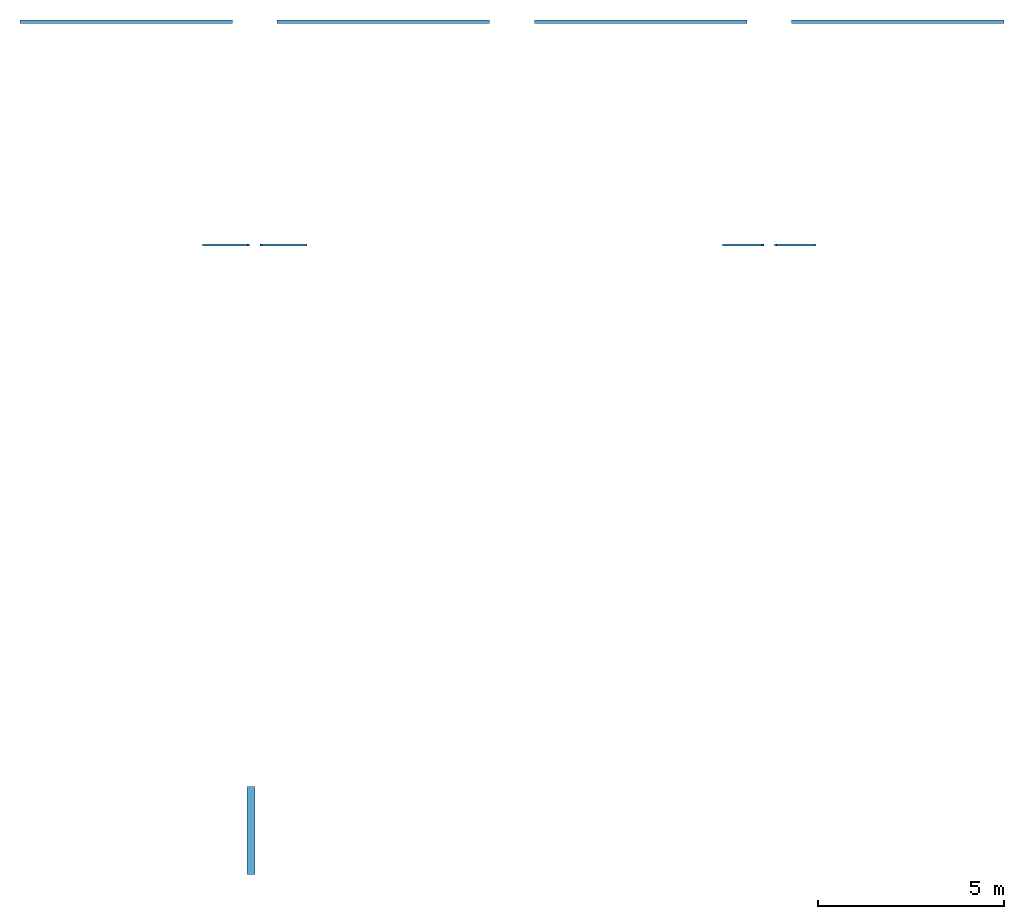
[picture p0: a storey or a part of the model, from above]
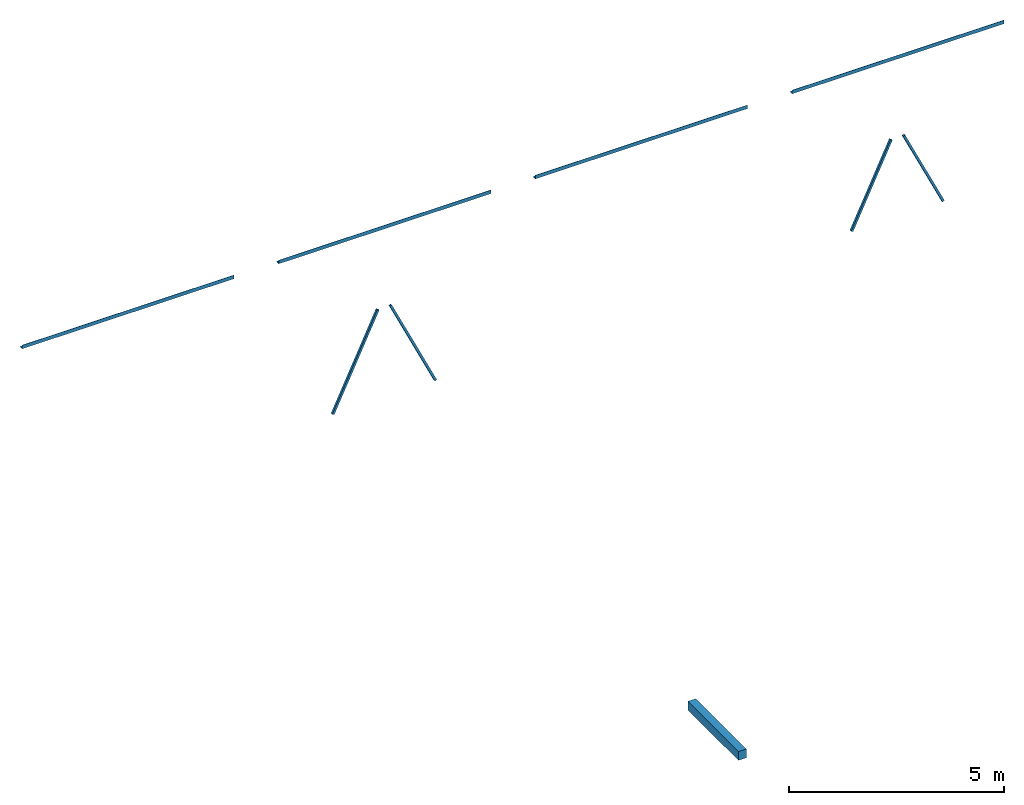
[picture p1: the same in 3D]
Properties of the parts of a building model (IFC2X3), part 1 of 6

# File
Description: ViewDefinition [CoordinationView_V2.0, QuantityTakeOffAddOnView], RevitIdentifiers [VersionGUID: f37ad820-e8d5-4bf8-b316-20b20cab6d81, NumberOfSaves: 258], CoordinateReference [CoordinateBase: Shared Coordinates, ProjectSite: Internal]
File name: 2023.123
Time: 2025-10-08T10:38:46+01:00
Written by: ODA SDAI 22.12
Made in: Autodesk Revit 23.1.60.36 (ENU) - IFC 23.3.0.0

# IfcProject, 2023.123
LongName: n.v.t.

# IfcSite, Default
RefLatitude: 42, 21, 29, 879999; RefLongitude: -71, -3, -37, -79999; RefElevation: 0 mm
Other - Category: Project Information; Client Name: Stichting Spaarnesant; Extensions.Parameters: n.v.t.; Project Address: IKC de zonnewijzer Planetenlaan 9 te Haarlem; Project Issue Date: n.v.t.; Project Name: n.v.t.; Project Number: 2023.123
Text - TemplateVersie: bt_revit_template.rte : 13-10-2023 R2016 ©RB

# IfcBuilding
Pset_BuildingCommon - NumberOfStoreys: 8
Other - Category: Project Information; Client Name: Stichting Spaarnesant; Extensions.Parameters: n.v.t.; Project Address: IKC de zonnewijzer Planetenlaan 9 te Haarlem; Project Issue Date: n.v.t.; Project Name: n.v.t.; Project Number: 2023.123
Text - TemplateVersie: bt_revit_template.rte : 13-10-2023 R2016 ©RB

# IfcBuildingStorey: Level:bt level - maat boven + naam onder (9)
Pset_AirSideSystemInformation - sets with these values: 2
Other - Category: Levels; Family: Level; Family and Type: Level: bt level - maat boven + naam onder; Type: bt level - maat boven + naam onder; Type Id: 551066
Dimensions - Computation Height: 0 mm
Identity Data - Building Story: yes; Structural: no
Other(Type) - Category: Levels; Family Name: Level
Constraints(Type) - Elevation Base: Project Base Point
Graphics(Type) - Color: 16711680; Line Pattern: bt_hoogtelijn; Line Weight: 1; Symbol: bt_hoogtelijnen : Hoogtemaat_Boven + Nivonaam_Onder; Symbol at End 1 Default: no; Symbol at End 2 Default: yes
Identity Data(Type) - Type Name: bt level - maat boven + naam onder
Name | LongName = Pset_AirSideSystemInformation, Name = Identity Data, Name | Elevation (mm) = Constraints, Elevation (mm)
KDV bk ruwe vloer | KDV bk ruwe vloer | -350
F1 begg (bk ruwe vloer) | F1 begg (bk ruwe vloer) | -70
KDV V1 1e verd. (bk ruwe vloer) | KDV V1 1e verd. (bk ruwe vloer) | 2550
V1 1e verd. (bk ruwe vloer) | V1 1e verd. (bk ruwe vloer) | 3730
KDV V2 werkbalken | KDV V2 werkbalken | 5000
V2 2e verd. (bk ruwe vloer) | V2 2e verd. (bk ruwe vloer) | 7530
KDV nok | KDV nok | 9310
V3 dakvloer | V3 dakvloer | 10840
V4 BK metselwerk | V4 BK metselwerk | 11700

# IfcBeam: btl_ihwg - RB 1x afschuining:b300/o200 x 500 (10)
In: F1 begg (bk ruwe vloer)
Type - Other - Category: Structural Framing; Family Name: btl_ihwg - RB 1x afschuining
Type - Dimensions - b boven: 300 mm; b onder: 200 mm; h: 500 mm
Type - Identity Data - Description: vorstrand 300/200 x 500; Model: betonbalk; OmniClass Number: 23.25.30.11.14.14; OmniClass Title: Beams; Type Name: b300/o200 x 500
Type - Materials and Finishes - Structural Material: Concrete - Cast-in-Place - C20/25
Type - Structural - Section Shape: 0
Type - Pset_BeamCommon - IsExternal: no; LoadBearing: yes
Type - Pset_ReinforcementBarPitchOfBeam - Description: vorstrand 300/200 x 500
Material: Concrete - Cast-in-Place - C20/25
BaseQuantities - CrossSectionArea: 125000 mm2
Pset_BeamCommon - Reference: b300/o200 x 500
Pset_QuantityTakeOff - Reference: b300/o200 x 500; sets with these values: 2
Other - Family: btl_ihwg - RB 1x afschuining; Family and Type: btl_ihwg - RB 1x afschuining: b300/o200 x 500; Type: b300/o200 x 500; Type Id: 2097147
Constraints - Cross-Section Rotation: 0 deg; Reference Level: F2 (bk fundering); Reference Level Elevation: -480 mm; Start Level Offset: -200 mm
Identity Data - Has Association: no
Phasing - Phase Created: 2. nieuwbouw
Structural - Rebar Cover - Other Faces: Rebar Cover 1 <25 mm>; Structural Usage: Other
Geometric Position - Join Status: Both joins enabled; y Offset Value: 0 mm; yz Justification: Uniform; z Justification: Top; z Offset Value: 0 mm; y Justification: Center
Name (btl_ihwg - RB 1x afschuining:b300/o200 x 500:...) | BaseQuantities, Length (mm) = Cut Length (mm) | OuterSurfaceArea (mm2) | GrossVolume (m3) | NetVolume (m3) = Volume (m3) | Slope (deg) | Span (mm) = Dimensions, Length (mm) | End Level Offset (mm) | Elevation at Bottom (mm) | Elevation at Top (mm) | Rebar Cover - Bottom Face
2097079 | 3950 | 5964113 | 0.49375 | 0.487917 | 0 | 3650 | -200 | -1180 | -680 | Rebar Cover 1 <25 mm>
2097230 | 1110 | 1675991 | 0.13875 | 0.132083 | 0 | 1160 | -200 | -1180 | -680 | Rebar Cover 1 <25 mm> | Structural - Rebar Cover - Top Face: Rebar Cover 1 <25 mm>
2097357 | 4840 | 7307925 | 0.605 | 0.589157 | 0 | 4840 | -200 | -1180 | -680 | Rebar Cover 1 <25 mm>
2097418 | 3151.69 | 4758749 | 0.393962 | 0.371541 | 0.194885 | 2939.98 | -210
2100637 | 4580 | 6915346 | 0.5725 | 0.5725 | 0 | 4430 | -200 | -1180 | -680 | Rebar Cover 1 <25 mm>
2101210 | 3530 | 5329954 | 0.44125 | 0.42875 | 0 | 3430 | -200 | -1180 | -680 | Rebar Cover 1 <25 mm>
2101342 | 1100 | 1660892 | 0.1375 | 0.1375 | 0 | 1100 | -200 | -1180 | -680 | Rebar Cover 1 <25 mm>
2101343 | 1620 | 2446041 | 0.2025 | 0.19 | 0 | 1520 | -200 | -1180 | -680 | Rebar Cover 1 <25 mm>
2101417 | 5145 | 7768446 | 0.643125 | 0.643125 | 0 | 5145 | -200 | -1180 | -680 | Rebar Cover 1 <25 mm>
2101418 | 950 | 1434407 | 0.11875 | 0.112083 | 0 | 1000 | -200 | -1180 | -680 | Rebar Cover 1 <25 mm>

# IfcBeam: btl_ihwg - RBeam:120x500 (8)
In: F1 begg (bk ruwe vloer)
Type - Other - Category: Structural Framing; Family Name: btl_ihwg - RBeam
Type - Dimensions - b: 120 mm; h: 500 mm
Type - Identity Data - Description: aanstort 120x500; OmniClass Number: 23.25.30.11.14.14; OmniClass Title: Beams; Type Name: 120x500
Type - Materials and Finishes - Structural Material: Concrete - Cast-in-Place - C30/37
Type - Structural - Section Shape: 0
Type - Pset_BeamCommon - IsExternal: no; LoadBearing: yes
Type - Pset_ReinforcementBarPitchOfBeam - Description: aanstort 120x500
Material: Concrete - Cast-in-Place - C30/37
BaseQuantities - CrossSectionArea: 60000 mm2
Pset_BeamCommon - Reference: 120x500
Pset_QuantityTakeOff - Reference: 120x500; sets with these values: 2
Other - Family: btl_ihwg - RBeam; Family and Type: btl_ihwg - RBeam: 120x500; Type: 120x500; Type Id: 2097461
Constraints - Cross-Section Rotation: 0 deg; Reference Level: F2 (bk fundering); Reference Level Elevation: -480 mm; Start Level Offset: -200 mm
Identity Data - Has Association: no
Phasing - Phase Created: 2. nieuwbouw
Structural - Rebar Cover - Other Faces: Rebar Cover 1 <25 mm>; Structural Usage: Other
Geometric Position - Join Status: Both joins enabled; y Offset Value: 0 mm; yz Justification: Uniform; z Justification: Top; z Offset Value: 0 mm; y Justification: Center
Name (btl_ihwg - RBeam:120x500:...) | BaseQuantities, Length (mm) = Cut Length (mm) | OuterSurfaceArea (mm2) | GrossVolume (m3) | NetVolume (m3) = Volume (m3) | Slope (deg) | Span (mm) = Dimensions, Length (mm) | End Level Offset (mm) | Elevation at Bottom (mm) | Elevation at Top (mm) | Rebar Cover - Bottom Face = Rebar Cover - Top Face
2097488 | 6720 | 8332800 | 0.4032 | 0.4032 | 0 | 6660 | -200 | -1180 | -680 | Rebar Cover 1 <25 mm>
2097557 | 5573 | 6910515 | 0.33438 | 0.33438 | 0 | 5573 | -200 | -1180 | -680 | Rebar Cover 1 <25 mm>
2097679 | 300.037 | 372046 | 0.0180022 | 0.0144022 | 0 | 300.037 | -200 | -1180 | -680 | Rebar Cover 1 <25 mm>
2098565 | 590.687 | 732452 | 0.0354412 | 0.0220276 | 1.56079 | 367.141 | -210
2101480 | 5633 | 6984915 | 0.33798 | 0.33798 | 0 | 5573 | -200 | -1180 | -680 | Rebar Cover 1 <25 mm>
2101547 | 1197.33 | 1484687 | 0.0718397 | 0.0718397 | 0 | 1077.33 | -200 | -1180 | -680 | Rebar Cover 1 <25 mm>
2101580 | 1704.99 | 2114193 | 0.1023 | 0.1023 | 0 | 1824.99 | -200 | -1180 | -680 | Rebar Cover 1 <25 mm>
2101653 | 2880 | 3571200 | 0.1728 | 0.1728 | 0 | 2940 | -200 | -1180 | -680 | Rebar Cover 1 <25 mm>

# IfcBeam: btl_ihwg - RBeam:400x700 (3)
In: F1 begg (bk ruwe vloer)
Type - Other - Category: Structural Framing; Family Name: btl_ihwg - RBeam
Type - Dimensions - b: 400 mm; h: 700 mm
Type - Identity Data - Description: betonbalk 400x700; OmniClass Number: 23.25.30.11.14.14; OmniClass Title: Beams; Type Name: 400x700
Type - Materials and Finishes - Structural Material: Beton, ihwg C30/37
Type - Structural - Section Shape: 0
Type - Pset_BeamCommon - IsExternal: no; LoadBearing: yes
Type - Pset_ReinforcementBarPitchOfBeam - Description: betonbalk 400x700
Material: Beton, ihwg C30/37
BaseQuantities - CrossSectionArea: 280000 mm2
Pset_BeamCommon - Slope: 0 deg; Reference: 400x700
Pset_QuantityTakeOff - Reference: 400x700; sets with these values: 2
Other - Family: btl_ihwg - RBeam; Family and Type: btl_ihwg - RBeam: 400x700; Type: 400x700; Type Id: 1999138
Constraints - Cross-Section Rotation: 0 deg; End Level Offset: 0 mm; Orientation: Normal; Reference Level: F2 (bk fundering); Start Level Offset: 0 mm; Reference Level Elevation: -480 mm; Work Plane: Level : F2 (bk fundering)
Dimensions - Elevation at Bottom: -1180 mm; Elevation at Top: -480 mm
Identity Data - Has Association: yes
Phasing - Phase Created: 2. nieuwbouw
Structural - Rebar Cover - Bottom Face: Rebar Cover 1 <25 mm>; Rebar Cover - Other Faces: Rebar Cover 1 <25 mm>; Rebar Cover - Top Face: Rebar Cover 1 <25 mm>; Structural Usage: Other
Geometric Position - y Offset Value: 0 mm; yz Justification: Uniform; z Justification: Top; z Offset Value: 0 mm
Name (btl_ihwg - RBeam:400x700:...) | BaseQuantities, Length (mm) = Cut Length (mm) | OuterSurfaceArea (mm2) | GrossVolume (m3) = NetVolume (m3) = Volume (m3) | Span (mm) = Dimensions, Length (mm) | Join Status | y Justification
1809656 | 8229.67 | 18105278 | 2.30431 | 8779.67 | Both joins enabled | Right
1999243 | 925.022 | 2035048 | 0.259006 | 1568.02 | Both joins enabled | Center
1999358 | 925.022 | 2035048 | 0.259006 | 1475.02 | One or two joins disabled | Center

# IfcBeam: btl_ihwg - RBeam:500x550 (3)
In: F1 begg (bk ruwe vloer)
Type - Other - Category: Structural Framing; Family Name: btl_ihwg - RBeam
Type - Dimensions - b: 500 mm; h: 550 mm
Type - Identity Data - Description: betonbalk 500x550; OmniClass Number: 23.25.30.11.14.14; OmniClass Title: Beams; Type Name: 500x550
Type - Materials and Finishes - Structural Material: Beton, ihwg C30/37
Type - Structural - Section Shape: 0
Type - Pset_BeamCommon - IsExternal: no; LoadBearing: yes
Type - Pset_ReinforcementBarPitchOfBeam - Description: betonbalk 500x550
Material: Beton, ihwg C30/37
BaseQuantities - CrossSectionArea: 275000 mm2
Pset_BeamCommon - Slope: 0 deg; Reference: 500x550
Pset_QuantityTakeOff - Reference: 500x550; sets with these values: 2
Other - Family: btl_ihwg - RBeam; Family and Type: btl_ihwg - RBeam: 500x550; Type: 500x550; Type Id: 1997161
Constraints - Cross-Section Rotation: 0 deg; Reference Level: F2 (bk fundering); End Level Offset: -150 mm; Reference Level Elevation: -480 mm; Start Level Offset: -150 mm
Dimensions - Elevation at Bottom: -1180 mm; Elevation at Top: -630 mm
Identity Data - Has Association: yes
Phasing - Phase Created: 2. nieuwbouw
Structural - Rebar Cover - Bottom Face: Rebar Cover 1 <25 mm>; Rebar Cover - Other Faces: Rebar Cover 1 <25 mm>; Rebar Cover - Top Face: Rebar Cover 1 <25 mm>; Structural Usage: Other
Geometric Position - y Offset Value: 0 mm; yz Justification: Uniform; z Justification: Top; z Offset Value: 0 mm; y Justification: Center
Name (btl_ihwg - RBeam:500x550:...) | BaseQuantities, Length (mm) = Cut Length (mm) | OuterSurfaceArea (mm2) | GrossVolume (m3) = NetVolume (m3) = Volume (m3) | Span (mm) = Dimensions, Length (mm) | Join Status
1624167 | 1000 | 2100000 | 0.275 | 1250 | Both joins enabled
1624201 | 7994.87 | 16789223 | 2.19859 | 7744.87 | One or two joins disabled
1624290 | 1000 | 2100000 | 0.275 | 1250 | Both joins enabled

# IfcBeam: btl_ihwg - RBeam:500x700 (11)
In: F1 begg (bk ruwe vloer)
Type - PredefinedType: BEAM; Material: Beton, ihwg C30/37
Type - Other - Category: Structural Framing; Family Name: btl_ihwg - RBeam
Type - Dimensions - b: 500 mm; h: 700 mm
Type - Identity Data - Description: betonbalk 500x700; OmniClass Number: 23.25.30.11.14.14; OmniClass Title: Beams; Type Name: 500x700
Type - Materials and Finishes - Structural Material: Beton, ihwg C30/37
Type - Structural - Section Shape: 0
Type - Pset_BeamCommon - IsExternal: no; LoadBearing: yes
Type - Pset_ReinforcementBarPitchOfBeam - Description: betonbalk 500x700
Pset_BeamCommon - Slope: 0 deg; Reference: 500x700
Pset_QuantityTakeOff - Reference: 500x700; sets with these values: 2
BaseQuantities - CrossSectionArea: 350000 mm2
Other - Family: btl_ihwg - RBeam; Family and Type: btl_ihwg - RBeam: 500x700; Type: 500x700; Type Id: 1541042
Constraints - Cross-Section Rotation: 0 deg; End Level Offset: 0 mm; Orientation: Normal; Reference Level: F2 (bk fundering); Start Level Offset: 0 mm; Reference Level Elevation: -480 mm; Work Plane: Level : F2 (bk fundering)
Dimensions - Elevation at Bottom: -1180 mm; Elevation at Top: -480 mm
Identity Data - Has Association: yes
Phasing - Phase Created: 2. nieuwbouw
Structural - Rebar Cover - Bottom Face: Rebar Cover 1 <25 mm>; Rebar Cover - Other Faces: Rebar Cover 1 <25 mm>; Rebar Cover - Top Face: Rebar Cover 1 <25 mm>; Structural Usage: Other
Geometric Position - y Offset Value: 0 mm; yz Justification: Uniform; z Justification: Top; z Offset Value: 0 mm
Name (btl_ihwg - RBeam:500x700:...) | Span (mm) = Dimensions, Length (mm) | BaseQuantities, Length (mm) | OuterSurfaceArea (mm2) | GrossVolume (m3) | NetVolume (m3) = Volume (m3) | Cut Length (mm) | Join Status | y Justification
1538251 | 23120 | 23120 | 11339998 | 1.65375 | 6.3595 | 22570 | One or two joins disabled | Center | BaseQuantities - Height: 500 mm; Width: 700 mm; GrossSurfaceArea: 12039998 mm2
1538264 | 22290 | 22200 | 53279962 | 7.76999 | 7.76999 | 22200 | Both joins enabled | Center
1538460 | 6600.78 | 6350 | 15240000 | 2.2225 | 2.2225 | 6350 | Both joins enabled | Center
1538551 | 6600.78 | 6350 | 15240000 | 2.2225 | 2.2225 | 6350 | Both joins enabled | Center
1538684 | 33873.3 | 33873.3 | 73615900 | 10.7357 | 11.6457 | 33873.3 | Both joins enabled | Center | BaseQuantities - Height: 500 mm; Width: 700 mm; GrossSurfaceArea: 74315900 mm2
1538778 | 6000 | 5150 | 12360000 | 1.8025 | 1.8025 | 5150 | Both joins enabled | Center
1538880 | 6000 | 5150 | 12360000 | 1.8025 | 1.8025 | 5150 | Both joins enabled | Center
1538898 | 6000 | 5150 | 12360000 | 1.8025 | 1.8025 | 5150 | Both joins enabled | Center
1538918 | 11500 | 11500 | 12360000 | 1.8025 | 3.62495 | 10857 | Both joins enabled | Center | BaseQuantities - Height: 700 mm; Width: 500 mm; GrossSurfaceArea: 13060000 mm2
1647018 | 6690.33 | 6900.33 | 16560783 | 2.41511 | 2.41511 | 6900.33 | Both joins enabled | Center
1921198 | 22345 | 22345 | 15240296 | 2.22254 | 6.08824 | 21795 | Both joins enabled | Right | BaseQuantities - Height: 500 mm; Width: 700 mm; GrossSurfaceArea: 15940296 mm2

# IfcBeam: btl_ihwg - RBeam:550x700 (8)
In: F1 begg (bk ruwe vloer)
Type - Other - Category: Structural Framing; Family Name: btl_ihwg - RBeam
Type - Dimensions - b: 550 mm; h: 700 mm
Type - Identity Data - Description: betonbalk 550x700; OmniClass Number: 23.25.30.11.14.14; OmniClass Title: Beams; Type Name: 550x700
Type - Materials and Finishes - Structural Material: Concrete - Cast-in-Place - C30/37
Type - Structural - Section Shape: 0
Type - Pset_BeamCommon - IsExternal: no; LoadBearing: yes
Type - Pset_ReinforcementBarPitchOfBeam - Description: betonbalk 550x700
Material: Concrete - Cast-in-Place - C30/37
Pset_BeamCommon - Slope: 0 deg; Reference: 550x700
Pset_QuantityTakeOff - Reference: 550x700; sets with these values: 2
Other - Family: btl_ihwg - RBeam; Family and Type: btl_ihwg - RBeam: 550x700; Type: 550x700; Type Id: 1782740
Constraints - Cross-Section Rotation: 0 deg; End Level Offset: 0 mm; Orientation: Normal; Reference Level: F2 (bk fundering); Start Level Offset: 0 mm; Reference Level Elevation: -480 mm; Work Plane: Level : F2 (bk fundering)
Dimensions - Elevation at Bottom: -1180 mm; Elevation at Top: -480 mm
Identity Data - Has Association: yes
Phasing - Phase Created: 2. nieuwbouw
Structural - Rebar Cover - Bottom Face: Rebar Cover 1 <25 mm>; Rebar Cover - Other Faces: Rebar Cover 1 <25 mm>; Rebar Cover - Top Face: Rebar Cover 1 <25 mm>; Structural Usage: Other
Geometric Position - y Offset Value: 0 mm; yz Justification: Uniform; z Justification: Top; z Offset Value: 0 mm
Name (btl_ihwg - RBeam:550x700:...) | CrossSectionArea (mm2) | NetVolume (m3) = Volume (m3) | Span (mm) = Dimensions, Length (mm) | Cut Length (mm) | Join Status | y Justification
1537750 | 385000 | 8.701 | 23200 | 22600 | Both joins enabled | Right | BaseQuantities - Length: 22600 mm; OuterSurfaceArea: 56500000 mm2; GrossVolume: 8.701 m3
1538102 | 7838967 | 2.23222 | 5942.97 | 6092.97 | One or two joins disabled | Right
1538182 | 385000 | 8.54699 | 22357 | 22200 | Both joins enabled | Center | BaseQuantities - Length: 22200 mm; OuterSurfaceArea: 55499961 mm2; GrossVolume: 8.54699 m3
1544843 | 27829474 | 8.43114 | 23200 | 22000 | One or two joins disabled | Right
1549963 | 7751211 | 2.24429 | 6342.97 | 5942.97 | Both joins enabled | Right
1651979 | 11865913 | 3.46478 | 9807 | 9157 | Both joins enabled | Right
1797548 | 385000 | 0.6545 | 2300 | 1700 | Both joins enabled | Left | BaseQuantities - Length: 1700 mm; OuterSurfaceArea: 4250000 mm2; GrossVolume: 0.6545 m3
1809711 | 385000 | 1.155 | 3000 | 3000 | Both joins enabled | Right | BaseQuantities - Length: 3000 mm; OuterSurfaceArea: 7500000 mm2; GrossVolume: 1.155 m3

# IfcBeam: btl_ihwg - RBeam:600x700 (5)
In: F1 begg (bk ruwe vloer)
Type - Other - Category: Structural Framing; Family Name: btl_ihwg - RBeam
Type - Dimensions - b: 600 mm; h: 700 mm
Type - Identity Data - Description: betonbalk 600x700; OmniClass Number: 23.25.30.11.14.14; OmniClass Title: Beams; Type Name: 600x700
Type - Materials and Finishes - Structural Material: Beton, ihwg C30/37
Type - Structural - Section Shape: 0
Type - Pset_BeamCommon - IsExternal: no; LoadBearing: yes
Type - Pset_ReinforcementBarPitchOfBeam - Description: betonbalk 600x700
Material: Beton, ihwg C30/37
Pset_BeamCommon - Reference: 600x700; Slope: 0 deg
Pset_QuantityTakeOff - Reference: 600x700; sets with these values: 2
Other - Family: btl_ihwg - RBeam; Family and Type: btl_ihwg - RBeam: 600x700; Type: 600x700; Type Id: 1537239
Constraints - Cross-Section Rotation: 0 deg; End Level Offset: 0 mm; Orientation: Normal; Reference Level: F2 (bk fundering); Reference Level Elevation: -480 mm; Start Level Offset: 0 mm; Work Plane: Level : F2 (bk fundering)
Dimensions - Elevation at Bottom: -1180 mm; Elevation at Top: -480 mm
Identity Data - Has Association: yes
Phasing - Phase Created: 2. nieuwbouw
Structural - Rebar Cover - Bottom Face: Rebar Cover 1 <25 mm>; Rebar Cover - Other Faces: Rebar Cover 1 <25 mm>; Rebar Cover - Top Face: Rebar Cover 1 <25 mm>; Structural Usage: Other
Geometric Position - y Offset Value: 0 mm; yz Justification: Uniform; z Justification: Top; z Offset Value: 0 mm
Name (btl_ihwg - RBeam:600x700:...) | CrossSectionArea (mm2) | NetVolume (m3) = Volume (m3) | Span (mm) = Dimensions, Length (mm) | Cut Length (mm) | Join Status | y Justification | BaseQuantities, Length (mm) | OuterSurfaceArea (mm2) | GrossVolume (m3)
1537459 | 30727980 | 9.65549 | 23300 | 23300 | Both joins enabled | Right
1538010 | 420000 | 4.81194 | 12107 | 11457 | Both joins enabled | Right | 11457 | 29788200 | 4.81194
1538033 | 420000 | 13.041 | 31650 | 31050 | Both joins enabled | Right | 31050 | 80729940 | 13.041
1546720 | 1182248 | 0.172905 | 736.059 | 736.059 | One or two joins disabled | Center
1809774 | 420000 | 1.26 | 3439.46 | 3000 | Both joins enabled | Right | 3000 | 7800000 | 1.26

# IfcBeam: btl_ihwg - RBeam:650x700 (2)
In: F1 begg (bk ruwe vloer)
Type - Other - Category: Structural Framing; Family Name: btl_ihwg - RBeam
Type - Dimensions - b: 650 mm; h: 700 mm
Type - Identity Data - Description: betonbalk 650x700; OmniClass Number: 23.25.30.11.14.14; OmniClass Title: Beams; Type Name: 650x700
Type - Materials and Finishes - Structural Material: Concrete - Cast-in-Place - C30/37
Type - Structural - Section Shape: 0
Type - Pset_BeamCommon - IsExternal: no; LoadBearing: yes
Type - Pset_ReinforcementBarPitchOfBeam - Description: betonbalk 650x700
Material: Concrete - Cast-in-Place - C30/37
BaseQuantities - CrossSectionArea: 455000 mm2
Pset_BeamCommon - Slope: 0 deg; Reference: 650x700
Pset_QuantityTakeOff - Reference: 650x700; sets with these values: 2
Other - Family: btl_ihwg - RBeam; Family and Type: btl_ihwg - RBeam: 650x700; Type: 650x700; Type Id: 1921500
Constraints - Cross-Section Rotation: 0 deg; End Level Offset: 0 mm; Orientation: Normal; Reference Level: F2 (bk fundering); Start Level Offset: 0 mm; Reference Level Elevation: -480 mm; Work Plane: Level : F2 (bk fundering)
Dimensions - Elevation at Bottom: -1180 mm; Elevation at Top: -480 mm
Identity Data - Has Association: yes
Phasing - Phase Created: 2. nieuwbouw
Structural - Rebar Cover - Bottom Face: Rebar Cover 1 <25 mm>; Rebar Cover - Other Faces: Rebar Cover 1 <25 mm>; Rebar Cover - Top Face: Rebar Cover 1 <25 mm>; Structural Usage: Other
Geometric Position - Join Status: Both joins enabled; y Justification: Right; y Offset Value: 0 mm; yz Justification: Uniform; z Justification: Top; z Offset Value: 0 mm
Name (btl_ihwg - RBeam:650x700:...) | BaseQuantities, Length (mm) = Cut Length (mm) | OuterSurfaceArea (mm2) | GrossVolume (m3) = NetVolume (m3) = Volume (m3) | Span (mm) = Dimensions, Length (mm)
1538075 | 7480 | 20196000 | 3.4034 | 7480
1921470 | 2374.99 | 6412486 | 1.08062 | 1824.99

# IfcBeam: btl_prefab - RBeam:214x250, btl_prefab - RBeam:214x250:1646126
In: KDV nok
Type - Other - Category: Structural Framing; Family Name: btl_prefab - RBeam
Type - Dimensions - b: 214 mm; h: 250 mm
Type - Identity Data - Description: prefab betonbalk 214x250; Model: ligger; OmniClass Number: 23.25.30.11.14.14; OmniClass Title: Beams; Type Name: 214x250
Type - Materials and Finishes - Structural Material: Beton, prefab
Type - Structural - Section Shape: 0
Type - Pset_BeamCommon - IsExternal: no; LoadBearing: yes
Type - Pset_ReinforcementBarPitchOfBeam - Description: prefab betonbalk 214x250
Material: Beton, prefab
BaseQuantities - Length: 2360.09 mm; CrossSectionArea: 53500 mm2; OuterSurfaceArea: 2190159 mm2; GrossVolume: 0.126265 m3; NetVolume: 0.126265 m3
Pset_BeamCommon - Slope: 0 deg; Reference: 214x250; Span: 1760.09 mm
Pset_QuantityTakeOff - Reference: 214x250; sets with these values: 2
Other - Family: btl_prefab - RBeam; End Extension Calculation: 3000 mm; Family and Type: btl_prefab - RBeam: 214x250; Start Extension Calculation: 3000 mm; Type: 214x250; Type Id: 1936622
Constraints - Cross-Section Rotation: 0 deg; End Level Offset: 177.992 mm; Reference Level: V3 ok vloer; Reference Level Elevation: 10380 mm; Start Level Offset: 177.992 mm
Construction - End Extension: -12.5 mm; Start Extension: -12.5 mm
Dimensions - Elevation at Bottom: 10308 mm; Elevation at Top: 10558 mm; Length: 1760.09 mm; Volume: 0.126265 m3
Identity Data - Has Association: yes
Phasing - Phase Created: 2. nieuwbouw
Structural - Rebar Cover - Bottom Face: Rebar Cover 1 <25 mm>; Rebar Cover - Other Faces: Rebar Cover 1 <25 mm>; Rebar Cover - Top Face: Rebar Cover 1 <25 mm>; Structural Usage: Other; Cut Length: 2360.09 mm
Geometric Position - y Offset Value: 0 mm; yz Justification: Uniform; z Justification: Top; z Offset Value: 0 mm; Join Status: One or two joins disabled; y Justification: Origin; End Extension: 300 mm; Start Extension: 300 mm

# IfcBeam: btl_prefab - RBeam:214x572 (6)
In: V1 1e verd. (bk ruwe vloer)
Type - Other - Category: Structural Framing; Family Name: btl_prefab - RBeam
Type - Dimensions - b: 214 mm; h: 572 mm
Type - Identity Data - Description: prefab betonbalk 214x572; Model: ligger; OmniClass Number: 23.25.30.11.14.14; OmniClass Title: Beams; Type Name: 214x572
Type - Materials and Finishes - Structural Material: Beton, prefab
Type - Structural - Section Shape: 0
Type - Pset_BeamCommon - IsExternal: no; LoadBearing: yes
Type - Pset_ReinforcementBarPitchOfBeam - Description: prefab betonbalk 214x572
Material: Beton, prefab
BaseQuantities - CrossSectionArea: 122408 mm2
Pset_BeamCommon - Slope: 0 deg; Reference: 214x572
Pset_QuantityTakeOff - Reference: 214x572; sets with these values: 2
Other - Family: btl_prefab - RBeam; End Extension Calculation: 3000 mm; Family and Type: btl_prefab - RBeam: 214x572; Start Extension Calculation: 3000 mm; Type: 214x572; Type Id: 1860793
Constraints - Cross-Section Rotation: 0 deg; Reference Level: V1 1e verd. (bk ruwe vloer); End Level Offset: -450 mm; Reference Level Elevation: 3730 mm; Start Level Offset: -450 mm
Construction - End Extension: -12.5 mm; Start Extension: -12.5 mm
Dimensions - Elevation at Bottom: 2708 mm; Elevation at Top: 3280 mm
Identity Data - Has Association: yes
Phasing - Phase Created: 2. nieuwbouw
Structural - Rebar Cover - Bottom Face: Rebar Cover 1 <25 mm>; Rebar Cover - Other Faces: Rebar Cover 1 <25 mm>; Rebar Cover - Top Face: Rebar Cover 1 <25 mm>; Structural Usage: Other
Geometric Position - y Offset Value: 0 mm; yz Justification: Uniform; z Justification: Top; z Offset Value: 0 mm; Join Status: One or two joins disabled; y Justification: Origin
Name (btl_prefab - RBeam:214x572:...) | BaseQuantities, Length (mm) = Cut Length (mm) | OuterSurfaceArea (mm2) | GrossVolume (m3) = NetVolume (m3) = Volume (m3) | Span (mm) = Dimensions, Length (mm) | End Extension (mm) | Start Extension (mm)
1630832 | 6638.79 | 10436184 | 0.812641 | 6348.79 | -10 | 300
1631125 | 6547 | 10291884 | 0.801405 | 6257 | 300 | -10
1632395 | 6301.08 | 9905302 | 0.771303 | 5701.08 | 300 | 300
1632859 | 6300.3 | 9904074 | 0.771207 | 5700.3 | 300 | 300
1633035 | 6300.28 | 9904037 | 0.771204 | 5700.28 | 300 | 300
1633200 | 6300.28 | 9904037 | 0.771204 | 5700.28 | 300 | 300

# IfcBeam: btl_prefab - RBeam:214x762 (15)
Type - Other - Category: Structural Framing; Family Name: btl_prefab - RBeam
Type - Dimensions - b: 214 mm; h: 762 mm
Type - Identity Data - Description: prefab betonbalk 214x ca.762; Model: ligger; OmniClass Number: 23.25.30.11.14.14; OmniClass Title: Beams; Type Name: 214x762
Type - Materials and Finishes - Structural Material: Beton, prefab
Type - Structural - Section Shape: 0
Type - Pset_BeamCommon - IsExternal: no; LoadBearing: yes
Type - Pset_ReinforcementBarPitchOfBeam - Description: prefab betonbalk 214x ca.762
Material: Beton, prefab
BaseQuantities - CrossSectionArea: 163068 mm2
Pset_BeamCommon - Slope: 0 deg; Reference: 214x762
Pset_QuantityTakeOff - Reference: 214x762; sets with these values: 2
Other - End Extension Calculation: 3000 mm; Family: btl_prefab - RBeam; Family and Type: btl_prefab - RBeam: 214x762; Start Extension Calculation: 3000 mm; Type: 214x762; Type Id: 1860184
Constraints - Cross-Section Rotation: 0 deg; End Level Offset: 0 mm; Start Level Offset: 0 mm
Construction - End Extension: -12.5 mm; Start Extension: -12.5 mm
Identity Data - Has Association: yes
Phasing - Phase Created: 2. nieuwbouw
Structural - Rebar Cover - Bottom Face: Rebar Cover 1 <25 mm>; Rebar Cover - Other Faces: Rebar Cover 1 <25 mm>; Rebar Cover - Top Face: Rebar Cover 1 <25 mm>; Structural Usage: Other
Geometric Position - y Offset Value: 0 mm; yz Justification: Uniform; z Justification: Top; z Offset Value: 0 mm; y Justification: Origin
Name (btl_prefab - RBeam:214x762:...) | In | BaseQuantities, Length (mm) = Cut Length (mm) | OuterSurfaceArea (mm2) | GrossVolume (m3) = NetVolume (m3) = Volume (m3) | Span (mm) = Dimensions, Length (mm) | Reference Level | Reference Level Elevation (mm) = Elevation at Top (mm) | Elevation at Bottom (mm) | Join Status | End Extension (mm) | Start Extension (mm)
1630391 | KDV V1 1e verd. (bk ruwe vloer) | 4704.2 | 9182599 | 0.767105 | 4104.2 | V1 ok vloer | 3470 | 2708 | One or two joins disabled | 300 | 300
1630645 | KDV V1 1e verd. (bk ruwe vloer) | 2360.09 | 4606887 | 0.384854 | 1760.09 | V1 ok vloer | 3470 | 2708 | One or two joins disabled | 300 | 300
1633378 | KDV V1 1e verd. (bk ruwe vloer) | 6300.28 | 12298143 | 1.02737 | 5700.28 | V1 ok vloer | 3470 | 2708 | One or two joins disabled | 300 | 300
1635602 | KDV V1 1e verd. (bk ruwe vloer) | 5160 | 10072313 | 0.84143 | 4560 | V1 ok vloer | 3470 | 2708 | Both joins enabled | 300 | 300
1635963 | KDV V1 1e verd. (bk ruwe vloer) | 7019 | 13701090 | 1.14457 | 7039 | V1 ok vloer | 3470 | 2708 | One or two joins disabled | -10 | -10
1636031 | KDV V1 1e verd. (bk ruwe vloer) | 6880 | 13429760 | 1.12191 | 6900 | V1 ok vloer | 3470 | 2708 | One or two joins disabled | -10 | -10
1636110 | KDV V1 1e verd. (bk ruwe vloer) | 6879.98 | 13429729 | 1.12191 | 6899.98 | V1 ok vloer | 3470 | 2708 | One or two joins disabled | -10 | -10
1636127 | KDV V1 1e verd. (bk ruwe vloer) | 6760.73 | 13196939 | 1.10246 | 6770.73 | V1 ok vloer | 3470 | 2708 | One or two joins disabled | 0 | -10
1636601 | KDV V2 werkbalken | 5160 | 10072313 | 0.84143 | 4560 | V2 ok vloer | 7270 | 6508 | Both joins enabled | 300 | 300
1636864 | KDV V2 werkbalken | 7019 | 13701090 | 1.14457 | 7039 | V2 ok vloer | 7270 | 6508 | One or two joins disabled | -10 | -10
1636866 | KDV V2 werkbalken | 6880 | 13429760 | 1.12191 | 6900 | V2 ok vloer | 7270 | 6508 | One or two joins disabled | -10 | -10
1636868 | KDV V2 werkbalken | 6879.98 | 13429729 | 1.12191 | 6899.98 | V2 ok vloer | 7270 | 6508 | One or two joins disabled | -10 | -10
1636870 | KDV V2 werkbalken | 6760.73 | 13196939 | 1.10246 | 6890.43 | V2 ok vloer | 7270 | 6508 | One or two joins disabled | 0 | -10 | Geometric Position - End Join Cutback: 12.7 mm
1645918 | KDV V2 werkbalken | 2360.09 | 4606887 | 0.384854 | 1760.09 | V2 ok vloer | 7270 | 6508 | One or two joins disabled | 300 | 300
1665288 | KDV V1 1e verd. (bk ruwe vloer) | 4704.2 | 9182599 | 0.767105 | 4104.2 | V1 ok vloer | 3470 | 2708 | One or two joins disabled | 300 | 300

# IfcBeam: btl_prefab - RBeam:214x850 (3)
In: KDV V1 1e verd. (bk ruwe vloer)
Type - Other - Category: Structural Framing; Family Name: btl_prefab - RBeam
Type - Dimensions - b: 214 mm; h: 850 mm
Type - Identity Data - Description: prefab betonbalk 214x ca.850; Model: ligger; OmniClass Number: 23.25.30.11.14.14; OmniClass Title: Beams; Type Name: 214x850
Type - Materials and Finishes - Structural Material: Beton, prefab
Type - Structural - Section Shape: 0
Type - Pset_BeamCommon - IsExternal: no; LoadBearing: yes
Type - Pset_ReinforcementBarPitchOfBeam - Description: prefab betonbalk 214x ca.850
Material: Beton, prefab
BaseQuantities - CrossSectionArea: 181900 mm2
Pset_BeamCommon - Slope: 0 deg; Reference: 214x850
Pset_QuantityTakeOff - Reference: 214x850; sets with these values: 2
Other - Family: btl_prefab - RBeam; End Extension Calculation: 3000 mm; Family and Type: btl_prefab - RBeam: 214x850; Start Extension Calculation: 3000 mm; Type: 214x850; Type Id: 2062221
Constraints - Cross-Section Rotation: 0 deg; Reference Level: V1 ok vloer; End Level Offset: -190 mm; Reference Level Elevation: 3470 mm; Start Level Offset: -190 mm
Construction - End Extension: -12.5 mm; Start Extension: -12.5 mm
Dimensions - Elevation at Bottom: 2430 mm; Elevation at Top: 3280 mm
Identity Data - Has Association: no
Phasing - Phase Created: 2. nieuwbouw
Structural - Rebar Cover - Bottom Face: Rebar Cover 1 <25 mm>; Rebar Cover - Other Faces: Rebar Cover 1 <25 mm>; Rebar Cover - Top Face: Rebar Cover 1 <25 mm>; Structural Usage: Other
Geometric Position - Join Status: Both joins enabled; y Offset Value: 0 mm; yz Justification: Uniform; z Justification: Top; z Offset Value: 0 mm; y Justification: Origin; End Extension: 200 mm; Start Extension: 200 mm
Name (btl_prefab - RBeam:214x850:...) | BaseQuantities, Length (mm) = Cut Length (mm) | OuterSurfaceArea (mm2) | GrossVolume (m3) = NetVolume (m3) = Volume (m3) | Span (mm) = Dimensions, Length (mm)
2062927 | 2655 | 5649840 | 0.482945 | 2255
2064152 | 4040 | 8597120 | 0.734876 | 3640
2064205 | 2660 | 5660480 | 0.483854 | 2260

# IfcBeam: btl_prefab - RBeam:214x880 (4)
In: V4 BK metselwerk
Type - Other - Category: Structural Framing; Family Name: btl_prefab - RBeam
Type - Dimensions - b: 214 mm; h: 880 mm
Type - Identity Data - Description: prefab betonbalk 214x880; Model: ligger; OmniClass Number: 23.25.30.11.14.14; OmniClass Title: Beams; Type Name: 214x880
Type - Materials and Finishes - Structural Material: Beton, prefab
Type - Structural - Section Shape: 0
Type - Pset_BeamCommon - IsExternal: no; LoadBearing: yes
Type - Pset_ReinforcementBarPitchOfBeam - Description: prefab betonbalk 214x880
Material: Beton, prefab
BaseQuantities - CrossSectionArea: 188320 mm2
Pset_BeamCommon - Slope: 0 deg; Reference: 214x880
Pset_QuantityTakeOff - Reference: 214x880; sets with these values: 2
Other - Family: btl_prefab - RBeam; End Extension Calculation: 3000 mm; Family and Type: btl_prefab - RBeam: 214x880; Start Extension Calculation: 3000 mm; Type: 214x880; Type Id: 2016995
Constraints - Cross-Section Rotation: 0 deg; Reference Level: V4 BK metselwerk; End Level Offset: -512 mm; Reference Level Elevation: 11700 mm; Start Level Offset: -512 mm
Construction - End Extension: -12.5 mm; Start Extension: -12.5 mm
Dimensions - Elevation at Bottom: 10308 mm; Elevation at Top: 11188 mm
Identity Data - Has Association: yes
Phasing - Phase Created: 2. nieuwbouw
Structural - Rebar Cover - Bottom Face: Rebar Cover 1 <25 mm>; Rebar Cover - Other Faces: Rebar Cover 1 <25 mm>; Rebar Cover - Top Face: Rebar Cover 1 <25 mm>; Structural Usage: Other
Geometric Position - y Offset Value: 0 mm; yz Justification: Uniform; z Justification: Top; z Offset Value: 0 mm; y Justification: Origin; End Extension: 590 mm
Name (btl_prefab - RBeam:214x880:...) | BaseQuantities, Length (mm) = Cut Length (mm) | OuterSurfaceArea (mm2) | GrossVolume (m3) = NetVolume (m3) = Volume (m3) | Span (mm) = Dimensions, Length (mm) | Join Status | Start Extension (mm)
1696130 | 7029.43 | 15380400 | 1.32378 | 6439.43 | One or two joins disabled | 0
1760935 | 6880 | 15053442 | 1.29564 | 5700 | Both joins enabled | 590
1760958 | 6879.98 | 15053407 | 1.29564 | 5699.98 | Both joins enabled | 590
1760980 | 6880 | 15053431 | 1.29564 | 5700 | Both joins enabled | 590

# IfcBeam: btl_staal - HE(a-b-m):HEA100 (16)
In: V3 dakvloer
Type - Other - Category: Structural Framing; Family Name: btl_staal - HE(a-b-m)
Type - Dimensions - bf: 100 mm; d: 96 mm; k: 20 mm; kr: 12 mm; tf: 8 mm; tw: 5 mm
Type - Identity Data - Description: HEA100; Model: ligger; Type Name: HEA100
Type - Materials and Finishes - Structural Material: Metal - Steel - S235 JRG2 (standaard)
Type - Structural - Section Shape: 0; A: 2124 mm2; W: 0.163477
Type - Pset_BeamCommon - IsExternal: no; LoadBearing: yes
Type - Pset_ReinforcementBarPitchOfBeam - Description: HEA100
Material: Metal - Steel - S235 JRG2 (standaard)
BaseQuantities - CrossSectionArea: 2000 mm2
Pset_BeamCommon - Slope: 0 deg; Reference: HEA100
Pset_QuantityTakeOff - Reference: HEA100; sets with these values: 2
Other - Family: btl_staal - HE(a-b-m); End Extension Calculation: 3000 mm; Family and Type: btl_staal - HE(a-b-m): HEA100; Start Extension Calculation: 3000 mm; Type: HEA100; Type Id: 1712342
Constraints - Cross-Section Rotation: 0 deg; Reference Level: V3 dakvloer; End Level Offset: -4.04687 mm; Reference Level Elevation: 10840 mm; Start Level Offset: -4.04687 mm
Construction - EindOplegging: -12.5 mm; StartOplegging: -12.5 mm
Dimensions - Elevation at Bottom: 10740 mm; Elevation at Top: 10836 mm
Identity Data - Has Association: no
Phasing - Phase Created: 2. nieuwbouw
Structural - Structural Usage: Other; Stick Symbol Location: Center of Geometry
Geometric Position - y Offset Value: 0 mm; yz Justification: Uniform; z Justification: Top; z Offset Value: 0 mm; y Justification: Origin; End Extension: 0 mm; Start Extension: 0 mm
Name (btl_staal - HE(a-b-m):HEA100:...) | BaseQuantities, Length (mm) = Cut Length (mm) | OuterSurfaceArea (mm2) | GrossVolume (m3) = NetVolume (m3) = Volume (m3) | Span (mm) = Dimensions, Length (mm) | Join Status | Group
2013470 | 3595.5 | 2092581 | 0.007191 | 3595.5 | One or two joins disabled | Model Group:Spant 4:2013463
2013471 | 3439.12 | 2001568 | 0.00687824 | 3439.12 | One or two joins disabled | Model Group:Spant 4:2013463
2013472 | 3375 | 1964250 | 0.00675 | 3375 | Both joins enabled | Model Group:Spant 4:2013463
2013473 | 3400 | 1978800 | 0.0068 | 3400 | Both joins enabled | Model Group:Spant 4:2013463
2013481 | 3515.5 | 2046021 | 0.007031 | 3595.5 | One or two joins disabled | Model Group:Spant 4:2013474 | Geometric Position - End Join Cutback: 0 mm
2013482 | 3439.12 | 2001568 | 0.00687824 | 3439.12 | One or two joins disabled | Model Group:Spant 4:2013474
2013483 | 3375 | 1964250 | 0.00675 | 3375 | Both joins enabled | Model Group:Spant 4:2013474
2013484 | 3400 | 1978800 | 0.0068 | 3400 | Both joins enabled | Model Group:Spant 4:2013474
2013492 | 3595.5 | 2092581 | 0.007191 | 3595.5 | One or two joins disabled | Model Group:Spant 4:2013485
2013493 | 3439.12 | 2001568 | 0.00687824 | 3439.12 | One or two joins disabled | Model Group:Spant 4:2013485
2013494 | 3375 | 1964250 | 0.00675 | 3375 | Both joins enabled | Model Group:Spant 4:2013485
2013495 | 3400 | 1978800 | 0.0068 | 3400 | Both joins enabled | Model Group:Spant 4:2013485
2013503 | 3595.5 | 2092581 | 0.007191 | 3595.5 | One or two joins disabled | Model Group:Spant 4:2013496
2013504 | 3439.12 | 2001568 | 0.00687824 | 3439.12 | One or two joins disabled | Model Group:Spant 4:2013496
2013505 | 3375 | 1964250 | 0.00675 | 3375 | Both joins enabled | Model Group:Spant 4:2013496
2013506 | 3400 | 1978800 | 0.0068 | 3400 | Both joins enabled | Model Group:Spant 4:2013496

# IfcBeam: btl_staal - HE(a-b-m):HEA120 (5)
In: V1 1e verd. (bk ruwe vloer)
Type - Other - Category: Structural Framing; Family Name: btl_staal - HE(a-b-m)
Type - Dimensions - bf: 120 mm; d: 114 mm; k: 20 mm; kr: 12 mm; tf: 8 mm; tw: 5 mm
Type - Identity Data - Description: HEA120; Model: ligger; Type Name: HEA120
Type - Materials and Finishes - Structural Material: Metal - Steel - S235 JRG2 (standaard)
Type - Structural - Section Shape: 0; A: 2534 mm2; W: 0.195054
Type - Pset_BeamCommon - IsExternal: no; LoadBearing: yes
Type - Pset_ReinforcementBarPitchOfBeam - Description: HEA120
Material: Metal - Steel - S235 JRG2 (standaard)
BaseQuantities - Length: 2248.22 mm; CrossSectionArea: 2410 mm2; OuterSurfaceArea: 1569261 mm2; GrossVolume: 0.00541822 m3; NetVolume: 0.00541822 m3
Pset_BeamCommon - Slope: 0 deg; Reference: HEA120
Pset_QuantityTakeOff - Reference: HEA120; sets with these values: 2
Other - Family: btl_staal - HE(a-b-m); End Extension Calculation: 3000 mm; Family and Type: btl_staal - HE(a-b-m): HEA120; Start Extension Calculation: 3000 mm; Type: HEA120; Type Id: 1807569
Constraints - Cross-Section Rotation: 0 deg
Construction - EindOplegging: -12.5 mm; StartOplegging: -12.5 mm
Dimensions - Volume: 0.00541822 m3
Identity Data - Has Association: yes
Phasing - Phase Created: 2. nieuwbouw
Structural - Structural Usage: Other; Stick Symbol Location: Center of Geometry; Start Attachment Type: End Elevation; End Attachment Type: End Elevation; Cut Length: 2248.22 mm
Geometric Position - Join Status: Both joins enabled; y Offset Value: 0 mm; yz Justification: Uniform; z Justification: Top; z Offset Value: 0 mm; y Justification: Origin; End Extension: 0 mm; Start Extension: 0 mm; End Join Cutback: 12.7 mm; Start Join Cutback: 12.7 mm
Name (btl_staal - HE(a-b-m):HEA120:...) | Span (mm) = Length (mm) | Reference Level | End Level Offset (mm) = Start Level Offset (mm) | Reference Level Elevation (mm) | Elevation at Bottom (mm) | Elevation at Top (mm)
1657248 | 2347.12 | V1 1e verd. (bk ruwe vloer) | -1980 | 3730 | 1636 | 1750
1807791 | 2347.12 | 03800 V1 1e verd | 787.75 | 3800 | 4473.75 | 4587.75
1807877 | 2413.62 | V1 1e verd. (bk ruwe vloer) | -1980 | 3730 | 1636 | 1750
1807899 | 2342.88 | V1 1e verd. (bk ruwe vloer) | -1980 | 3730 | 1636 | 1750
1807901 | 2342.88 | 03800 V1 1e verd | 787.75 | 3800 | 4473.75 | 4587.75

# IfcBeam: btl_staal - HE(a-b-m):HEA140, btl_staal - HE(a-b-m):HEA140:1839879
In: V3 dakvloer
Type - PredefinedType: BEAM; Material: Metal - Steel - S235 JRG2 (standaard)
Type - Other - Category: Structural Framing; Family Name: btl_staal - HE(a-b-m)
Type - Dimensions - bf: 140 mm; d: 133 mm; k: 20.5 mm; kr: 12 mm; tf: 8.5 mm; tw: 5.5 mm
Type - Identity Data - Description: HEA 140; Model: ligger; Type Name: HEA140
Type - Materials and Finishes - Structural Material: Metal - Steel - S235 JRG2 (standaard)
Type - Structural - Section Shape: 0; A: 3142 mm2; W: 0.241832
Type - Pset_BeamCommon - IsExternal: no; LoadBearing: yes
Type - Pset_ReinforcementBarPitchOfBeam - Description: HEA 140
Pset_BeamCommon - Reference: HEA140; Span: 3632.14 mm; Slope: 20.9887 deg
Pset_QuantityTakeOff - Reference: HEA140; sets with these values: 2
BaseQuantities - Length: 3632.14 mm; CrossSectionArea: 3018 mm2; OuterSurfaceArea: 609362 mm2; GrossSurfaceArea: 615398 mm2; GrossVolume: 0.00225651 m3; NetVolume: 0.00943871 m3
Other - Family: btl_staal - HE(a-b-m); Type: HEA140; Family and Type: btl_staal - HE(a-b-m): HEA140; Type Id: 1652352; End Extension Calculation: 3000 mm; Start Extension Calculation: 3000 mm
Constraints - Cross-Section Rotation: 0 deg; Reference Level: V3 dakvloer; End Level Offset: 1300.41 mm; Reference Level Elevation: 10840 mm; Start Level Offset: -0.559996 mm
Construction - EindOplegging: -12.5 mm; StartOplegging: -12.5 mm
Dimensions - Length: 3632.14 mm; Volume: 0.00943871 m3
Identity Data - Has Association: yes
Phasing - Phase Created: 2. nieuwbouw
Structural - Structural Usage: Other; Stick Symbol Location: Center of Geometry; Cut Length: 3468.78 mm
Geometric Position - y Offset Value: 0 mm; yz Justification: Uniform; z Justification: Top; z Offset Value: 0 mm; Join Status: One or two joins disabled; y Justification: Origin; End Extension: 0 mm; Start Extension: 0 mm

# IfcBeam: btl_staal - HE(a-b-m):HEA140 (45)
Type - Other - Category: Structural Framing; Family Name: btl_staal - HE(a-b-m)
Type - Dimensions - bf: 140 mm; d: 133 mm; k: 20.5 mm; kr: 12 mm; tf: 8.5 mm; tw: 5.5 mm
Type - Identity Data - Description: HEA 140; Model: ligger; Type Name: HEA140
Type - Materials and Finishes - Structural Material: Metal - Steel - S235 JRG2 (standaard)
Type - Structural - Section Shape: 0; A: 3142 mm2; W: 0.241832
Type - Pset_BeamCommon - IsExternal: no; LoadBearing: yes
Type - Pset_ReinforcementBarPitchOfBeam - Description: HEA 140
Material: Metal - Steel - S235 JRG2 (standaard)
BaseQuantities - CrossSectionArea: 3018 mm2
Pset_BeamCommon - Reference: HEA140
Pset_QuantityTakeOff - Reference: HEA140; sets with these values: 2
Other - Family: btl_staal - HE(a-b-m); Type: HEA140; Family and Type: btl_staal - HE(a-b-m): HEA140; Start Extension Calculation: 3000 mm; Type Id: 1652352
Constraints - Cross-Section Rotation: 0 deg
Construction - StartOplegging: -12.5 mm
Phasing - Phase Created: 2. nieuwbouw
Structural - Structural Usage: Other; Stick Symbol Location: Center of Geometry
Geometric Position - y Offset Value: 0 mm; yz Justification: Uniform; z Justification: Top; z Offset Value: 0 mm; y Justification: Origin; Start Extension: 0 mm
Name (btl_staal - HE(a-b-m):HEA140:...) | In | BaseQuantities, Length (mm) = Cut Length (mm) | OuterSurfaceArea (mm2) | GrossVolume (m3) | NetVolume (m3) = Volume (m3) | Span (mm) = Dimensions, Length (mm) | Slope (deg) | End Extension Calculation (mm) | Reference Level | End Level Offset (mm) | Reference Level Elevation (mm) | Start Level Offset (mm) | EindOplegging (mm) | Has Association | Join Status | End Extension (mm) | Group
1839871 | V3 dakvloer | 3468.78 | 2827052 | 0.0104688 | 0.00986863 | 3574.62 | 20.9887 | 3000 | V3 dakvloer | 1300.41 | 10840 | 20.0409 | -12.5 | yes | Both joins enabled | 0
1839873 | V3 dakvloer | 3468.77 | 2827048 | 0.0104688 | 0.00986861 | 3615.7 | 20.9888 | 2996.96 | V3 dakvloer | 5.32374 | 10840 | 1300.41 | -15.5425 | yes | Both joins enabled | 0
1839875 | V3 dakvloer | 3440.77 | 2804226 | 0.0103842 | 0.00984555 | 3625.69 | 20.9887 | 3000 | V3 dakvloer | 1300.43 | 10840 | 1.76692 | -12.5 | yes | One or two joins disabled | -5.43931 | Identity Data - Comments: + aangelaste oplegstrip 100x8
1839877 | V3 dakvloer | 3468.82 | 2827088 | 0.0104689 | 0.00986876 | 3685.68 | 20.9887 | 3000 | V3 dakvloer | -19.7231 | 10840 | 1300.43 | -12.5 | yes | One or two joins disabled | 0
1839881 | V3 dakvloer | 3468.77 | 2827047 | 0.0104687 | 0.00986861 | 3574.61 | 20.9888 | 3000 | V3 dakvloer | 20.0409 | 10840 | 1300.41 | -12.5 | yes | Both joins enabled | 0
2011398 | V4 BK metselwerk | 3327.21 | 2711675 | 0.0100415 | 0.00944138 | 3475 | 20.9887 | 3000 | V4 BK metselwerk | 431.259 | 11700 | -813.43 | -12.5 | no | One or two joins disabled | 0 | Model Group:dakspant 1A (members excluded):2011268
2011399 | V4 BK metselwerk | 3327.2 | 2711671 | 0.0100415 | 0.00944136 | 3595.25 | 20.9888 | 2996.96 | V4 BK metselwerk | -856.504 | 11700 | 431.259 | -15.5425 | no | One or two joins disabled | 0 | Model Group:dakspant 1A (members excluded):2011268
2011400 | V4 BK metselwerk | 3327.33 | 2711776 | 0.0100419 | 0.00944175 | 3555 | 20.9887 | 3000 | V4 BK metselwerk | 413.3 | 11700 | -860.045 | -12.5 | no | One or two joins disabled | 0 | Model Group:dakspant 1A (members excluded):2011268
2011401 | V4 BK metselwerk | 3327.33 | 2711775 | 0.0100419 | 0.00944175 | 3610 | 20.9887 | 3000 | V4 BK metselwerk | -881.534 | 11700 | 411.512 | -12.5 | no | One or two joins disabled | 0 | Model Group:dakspant 1A (members excluded):2011268
2011402 | V4 BK metselwerk | 3327.33 | 2711778 | 0.0100419 | 0.00944176 | 3464.46 | 20.9887 | 3000 | V4 BK metselwerk | 438.619 | 11700 | -802.294 | -12.5 | no | One or two joins disabled | 0 | Model Group:dakspant 1A (members excluded):2011268
2011403 | V4 BK metselwerk | 3327.33 | 2711772 | 0.0100419 | 0.00944174 | 3450 | 20.9888 | 3000 | V4 BK metselwerk | -797.119 | 11700 | 438.619 | -12.5 | no | One or two joins disabled | 0 | Model Group:dakspant 1A (members excluded):2011268
2011732 | V3 dakvloer | 3556.91 | 2898880 | 0.0107347 | 0.0101346 | 3617.08 | 20.9887 | 3000 | V3 dakvloer | 1291.29 | 10840 | -4.28906 | -12.5 | no | One or two joins disabled | 0 | Model Group:dakspant 1 (members excluded):2011580
2011733 | V3 dakvloer | 3553.77 | 2896322 | 0.0107253 | 0.0101341 | 3617 | 20.9888 | 2996.96 | V3 dakvloer | -4.28906 | 10840 | 1291.26 | -15.5425 | no | One or two joins disabled | 0 | Model Group:dakspant 1 (members excluded):2011580
2011734 | V3 dakvloer | 3544.77 | 2888985 | 0.0106981 | 0.0101307 | 3565 | 20.9887 | 3000 | V3 dakvloer | 1276.99 | 10840 | 0.0605824 | -12.5 | no | One or two joins disabled | 0 | Model Group:dakspant 1 (members excluded):2011580
2011735 | V3 dakvloer | 3556.9 | 2898877 | 0.0107347 | 0.0101346 | 3612.39 | 20.9887 | 3000 | V3 dakvloer | -21.4294 | 10840 | 1272.47 | -12.5 | no | One or two joins disabled | 0 | Model Group:dakspant 1 (members excluded):2011580
2011736 | V3 dakvloer | 3551.59 | 2894544 | 0.0107187 | 0.0101336 | 3632.18 | 20.9887 | 3000 | V3 dakvloer | 1298.57 | 10840 | -2.41579 | -12.5 | no | One or two joins disabled | 0 | Model Group:dakspant 1 (members excluded):2011580
2011737 | V3 dakvloer | 3540.09 | 2885171 | 0.010684 | 0.0101257 | 3643.73 | 20.9888 | 3000 | V3 dakvloer | -6.55535 | 10840 | 1298.57 | -12.5 | no | One or two joins disabled | 0 | Model Group:dakspant 1 (members excluded):2011580
2012031 | V3 dakvloer | 3556.91 | 2898880 | 0.0107347 | 0.0101346 | 3617.08 | 20.9887 | 3000 | V3 dakvloer | 1291.29 | 10840 | -4.28906 | -12.5 | no | One or two joins disabled | 0 | Model Group:dakspant 1 (members excluded):2011879
2012032 | V3 dakvloer | 3553.77 | 2896322 | 0.0107253 | 0.0101341 | 3617 | 20.9888 | 2996.96 | V3 dakvloer | -4.28906 | 10840 | 1291.26 | -15.5425 | no | One or two joins disabled | 0 | Model Group:dakspant 1 (members excluded):2011879
2012033 | V3 dakvloer | 3544.77 | 2888985 | 0.0106981 | 0.0101307 | 3565 | 20.9887 | 3000 | V3 dakvloer | 1276.99 | 10840 | 0.0605824 | -12.5 | no | One or two joins disabled | 0 | Model Group:dakspant 1 (members excluded):2011879
2012034 | V3 dakvloer | 3556.9 | 2898877 | 0.0107347 | 0.0101346 | 3612.39 | 20.9887 | 3000 | V3 dakvloer | -21.4294 | 10840 | 1272.47 | -12.5 | no | One or two joins disabled | 0 | Model Group:dakspant 1 (members excluded):2011879
2012035 | V3 dakvloer | 3551.59 | 2894544 | 0.0107187 | 0.0101336 | 3632.18 | 20.9887 | 3000 | V3 dakvloer | 1298.57 | 10840 | -2.41579 | -12.5 | no | One or two joins disabled | 0 | Model Group:dakspant 1 (members excluded):2011879
2012036 | V3 dakvloer | 3540.09 | 2885171 | 0.010684 | 0.0101257 | 3643.73 | 20.9888 | 3000 | V3 dakvloer | -6.55535 | 10840 | 1298.57 | -12.5 | no | One or two joins disabled | 0 | Model Group:dakspant 1 (members excluded):2011879
2012330 | V3 dakvloer | 3556.91 | 2898880 | 0.0107347 | 0.0101346 | 3617.08 | 20.9887 | 3000 | V3 dakvloer | 1291.29 | 10840 | -4.28906 | -12.5 | no | One or two joins disabled | 0 | Model Group:dakspant 1 (members excluded):2012178
2012331 | V3 dakvloer | 3553.77 | 2896322 | 0.0107253 | 0.0101341 | 3617 | 20.9888 | 2996.96 | V3 dakvloer | -4.28906 | 10840 | 1291.26 | -15.5425 | no | One or two joins disabled | 0 | Model Group:dakspant 1 (members excluded):2012178
2012332 | V3 dakvloer | 3544.77 | 2888985 | 0.0106981 | 0.0101307 | 3565 | 20.9887 | 3000 | V3 dakvloer | 1276.99 | 10840 | 0.0605824 | -12.5 | no | One or two joins disabled | 0 | Model Group:dakspant 1 (members excluded):2012178
2012333 | V3 dakvloer | 3556.9 | 2898877 | 0.0107347 | 0.0101346 | 3612.39 | 20.9887 | 3000 | V3 dakvloer | -21.4294 | 10840 | 1272.47 | -12.5 | no | One or two joins disabled | 0 | Model Group:dakspant 1 (members excluded):2012178
2012334 | V3 dakvloer | 3551.59 | 2894544 | 0.0107187 | 0.0101336 | 3632.18 | 20.9887 | 3000 | V3 dakvloer | 1298.57 | 10840 | -2.41579 | -12.5 | no | One or two joins disabled | 0 | Model Group:dakspant 1 (members excluded):2012178
2012335 | V3 dakvloer | 3540.09 | 2885171 | 0.010684 | 0.0101257 | 3643.73 | 20.9888 | 3000 | V3 dakvloer | -6.55535 | 10840 | 1298.57 | -12.5 | no | One or two joins disabled | 0 | Model Group:dakspant 1 (members excluded):2012178
2043975 | V3 dakvloer | 697.364 | 568352 | 0.00210465 | 0.00150451 | 697.364 | 20.9887 | 3000 | V3 dakvloer | 1300.41 | 10840 | 1050.63 | -12.5 | no | One or two joins disabled | 0
2043976 | V3 dakvloer | 727.037 | 592535 | 0.0021942 | 0.00159406 | 790 | 20.9888 | 2996.96 | V3 dakvloer | 1017.45 | 10840 | 1300.41 | -15.5425 | no | Both joins enabled | 0
2044422 | V3 dakvloer | 697.364 | 568352 | 0.00210465 | 0.00150451 | 697.364 | 20.9887 | 3000 | V3 dakvloer | 1300.41 | 10840 | 1050.63 | -12.5 | no | One or two joins disabled | 0
2044423 | V3 dakvloer | 721.957 | 588395 | 0.00217887 | 0.00159337 | 725 | 20.9888 | 2996.96 | V3 dakvloer | 1040.73 | 10840 | 1300.41 | -15.5425 | no | One or two joins disabled | 0
2044727 | V4 BK metselwerk | 697.364 | 568352 | 0.00210465 | 0.00150451 | 697.364 | 20.9887 | 3000 | V4 BK metselwerk | 440.414 | 11700 | 190.629 | -12.5 | no | One or two joins disabled | 0
2044728 | V4 BK metselwerk | 727.037 | 592535 | 0.0021942 | 0.00159406 | 790 | 20.9888 | 2996.96 | V4 BK metselwerk | 157.448 | 11700 | 440.414 | -15.5425 | no | Both joins enabled | 0
2044745 | V4 BK metselwerk | 697.364 | 568352 | 0.00210465 | 0.00150451 | 697.364 | 20.9887 | 3000 | V4 BK metselwerk | 440.414 | 11700 | 190.629 | -12.5 | no | One or two joins disabled | 0
2044746 | V4 BK metselwerk | 721.957 | 588395 | 0.00217887 | 0.00159337 | 725 | 20.9888 | 2996.96 | V4 BK metselwerk | 180.73 | 11700 | 440.414 | -15.5425 | no | One or two joins disabled | 0
2045352 | V4 BK metselwerk | 697.364 | 568352 | 0.00210465 | 0.00150451 | 697.364 | 20.9887 | 3000 | V4 BK metselwerk | 440.414 | 11700 | 190.629 | -12.5 | no | One or two joins disabled | 0
2045353 | V4 BK metselwerk | 721.957 | 588395 | 0.00217887 | 0.00159337 | 725 | 20.9888 | 2996.96 | V4 BK metselwerk | 180.73 | 11700 | 440.414 | -15.5425 | no | One or two joins disabled | 0
2045463 | V4 BK metselwerk | 697.364 | 568352 | 0.00210465 | 0.0015815 | 697.364 | 20.9887 | 3000 | V4 BK metselwerk | 440.414 | 11700 | 190.629 | -12.5 | no | One or two joins disabled | 0
2045464 | V4 BK metselwerk | 586.946 | 478361 | 0.0017714 | 0.0012629 | 725 | 20.9888 | 2996.96 | V4 BK metselwerk | 180.73 | 11700 | 440.414 | -15.5425 | no | One or two joins disabled | 0 | Geometric Position - Start Join Cutback: 0 mm
2077953 | V1 1e verd. (bk ruwe vloer) | 6168.07 | 5026978 | 0.0186152 | 0.0183321 | 6074.25 | 44.8082 | 3000 | 03800 V1 1e verd | 5097.66 | 3800 | 816.915 | -12.5 | no | Both joins enabled | 0 | Identity Data - Comments: onder bestaande vloer
2078034 | V1 1e verd. (bk ruwe vloer) | 6154.19 | 5015663 | 0.0185733 | 0.0182904 | 6060.42 | 44.8823 | 3000 | 03800 V1 1e verd | 821.045 | 3800 | 5097.6 | -12.5 | no | Both joins enabled | 0 | Identity Data - Comments: onder bestaande vloer
2078098 | V1 1e verd. (bk ruwe vloer) | 871.551 | 710314 | 0.00263034 | 0.00254697 | 843.926 | 90 | 3000 | 03800 V1 1e verd | -70 | 3800 | 773.926 | -12.5 | no | One or two joins disabled | 0 | Identity Data - Comments: onder bestaande vloer
2078219 | V1 1e verd. (bk ruwe vloer) | 867.41 | 706940 | 0.00261784 | 0.00253432 | 839.735 | 90 | 3000 | 03800 V1 1e verd | -70 | 3800 | 769.735 | -12.5 | no | One or two joins disabled | 0 | Identity Data - Comments: onder bestaande vloer

# IfcBeam: btl_staal - HE(a-b-m):HEA160. (27)
Type - Other - Category: Structural Framing; Family Name: btl_staal - HE(a-b-m)
Type - Dimensions - bf: 160 mm; d: 152 mm; k: 24 mm; kr: 15 mm; tf: 9 mm; tw: 6 mm
Type - Identity Data - Description: HEA 160; Model: ligger; Type Name: HEA160.
Type - Materials and Finishes - Structural Material: Metal - Steel - S235 JRG2 (standaard)
Type - Structural - Section Shape: 0; A: 3880 mm2; W: 0.298514
Type - Pset_BeamCommon - IsExternal: no; LoadBearing: yes
Type - Pset_ReinforcementBarPitchOfBeam - Description: HEA 160
Material: Metal - Steel - S235 JRG2 (standaard)
BaseQuantities - CrossSectionArea: 3684 mm2
Pset_BeamCommon - Reference: HEA160.
Pset_QuantityTakeOff - Reference: HEA160.; sets with these values: 2
Other - End Extension Calculation: 3000 mm; Family: btl_staal - HE(a-b-m); Family and Type: btl_staal - HE(a-b-m): HEA160.; Start Extension Calculation: 3000 mm; Type: HEA160.; Type Id: 1705367
Constraints - Cross-Section Rotation: 0 deg
Construction - EindOplegging: -12.5 mm; StartOplegging: -12.5 mm
Phasing - Phase Created: 2. nieuwbouw
Structural - Structural Usage: Other; Stick Symbol Location: Center of Geometry
Geometric Position - y Offset Value: 0 mm; yz Justification: Uniform; z Justification: Top; z Offset Value: 0 mm; y Justification: Origin; Start Extension: 0 mm
Name (btl_staal - HE(a-b-m):HEA160.:...) | In | BaseQuantities, Length (mm) = Cut Length (mm) | OuterSurfaceArea (mm2) | GrossVolume (m3) = NetVolume (m3) = Volume (m3) | Slope (deg) | Span (mm) = Dimensions, Length (mm) | End Level Offset (mm) | Reference Level | Reference Level Elevation (mm) | Start Level Offset (mm) | Elevation at Bottom (mm) | Elevation at Top (mm) | Has Association | Join Status | End Extension (mm) | Group
1586570 | V4 BK metselwerk | 2403.35 | 2239923 | 0.00885395 | 0 | 2403.35 | 424 | V4 BK metselwerk | 11700 | 424 | 11972 | 12124 | yes | One or two joins disabled | 0
1748311 | V4 BK metselwerk | 2462.26 | 2294826 | 0.00907097 | 0.427043 | 2683.4 | 200 | V4 BK metselwerk | 11700 | 180 |  |  | yes | Both joins enabled | 0 | Structural - Start Attachment Type: End Elevation; Geometric Position - End Join Cutback: 0 mm; Start Join Cutback: 0 mm
1836224 | V4 BK metselwerk | 2247.85 | 2094997 | 0.00828108 | 0 | 2247.85 | 424 | V4 BK metselwerk | 11700 | 424 | 11972 | 12124 | yes | One or two joins disabled | 0
1849496 | V4 BK metselwerk | 2543.32 | 2370378 | 0.00936961 | 0 | 2593.32 | 409.706 | V4 BK metselwerk | 11700 | 409.706 | 11957.7 | 12109.7 | yes | One or two joins disabled | -50
1849608 | V3 dakvloer | 2593.32 | 2416978 | 0.00955381 | 0 | 2593.32 | 1269.71 | V3 dakvloer | 10840 | 1269.71 | 11957.7 | 12109.7 | yes | Both joins enabled | 0
1849866 | V4 BK metselwerk | 2543.32 | 2370378 | 0.00936961 | 0 | 2593.32 | 409.706 | V4 BK metselwerk | 11700 | 409.706 | 11957.7 | 12109.7 | yes | One or two joins disabled | -50
1854317 | V4 BK metselwerk | 2593.32 | 2416978 | 0.00955381 | 0 | 2593.32 | 409.706 | V4 BK metselwerk | 11700 | 409.706 | 11957.7 | 12109.7 | yes | Both joins enabled | 0
2011731 | V3 dakvloer | 3292.9 | 3068979 | 0.012131 | 0 | 3292.9 | -4.28906 | V3 dakvloer | 10840 | -4.28906 | 10683.7 | 10835.7 | no | One or two joins disabled | 0 | Model Group:dakspant 1 (members excluded):2011580
2011875 | V3 dakvloer | 7579.75 | 7064324 | 0.0279238 | 0 | 7579.75 | -4.28906 | V3 dakvloer | 10840 | -4.28906 | 10683.7 | 10835.7 | no | One or two joins disabled | 0 | Model Group:dakspant 1 (members excluded):2011580
2011876 | V3 dakvloer | 7589.09 | 7073035 | 0.0279582 | 0 | 7589.09 | -4.28906 | V3 dakvloer | 10840 | -4.28906 | 10683.7 | 10835.7 | no | One or two joins disabled | 0 | Model Group:dakspant 1 (members excluded):2011580
2011877 | V3 dakvloer | 3302.91 | 3078309 | 0.0121679 | 0 | 3302.91 | -4.28906 | V3 dakvloer | 10840 | -4.28906 | 10683.7 | 10835.7 | no | One or two joins disabled | 0 | Model Group:dakspant 1 (members excluded):2011580
2012030 | V3 dakvloer | 3292.9 | 3068979 | 0.012131 | 0 | 3292.9 | -4.28906 | V3 dakvloer | 10840 | -4.28906 | 10683.7 | 10835.7 | no | One or two joins disabled | 0 | Model Group:dakspant 1 (members excluded):2011879
2012174 | V3 dakvloer | 7579.75 | 7064324 | 0.0279238 | 0 | 7579.75 | -4.28906 | V3 dakvloer | 10840 | -4.28906 | 10683.7 | 10835.7 | no | One or two joins disabled | 0 | Model Group:dakspant 1 (members excluded):2011879
2012175 | V3 dakvloer | 7589.09 | 7073035 | 0.0279582 | 0 | 7589.09 | -4.28906 | V3 dakvloer | 10840 | -4.28906 | 10683.7 | 10835.7 | no | One or two joins disabled | 0 | Model Group:dakspant 1 (members excluded):2011879
2012176 | V3 dakvloer | 3302.91 | 3078309 | 0.0121679 | 0 | 3302.91 | -4.28906 | V3 dakvloer | 10840 | -4.28906 | 10683.7 | 10835.7 | no | One or two joins disabled | 0 | Model Group:dakspant 1 (members excluded):2011879
2012329 | V3 dakvloer | 3292.9 | 3068979 | 0.012131 | 0 | 3292.9 | -4.28906 | V3 dakvloer | 10840 | -4.28906 | 10683.7 | 10835.7 | no | One or two joins disabled | 0 | Model Group:dakspant 1 (members excluded):2012178
2012473 | V3 dakvloer | 7579.75 | 7064324 | 0.0279238 | 0 | 7579.75 | -4.28906 | V3 dakvloer | 10840 | -4.28906 | 10683.7 | 10835.7 | no | One or two joins disabled | 0 | Model Group:dakspant 1 (members excluded):2012178
2012474 | V3 dakvloer | 7589.09 | 7073035 | 0.0279582 | 0 | 7589.09 | -4.28906 | V3 dakvloer | 10840 | -4.28906 | 10683.7 | 10835.7 | no | One or two joins disabled | 0 | Model Group:dakspant 1 (members excluded):2012178
2012475 | V3 dakvloer | 3302.91 | 3078309 | 0.0121679 | 0 | 3302.91 | -4.28906 | V3 dakvloer | 10840 | -4.28906 | 10683.7 | 10835.7 | no | One or two joins disabled | 0 | Model Group:dakspant 1 (members excluded):2012178
2012643 | V3 dakvloer | 14214.1 | 13247560 | 0.0523648 | 0 | 14214.1 | -4.28906 | V3 dakvloer | 10840 | -4.28906 | 10683.7 | 10835.7 | no | One or two joins disabled | 0 | Model Group:Spant 3:2012551
2012709 | V4 BK metselwerk | 14452 | 13469264 | 0.0532412 | 0 | 14452 | 409.706 | V4 BK metselwerk | 11700 | 409.706 | 11957.7 | 12109.7 | no | One or two joins disabled | 0 | Model Group:Spant 3:2012551
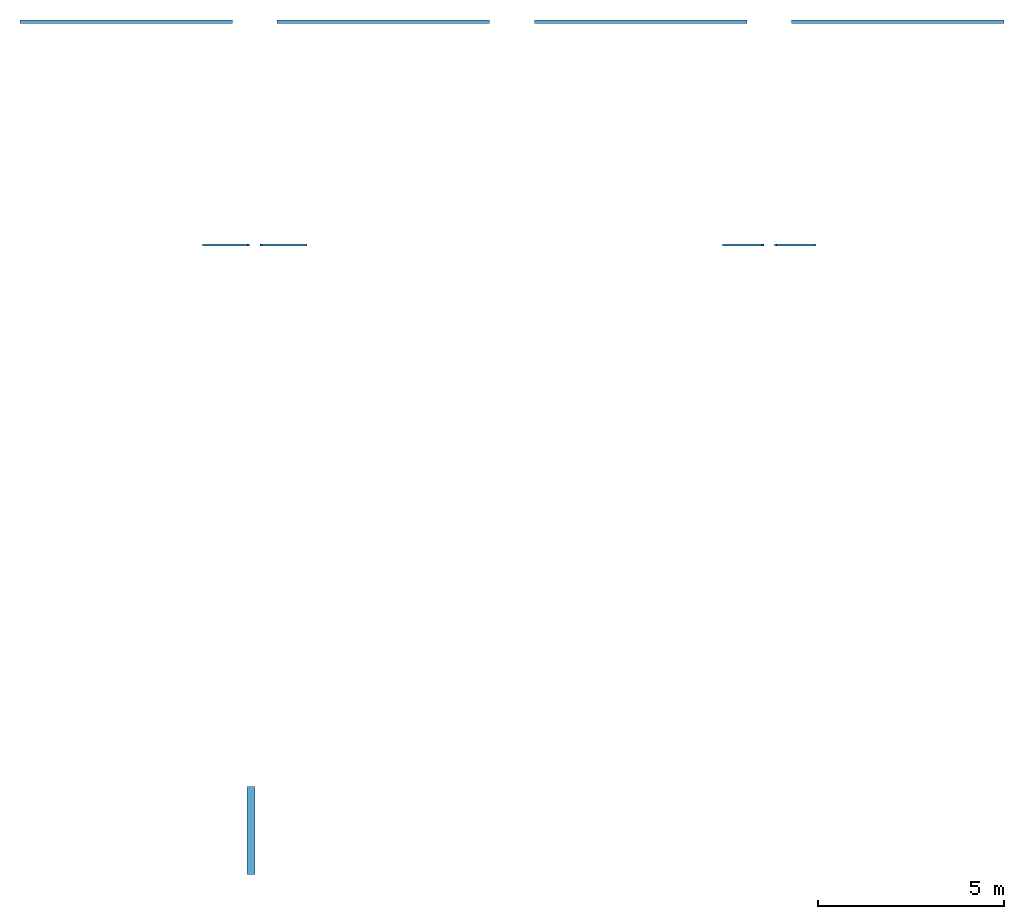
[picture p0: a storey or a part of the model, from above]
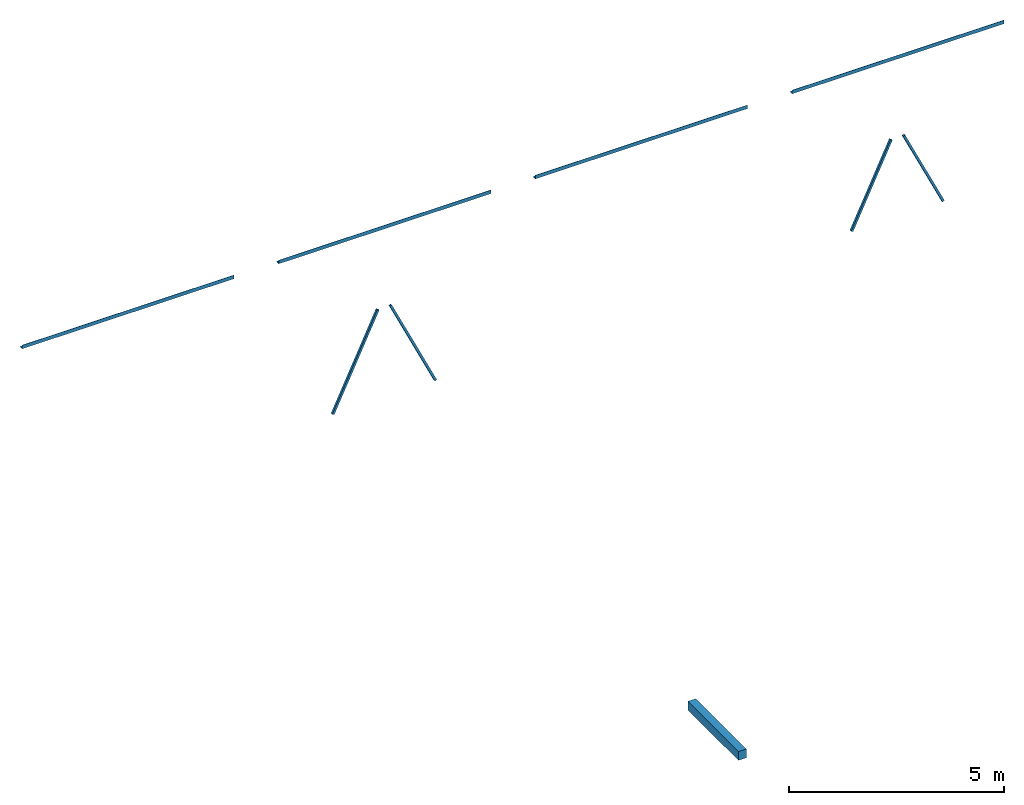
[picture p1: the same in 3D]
Properties of the parts of a building model (IFC2X3), part 2 of 6

# IfcBeam: btl_staal - HE(a-b-m):HEA160. (27)
Name (btl_staal - HE(a-b-m):HEA160.:...) | In | BaseQuantities, Length (mm) = Cut Length (mm) | OuterSurfaceArea (mm2) | GrossVolume (m3) = NetVolume (m3) = Volume (m3) | Slope (deg) | Span (mm) = Dimensions, Length (mm) | End Level Offset (mm) | Reference Level | Reference Level Elevation (mm) | Start Level Offset (mm) | Elevation at Bottom (mm) | Elevation at Top (mm) | Has Association | Join Status | End Extension (mm) | Group
2012824 | V3 dakvloer | 14214.1 | 13247560 | 0.0523648 | 0 | 14214.1 | -4.28906 | V3 dakvloer | 10840 | -4.28906 | 10683.7 | 10835.7 | no | One or two joins disabled | 0 | Model Group:Spant 3:2012732
2012890 | V4 BK metselwerk | 14452 | 13469264 | 0.0532412 | 0 | 14452 | 409.706 | V4 BK metselwerk | 11700 | 409.706 | 11957.7 | 12109.7 | no | One or two joins disabled | 0 | Model Group:Spant 3:2012732
2013005 | V3 dakvloer | 14214.1 | 13247560 | 0.0523648 | 0 | 14214.1 | -4.28906 | V3 dakvloer | 10840 | -4.28906 | 10683.7 | 10835.7 | no | One or two joins disabled | 0 | Model Group:Spant 3:2012913
2013071 | V4 BK metselwerk | 14452 | 13469264 | 0.0532412 | 0 | 14452 | 409.706 | V4 BK metselwerk | 11700 | 409.706 | 11957.7 | 12109.7 | no | One or two joins disabled | 0 | Model Group:Spant 3:2012913
2036651 | V4 BK metselwerk | 2323.32 | 2165338 | 0.00855913 | 0 | 2723.32 | 200 | V4 BK metselwerk | 11700 | 200 | 11748 | 11900 | no | Both joins enabled | 0 | Geometric Position - End Join Cutback: 0 mm; Start Join Cutback: 0 mm
2036740 | V4 BK metselwerk | 2102.11 | 1959167 | 0.00774418 | 0.497487 | 2303.44 | 180 | V4 BK metselwerk | 11700 | 200 |  |  | no | One or two joins disabled | 0 | Geometric Position - Start Join Cutback: 0 mm

# IfcBeam: btl_staal - HE(a-b-m):HEA180, btl_staal - HE(a-b-m):HEA180:2032421
In: V3 dakvloer
Type - PredefinedType: BEAM; Material: Metal - Steel - S235 JRG2 (standaard)
Type - Other - Category: Structural Framing; Family Name: btl_staal - HE(a-b-m)
Type - Dimensions - bf: 180 mm; d: 171 mm; k: 24.5 mm; kr: 15 mm; tf: 9.5 mm; tw: 6 mm
Type - Identity Data - Description: HEA180; Model: ligger; Type Name: HEA180
Type - Materials and Finishes - Structural Material: Metal - Steel - S235 JRG2 (standaard)
Type - Structural - Section Shape: 0; A: 4530 mm2; W: 0.348136
Type - Pset_BeamCommon - IsExternal: no; LoadBearing: yes
Type - Pset_ReinforcementBarPitchOfBeam - Description: HEA180
Pset_BeamCommon - Reference: HEA180; Span: 2769.57 mm; Slope: 20.9887 deg
Pset_QuantityTakeOff - Reference: HEA180; sets with these values: 2
BaseQuantities - Length: 2769.57 mm; CrossSectionArea: 4332 mm2; OuterSurfaceArea: 2908048 mm2; GrossSurfaceArea: 2916712 mm2; GrossVolume: 0.0119978 m3; NetVolume: 0.011325 m3
Other - Family: btl_staal - HE(a-b-m); Family and Type: btl_staal - HE(a-b-m): HEA180; Type: HEA180; Type Id: 1732681; End Extension Calculation: 3000 mm; Start Extension Calculation: 3000 mm
Constraints - Cross-Section Rotation: 0 deg; Reference Level: V3 dakvloer; End Level Offset: 1040 mm; Reference Level Elevation: 10840 mm; Start Level Offset: 47.9841 mm
Construction - EindOplegging: -12.5 mm; StartOplegging: -12.5 mm
Dimensions - Length: 2769.57 mm; Volume: 0.011325 m3
Identity Data - Has Association: no
Phasing - Phase Created: 2. nieuwbouw
Structural - Structural Usage: Other; Stick Symbol Location: Center of Geometry; Cut Length: 2769.57 mm
Geometric Position - Join Status: Both joins enabled; y Offset Value: 0 mm; yz Justification: Uniform; z Justification: Top; z Offset Value: 0 mm; y Justification: Origin; End Extension: 0 mm; Start Extension: 0 mm

# IfcBeam: btl_staal - HE(a-b-m):HEA180 (10)
Type - Other - Category: Structural Framing; Family Name: btl_staal - HE(a-b-m)
Type - Dimensions - bf: 180 mm; d: 171 mm; k: 24.5 mm; kr: 15 mm; tf: 9.5 mm; tw: 6 mm
Type - Identity Data - Description: HEA180; Model: ligger; Type Name: HEA180
Type - Materials and Finishes - Structural Material: Metal - Steel - S235 JRG2 (standaard)
Type - Structural - Section Shape: 0; A: 4530 mm2; W: 0.348136
Type - Pset_BeamCommon - IsExternal: no; LoadBearing: yes
Type - Pset_ReinforcementBarPitchOfBeam - Description: HEA180
Material: Metal - Steel - S235 JRG2 (standaard)
BaseQuantities - CrossSectionArea: 4332 mm2
Pset_BeamCommon - Reference: HEA180
Pset_QuantityTakeOff - Reference: HEA180; sets with these values: 2
Other - Family: btl_staal - HE(a-b-m); End Extension Calculation: 3000 mm; Family and Type: btl_staal - HE(a-b-m): HEA180; Start Extension Calculation: 3000 mm; Type: HEA180; Type Id: 1732681
Constraints - Cross-Section Rotation: 0 deg
Construction - EindOplegging: -12.5 mm; StartOplegging: -12.5 mm
Phasing - Phase Created: 2. nieuwbouw
Structural - Structural Usage: Other; Stick Symbol Location: Center of Geometry
Geometric Position - y Offset Value: 0 mm; yz Justification: Uniform; z Justification: Top; z Offset Value: 0 mm; y Justification: Origin; End Extension: 0 mm; Start Extension: 0 mm
Name (btl_staal - HE(a-b-m):HEA180:...) | In | BaseQuantities, Length (mm) = Cut Length (mm) | OuterSurfaceArea (mm2) | GrossVolume (m3) | NetVolume (m3) = Volume (m3) | Slope (deg) | Span (mm) = Dimensions, Length (mm) | Reference Level | End Level Offset (mm) | Reference Level Elevation (mm) | Start Level Offset (mm) | Elevation at Bottom (mm) | Elevation at Top (mm) | Has Association | Join Status
1608468 | V4 BK metselwerk | 6807 | 7147350 | 0.0294879 | 0.0294879 | 0 | 6807 | V4 BK metselwerk | 1743.8 | 11700 | 1743.8 | 13272.8 | 13443.8 | yes | One or two joins disabled
1608470 | V4 BK metselwerk | 6675 | 7008749 | 0.0289161 | 0.0289161 | 0 | 6675 | V4 BK metselwerk | 1743.8 | 11700 | 1743.8 | 13272.8 | 13443.8 | yes | Both joins enabled
1608472 | V4 BK metselwerk | 6699.98 | 7034983 | 0.0290243 | 0.0290243 | 0 | 6699.98 | V4 BK metselwerk | 1743.8 | 11700 | 1743.8 | 13272.8 | 13443.8 | yes | Both joins enabled
1608474 | V4 BK metselwerk | 6699.99 | 7034995 | 0.0290244 | 0.0290244 | 0 | 6699.99 | V4 BK metselwerk | 1743.8 | 11700 | 1743.8 | 13272.8 | 13443.8 | yes | Both joins enabled
1608476 | V4 BK metselwerk | 2913.75 | 3059434 | 0.0126224 | 0.0126224 | 0 | 2913.75 | V4 BK metselwerk | 1743.79 | 11700 | 1743.79 | 13272.8 | 13443.8 | yes | One or two joins disabled
2014031 | V3 dakvloer | 250.106 | 262611 | 0.00108346 | 0.000828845 | 90 | 191.331 | V3 dakvloer | 181.331 | 10840 | -10 |  |  | no | One or two joins disabled
2032422 | V4 BK metselwerk | 5069.86 | 5323349 | 0.0219626 | 0.021894 | 0 | 5069.86 | V4 BK metselwerk | 180 | 11700 | 180 | 11709 | 11880 | no | Both joins enabled
2032427 | V3 dakvloer | 2233.19 | 2344848 | 0.00967417 | 0.00935095 | 20.9888 | 2174.41 | V3 dakvloer | 261.158 | 10840 | 1040 |  |  | no | Both joins enabled
2060078 | V4 BK metselwerk | 8310.12 | 8725630 | 0.0359995 | 0.0359995 | 0 | 8310.12 | V4 BK metselwerk | 180 | 11700 | 180 | 11709 | 11880 | no | One or two joins disabled
2060432 | V4 BK metselwerk | 3069.98 | 3223480 | 0.0132992 | 0.0132305 | 0 | 3069.98 | V4 BK metselwerk | 180 | 11700 | 180 | 11709 | 11880 | no | One or two joins disabled

# IfcBeam: btl_staal - HE(a-b-m):HEA200. (22)
Type - Other - Category: Structural Framing; Family Name: btl_staal - HE(a-b-m)
Type - Dimensions - bf: 200 mm; d: 190 mm; k: 28 mm; kr: 18 mm; tf: 10 mm; tw: 6.5 mm
Type - Identity Data - Description: HEA 200; Model: ligger; Type Name: HEA200.
Type - Materials and Finishes - Structural Material: Metal - Steel - S235 JRG2 (standaard)
Type - Structural - Section Shape: 0; A: 5380 mm2; W: 0.414821
Type - Pset_BeamCommon - IsExternal: no; LoadBearing: yes
Type - Pset_ReinforcementBarPitchOfBeam - Description: HEA 200
Material: Metal - Steel - S235 JRG2 (standaard)
Pset_BeamCommon - Reference: HEA200.
Pset_QuantityTakeOff - Reference: HEA200.; sets with these values: 2
Other - Family: btl_staal - HE(a-b-m); End Extension Calculation: 3000 mm; Family and Type: btl_staal - HE(a-b-m): HEA200.; Start Extension Calculation: 3000 mm; Type: HEA200.; Type Id: 1757411
Construction - EindOplegging: -12.5 mm; StartOplegging: -12.5 mm
Phasing - Phase Created: 2. nieuwbouw
Structural - Structural Usage: Other; Stick Symbol Location: Center of Geometry
Geometric Position - y Offset Value: 0 mm; yz Justification: Uniform; z Justification: Top; z Offset Value: 0 mm; y Justification: Origin; End Extension: 0 mm; Start Extension: 0 mm
Name (btl_staal - HE(a-b-m):HEA200.:...) | In | BaseQuantities, Length (mm) | CrossSectionArea (mm2) | OuterSurfaceArea (mm2) | GrossVolume (m3) | NetVolume (m3) = Volume (m3) | Span (mm) = Dimensions, Length (mm) | Slope (deg) | Reference Level | Cross-Section Rotation (deg) | End Level Offset (mm) | Reference Level Elevation (mm) | Start Level Offset (mm) | Has Association | Cut Length (mm) | Join Status
1603292 | V4 BK metselwerk | 6002.45 | 5105 | 7004858 | 0.0306425 | 0.030261 | 6186.77 | 20.968 | V4 BK metselwerk | -90 | -542.719 | 11700 | 1671.19 | yes | 6002.45 | One or two joins disabled
1603324 | V4 BK metselwerk | 6170.13 | 5105 | 7200536 | 0.0314985 | 0.030942 | 6145.04 | 20.9696 | V4 BK metselwerk | 90 | -527.951 | 11700 | 1671.19 | yes | 6170.13 | One or two joins disabled
1764587 | V4 BK metselwerk | 6687.3 | 5105 | 7804079 | 0.0341387 | 0.0341387 | 6807 | 0 | V4 BK metselwerk | -20.97 | 705.2 | 11700 | 705.2 | yes | 6687.3 | Both joins enabled | Dimensions - Elevation at Bottom: 12192 mm; Elevation at Top: 12441 mm; Geometric Position - Start Join Cutback: 12.7 mm
1764589 | V4 BK metselwerk | 6675 | 5105 | 7789724 | 0.0340759 | 0.0340759 | 6675 | 0 | V4 BK metselwerk | 20.97 | 705.2 | 11700 | 705.2 | yes | 6675 | Both joins enabled | Dimensions - Elevation at Bottom: 12192 mm; Elevation at Top: 12441 mm
1764591 | V4 BK metselwerk | 6699.98 | 5105 | 7818881 | 0.0342034 | 0.0342034 | 6699.98 | 0 | V4 BK metselwerk | 20.97 | 705.2 | 11700 | 705.2 | yes | 6699.98 | Both joins enabled | Dimensions - Elevation at Bottom: 12192 mm; Elevation at Top: 12441 mm
1764593 | V4 BK metselwerk | 6674.99 | 5105 | 7789718 | 0.0340758 | 0.0340758 | 6674.99 | 0 | V4 BK metselwerk | 20.97 | 705.2 | 11700 | 705.2 | yes | 6674.99 | Both joins enabled | Dimensions - Elevation at Bottom: 12192 mm; Elevation at Top: 12441 mm
1764595 | V4 BK metselwerk | 2909.05 | 5105 | 3394859 | 0.0148507 | 0.0148507 | 3028.75 | 0 | V4 BK metselwerk | 20.97 | 705.2 | 11700 | 705.2 | yes | 2909.05 | Both joins enabled | Dimensions - Elevation at Bottom: 12192 mm; Elevation at Top: 12441 mm; Geometric Position - Start Join Cutback: 12.7 mm
1765167 | V4 BK metselwerk | 6687.3 | 5105 | 7804079 | 0.0341387 | 0.0341387 | 6807 | 0 | V4 BK metselwerk | 20.97 | 705.2 | 11700 | 705.2 | yes | 6687.3 | Both joins enabled | Dimensions - Elevation at Bottom: 12192 mm; Elevation at Top: 12441 mm; Geometric Position - Start Join Cutback: 12.7 mm
1765169 | V4 BK metselwerk | 6675 | 5105 | 7789724 | 0.0340759 | 0.0340759 | 6675 | 0 | V4 BK metselwerk | -20.97 | 705.2 | 11700 | 705.2 | yes | 6675 | Both joins enabled | Dimensions - Elevation at Bottom: 12192 mm; Elevation at Top: 12441 mm
1765171 | V4 BK metselwerk | 6699.98 | 5105 | 7818881 | 0.0342034 | 0.0342034 | 6699.98 | 0 | V4 BK metselwerk | -20.97 | 705.2 | 11700 | 705.2 | yes | 6699.98 | Both joins enabled | Dimensions - Elevation at Bottom: 12192 mm; Elevation at Top: 12441 mm
1765173 | V4 BK metselwerk | 6674.99 | 5105 | 7789718 | 0.0340758 | 0.0340758 | 6674.99 | 0 | V4 BK metselwerk | -20.97 | 705.2 | 11700 | 705.2 | yes | 6674.99 | Both joins enabled | Dimensions - Elevation at Bottom: 12192 mm; Elevation at Top: 12441 mm
1765175 | V4 BK metselwerk | 3028.75 | 5105 | 3534549 | 0.0154618 | 0.0154618 | 3028.75 | 0 | V4 BK metselwerk | -20.97 | 705.2 | 11700 | 705.2 | yes | 3028.75 | One or two joins disabled | Dimensions - Elevation at Bottom: 12192 mm; Elevation at Top: 12441 mm
1988283 | V4 BK metselwerk | 6002.43 | 5105 | 7004841 | 0.0306424 | 0.0302609 | 6186.75 | 20.9681 | V4 BK metselwerk | -90 | -542.719 | 11700 | 1671.2 | yes | 6002.43 | One or two joins disabled
1988285 | V4 BK metselwerk | 6170.15 | 5105 | 7200561 | 0.0314986 | 0.0309421 | 6145.06 | 20.9696 | V4 BK metselwerk | 90 | -527.951 | 11700 | 1671.2 | yes | 6170.15 | One or two joins disabled
2015837 | V3 dakvloer | 5847.55 | 5105 | 6824096 | 0.0298518 | 0.0296659 | 6188.68 | 20.9681 | V3 dakvloer | 0 | 410.655 | 10840 | 2625.26 | no | 5847.55 | One or two joins disabled | Geometric Position - Start Join Cutback: 12.7 mm; Structural - Start Attachment Type: End Elevation; Group: Model Group:Spant 5 (members excluded):2015775
2015838 | V3 dakvloer |  |  |  |  | 0.0304958 | 6146.99 | 20.9696 | V3 dakvloer | 0 | 425.42 | 10840 | 2625.26 | no | 6044.37 | One or two joins disabled | Geometric Position - Start Join Cutback: 12.7 mm; Structural - Start Attachment Type: End Elevation; Group: Model Group:Spant 5 (members excluded):2015775; BaseQuantities - GrossSurfaceArea: 0 mm2
2015954 | V3 dakvloer | 5847.55 | 5105 | 6824096 | 0.0298518 | 0.0296659 | 6188.68 | 20.9681 | V3 dakvloer | 0 | 410.655 | 10840 | 2625.26 | no | 5847.55 | One or two joins disabled | Geometric Position - Start Join Cutback: 12.7 mm; Structural - Start Attachment Type: End Elevation; Group: Model Group:Spant 5 (members excluded):2015892
2015955 | V3 dakvloer |  |  |  |  | 0.0304958 | 6146.99 | 20.9696 | V3 dakvloer | 0 | 425.42 | 10840 | 2625.26 | no | 6044.37 | One or two joins disabled | Geometric Position - Start Join Cutback: 12.7 mm; Structural - Start Attachment Type: End Elevation; Group: Model Group:Spant 5 (members excluded):2015892; BaseQuantities - GrossSurfaceArea: 0 mm2
2016069 | V3 dakvloer | 5847.55 | 5105 | 6824096 | 0.0298518 | 0.0296659 | 6188.68 | 20.9681 | V3 dakvloer | 0 | 410.655 | 10840 | 2625.26 | no | 5847.55 | One or two joins disabled | Geometric Position - Start Join Cutback: 12.7 mm; Structural - Start Attachment Type: End Elevation; Group: Model Group:Spant 5 (members excluded):2016007
2016070 | V3 dakvloer |  |  |  |  | 0.0304958 | 6146.99 | 20.9696 | V3 dakvloer | 0 | 425.42 | 10840 | 2625.26 | no | 6044.37 | One or two joins disabled | Geometric Position - Start Join Cutback: 12.7 mm; Structural - Start Attachment Type: End Elevation; Group: Model Group:Spant 5 (members excluded):2016007; BaseQuantities - GrossSurfaceArea: 0 mm2
2016184 | V3 dakvloer | 5847.55 | 5105 | 6824096 | 0.0298518 | 0.0296659 | 6188.68 | 20.9681 | V3 dakvloer | 0 | 410.655 | 10840 | 2625.26 | no | 5847.55 | One or two joins disabled | Geometric Position - Start Join Cutback: 12.7 mm; Structural - Start Attachment Type: End Elevation; Group: Model Group:Spant 5 (members excluded):2016122
2016185 | V3 dakvloer |  |  |  |  | 0.0304958 | 6146.99 | 20.9696 | V3 dakvloer | 0 | 425.42 | 10840 | 2625.26 | no | 6044.37 | One or two joins disabled | Geometric Position - Start Join Cutback: 12.7 mm; Structural - Start Attachment Type: End Elevation; Group: Model Group:Spant 5 (members excluded):2016122; BaseQuantities - GrossSurfaceArea: 0 mm2

# IfcBeam: btl_staal - HE(a-b-m):HEA260 (12)
Type - Other - Category: Structural Framing; Family Name: btl_staal - HE(a-b-m)
Type - Dimensions - bf: 260 mm; d: 250 mm; k: 36.5 mm; kr: 24 mm; tf: 12.5 mm; tw: 7.5 mm
Type - Identity Data - Description: HEA 260; Model: ligger; Type Name: HEA260
Type - Materials and Finishes - Structural Material: Metal - Steel - S235 JRG2 (standaard)
Type - Structural - Section Shape: 0; A: 8680 mm2; W: 0.668814
Type - Pset_BeamCommon - IsExternal: no; LoadBearing: yes
Type - Pset_ReinforcementBarPitchOfBeam - Description: HEA 260
Material: Metal - Steel - S235 JRG2 (standaard)
BaseQuantities - CrossSectionArea: 8187.5 mm2
Pset_BeamCommon - Slope: 0 deg; Reference: HEA260
Pset_QuantityTakeOff - Reference: HEA260; sets with these values: 2
Other - Type: HEA260; Family: btl_staal - HE(a-b-m); End Extension Calculation: 3000 mm; Family and Type: btl_staal - HE(a-b-m): HEA260; Start Extension Calculation: 3000 mm; Type Id: 1779730
Construction - EindOplegging: -12.5 mm; StartOplegging: -12.5 mm
Phasing - Phase Created: 2. nieuwbouw
Structural - Structural Usage: Other; Stick Symbol Location: Center of Geometry
Geometric Position - y Offset Value: 0 mm; yz Justification: Uniform; z Offset Value: 0 mm; y Justification: Origin; End Extension: 0 mm; Start Extension: 0 mm
Name (btl_staal - HE(a-b-m):HEA260:...) | In | BaseQuantities, Length (mm) = Cut Length (mm) | OuterSurfaceArea (mm2) | GrossVolume (m3) = NetVolume (m3) = Volume (m3) | Span (mm) = Dimensions, Length (mm) | Reference Level | Cross-Section Rotation (deg) | End Level Offset (mm) = Start Level Offset (mm) | Reference Level Elevation (mm) | Elevation at Bottom (mm) | Elevation at Top (mm) | Has Association | z Justification | Join Status | End Join Cutback (mm) | Start Attachment Type = End Attachment Type | Start Join Cutback (mm)
1735328 | V4 BK metselwerk | 14542 | 22176550 | 0.119063 | 14692 | V4 BK metselwerk | 90 | -912 | 11700 | 10658 | 10918 | yes | Top | One or two joins disabled | 0
1735475 | V4 BK metselwerk | 22646 | 34535109 | 0.185414 | 22646 | V4 BK metselwerk | 90 | -912 | 11700 | 10658 | 10918 | yes | Top | One or two joins disabled
1760956 | V4 BK metselwerk | 31087.7 | 47408784 | 0.254531 | 31087.7 | V4 BK metselwerk | 90 | -484 | 11700 | 11086 | 11346 | yes | Top | Both joins enabled
1764120 | V2 2e verd. (bk ruwe vloer) | 6934.6 | 10575265 | 0.056777 | 7091.87 | V2 2e verd. (bk ruwe vloer) | 90 | 0 | 7530 | 7400 | 7660 | yes | Top | Both joins enabled | 12.7 | End Elevation | 12.7
1766850 | V2 2e verd. (bk ruwe vloer) | 6976.6 | 10639315 | 0.0571209 | 7214.12 | V2 2e verd. (bk ruwe vloer) | -90 | 0 | 7530 | 7400 | 7660 | yes | Top | Both joins enabled | 12.7 | End Elevation | 12.7
1766907 | V2 2e verd. (bk ruwe vloer) | 7373.16 | 11244062 | 0.0603677 | 7616.5 | V2 2e verd. (bk ruwe vloer) | 90 | 0 | 7530 | 7400 | 7660 | yes | Top | Both joins enabled | 12.7 | End Elevation | 12.7
1767654 | V2 2e verd. (bk ruwe vloer) | 6955.47 | 10607099 | 0.0569479 | 7349.54 | V2 2e verd. (bk ruwe vloer) | -90 | 0 | 7530 | 7400 | 7660 | yes | Top | Both joins enabled | 12.7 | End Elevation | 12.7
1767692 | V2 2e verd. (bk ruwe vloer) | 7329.15 | 11176961 | 0.0600075 | 7567.81 | V2 2e verd. (bk ruwe vloer) | 90 | 0 | 7530 | 7400 | 7660 | yes | Top | Both joins enabled | 12.7 | End Elevation | 12.7
1767811 | V2 2e verd. (bk ruwe vloer) | 6976.6 | 10639315 | 0.0571209 | 7214.12 | V2 2e verd. (bk ruwe vloer) | -90 | 0 | 7530 | 7400 | 7660 | yes | Top | Both joins enabled | 12.7 | End Elevation | 12.7
1767838 | V2 2e verd. (bk ruwe vloer) | 6934.6 | 10575265 | 0.056777 | 7227.12 | V2 2e verd. (bk ruwe vloer) | 90 | 0 | 7530 | 7400 | 7660 | yes | Top | Both joins enabled | 12.7 | End Elevation | 12.7
2011397 | V4 BK metselwerk | 22259 | 33944952 | 0.182245 | 22259 | V4 BK metselwerk | 90 | -912.047 | 11700 | 10658 | 10918 | no | Center | One or two joins disabled | Group: Model Group:dakspant 1A (members excluded):2011268
2049194 | V4 BK metselwerk | 7940 | 12108500 | 0.0650088 | 7940 | V4 BK metselwerk | 0 | -782 | 11700 | 10668 | 10918 | no | Top | Both joins enabled

# IfcBeam: btl_staal - HE(a-b-m):HEB120, btl_staal - HE(a-b-m):HEB120:1807879
In: V1 1e verd. (bk ruwe vloer)
Type - Other - Category: Structural Framing; Family Name: btl_staal - HE(a-b-m)
Type - Dimensions - bf: 120 mm; d: 120 mm; k: 23 mm; kr: 12 mm; tf: 11 mm; tw: 6.5 mm
Type - Identity Data - Description: HEB120; Model: ligger; Type Name: HEB120
Type - Materials and Finishes - Structural Material: Metal - Steel - S235 JRG2 (standaard)
Type - Structural - Section Shape: 0; A: 3400 mm2; W: 0.261739
Type - Pset_BeamCommon - IsExternal: no; LoadBearing: yes
Type - Pset_ReinforcementBarPitchOfBeam - Description: HEB120
Material: Metal - Steel - S235 JRG2 (standaard)
BaseQuantities - Length: 2248.22 mm; CrossSectionArea: 3277 mm2; OuterSurfaceArea: 1589495 mm2; GrossVolume: 0.00736743 m3; NetVolume: 0.00736743 m3
Pset_BeamCommon - Slope: 0 deg; Reference: HEB120; Span: 2413.62 mm
Pset_QuantityTakeOff - Reference: HEB120; sets with these values: 2
Other - Family: btl_staal - HE(a-b-m); End Extension Calculation: 3000 mm; Family and Type: btl_staal - HE(a-b-m): HEB120; Start Extension Calculation: 3000 mm; Type: HEB120; Type Id: 1662910
Constraints - Cross-Section Rotation: 0 deg; Reference Level: 03800 V1 1e verd; End Level Offset: 787.75 mm; Reference Level Elevation: 3800 mm; Start Level Offset: 787.75 mm
Construction - EindOplegging: -12.5 mm; StartOplegging: -12.5 mm
Dimensions - Elevation at Bottom: 4467.75 mm; Elevation at Top: 4587.75 mm; Length: 2413.62 mm; Volume: 0.00736743 m3
Identity Data - Has Association: yes
Phasing - Phase Created: 2. nieuwbouw
Structural - Structural Usage: Other; Stick Symbol Location: Center of Geometry; Start Attachment Type: End Elevation; End Attachment Type: End Elevation; Cut Length: 2248.22 mm
Geometric Position - Join Status: Both joins enabled; y Offset Value: 0 mm; yz Justification: Uniform; z Justification: Top; z Offset Value: 0 mm; y Justification: Origin; End Extension: 0 mm; Start Extension: 0 mm; End Join Cutback: 12.7 mm; Start Join Cutback: 12.7 mm

# IfcBeam: btl_staal - HE(a-b-m):HEB180 (4)
In: V3 dakvloer
Type - Other - Category: Structural Framing; Family Name: btl_staal - HE(a-b-m)
Type - Dimensions - bf: 180 mm; d: 180 mm; k: 29 mm; kr: 15 mm; tf: 14 mm; tw: 8.5 mm
Type - Identity Data - Description: HEB180; Model: ligger; Type Name: HEB180
Type - Materials and Finishes - Structural Material: Metal - Steel - S235 JRG2 (standaard)
Type - Structural - Section Shape: 0; A: 6530 mm2; W: 0.5021
Type - Pset_BeamCommon - IsExternal: no; LoadBearing: yes
Type - Pset_ReinforcementBarPitchOfBeam - Description: HEB180
Material: Metal - Steel - S235 JRG2 (standaard)
BaseQuantities - GrossSurfaceArea: 0 mm2
Pset_BeamCommon - Reference: HEB180
Pset_QuantityTakeOff - Reference: HEB180; sets with these values: 2
Other - Family: btl_staal - HE(a-b-m); End Extension Calculation: 3000 mm; Family and Type: btl_staal - HE(a-b-m): HEB180; Start Extension Calculation: 3000 mm; Type: HEB180; Type Id: 1985818
Constraints - Cross-Section Rotation: 0 deg; Reference Level: V3 dakvloer; Reference Level Elevation: 10840 mm
Construction - EindOplegging: -12.5 mm; StartOplegging: -12.5 mm
Identity Data - Has Association: no
Phasing - Phase Created: 2. nieuwbouw
Structural - Structural Usage: Other; Stick Symbol Location: Center of Geometry
Geometric Position - y Offset Value: 0 mm; yz Justification: Uniform; z Justification: Top; z Offset Value: 0 mm; Join Status: One or two joins disabled; y Justification: Origin; End Extension: 0 mm; Start Extension: 0 mm
Name (btl_staal - HE(a-b-m):HEB180:...) | NetVolume (m3) = Volume (m3) | Span (mm) = Length (mm) | Slope (deg) | End Level Offset (mm) | Start Level Offset (mm) | Cut Length (mm)
2013574 | 0.0184554 | 3080 | 20.9887 | 1050.63 | -52.5782 | 3050.33
2013580 | 0.0183998 | 2960.52 | 20.9888 | -20.2829 | 1040.13 | 2960.16
2031743 | 0.0184554 | 3080 | 20.9887 | 1050.63 | -52.5782 | 3050.33
2031749 | 0.0183998 | 2960.52 | 20.9888 | -20.2829 | 1040.13 | 2960.16

# IfcBeam: btl_staal - HE(a-b-m):HEB200 (3)
Type - Other - Category: Structural Framing; Family Name: btl_staal - HE(a-b-m)
Type - Dimensions - bf: 200 mm; d: 200 mm; k: 33 mm; kr: 18 mm; tf: 15 mm; tw: 9 mm
Type - Identity Data - Description: HEB 200; Model: ligger; Type Name: HEB200
Type - Materials and Finishes - Structural Material: Metal - Steel - S235 JRG2 (standaard)
Type - Structural - Section Shape: 0; A: 7810 mm2; W: 0.601148
Type - Pset_BeamCommon - IsExternal: no; LoadBearing: yes
Type - Pset_ReinforcementBarPitchOfBeam - Description: HEB 200
Material: Metal - Steel - S235 JRG2 (standaard)
BaseQuantities - CrossSectionArea: 7530 mm2
Pset_BeamCommon - Slope: 0 deg; Reference: HEB200
Pset_QuantityTakeOff - Reference: HEB200; sets with these values: 2
Other - Family: btl_staal - HE(a-b-m); Type: HEB200; End Extension Calculation: 3000 mm; Family and Type: btl_staal - HE(a-b-m): HEB200; Start Extension Calculation: 3000 mm; Type Id: 1576327
Constraints - Cross-Section Rotation: 0 deg
Construction - EindOplegging: -12.5 mm; StartOplegging: -12.5 mm
Identity Data - Has Association: yes
Phasing - Phase Created: 2. nieuwbouw
Structural - Structural Usage: Other; Stick Symbol Location: Center of Geometry
Geometric Position - y Offset Value: 0 mm; yz Justification: Uniform; z Justification: Top; z Offset Value: 0 mm; y Justification: Origin; End Extension: 0 mm; Start Extension: 0 mm
Name (btl_staal - HE(a-b-m):HEB200:...) | In | BaseQuantities, Length (mm) = Span (mm) = Dimensions, Length (mm) = Cut Length (mm) | OuterSurfaceArea (mm2) | GrossVolume (m3) = NetVolume (m3) = Volume (m3) | Reference Level | End Level Offset (mm) = Start Level Offset (mm) | Reference Level Elevation (mm) | Elevation at Bottom (mm) | Elevation at Top (mm) | Join Status
1861520 | V1 1e verd. (bk ruwe vloer) | 7604.75 | 8988815 | 0.0572638 | V1 1e verd. (bk ruwe vloer) | -60 | 3730 | 3470 | 3670 | Both joins enabled
1868773 | V2 2e verd. (bk ruwe vloer) | 7728.75 | 9135383 | 0.0581975 | V2 2e verd. (bk ruwe vloer) | -60 | 7530 | 7270 | 7470 | Both joins enabled
1922207 | V1 1e verd. (bk ruwe vloer) | 8736.59 | 10326648 | 0.0657865 | V1 1e verd. (bk ruwe vloer) | -200 | 3730 | 3330 | 3530 | One or two joins disabled | Identity Data - Comments: onder bestaande vloer

# IfcBeam: btl_staal - HE(a-b-m):HEB200 (S355) (5)
Type - Other - Category: Structural Framing; Family Name: btl_staal - HE(a-b-m)
Type - Dimensions - bf: 200 mm; d: 200 mm; k: 33 mm; kr: 18 mm; tf: 15 mm; tw: 9 mm
Type - Identity Data - Description: HEB200 (S355); Model: ligger; Type Name: HEB200 (S355)
Type - Materials and Finishes - Structural Material: Metal - Steel - S355 JR (standaard-geintegreerde liggers)
Type - Structural - Section Shape: 0; A: 7810 mm2; W: 0.601148
Type - Pset_BeamCommon - IsExternal: no; LoadBearing: yes
Type - Pset_ReinforcementBarPitchOfBeam - Description: HEB200 (S355)
Material: Metal - Steel - S355 JR (standaard-geintegreerde liggers)
BaseQuantities - CrossSectionArea: 7530 mm2
Pset_BeamCommon - Reference: HEB200 (S355)
Pset_QuantityTakeOff - Reference: HEB200 (S355); sets with these values: 2
Other - Family: btl_staal - HE(a-b-m); End Extension Calculation: 3000 mm; Family and Type: btl_staal - HE(a-b-m): HEB200 (S355); Start Extension Calculation: 3000 mm; Type: HEB200 (S355); Type Id: 1963991
Constraints - Cross-Section Rotation: 0 deg
Construction - EindOplegging: -12.5 mm; StartOplegging: -12.5 mm
Phasing - Phase Created: 2. nieuwbouw
Structural - Structural Usage: Other; Stick Symbol Location: Center of Geometry
Geometric Position - y Offset Value: 0 mm; yz Justification: Uniform; z Justification: Top; z Offset Value: 0 mm; y Justification: Origin; End Extension: 0 mm; Start Extension: 0 mm
Name (btl_staal - HE(a-b-m):HEB200 (S355):...) | In | BaseQuantities, Length (mm) = Cut Length (mm) | OuterSurfaceArea (mm2) | GrossVolume (m3) = NetVolume (m3) = Volume (m3) | Span (mm) = Dimensions, Length (mm) | Slope (deg) | End Level Offset (mm) | Reference Level | Reference Level Elevation (mm) | Start Level Offset (mm) | Has Association | Comments | Start Attachment Type = End Attachment Type | Join Status | End Join Cutback (mm) = Start Join Cutback (mm)
1612477 | V1 1e verd. (bk ruwe vloer) | 6405.63 | 7571449 | 0.0482344 | 6592.98 | 0.0869043 | 0 | V1 1e verd. (bk ruwe vloer) | 3730 | 10 | yes | Toog 15mm & brandwerend bekleden | End Elevation | Both joins enabled | 12.7
1613049 | V1 1e verd. (bk ruwe vloer) | 6405.63 | 7571449 | 0.0482344 | 6592.98 | 0.0869043 | 0 | V1 1e verd. (bk ruwe vloer) | 3730 | 10 | yes | Toog 15mm & brandwerend bekleden | End Elevation | Both joins enabled | 12.7
1641951 | V2 2e verd. (bk ruwe vloer) | 6405.63 | 7571449 | 0.0482344 | 6592.98 | 0.0869043 | 0 | V2 2e verd. (bk ruwe vloer) | 7530 | 10 | yes | Toog 15mm & brandwerend bekleden | End Elevation | Both joins enabled | 12.7
1641953 | V2 2e verd. (bk ruwe vloer) | 6405.63 | 7571449 | 0.0482344 | 6592.98 | 0.0869043 | 0 | V2 2e verd. (bk ruwe vloer) | 7530 | 10 | yes | Toog 15mm & brandwerend bekleden | End Elevation | Both joins enabled | 12.7
2059949 | V3 dakvloer | 22279 | 26333761 | 0.167761 | 22279 | 0 | 57.9531 | V3 dakvloer | 10840 | 57.9531 | no |  |  | One or two joins disabled | Dimensions - Elevation at Bottom: 10698 mm; Elevation at Top: 10898 mm

# IfcBeam: btl_staal - HE(a-b-m):HEB240 (2)
In: V4 BK metselwerk
Type - Other - Category: Structural Framing; Family Name: btl_staal - HE(a-b-m)
Type - Dimensions - bf: 240 mm; d: 240 mm; k: 38 mm; kr: 21 mm; tf: 17 mm; tw: 10 mm
Type - Identity Data - Description: HEB240; Model: ligger; Type Name: HEB240
Type - Materials and Finishes - Structural Material: Metal - Steel - S235 JRG2 (standaard)
Type - Structural - Section Shape: 0; A: 10600 mm2; W: 0.815913
Type - Pset_BeamCommon - IsExternal: no; LoadBearing: yes
Type - Pset_ReinforcementBarPitchOfBeam - Description: HEB240
Material: Metal - Steel - S235 JRG2 (standaard)
BaseQuantities - Length: 8085 mm; CrossSectionArea: 10220 mm2; OuterSurfaceArea: 11480700 mm2; GrossVolume: 0.0826287 m3; NetVolume: 0.0826287 m3
Pset_BeamCommon - Slope: 0 deg; Reference: HEB240; Span: 8085 mm
Pset_QuantityTakeOff - Reference: HEB240; sets with these values: 2
Other - Family: btl_staal - HE(a-b-m); End Extension Calculation: 3000 mm; Family and Type: btl_staal - HE(a-b-m): HEB240; Start Extension Calculation: 3000 mm; Type: HEB240; Type Id: 1612443
Constraints - Cross-Section Rotation: 0 deg; Reference Level: V4 BK metselwerk; End Level Offset: 240 mm; Reference Level Elevation: 11700 mm; Start Level Offset: 240 mm
Construction - EindOplegging: -12.5 mm; StartOplegging: -12.5 mm
Dimensions - Elevation at Bottom: 11700 mm; Elevation at Top: 11940 mm; Length: 8085 mm; Volume: 0.0826287 m3
Identity Data - Has Association: yes; Comments: Toog 20mm
Phasing - Phase Created: 2. nieuwbouw
Structural - Structural Usage: Other; Stick Symbol Location: Center of Geometry; Cut Length: 8085 mm
Geometric Position - y Offset Value: 0 mm; yz Justification: Uniform; z Justification: Top; z Offset Value: 0 mm; Join Status: One or two joins disabled; y Justification: Origin; End Extension: 0 mm; Start Extension: 0 mm
Name (btl_staal - HE(a-b-m):HEB240:...)
1734806
1735245

# IfcBeam: btl_staal - Hoeklijn 2.0:L 60X60X8 (40)
Type - Other - Category: Structural Framing; Family Name: btl_staal - Hoeklijn 2.0
Type - Dimensions - b: 60 mm; d: 60 mm; k: 16 mm; t: 8 mm; x: 28.22 mm; y: 28.22 mm
Type - Identity Data - Description: WVB L60X60X8; Model: ligger; Type Name: L 60X60X8
Type - Materials and Finishes - Structural Material: Metal - Steel - S235 JRG2 (standaard)
Type - Structural - Section Shape: 0; A: 1915 mm2; W: 0.147492
Type - Pset_BeamCommon - IsExternal: no; LoadBearing: yes
Type - Pset_ReinforcementBarPitchOfBeam - Description: WVB L60X60X8
Material: Metal - Steel - S235 JRG2 (standaard)
BaseQuantities - CrossSectionArea: 896 mm2
Pset_BeamCommon - Reference: L 60X60X8
Pset_QuantityTakeOff - Reference: L 60X60X8; sets with these values: 2
Other - Family: btl_staal - Hoeklijn 2.0; End Extension Calculation: 3000 mm; Family and Type: btl_staal - Hoeklijn 2.0: L 60X60X8; Start Extension Calculation: 3000 mm; Type: L 60X60X8; Type Id: 2106954
Construction - EindOplegging: -12.5 mm; StartOplegging: -12.5 mm
Identity Data - Has Association: no
Phasing - Phase Created: 2. nieuwbouw
Structural - Structural Usage: Other; Stick Symbol Location: Center of Geometry
Geometric Position - Join Status: Both joins enabled; y Offset Value: 0 mm; yz Justification: Uniform; z Justification: Top; z Offset Value: 0 mm; y Justification: Origin; End Extension: 0 mm; Start Extension: 0 mm
Name (btl_staal - Hoeklijn 2.0:L 60X60X8:...) | In | BaseQuantities, Length (mm) = Cut Length (mm) | OuterSurfaceArea (mm2) | GrossVolume (m3) = NetVolume (m3) = Volume (m3) | Span (mm) = Dimensions, Length (mm) | Slope (deg) | Cross-Section Rotation (deg) | Orientation | Reference Level | End Level Offset (mm) | Reference Level Elevation (mm) | Start Level Offset (mm) | Work Plane | Start Join Cutback (mm)
2047389 | V4 BK metselwerk | 4759.46 | 1142272 | 0.00426448 | 4995.25 | 14.4873 | 0 | Normal | V4 BK metselwerk | 372.416 | 11700 | -877.226 | Reference Plane : Dakvlak 1 | 12.7 | Geometric Position - End Join Cutback: 12.7 mm
2047494 | V4 BK metselwerk | 4752.34 | 1140562 | 0.0042581 | 4995.25 | 14.4873 | 0 | Normal | V4 BK metselwerk | 372.416 | 11700 | -877.226 | Reference Plane : Dakvlak 1 | 12.7 | Geometric Position - End Join Cutback: 12.7 mm
2047569 | V4 BK metselwerk | 4204.6 | 1009105 | 0.00376733 | 4180 | 17.0621 | 0 | Normal | V4 BK metselwerk | 367.624 | 11700 | -858.819 | Reference Plane : Dakvlak 1
2047590 | V4 BK metselwerk | 4240.74 | 1017777 | 0.0037997 | 4216.31 | 17.1716 | 0 | Normal | V4 BK metselwerk | 367.566 | 11700 | -877.237 | Reference Plane : Dakvlak 1
2047611 | V4 BK metselwerk | 4370.44 | 1048905 | 0.00391591 | 4400 | 16.3947 | 0 | Normal | V4 BK metselwerk | -874.289 | 11700 | 367.624 | Reference Plane : Dakvlak 1 | 12.7
2047629 | V4 BK metselwerk | 4114.97 | 987594 | 0.00368702 | 4431.9 | 16.3379 | 0 | Normal | V4 BK metselwerk | 372.416 | 11700 | -874.289 | Reference Plane : Dakvlak 1 | 12.7 | Geometric Position - End Join Cutback: 12.7 mm
2047684 | V4 BK metselwerk | 4121.8 | 989232 | 0.00369313 | 4440 | 16.3947 | 0 | Normal | V4 BK metselwerk | 373.443 | 11700 | -879.76 | Reference Plane : Dakvlak 1 | 12.7 | Geometric Position - End Join Cutback: 12.7 mm
2047698 | V4 BK metselwerk | 4401.7 | 1056408 | 0.00394392 | 4431.72 | 16.3922 | 0 | Normal | V4 BK metselwerk | -877.237 | 11700 | 373.443 | Reference Plane : Dakvlak 1 | Geometric Position - End Join Cutback: 12.7 mm
2047822 | V4 BK metselwerk | 4854.32 | 1165036 | 0.00434947 | 4995.25 | 14.4873 | 0 | Normal | V4 BK metselwerk | 372.416 | 11700 | -877.226 | <not associated> | 12.7
2047823 | V4 BK metselwerk | 4847.2 | 1163327 | 0.00434309 | 4995.25 | 14.4873 | 0 | Normal | V4 BK metselwerk | 372.416 | 11700 | -877.226 | <not associated> | 12.7
2049020 | V4 BK metselwerk | 4741.88 | 1138050 | 0.00424872 | 4975.65 | 14.4259 | 0 | Normal | V4 BK metselwerk | 370.201 | 11700 | -869.367 | Reference Plane : Dakvlak 3 | 12.7 | Geometric Position - End Join Cutback: 12.7 mm
2049045 | V4 BK metselwerk | 4751.28 | 1140306 | 0.00425714 | 4986.59 | 14.4603 | 0 | Normal | V4 BK metselwerk | 372.325 | 11700 | -872.871 | Reference Plane : Dakvlak 3 | 12.7 | Geometric Position - End Join Cutback: 12.7 mm
2049070 | V1 1e verd. (bk ruwe vloer) | 4836.78 | 1160827 | 0.00433375 | 4975.65 | 14.4259 | 0 | Normal | V1 1e verd. (bk ruwe vloer) | 8340.2 | 3730 | 7100.63 | <not associated> | 12.7
2049071 | V1 1e verd. (bk ruwe vloer) | 4846.15 | 1163076 | 0.00434215 | 4986.59 | 14.4603 | 0 | Normal | V1 1e verd. (bk ruwe vloer) | 8342.33 | 3730 | 7097.13 | <not associated> | 12.7
2049086 | V1 1e verd. (bk ruwe vloer) | 4792.26 | 1150142 | 0.00429386 | 5124.57 | 14.4259 | 0 | Normal | V1 1e verd. (bk ruwe vloer) | 8377.3 | 3730 | 7100.63 | Reference Plane : Dakvlak 3 | 12.7 | Geometric Position - End Join Cutback: 12.7 mm
2049087 | V1 1e verd. (bk ruwe vloer) | 4874.42 | 1169860 | 0.00436748 | 5135.84 | 14.4603 | 0 | Normal | V1 1e verd. (bk ruwe vloer) | 8342.33 | 3730 | 7059.86 | Reference Plane : Dakvlak 3 | 12.7 | Geometric Position - End Join Cutback: 12.7 mm
2049089 | V1 1e verd. (bk ruwe vloer) | 4792.26 | 1150142 | 0.00429386 | 5124.57 | 14.4259 | 0 | Normal | V1 1e verd. (bk ruwe vloer) | 8377.3 | 3730 | 7100.63 | <not associated> | 12.7 | Geometric Position - End Join Cutback: 12.7 mm
2049090 | V1 1e verd. (bk ruwe vloer) | 4969.29 | 1192629 | 0.00445248 | 5135.84 | 14.4603 | 0 | Normal | V1 1e verd. (bk ruwe vloer) | 8342.33 | 3730 | 7059.86 | <not associated> | 12.7
2049104 | V1 1e verd. (bk ruwe vloer) | 4759.27 | 1142226 | 0.00426431 | 4975.65 | 14.4259 | 0 | Normal | V1 1e verd. (bk ruwe vloer) | 8340.2 | 3730 | 7100.63 | Reference Plane : Dakvlak 3 | 12.7 | Geometric Position - End Join Cutback: 12.7 mm
2049105 | V1 1e verd. (bk ruwe vloer) | 4768.71 | 1144491 | 0.00427277 | 4986.59 | 14.4603 | 0 | Normal | V1 1e verd. (bk ruwe vloer) | 8342.33 | 3730 | 7097.13 | Reference Plane : Dakvlak 3 | 12.7 | Geometric Position - End Join Cutback: 12.7 mm
2049106 | V1 1e verd. (bk ruwe vloer) | 4854.18 | 1165002 | 0.00434934 | 4975.65 | 14.4259 | 0 | Normal | V1 1e verd. (bk ruwe vloer) | 8340.2 | 3730 | 7100.63 | <not associated> | 12.7
2049107 | V1 1e verd. (bk ruwe vloer) | 4863.59 | 1167261 | 0.00435777 | 4986.59 | 14.4603 | 0 | Normal | V1 1e verd. (bk ruwe vloer) | 8342.33 | 3730 | 7097.13 | <not associated> | 12.7
2049123 | V1 1e verd. (bk ruwe vloer) | 4896.68 | 1175204 | 0.00438743 | 4975.65 | 14.4259 | 0 | Normal | V1 1e verd. (bk ruwe vloer) | 8340.2 | 3730 | 7100.63 | Reference Plane : Dakvlak 3 | Geometric Position - End Join Cutback: 12.7 mm
2049124 | V1 1e verd. (bk ruwe vloer) | 4632.2 | 1111727 | 0.00415045 | 5004.02 | 14.4603 | 0 | Normal | V1 1e verd. (bk ruwe vloer) | 8346.68 | 3730 | 7097.13 | Reference Plane : Dakvlak 3 | 12.7 | Geometric Position - End Join Cutback: 12.7 mm
2049125 | V1 1e verd. (bk ruwe vloer) | 4771.9 | 1145255 | 0.00427562 | 4993.04 | 14.4259 | 0 | Normal | V1 1e verd. (bk ruwe vloer) | 8340.2 | 3730 | 7096.3 | <not associated> | 12.7
2049126 | V1 1e verd. (bk ruwe vloer) | 4632.2 | 1111727 | 0.00415045 | 5004.02 | 14.4603 | 0 | Normal | V1 1e verd. (bk ruwe vloer) | 8346.68 | 3730 | 7097.13 | <not associated> | 12.7 | Geometric Position - End Join Cutback: 12.7 mm
2049140 | V1 1e verd. (bk ruwe vloer) | 4204.6 | 1009105 | 0.00376733 | 4180 | 17.0621 | 0 | Normal | V1 1e verd. (bk ruwe vloer) | 8337.62 | 3730 | 7111.18 | <not associated>
2049141 | V1 1e verd. (bk ruwe vloer) | 4240.74 | 1017777 | 0.0037997 | 4216.31 | 17.1716 | 0 | Normal | V1 1e verd. (bk ruwe vloer) | 8337.57 | 3730 | 7092.76 | <not associated>
2049142 | V1 1e verd. (bk ruwe vloer) | 4370.44 | 1048905 | 0.00391591 | 4400 | 16.3947 | 0 | Normal | V1 1e verd. (bk ruwe vloer) | 7095.71 | 3730 | 8337.62 | <not associated> | 12.7
2049143 | V1 1e verd. (bk ruwe vloer) | 4114.97 | 987594 | 0.00368702 | 4431.9 | 16.3379 | 0 | Normal | V1 1e verd. (bk ruwe vloer) | 8342.42 | 3730 | 7095.71 | <not associated> | 12.7 | Geometric Position - End Join Cutback: 12.7 mm
2049144 | V1 1e verd. (bk ruwe vloer) | 4121.8 | 989232 | 0.00369313 | 4440 | 16.3947 | 0 | Normal | V1 1e verd. (bk ruwe vloer) | 8343.44 | 3730 | 7090.24 | <not associated> | 12.7 | Geometric Position - End Join Cutback: 12.7 mm
2049145 | V1 1e verd. (bk ruwe vloer) | 4401.7 | 1056408 | 0.00394392 | 4431.72 | 16.3922 | 0 | Normal | V1 1e verd. (bk ruwe vloer) | 7092.76 | 3730 | 8343.44 | <not associated> | Geometric Position - End Join Cutback: 12.7 mm
2049161 | V1 1e verd. (bk ruwe vloer) | 4759.46 | 1142272 | 0.00426448 | 4986.06 | 14.4873 | 0 | Normal | V1 1e verd. (bk ruwe vloer) | 8340.12 | 3730 | 7092.77 | <not associated> | 12.7 | Geometric Position - End Join Cutback: 12.7 mm
2049162 | V1 1e verd. (bk ruwe vloer) | 4752.34 | 1140562 | 0.0042581 | 4986.06 | 14.4873 | 0 | Normal | V1 1e verd. (bk ruwe vloer) | 8340.12 | 3730 | 7092.77 | <not associated> | 12.7 | Geometric Position - End Join Cutback: 12.7 mm
2049164 | V1 1e verd. (bk ruwe vloer) | 4854.32 | 1165036 | 0.00434947 | 4986.06 | 14.4873 | 0 | Normal | V1 1e verd. (bk ruwe vloer) | 8340.12 | 3730 | 7092.77 | <not associated> | 12.7
2049165 | V1 1e verd. (bk ruwe vloer) | 4847.2 | 1163327 | 0.00434309 | 4986.06 | 14.4873 | 0 | Normal | V1 1e verd. (bk ruwe vloer) | 8340.12 | 3730 | 7092.77 | <not associated> | 12.7
2124958 | V3 dakvloer | 3819.65 | 916715 | 0.0034224 | 3819.65 | 0 | 0 |  | V3 dakvloer | 0 | 10840 | 0 | Dimensions - Elevation at Bottom: 10780 mm; Elevation at Top: 10840 mm
2125387 | V3 dakvloer | 3805.79 | 913390 | 0.00340999 | 3805.79 | 0 | 180 |  | V3 dakvloer | -120 | 10840 | -120 | Dimensions - Elevation at Bottom: 10720 mm; Elevation at Top: 10780 mm
2125494 | V3 dakvloer | 3819.65 | 916715 | 0.0034224 | 3819.65 | 0 | 0 |  | V3 dakvloer | 0 | 10840 | 0 | Dimensions - Elevation at Bottom: 10780 mm; Elevation at Top: 10840 mm
2125495 | V3 dakvloer | 3805.79 | 913390 | 0.00340999 | 3805.79 | 0 | 180 |  | V3 dakvloer | -120 | 10840 | -120 | Dimensions - Elevation at Bottom: 10720 mm; Elevation at Top: 10780 mm

# IfcBeam: btl_staal - Hoeklijn 2.0:L100x100x10 (21)
Type - Other - Category: Structural Framing; Family Name: btl_staal - Hoeklijn 2.0
Type - Dimensions - b: 100 mm; d: 100 mm; k: 16 mm; t: 10 mm; x: 28.22 mm; y: 28.22 mm
Type - Identity Data - Description: geveldrager; Model: ligger; Type Name: L100x100x10
Type - Materials and Finishes - Structural Material: Metal - Steel - S235 JRG2 (standaard)
Type - Structural - Section Shape: 0; A: 1915 mm2; W: 0.147492
Type - Pset_BeamCommon - IsExternal: no; LoadBearing: yes
Type - Pset_ReinforcementBarPitchOfBeam - Description: geveldrager
Material: Metal - Steel - S235 JRG2 (standaard)
BaseQuantities - CrossSectionArea: 1900 mm2
Pset_BeamCommon - Slope: 0 deg; Reference: L100x100x10
Pset_QuantityTakeOff - Reference: L100x100x10; sets with these values: 2
Other - Family: btl_staal - Hoeklijn 2.0; End Extension Calculation: 3000 mm; Family and Type: btl_staal - Hoeklijn 2.0: L100x100x10; Start Extension Calculation: 3000 mm; Type: L100x100x10; Type Id: 1683194
Constraints - Cross-Section Rotation: 0 deg
Construction - EindOplegging: -12.5 mm; StartOplegging: -12.5 mm
Identity Data - Has Association: no
Phasing - Phase Created: 2. nieuwbouw
Structural - Structural Usage: Other; Stick Symbol Location: Center of Geometry
Geometric Position - Join Status: Both joins enabled; y Offset Value: 0 mm; yz Justification: Uniform; z Justification: Top; z Offset Value: 0 mm; y Justification: Origin; End Extension: 0 mm; Start Extension: 0 mm
Name (btl_staal - Hoeklijn 2.0:L100x100x10:...) | In | BaseQuantities, Length (mm) = Span (mm) = Dimensions, Length (mm) = Cut Length (mm) | OuterSurfaceArea (mm2) | GrossVolume (m3) = NetVolume (m3) = Volume (m3) | Reference Level | End Level Offset (mm) = Start Level Offset (mm) | Reference Level Elevation (mm) | Elevation at Bottom (mm) | Elevation at Top (mm)
2067165 | V1 1e verd. (bk ruwe vloer) | 5700.3 | 2280120 | 0.0108306 | V1 1e verd. (bk ruwe vloer) | -932 | 3730 | 2698 | 2798
2067406 | V1 1e verd. (bk ruwe vloer) | 5700.3 | 2280120 | 0.0108306 | V1 1e verd. (bk ruwe vloer) | -932 | 3730 | 2698 | 2798
2067424 | V1 1e verd. (bk ruwe vloer) | 5700.3 | 2280120 | 0.0108306 | V1 1e verd. (bk ruwe vloer) | -932 | 3730 | 2698 | 2798
2067434 | V1 1e verd. (bk ruwe vloer) | 5700.3 | 2280120 | 0.0108306 | V1 1e verd. (bk ruwe vloer) | -932 | 3730 | 2698 | 2798
2067495 | V2 2e verd. (bk ruwe vloer) | 5700.3 | 2280120 | 0.0108306 | V2 2e verd. (bk ruwe vloer) | -932 | 7530 | 6498 | 6598
2067496 | V2 2e verd. (bk ruwe vloer) | 5700.3 | 2280120 | 0.0108306 | V2 2e verd. (bk ruwe vloer) | -932 | 7530 | 6498 | 6598
2067497 | V2 2e verd. (bk ruwe vloer) | 5700.3 | 2280120 | 0.0108306 | V2 2e verd. (bk ruwe vloer) | -932 | 7530 | 6498 | 6598
2067498 | V2 2e verd. (bk ruwe vloer) | 5700.3 | 2280120 | 0.0108306 | V2 2e verd. (bk ruwe vloer) | -932 | 7530 | 6498 | 6598
2067508 | KDV nok | 5700.3 | 2280120 | 0.0108306 | V3 ok vloer | 18 | 10380 | 10298 | 10398
2067509 | KDV nok | 5700.3 | 2280120 | 0.0108306 | V3 ok vloer | 18 | 10380 | 10298 | 10398
2067510 | KDV nok | 5700.3 | 2280120 | 0.0108306 | V3 ok vloer | 18 | 10380 | 10298 | 10398
2067511 | KDV nok | 5700.3 | 2280120 | 0.0108306 | V3 ok vloer | 18 | 10380 | 10298 | 10398
2067836 | V1 1e verd. (bk ruwe vloer) | 4104.2 | 1641680 | 0.00779798 | V1 1e verd. (bk ruwe vloer) | -932 | 3730 | 2698 | 2798
2068072 | V1 1e verd. (bk ruwe vloer) | 5700.33 | 2280130 | 0.0108306 | V1 1e verd. (bk ruwe vloer) | -932 | 3730 | 2698 | 2798
2068134 | V1 1e verd. (bk ruwe vloer) | 5700.33 | 2280130 | 0.0108306 | V1 1e verd. (bk ruwe vloer) | -932 | 3730 | 2698 | 2798
2068409 | V1 1e verd. (bk ruwe vloer) | 5696.29 | 2278518 | 0.010823 | V1 1e verd. (bk ruwe vloer) | -932 | 3730 | 2698 | 2798
2068558 | V1 1e verd. (bk ruwe vloer) | 5696.29 | 2278518 | 0.010823 | V1 1e verd. (bk ruwe vloer) | -932 | 3730 | 2698 | 2798
2068572 | V1 1e verd. (bk ruwe vloer) | 5696.29 | 2278518 | 0.010823 | V1 1e verd. (bk ruwe vloer) | -932 | 3730 | 2698 | 2798
2068580 | V1 1e verd. (bk ruwe vloer) | 4104.22 | 1641687 | 0.00779801 | V1 1e verd. (bk ruwe vloer) | -932 | 3730 | 2698 | 2798
2068965 | V1 1e verd. (bk ruwe vloer) | 5700.3 | 2280120 | 0.0108306 | V1 1e verd. (bk ruwe vloer) | -932 | 3730 | 2698 | 2798
2069010 | V1 1e verd. (bk ruwe vloer) | 5696.29 | 2278518 | 0.010823 | V1 1e verd. (bk ruwe vloer) | -932 | 3730 | 2698 | 2798

# IfcBeam: btl_staal - Hoeklijn 2.0:L120x120x12 (2)
In: V1 1e verd. (bk ruwe vloer)
Type - Other - Category: Structural Framing; Family Name: btl_staal - Hoeklijn 2.0
Type - Dimensions - b: 120 mm; d: 120 mm; k: 18.5 mm; t: 12 mm; x: 34 mm; y: 34 mm
Type - Identity Data - Model: ligger; Type Name: L120x120x12
Type - Materials and Finishes - Structural Material: Metal - Steel - S235 JRG2 (standaard)
Type - Structural - Section Shape: 0; A: 2754 mm2; W: 0.21202
Type - Pset_BeamCommon - IsExternal: no; LoadBearing: yes
Material: Metal - Steel - S235 JRG2 (standaard)
BaseQuantities - CrossSectionArea: 2736 mm2
Pset_BeamCommon - Slope: 0 deg; Reference: L120x120x12
Pset_QuantityTakeOff - Reference: L120x120x12; sets with these values: 2
Other - End Extension Calculation: 3000 mm; Family: btl_staal - Hoeklijn 2.0; Family and Type: btl_staal - Hoeklijn 2.0: L120x120x12; Start Extension Calculation: 3000 mm; Type: L120x120x12; Type Id: 1662901
Constraints - Cross-Section Rotation: 0 deg; Reference Level: V1 1e verd. (bk ruwe vloer); Reference Level Elevation: 3730 mm
Construction - EindOplegging: -12.5 mm; StartOplegging: -12.5 mm
Identity Data - Has Association: yes
Phasing - Phase Created: 2. nieuwbouw
Structural - Structural Usage: Other; Stick Symbol Location: Center of Geometry
Geometric Position - Join Status: Both joins enabled; y Offset Value: 0 mm; yz Justification: Uniform; z Justification: Top; z Offset Value: 0 mm; y Justification: Origin; End Extension: 0 mm; Start Extension: 0 mm
Name (btl_staal - Hoeklijn 2.0:L120x120x12:...) | BaseQuantities, Length (mm) = Span (mm) = Dimensions, Length (mm) = Cut Length (mm) | OuterSurfaceArea (mm2) | GrossVolume (m3) = NetVolume (m3) = Volume (m3) | End Level Offset (mm) = Start Level Offset (mm) | Elevation at Bottom (mm) | Elevation at Top (mm)
1663107 | 1135.56 | 545069 | 0.00310689 | 28 | 3638 | 3758
1663956 | 837.985 | 402233 | 0.00229273 | -1872 | 1738 | 1858

# IfcBeam: btl_staal - Hoeklijn 2.0:L150x150x12 (3)
In: V1 1e verd. (bk ruwe vloer)
Type - Other - Category: Structural Framing; Family Name: btl_staal - Hoeklijn 2.0
Type - Dimensions - b: 150 mm; d: 150 mm; k: 16.5 mm; t: 12 mm; x: 23.36 mm; y: 48 mm
Type - Identity Data - Description: Hoeklijn 150x150x12; Model: ligger; Type Name: L150x150x12
Type - Materials and Finishes - Structural Material: Metal - Steel - S235 JRG2 (standaard)
Type - Structural - Section Shape: 0; A: 2418 mm2; W: 0.18613
Type - Pset_BeamCommon - IsExternal: no; LoadBearing: yes
Type - Pset_ReinforcementBarPitchOfBeam - Description: Hoeklijn 150x150x12
Material: Metal - Steel - S235 JRG2 (standaard)
BaseQuantities - CrossSectionArea: 3456 mm2
Pset_BeamCommon - Slope: 0 deg; Reference: L150x150x12
Pset_QuantityTakeOff - Reference: L150x150x12; sets with these values: 2
Other - Family: btl_staal - Hoeklijn 2.0; End Extension Calculation: 3000 mm; Family and Type: btl_staal - Hoeklijn 2.0: L150x150x12; Start Extension Calculation: 3000 mm; Type: L150x150x12; Type Id: 1867773
Constraints - Cross-Section Rotation: 0 deg
Construction - EindOplegging: -12.5 mm; StartOplegging: -12.5 mm
Identity Data - Has Association: yes
Phasing - Phase Created: 2. nieuwbouw
Structural - Structural Usage: Other; Stick Symbol Location: Center of Geometry
Geometric Position - y Offset Value: 0 mm; yz Justification: Uniform; z Justification: Top; z Offset Value: 0 mm; Join Status: One or two joins disabled; y Justification: Origin; End Extension: 0 mm; Start Extension: 0 mm
Name (btl_staal - Hoeklijn 2.0:L150x150x12:...) | BaseQuantities, Length (mm) = Cut Length (mm) | OuterSurfaceArea (mm2) | GrossVolume (m3) = NetVolume (m3) = Volume (m3) | Span (mm) = Dimensions, Length (mm) | Reference Level | End Level Offset (mm) = Start Level Offset (mm) | Reference Level Elevation (mm) | Elevation at Bottom (mm) | Elevation at Top (mm)
1683242 | 1323.48 | 794087 | 0.00457394 | 1486.18 | V1 1e verd. (bk ruwe vloer) | -2280 | 3730 | 1300 | 1450 | Geometric Position - Start Join Cutback: 12.7 mm
1868439 | 1311.18 | 786707 | 0.00453143 | 1311.18 | 03800 V1 1e verd | 1450 | 3800 | 5100 | 5250
1970536 | 920 | 552000 | 0.00317952 | 920 | V1 1e verd. (bk ruwe vloer) | -1900.3 | 3730 | 1679.7 | 1829.7

# IfcBeam: btl_staal - Hoeklijn 2.0:L260x180x10 (4)
In: V1 1e verd. (bk ruwe vloer)
Type - Other - Category: Structural Framing; Family Name: btl_staal - Hoeklijn 2.0
Type - Dimensions - b: 180 mm; d: 260 mm; k: 16.5 mm; t: 10 mm; x: 23.36 mm; y: 48 mm
Type - Identity Data - Model: ligger; Type Name: L260x180x10
Type - Materials and Finishes - Structural Material: Metal - Steel - S235 JRG2 (standaard)
Type - Structural - Section Shape: 0; A: 2418 mm2; W: 0.18613
Type - Pset_BeamCommon - IsExternal: no; LoadBearing: yes
Material: Metal - Steel - S235 JRG2 (standaard)
BaseQuantities - Length: 80 mm; CrossSectionArea: 4300 mm2; OuterSurfaceArea: 70400 mm2; GrossVolume: 0.000344 m3; NetVolume: 0.000344 m3
Pset_BeamCommon - Slope: 0 deg; Reference: L260x180x10; Span: 80 mm
Pset_QuantityTakeOff - Reference: L260x180x10; sets with these values: 2
Other - Family: btl_staal - Hoeklijn 2.0; End Extension Calculation: 3000 mm; Family and Type: btl_staal - Hoeklijn 2.0: L260x180x10; Start Extension Calculation: 3000 mm; Type: L260x180x10; Type Id: 1830118
Constraints - Cross-Section Rotation: 0 deg; End Level Offset: 0 mm; Orientation: Normal; Start Level Offset: 0 mm; Reference Level: V1 1e verd. (bk ruwe vloer); Reference Level Elevation: 3730 mm; Work Plane: Level : V1 1e verd. (bk ruwe vloer)
Construction - EindOplegging: -12.5 mm; StartOplegging: -12.5 mm
Dimensions - Elevation at Bottom: 3470 mm; Elevation at Top: 3730 mm; Length: 80 mm; Volume: 0.000344 m3
Identity Data - Has Association: yes
Phasing - Phase Created: 2. nieuwbouw
Structural - Structural Usage: Other; Stick Symbol Location: Center of Geometry; Cut Length: 80 mm
Geometric Position - Join Status: Both joins enabled; y Offset Value: 0 mm; yz Justification: Uniform; z Justification: Top; z Offset Value: 0 mm; y Justification: Origin; End Extension: 0 mm; Start Extension: 0 mm
Name (btl_staal - Hoeklijn 2.0:L260x180x10:...) | Group
1830191 | Model Group:koppeling stalen kolom aan ligget tpv vide (members excluded):1831325
1831374 | Model Group:koppeling stalen kolom aan ligget tpv vide (members excluded):1831406
1831445 | Model Group:koppeling stalen kolom aan ligget tpv vide (members excluded):1831465
1831516 | Model Group:koppeling stalen kolom aan ligget tpv vide (members excluded):1831536

# IfcBeam: btl_staal - IPE:IPE160 (32)
Type - Other - Category: Structural Framing; Family Name: btl_staal - IPE
Type - Dimensions - bf: 82 mm; d: 160 mm; k: 16.4 mm; tf: 7.4 mm; tr: 9 mm; tw: 5 mm
Type - Identity Data - Description: IPE160; Model: ligger; Type Name: IPE160
Type - Materials and Finishes - Structural Material: Metal - Steel - S235 JRG2 (standaard)
Type - Structural - Section Shape: 0; A: 2009 mm2; W: 0.154651
Type - Pset_BeamCommon - IsExternal: no; LoadBearing: yes
Type - Pset_ReinforcementBarPitchOfBeam - Description: IPE160
Material: Metal - Steel - S235 JRG2 (standaard)
BaseQuantities - CrossSectionArea: 1939.6 mm2
Pset_BeamCommon - Reference: IPE160
Pset_QuantityTakeOff - Reference: IPE160; sets with these values: 2
Other - End Extension Calculation: 3000 mm; Family: btl_staal - IPE; Family and Type: btl_staal - IPE: IPE160; Start Extension Calculation: 3000 mm; Type: IPE160; Type Id: 1818942
Constraints - Cross-Section Rotation: 0 deg
Construction - EindOplegging: -12.5 mm; StartOplegging: -12.5 mm
Identity Data - Has Association: yes
Phasing - Phase Created: 2. nieuwbouw
Structural - Structural Usage: Other; Stick Symbol Location: Center of Geometry
Geometric Position - y Offset Value: 0 mm; yz Justification: Uniform; z Justification: Top; z Offset Value: 0 mm; y Justification: Origin; End Extension: 0 mm; Start Extension: 0 mm
Name (btl_staal - IPE:IPE160:...) | In | BaseQuantities, Length (mm) = Cut Length (mm) | OuterSurfaceArea (mm2) | GrossVolume (m3) | NetVolume (m3) = Volume (m3) | Span (mm) = Dimensions, Length (mm) | Slope (deg) | Start Level Offset (mm) | End Level Offset (mm) | Reference Level | Reference Level Elevation (mm) | Join Status | Elevation at Bottom (mm) | Elevation at Top (mm)
1819181 | F1 begg (bk ruwe vloer) | 2625.9 | 1675322 | 0.00509319 | 0.00501446 | 2763.36 | 36.1968 | 0 | 1631.93 | 00000 begg | 0 | Both joins enabled | Geometric Position - End Join Cutback: 0 mm; Group: Model Group:tribune spant (members excluded):1820483
1819208 | F1 begg (bk ruwe vloer) | 1099.87 | 701720 | 0.00213332 | 0.00213332 | 1099.87 | 0 | 2952.6 | 2952.6 | F2 (bk fundering) | -480 | Both joins enabled | 2312.6 | 2472.6 | Group: Model Group:tribune spant (members excluded):1820483
1820520 | F1 begg (bk ruwe vloer) | 2625.9 | 1675322 | 0.00509319 | 0.00501446 | 2763.36 | 36.1968 | 0 | 1631.93 | 00000 begg | 0 | Both joins enabled | Geometric Position - End Join Cutback: 0 mm; Group: Model Group:tribune spant (members excluded):1820524
1820522 | KDV V1 1e verd. (bk ruwe vloer) | 1099.87 | 701720 | 0.00213332 | 0.0020826 | 1099.87 | 0 | -997.4 | -997.4 | V1 ok vloer | 3470 | Both joins enabled | 2312.6 | 2472.6 | Group: Model Group:tribune spant (members excluded):1820524
1820542 | F1 begg (bk ruwe vloer) | 2625.9 | 1675322 | 0.00509319 | 0.00501446 | 2763.36 | 36.1968 | 0 | 1631.93 | 00000 begg | 0 | Both joins enabled | Geometric Position - End Join Cutback: 0 mm; Group: Model Group:tribune spant (members excluded):1820546
1820544 | KDV V1 1e verd. (bk ruwe vloer) | 1099.87 | 701720 | 0.00213332 | 0.0020826 | 1099.87 | 0 | -997.4 | -997.4 | V1 ok vloer | 3470 | Both joins enabled | 2312.6 | 2472.6 | Group: Model Group:tribune spant (members excluded):1820546
1820582 | V1 1e verd. (bk ruwe vloer) | 6810.11 | 4344852 | 0.0132089 | 0.0132089 | 6810.11 | 0 | -1257.4 | -1257.4 | V1 1e verd. (bk ruwe vloer) | 3730 | One or two joins disabled | 2312.6 | 2472.6
1821838 | F1 begg (bk ruwe vloer) | 2873.6 | 1833357 | 0.00557363 | 0.00536007 | 2904.04 | 35.0319 | 472.047 | 2139.06 | F2 (bk fundering) | -480 | Both joins enabled | Geometric Position - End Join Cutback: 0 mm
1821840 | F1 begg (bk ruwe vloer) | 1059.67 | 676067 | 0.00205533 | 0.00200636 | 1034.42 | 0 | 2952.6 | 2952.6 | F2 (bk fundering) | -480 | One or two joins disabled | 2312.6 | 2472.6
1821888 | V1 1e verd. (bk ruwe vloer) | 903.285 | 576296 | 0.00175201 | 0.00175201 | 915.99 | 0 | -1257.4 | -1257.4 | V1 1e verd. (bk ruwe vloer) | 3730 | Both joins enabled | 2312.6 | 2472.6 | Geometric Position - Start Join Cutback: 12.7 mm
1824940 | V1 1e verd. (bk ruwe vloer) | 1879.17 | 1198911 | 0.00364484 | 0.00364484 | 1910.14 | 0 | -1257.4 | -1257.4 | V1 1e verd. (bk ruwe vloer) | 3730 | One or two joins disabled | 2312.6 | 2472.6 | Geometric Position - Start Join Cutback: 0 mm
1825043 | V1 1e verd. (bk ruwe vloer) | 1518.95 | 969091 | 0.00294616 | 0.00294616 | 1609.37 | 0 | -1257.4 | -1257.4 | V1 1e verd. (bk ruwe vloer) | 3730 | Both joins enabled | 2312.6 | 2472.6 | Geometric Position - End Join Cutback: 0 mm; Start Join Cutback: 0 mm
1825166 | V1 1e verd. (bk ruwe vloer) | 1518.95 | 969091 | 0.00294616 | 0.00294616 | 1590.73 | 0 | -1257.4 | -1257.4 | V1 1e verd. (bk ruwe vloer) | 3730 | Both joins enabled | 2312.6 | 2472.6 | Geometric Position - End Join Cutback: 0 mm; Start Join Cutback: 0 mm
1825341 | KDV V1 1e verd. (bk ruwe vloer) | 918.052 | 585717 | 0.00178065 | 0.00178065 | 918.052 | 0 | -1674.78 | -1674.78 | V1 ok vloer | 3470 | One or two joins disabled | 1635.22 | 1795.22
1825343 | KDV V1 1e verd. (bk ruwe vloer) | 2064.77 | 1317320 | 0.00400482 | 0.00400482 | 2095.74 | 0 | -1674.78 | -1674.78 | V1 ok vloer | 3470 | Both joins enabled | 1635.22 | 1795.22 | Geometric Position - Start Join Cutback: 0 mm
1825345 | KDV V1 1e verd. (bk ruwe vloer) | 1518.95 | 969091 | 0.00294616 | 0.00294616 | 1609.37 | 0 | -1674.78 | -1674.78 | V1 ok vloer | 3470 | Both joins enabled | 1635.22 | 1795.22 | Geometric Position - End Join Cutback: 0 mm; Start Join Cutback: 0 mm
1825347 | KDV V1 1e verd. (bk ruwe vloer) | 1518.95 | 969091 | 0.00294616 | 0.00294616 | 1600.95 | 0 | -1674.78 | -1674.78 | V1 ok vloer | 3470 | Both joins enabled | 1635.22 | 1795.22 | Geometric Position - End Join Cutback: 0 mm; Start Join Cutback: 0 mm
1825709 | F1 begg (bk ruwe vloer) | 2719.55 | 1735074 | 0.00527484 | 0.00505353 | 2776.91 | 35.0357 | 447.073 | 2041.26 | F2 (bk fundering) | -480 | Both joins enabled | Geometric Position - End Join Cutback: 0 mm
1825711 | F1 begg (bk ruwe vloer) | 1044.92 | 666660 | 0.00202673 | 0.00197775 | 1044.92 | 0 | 2952.6 | 2952.6 | F2 (bk fundering) | -480 | One or two joins disabled | 2312.6 | 2472.6
1827109 | V1 1e verd. (bk ruwe vloer) | 854.623 | 545249 | 0.00165763 | 0.00165763 | 956.573 | 0 | -1257.4 | -1257.4 | V1 1e verd. (bk ruwe vloer) | 3730 | Both joins enabled | 2312.6 | 2472.6 | Geometric Position - End Join Cutback: 0 mm; Start Join Cutback: 0 mm
1828013 | KDV V1 1e verd. (bk ruwe vloer) | 1046.94 | 667951 | 0.00203065 | 0.00203065 | 1099.77 | 0 | -1674.78 | -1674.78 | V1 ok vloer | 3470 | One or two joins disabled | 1635.22 | 1795.22 | Geometric Position - End Join Cutback: 0 mm
1828206 | F1 begg (bk ruwe vloer) | 2561.49 | 1634228 | 0.00496826 | 0.00474695 | 2618.84 | 35.0357 | 447.073 | 1950.52 | F2 (bk fundering) | -480 | Both joins enabled | Geometric Position - End Join Cutback: 0 mm
1828208 | F1 begg (bk ruwe vloer) | 877.722 | 559987 | 0.00170243 | 0.00165345 | 877.722 | 0 | 2952.6 | 2952.6 | F2 (bk fundering) | -480 | One or two joins disabled | 2312.6 | 2472.6
1887897 | F1 begg (bk ruwe vloer) | 121.178 | 77311.7 | 0.000235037 | 0.000156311 | 140 | 90 | 100 | -40 | 00000 begg | 0 | One or two joins disabled | Group: Model Group:tribune spant (members excluded):1820483
1888125 | F1 begg (bk ruwe vloer) | 121.178 | 77311.7 | 0.000235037 | 0.000156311 | 140 | 90 | 170 | 30 | F1 begg (bk ruwe vloer) | -70 | One or two joins disabled | Group: Model Group:tribune spant (members excluded):1820524
1888152 | F1 begg (bk ruwe vloer) | 121.178 | 77311.7 | 0.000235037 | 0.000156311 | 140 | 90 | 170 | 30 | F1 begg (bk ruwe vloer) | -70 | One or two joins disabled | Group: Model Group:tribune spant (members excluded):1820546
1906077 | F1 begg (bk ruwe vloer) | 1745.53 | 1113647 | 0.00338563 | 0.00333665 | 1745.53 | 35.0357 | 1950.52 | 2952.6 | F2 (bk fundering) | -480 | Both joins enabled
1906103 | F1 begg (bk ruwe vloer) | 1587.46 | 1012800 | 0.00307904 | 0.00303006 | 1587.46 | 35.0357 | 2041.26 | 2952.6 | F2 (bk fundering) | -480 | Both joins enabled
1906167 | F1 begg (bk ruwe vloer) | 1423.51 | 908200 | 0.00276104 | 0.00271033 | 1423.51 | 36.1968 | 1631.93 | 2472.6 | 00000 begg | 0 | Both joins enabled | Group: Model Group:tribune spant (members excluded):1820483
1906268 | F1 begg (bk ruwe vloer) | 1423.51 | 908200 | 0.00276104 | 0.00271033 | 1423.51 | 36.1968 | 1631.93 | 2472.6 | 00000 begg | 0 | Both joins enabled | Group: Model Group:tribune spant (members excluded):1820524
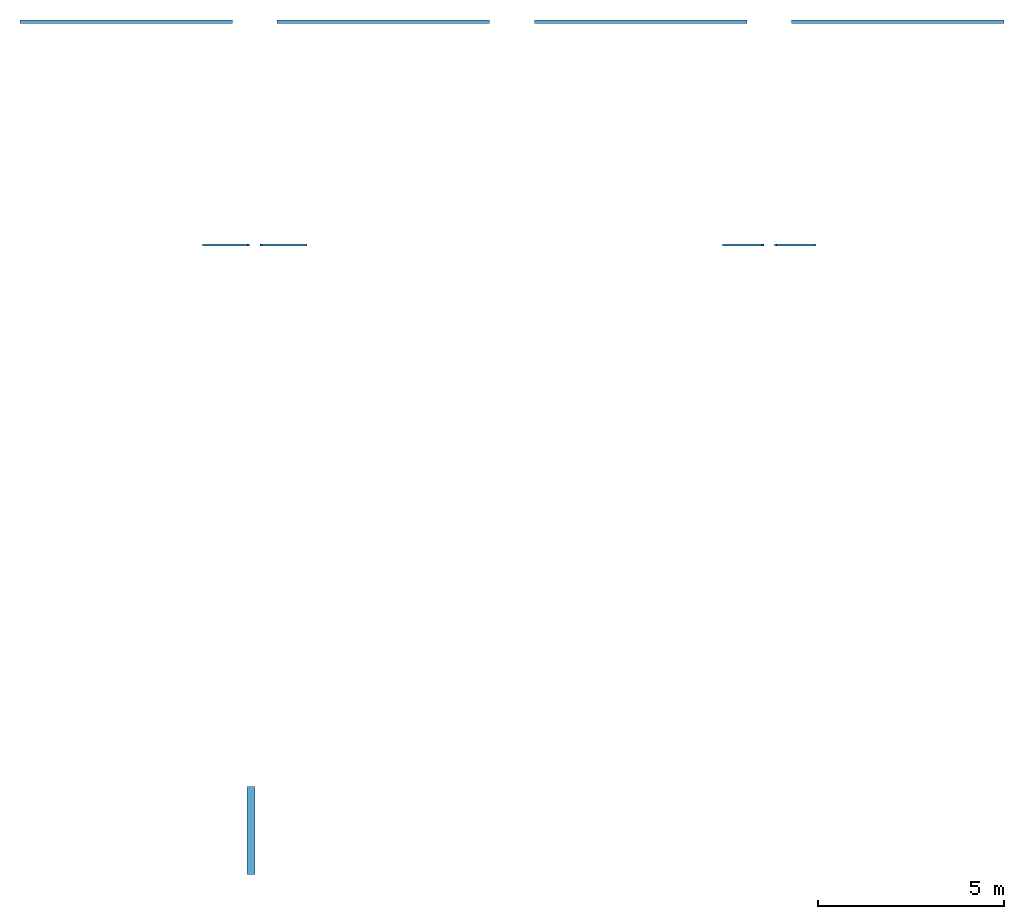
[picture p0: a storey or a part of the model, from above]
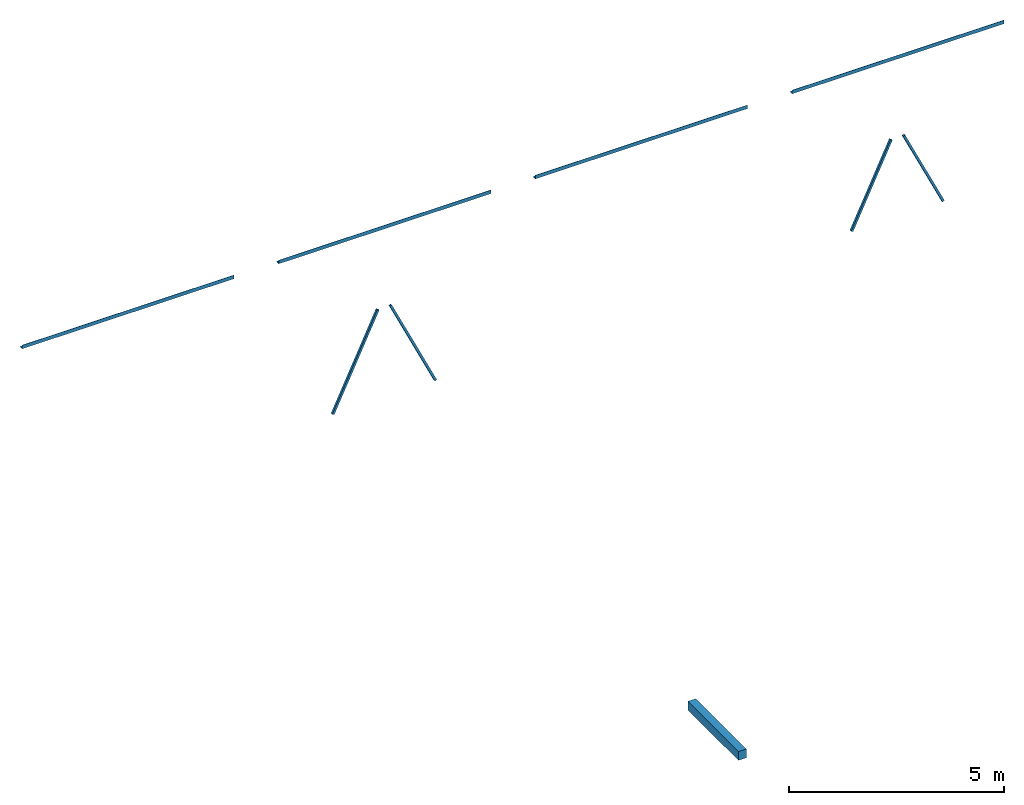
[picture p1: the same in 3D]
Properties of the parts of a building model (IFC2X3), part 3 of 6

# IfcBeam: btl_staal - IPE:IPE160 (32)
Name (btl_staal - IPE:IPE160:...) | In | BaseQuantities, Length (mm) = Cut Length (mm) | OuterSurfaceArea (mm2) | GrossVolume (m3) | NetVolume (m3) = Volume (m3) | Span (mm) = Dimensions, Length (mm) | Slope (deg) | Start Level Offset (mm) | End Level Offset (mm) | Reference Level | Reference Level Elevation (mm) | Join Status | Elevation at Bottom (mm) | Elevation at Top (mm)
1906272 | F1 begg (bk ruwe vloer) | 1423.51 | 908200 | 0.00276104 | 0.00271033 | 1423.51 | 36.1968 | 1631.93 | 2472.6 | 00000 begg | 0 | Both joins enabled | Group: Model Group:tribune spant (members excluded):1820546
1964621 | F1 begg (bk ruwe vloer) | 1417.23 | 904192 | 0.00274886 | 0.00269988 | 1391.98 | 35.0319 | 2139.06 | 2938.11 | F2 (bk fundering) | -480 | Both joins enabled

# IfcBeam: btl_staal - IPE:IPE200 (4)
In: V3 dakvloer
Type - Other - Category: Structural Framing; Family Name: btl_staal - IPE
Type - Dimensions - bf: 100 mm; d: 200 mm; k: 20.5 mm; tf: 8.5 mm; tr: 12 mm; tw: 5.6 mm
Type - Identity Data - Description: IPE200; Model: ligger; Type Name: IPE200
Type - Materials and Finishes - Structural Material: Metal - Steel - S235 JRG2 (standaard)
Type - Structural - Section Shape: 0; A: 2848 mm2; W: 0.219277
Type - Pset_BeamCommon - IsExternal: no; LoadBearing: yes
Type - Pset_ReinforcementBarPitchOfBeam - Description: IPE200
Material: Metal - Steel - S235 JRG2 (standaard)
BaseQuantities - Length: 5473.81 mm; CrossSectionArea: 2724.8 mm2; OuterSurfaceArea: 4317743 mm2; GrossVolume: 0.014915 m3; NetVolume: 0.014915 m3
Pset_BeamCommon - Slope: 0 deg; Reference: IPE200; Span: 5473.81 mm
Pset_QuantityTakeOff - Reference: IPE200; sets with these values: 2
Other - Family: btl_staal - IPE; End Extension Calculation: 3000 mm; Family and Type: btl_staal - IPE: IPE200; Start Extension Calculation: 3000 mm; Type: IPE200; Type Id: 1757208
Constraints - Cross-Section Rotation: 0 deg; Reference Level: V3 dakvloer; End Level Offset: -10 mm; Reference Level Elevation: 10840 mm; Start Level Offset: -10 mm
Construction - EindOplegging: -12.5 mm; StartOplegging: -12.5 mm
Dimensions - Elevation at Bottom: 10630 mm; Elevation at Top: 10830 mm; Length: 5473.81 mm; Volume: 0.014915 m3
Identity Data - Has Association: no
Phasing - Phase Created: 2. nieuwbouw
Structural - Structural Usage: Other; Stick Symbol Location: Center of Geometry; Cut Length: 5473.81 mm
Geometric Position - y Offset Value: 0 mm; yz Justification: Uniform; z Justification: Top; z Offset Value: 0 mm; Join Status: One or two joins disabled; y Justification: Origin; End Extension: 0 mm; Start Extension: 0 mm
Name (btl_staal - IPE:IPE200:...) | Group
2015836 | Model Group:Spant 5 (members excluded):2015775
2015953 | Model Group:Spant 5 (members excluded):2015892
2016068 | Model Group:Spant 5 (members excluded):2016007
2016183 | Model Group:Spant 5 (members excluded):2016122

# IfcBeam: btl_staal - IPE:IPE240 (2)
Type - Other - Category: Structural Framing; Family Name: btl_staal - IPE
Type - Dimensions - bf: 120 mm; d: 240 mm; k: 24.8 mm; tf: 9.8 mm; tr: 15 mm; tw: 6.2 mm
Type - Identity Data - Description: IPE240; Model: ligger; Type Name: IPE240
Type - Materials and Finishes - Structural Material: Metal - Steel - S235 JRG2 (standaard)
Type - Structural - Section Shape: 0; A: 3910 mm2; W: 0.301162
Type - Pset_BeamCommon - IsExternal: no; LoadBearing: yes
Type - Pset_ReinforcementBarPitchOfBeam - Description: IPE240
Material: Metal - Steel - S235 JRG2 (standaard)
BaseQuantities - Length: 3301.06 mm; CrossSectionArea: 3718.48 mm2; OuterSurfaceArea: 3128087 mm2; GrossVolume: 0.0122749 m3; NetVolume: 0.0122749 m3
Pset_BeamCommon - Slope: 0 deg; Reference: IPE240; Span: 3301.06 mm
Pset_QuantityTakeOff - Reference: IPE240; sets with these values: 2
Other - Family: btl_staal - IPE; End Extension Calculation: 3000 mm; Family and Type: btl_staal - IPE: IPE240; Start Extension Calculation: 3000 mm; Type: IPE240; Type Id: 1760346
Constraints - Cross-Section Rotation: 90 deg; End Level Offset: -120 mm; Start Level Offset: -120 mm
Construction - EindOplegging: -12.5 mm; StartOplegging: -12.5 mm
Dimensions - Length: 3301.06 mm; Volume: 0.0122749 m3
Identity Data - Has Association: no
Phasing - Phase Created: 2. nieuwbouw
Structural - Structural Usage: Other; Stick Symbol Location: Center of Geometry; Cut Length: 3301.06 mm
Geometric Position - y Offset Value: 0 mm; yz Justification: Uniform; z Justification: Top; z Offset Value: 0 mm; Join Status: One or two joins disabled; y Justification: Origin; End Extension: 0 mm; Start Extension: 0 mm
Name (btl_staal - IPE:IPE240:...) | In | Reference Level | Reference Level Elevation (mm) | Elevation at Bottom (mm) | Elevation at Top (mm)
2051930 | V1 1e verd. (bk ruwe vloer) | V1 1e verd. (bk ruwe vloer) | 3730 | 3550 | 3670
2052821 | V2 2e verd. (bk ruwe vloer) | V2 2e verd. (bk ruwe vloer) | 7530 | 7350 | 7470

# IfcBeam: btl_staal - Koker:K200x120x8 (2)
In: V4 BK metselwerk
Type - Other - Category: Structural Framing; Family Name: btl_staal - Koker
Type - Dimensions - b: 120 mm; Ht: 200 mm; t: 8 mm; tr: 16 mm
Type - Identity Data - Description: K200x10x8; Model: ligger; Type Name: K200x120x8
Type - Materials and Finishes - Structural Material: Metal - Steel - S275 J0H (standaard-kokers/buizen)
Type - Structural - Section Shape: 0; A: 2500 mm2; Shape: rechthoek; W: 0.19221
Type - Pset_BeamCommon - IsExternal: no; LoadBearing: yes
Type - Pset_ReinforcementBarPitchOfBeam - Description: K200x10x8
Material: Metal - Steel - S275 J0H (standaard-kokers/buizen)
BaseQuantities - CrossSectionArea: 24000 mm2
Pset_BeamCommon - Slope: 0 deg; Reference: K200x120x8
Pset_QuantityTakeOff - Reference: K200x120x8; sets with these values: 2
Other - End Extension Calculation: 3000 mm; Family: btl_staal - Koker; Family and Type: btl_staal - Koker: K200x120x8; Start Extension Calculation: 3000 mm; Type: K200x120x8; Type Id: 2116077
Constraints - Cross-Section Rotation: 0 deg; Reference Level: V4 BK metselwerk; Reference Level Elevation: 11700 mm
Construction - EindOpleggging: -12.5 mm; StartOplegging: -12.5 mm
Identity Data - Has Association: yes
Phasing - Phase Created: 2. nieuwbouw
Structural - Structural Usage: Other; Stick Symbol Location: Center of Geometry
Geometric Position - Join Status: Both joins enabled; y Offset Value: 0 mm; yz Justification: Uniform; z Justification: Top; z Offset Value: 0 mm; y Justification: Origin; End Extension: 0 mm; Start Extension: 0 mm
Name (btl_staal - Koker:K200x120x8:...) | BaseQuantities, Length (mm) = Span (mm) = Dimensions, Length (mm) = Cut Length (mm) | OuterSurfaceArea (mm2) | GrossVolume (m3) | NetVolume (m3) = Volume (m3) | End Level Offset (mm) = Start Level Offset (mm) | Elevation at Bottom (mm) | Elevation at Top (mm)
1610107 | 6278.47 | 4018220 | 0.150683 | 0.0305385 | -910 | 10590 | 10790
1610363 | 6292.97 | 4027500 | 0.151031 | 0.030609 | -870 | 10630 | 10830

# IfcBeam: btl_staal - Koker:K220x80x5.0, btl_staal - Koker:K220x80x5.0:1770139
In: V1 1e verd. (bk ruwe vloer)
Type - Other - Category: Structural Framing; Family Name: btl_staal - Koker
Type - Dimensions - b: 80 mm; Ht: 220 mm; t: 5 mm; tr: 10 mm
Type - Identity Data - Description: K220x80x5; Model: ligger; Type Name: K220x80x5.0
Type - Materials and Finishes - Structural Material: Metal - Steel - S275 J0H (standaard-kokers/buizen)
Type - Structural - Section Shape: 0; A: 2500 mm2; Shape: rechthoek; W: 0.19221
Type - Pset_BeamCommon - IsExternal: no; LoadBearing: yes
Type - Pset_ReinforcementBarPitchOfBeam - Description: K220x80x5
Material: Metal - Steel - S275 J0H (standaard-kokers/buizen)
BaseQuantities - Length: 13513.7 mm; CrossSectionArea: 17600 mm2; OuterSurfaceArea: 8108197 mm2; GrossVolume: 0.23784 m3; NetVolume: 0.0391896 m3
Pset_BeamCommon - Slope: 0 deg; Reference: K220x80x5.0; Span: 13513.7 mm
Pset_QuantityTakeOff - Reference: K220x80x5.0; sets with these values: 2
Other - Family: btl_staal - Koker; End Extension Calculation: 3000 mm; Family and Type: btl_staal - Koker: K220x80x5.0; Start Extension Calculation: 3000 mm; Type: K220x80x5.0; Type Id: 1770266
Constraints - Cross-Section Rotation: 0 deg; Reference Level: V1 1e verd. (bk ruwe vloer); End Level Offset: -262.5 mm; Reference Level Elevation: 3730 mm; Start Level Offset: -262.5 mm
Construction - EindOpleggging: -12.5 mm; StartOplegging: -12.5 mm
Dimensions - Elevation at Bottom: 3247.5 mm; Elevation at Top: 3467.5 mm; Length: 13513.7 mm; Volume: 0.0391896 m3
Identity Data - Has Association: yes
Phasing - Phase Created: 2. nieuwbouw
Structural - Structural Usage: Other; Stick Symbol Location: Center of Geometry; Cut Length: 13513.7 mm
Geometric Position - y Offset Value: 0 mm; yz Justification: Uniform; z Justification: Top; z Offset Value: 0 mm; Join Status: One or two joins disabled; y Justification: Origin; End Extension: 0 mm; Start Extension: 0 mm

# IfcBeam: btl_staal - Koker:K60x60x5.0 (4)
In: KDV nok
Type - Other - Category: Structural Framing; Family Name: btl_staal - Koker
Type - Dimensions - b: 60 mm; Ht: 60 mm; t: 5 mm; tr: 10 mm
Type - Identity Data - Description: K60x60x5; Model: ligger; Type Name: K60x60x5.0
Type - Materials and Finishes - Structural Material: Metal - Steel - S275 J0H (standaard-kokers/buizen)
Type - Structural - Section Shape: 0; A: 1088 mm2; Shape: vierkant; W: 0.0837488
Type - Pset_BeamCommon - IsExternal: no; LoadBearing: yes
Type - Pset_ReinforcementBarPitchOfBeam - Description: K60x60x5
Material: Metal - Steel - S275 J0H (standaard-kokers/buizen)
BaseQuantities - CrossSectionArea: 3600 mm2
Pset_BeamCommon - Reference: K60x60x5.0; Span: 3036.84 mm; Slope: 64.6366 deg
Pset_QuantityTakeOff - Reference: K60x60x5.0; sets with these values: 2
Other - Family: btl_staal - Koker; End Extension Calculation: 3000 mm; Family and Type: btl_staal - Koker: K60x60x5.0; Start Extension Calculation: 3000 mm; Type: K60x60x5.0; Type Id: 1762913
Constraints - Cross-Section Rotation: 0 deg; Reference Level: V3 ok vloer; Reference Level Elevation: 10380 mm
Construction - EindOpleggging: -12.5 mm; StartOplegging: -12.5 mm
Dimensions - Length: 3036.84 mm
Identity Data - Has Association: yes
Phasing - Phase Created: 2. nieuwbouw
Structural - Structural Usage: Other; End Attachment Elevation: 0 mm; Start Attachment Elevation: 0 mm
Geometric Position - yz Justification: Uniform; z Offset Value: 0 mm; Join Status: One or two joins disabled; y Justification: Origin; z Justification: Origin; Start Extension: -394.645 mm
Name (btl_staal - Koker:K60x60x5.0:...) | Length (mm) = Cut Length (mm) | OuterSurfaceArea (mm2) | GrossVolume (m3) | NetVolume (m3) = Volume (m3) | End Extension (mm) | y Offset Value (mm)
1762934 | 2818.4 | 676416 | 0.0101462 | 0.00310024 | 176.2 | -5
1763153 | 2818.4 | 676416 | 0.0101462 | 0.00310024 | 176.2 | 5
1763191 | 2466.01 | 591843 | 0.00887764 | 0.00271261 | -176.188 | -5
1763193 | 2466.01 | 591843 | 0.00887764 | 0.00271261 | -176.188 | 5

# IfcBeam: btl_staal - Koker:K70x70x6.0 (6)
In: V3 dakvloer
Type - Other - Category: Structural Framing; Family Name: btl_staal - Koker
Type - Dimensions - b: 70 mm; Ht: 70 mm; t: 6 mm; tr: 12 mm
Type - Identity Data - Description: K70x70x6; Model: ligger; Type Name: K70x70x6.0
Type - Materials and Finishes - Structural Material: Metal - Steel - S275 J0H (standaard-kokers/buizen)
Type - Structural - Section Shape: 0; A: 1288 mm2; Shape: vierkant; W: 0.0984244
Type - Pset_BeamCommon - IsExternal: no; LoadBearing: yes
Type - Pset_ReinforcementBarPitchOfBeam - Description: K70x70x6
Material: Metal - Steel - S275 J0H (standaard-kokers/buizen)
BaseQuantities - Length: 5345 mm; CrossSectionArea: 4900 mm2; OuterSurfaceArea: 1496600 mm2; GrossVolume: 0.0261905 m3; NetVolume: 0.00820992 m3
Pset_BeamCommon - Slope: 0 deg; Reference: K70x70x6.0; Span: 5345 mm
Pset_QuantityTakeOff - Reference: K70x70x6.0; sets with these values: 2
Other - Family: btl_staal - Koker; End Extension Calculation: 3000 mm; Family and Type: btl_staal - Koker: K70x70x6.0; Start Extension Calculation: 3000 mm; Type: K70x70x6.0; Type Id: 1757260
Constraints - Cross-Section Rotation: 0 deg; Reference Level: V3 dakvloer; Reference Level Elevation: 10840 mm
Construction - EindOpleggging: -12.5 mm; StartOplegging: -12.5 mm
Dimensions - Length: 5345 mm; Volume: 0.00820992 m3
Identity Data - Has Association: no
Phasing - Phase Created: 2. nieuwbouw
Structural - Structural Usage: Other; Stick Symbol Location: Center of Geometry; Cut Length: 5345 mm
Geometric Position - y Offset Value: 0 mm; yz Justification: Uniform; z Justification: Top; z Offset Value: 0 mm; Join Status: One or two joins disabled; y Justification: Origin; End Extension: 0 mm; Start Extension: 0 mm
Name (btl_staal - Koker:K70x70x6.0:...) | End Level Offset (mm) = Start Level Offset (mm) | Elevation at Bottom (mm) | Elevation at Top (mm) | Group
2015880 | 315.9 | 11085.9 | 11155.9 | Model Group:Spant 5 (members excluded):2015775
2015997 | 315.9 | 11085.9 | 11155.9 | Model Group:Spant 5 (members excluded):2015892
2016112 | 315.9 | 11085.9 | 11155.9 | Model Group:Spant 5 (members excluded):2016007
2016227 | 315.9 | 11085.9 | 11155.9 | Model Group:Spant 5 (members excluded):2016122
2094437 | -100 | 10670 | 10740
2094761 | -100 | 10670 | 10740

# IfcBeam: btl_staal - Koker:K80x40x5.0 (6)
Type - Other - Category: Structural Framing; Family Name: btl_staal - Koker
Type - Dimensions - b: 40 mm; Ht: 80 mm; t: 5 mm; tr: 10 mm
Type - Identity Data - Description: K80x40x5.0; Model: ligger; Type Name: K80x40x5.0
Type - Materials and Finishes - Structural Material: Metal - Steel - S275 J0H (standaard-kokers/buizen)
Type - Structural - Section Shape: 0; A: 1088 mm2; Shape: rechthoek; W: 0.0837488
Type - Pset_BeamCommon - IsExternal: no; LoadBearing: yes
Type - Pset_ReinforcementBarPitchOfBeam - Description: K80x40x5.0
Material: Metal - Steel - S275 J0H (standaard-kokers/buizen)
BaseQuantities - CrossSectionArea: 3200 mm2
Pset_BeamCommon - Slope: 0 deg; Reference: K80x40x5.0; Span: 1593.6 mm
Pset_QuantityTakeOff - Reference: K80x40x5.0; sets with these values: 2
Other - Family: btl_staal - Koker; End Extension Calculation: 3000 mm; Family and Type: btl_staal - Koker: K80x40x5.0; Start Extension Calculation: 3000 mm; Type: K80x40x5.0; Type Id: 1808185
Constraints - Cross-Section Rotation: 90 deg
Construction - EindOpleggging: -12.5 mm; StartOplegging: -12.5 mm
Dimensions - Length: 1593.6 mm
Identity Data - Has Association: yes
Phasing - Phase Created: 2. nieuwbouw
Structural - Structural Usage: Other; Stick Symbol Location: Center of Geometry; Start Attachment Type: End Elevation
Geometric Position - Join Status: Both joins enabled; y Offset Value: 0 mm; yz Justification: Uniform; z Offset Value: 0 mm; y Justification: Origin; End Extension: 0 mm; Start Extension: 0 mm; End Join Cutback: 12.7 mm; Start Join Cutback: 12.7 mm; z Justification: Center
Name (btl_staal - Koker:K80x40x5.0:...) | In | Length (mm) = Cut Length (mm) | OuterSurfaceArea (mm2) | GrossVolume (m3) | NetVolume (m3) = Volume (m3) | Reference Level | End Level Offset (mm) = Start Level Offset (mm) | Reference Level Elevation (mm) | Elevation at Bottom (mm) | Elevation at Top (mm)
1808448 | KDV V2 werkbalken | 1318.57 | 316456 | 0.00421942 | 0.00145042 | V2 ok vloer | 260 | 7270 | 7510 | 7550
1808635 | KDV V2 werkbalken | 1318.57 | 316456 | 0.00421942 | 0.00145042 | V2 ok vloer | 260 | 7270 | 7510 | 7550
1808897 | KDV V2 werkbalken | 1407.69 | 337845 | 0.0045046 | 0.00154846 | V2 ok vloer | -545 | 7270 | 6705 | 6745 | Structural - End Attachment Type: End Elevation
1808980 | KDV V2 werkbalken | 1407.69 | 337845 | 0.0045046 | 0.00154846 | V2 ok vloer | -545 | 7270 | 6705 | 6745 | Structural - End Attachment Type: End Elevation
1809233 | V1 1e verd. (bk ruwe vloer) | 1318.57 | 316456 | 0.00421942 | 0.00145042 | V1 1e verd. (bk ruwe vloer) | -940 | 3730 | 2770 | 2810
1809235 | V1 1e verd. (bk ruwe vloer) | 1318.57 | 316456 | 0.00421942 | 0.00145042 | V1 1e verd. (bk ruwe vloer) | -940 | 3730 | 2770 | 2810

# IfcBeam: btl_staal - Koker:K80x80x5.0 (24)
In: V3 dakvloer
Type - Other - Category: Structural Framing; Family Name: btl_staal - Koker
Type - Dimensions - b: 80 mm; Ht: 80 mm; t: 5 mm; tr: 10 mm
Type - Identity Data - Description: K80x80x5; Model: ligger; Type Name: K80x80x5.0
Type - Materials and Finishes - Structural Material: Metal - Steel - S275 J0H (standaard-kokers/buizen)
Type - Structural - Section Shape: 0; A: 1488 mm2; Shape: vierkant; W: 0.113821
Type - Pset_BeamCommon - IsExternal: no; LoadBearing: yes
Type - Pset_ReinforcementBarPitchOfBeam - Description: K80x80x5
Material: Metal - Steel - S275 J0H (standaard-kokers/buizen)
BaseQuantities - GrossSurfaceArea: 0 mm2
Pset_BeamCommon - Reference: K80x80x5.0
Pset_QuantityTakeOff - Reference: K80x80x5.0; sets with these values: 2
Other - Family: btl_staal - Koker; End Extension Calculation: 3000 mm; Family and Type: btl_staal - Koker: K80x80x5.0; Start Extension Calculation: 3000 mm; Type: K80x80x5.0; Type Id: 1714443
Constraints - Cross-Section Rotation: 0 deg; Reference Level: V3 dakvloer; Reference Level Elevation: 10840 mm; Start Level Offset: -66.0469 mm
Construction - EindOpleggging: -12.5 mm; StartOplegging: -12.5 mm
Identity Data - Has Association: no
Phasing - Phase Created: 2. nieuwbouw
Structural - Structural Usage: Other; Stick Symbol Location: Center of Geometry
Geometric Position - y Offset Value: 0 mm; yz Justification: Uniform; z Offset Value: 0 mm; Join Status: One or two joins disabled; y Justification: Origin; Start Extension: 0 mm; z Justification: Center
Name (btl_staal - Koker:K80x80x5.0:...) | NetVolume (m3) = Volume (m3) | Span (mm) = Length (mm) | Slope (deg) | End Level Offset (mm) | Cut Length (mm) | End Extension (mm) | Group
2012644 | 0.00275618 | 2170 | 34.9874 | 1178.22 | 1894.61 | -200 | Model Group:Spant 3:2012551
2012645 | 0.0028831 | 2187.16 | 34.9874 | 1188.07 | 2020.74 | 0 | Model Group:Spant 3:2012551
2012646 | 0.0028831 | 2187.16 | 34.9874 | 1188.07 | 2020.74 | 0 | Model Group:Spant 3:2012551
2012647 | 0.00278193 | 2187.16 | 34.9874 | 1188.07 | 1911.77 | -200 | Model Group:Spant 3:2012551
2012648 | 0.00276744 | 2176.89 | 35.1752 | 1188.01 | 1901.72 | -200 | Model Group:Spant 3:2012551
2012649 | 0.00278822 | 2190.74 | 35.1752 | 1195.99 | 1915.57 | -200 | Model Group:Spant 3:2012551
2012650 | 0.00270912 | 2138 | 35.1752 | 1165.61 | 1862.83 | -200 | Model Group:Spant 3:2012551
2012658 | 0.00288057 | 2257.13 | 33.7627 | 1188.36 | 1980.22 | -200 | Model Group:Spant 3:2012551
2012825 | 0.00275618 | 2170 | 34.9874 | 1178.22 | 1894.61 | -200 | Model Group:Spant 3:2012732
2012826 | 0.0028831 | 2187.16 | 34.9874 | 1188.07 | 2020.74 | 0 | Model Group:Spant 3:2012732
2012827 | 0.0028831 | 2187.16 | 34.9874 | 1188.07 | 2020.74 | 0 | Model Group:Spant 3:2012732
2012828 | 0.00278193 | 2187.16 | 34.9874 | 1188.07 | 1911.77 | -200 | Model Group:Spant 3:2012732
2012829 | 0.00276744 | 2176.89 | 35.1752 | 1188.01 | 1901.72 | -200 | Model Group:Spant 3:2012732
2012830 | 0.00278822 | 2190.74 | 35.1752 | 1195.99 | 1915.57 | -200 | Model Group:Spant 3:2012732
2012831 | 0.00270912 | 2138 | 35.1752 | 1165.61 | 1862.83 | -200 | Model Group:Spant 3:2012732
2012839 | 0.00288057 | 2257.13 | 33.7627 | 1188.36 | 1980.22 | -200 | Model Group:Spant 3:2012732
2013006 | 0.00275618 | 2170 | 34.9874 | 1178.22 | 1894.61 | -200 | Model Group:Spant 3:2012913
2013007 | 0.0028831 | 2187.16 | 34.9874 | 1188.07 | 2020.74 | 0 | Model Group:Spant 3:2012913
2013008 | 0.0028831 | 2187.16 | 34.9874 | 1188.07 | 2020.74 | 0 | Model Group:Spant 3:2012913
2013009 | 0.00278193 | 2187.16 | 34.9874 | 1188.07 | 1911.77 | -200 | Model Group:Spant 3:2012913
2013010 | 0.00276744 | 2176.89 | 35.1752 | 1188.01 | 1901.72 | -200 | Model Group:Spant 3:2012913
2013011 | 0.00278822 | 2190.74 | 35.1752 | 1195.99 | 1915.57 | -200 | Model Group:Spant 3:2012913
2013012 | 0.00270912 | 2138 | 35.1752 | 1165.61 | 1862.83 | -200 | Model Group:Spant 3:2012913
2013020 | 0.00288057 | 2257.13 | 33.7627 | 1188.36 | 1980.22 | -200 | Model Group:Spant 3:2012913

# IfcBeam: btl_staal - Rond:Ø16 (12)
Type - Other - Category: Structural Framing; Family Name: btl_staal - Rond
Type - Dimensions - d: 16 mm
Type - Identity Data - Description: Ø16+spanwartel; Model: staaf; OmniClass Number: 23.25.30.11.14.14; OmniClass Title: Beams; Type Name: Ø16
Type - Materials and Finishes - Structural Material: Metal - Steel - S235 JRG2 (standaard)
Type - Structural - Section Shape: 0; A: 0 mm2
Type - Pset_BeamCommon - IsExternal: no; LoadBearing: yes
Type - Pset_ReinforcementBarPitchOfBeam - Description: Ø16+spanwartel
Material: Metal - Steel - S235 JRG2 (standaard)
BaseQuantities - CrossSectionArea: 200.853 mm2
Pset_BeamCommon - Reference: Ø16
Pset_QuantityTakeOff - Reference: Ø16; sets with these values: 2
Other - End Extension Calculation: 3000 mm; Family: btl_staal - Rond; Family and Type: btl_staal - Rond: Ø16; Start Extension Calculation: 3000 mm; Type: Ø16; Type Id: 2000533
Constraints - Cross-Section Rotation: 0 deg
Construction - End Extension: -12.5 mm; Start Extension: -12.5 mm
Identity Data - Has Association: yes
Phasing - Phase Created: 2. nieuwbouw
Structural - Stick Symbol Location: Center of Geometry
Geometric Position - Join Status: Both joins enabled; y Offset Value: 0 mm; yz Justification: Uniform; z Justification: Top; z Offset Value: 0 mm; y Justification: Origin; End Extension: 0 mm; Start Extension: 0 mm
Name (btl_staal - Rond:Ø16:...) | In | BaseQuantities, Length (mm) = Cut Length (mm) | OuterSurfaceArea (mm2) | GrossVolume (m3) | NetVolume (m3) = Volume (m3) | Span (mm) = Dimensions, Length (mm) | Slope (deg) | Reference Level | End Level Offset (mm) | Reference Level Elevation (mm) | Start Level Offset (mm) | Structural Usage | End Join Cutback (mm)
1870659 | V1 1e verd. (bk ruwe vloer) | 3266.23 | 164179 | 0.000656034 | 0.000656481 | 3288.12 | 31.0532 | V1 1e verd. (bk ruwe vloer) | -2033.87 | 3730 | -3729.99 | Other | 12.7 | Constraints - Orientation: Normal; Work Plane: Reference Plane : Windverband in tribune schuin
1870735 | V1 1e verd. (bk ruwe vloer) | 3265.61 | 164147 | 0.000655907 | 0.000656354 | 3287.61 | 31.0515 | V1 1e verd. (bk ruwe vloer) | -2033.82 | 3730 | -3729.6 | Other | 12.7 | Constraints - Orientation: Normal; Work Plane: Reference Plane : Windverband in tribune schuin
1870784 | V1 1e verd. (bk ruwe vloer) | 1984.31 | 99742.1 | 0.000398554 | 0.000398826 | 1975 | 21.208 | V1 1e verd. (bk ruwe vloer) | -1319.35 | 3730 | -2033.82 | Other | Constraints - Orientation: Normal; Work Plane: Reference Plane : Windverband in tribune schuin
1870805 | V1 1e verd. (bk ruwe vloer) | 2013.79 | 101224 | 0.000404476 | 0.000404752 | 2004.61 | 20.8185 | V1 1e verd. (bk ruwe vloer) | -1321.42 | 3730 | -2033.87 | Other | Constraints - Orientation: Normal; Work Plane: Reference Plane : Windverband in tribune schuin
1872395 | F1 begg (bk ruwe vloer) | 2690.02 | 135215 | 0.000540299 | 0.000540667 | 2792.58 | 39.7375 | F1 begg (bk ruwe vloer) | 0 | -70 | 1785.22 | Other | 12.7 | Structural - End Attachment Type: End Elevation; Geometric Position - Start Join Cutback: 12.7 mm
1872422 | F1 begg (bk ruwe vloer) | 2559.77 | 128668 | 0.000514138 | 0.000514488 | 2700.65 | 37.3298 | F1 begg (bk ruwe vloer) | 0 | -70 | 1637.68 | Girder | 12.7 | Structural - End Attachment Type: End Elevation; Start Attachment Type: End Elevation; Geometric Position - Start Join Cutback: 12.7 mm
1872783 | F1 begg (bk ruwe vloer) | 2947.85 | 148175 | 0.000592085 | 0.000592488 | 3029.24 | 54.3846 | F1 begg (bk ruwe vloer) | 0 | -70 | 2462.6 | Other | 12.7 | Structural - End Attachment Type: End Elevation
1872850 | F1 begg (bk ruwe vloer) | 2947.85 | 148175 | 0.000592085 | 0.000592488 | 3029.24 | 54.3846 | F1 begg (bk ruwe vloer) | 0 | -70 | 2462.6 | Other | 12.7 | Structural - End Attachment Type: End Elevation
1872890 | F1 begg (bk ruwe vloer) | 2947.91 | 148178 | 0.000592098 | 0.000592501 | 3029.3 | 54.3829 | F1 begg (bk ruwe vloer) | 0 | -70 | 2462.6 | Other | 12.7 | Structural - End Attachment Type: End Elevation
1872919 | F1 begg (bk ruwe vloer) | 2948.03 | 148184 | 0.000592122 | 0.000586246 | 3029.42 | 54.3846 | F1 begg (bk ruwe vloer) | -0.151257 | -70 | 2462.6 | Other | 12.7 | Structural - End Attachment Type: End Elevation
2001237 | F1 begg (bk ruwe vloer) | 1841.24 | 92550.8 | 0.000369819 | 0.000366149 | 1841.24 | 0 | F1 begg (bk ruwe vloer) | 2470.6 | -70 | 2470.6 | Other | Dimensions - Elevation at Bottom: 2384.6 mm; Elevation at Top: 2400.6 mm
2001239 | F1 begg (bk ruwe vloer) | 1873.73 | 94183.9 | 0.000376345 | 0.00037261 | 1873.73 | 0 | F1 begg (bk ruwe vloer) | 2470.6 | -70 | 2470.6 | Other | Dimensions - Elevation at Bottom: 2384.6 mm; Elevation at Top: 2400.6 mm

# IfcBeam: btl_staal - SFB:HEB200+400x8 (6)
In: V4 BK metselwerk
Type - PredefinedType: BEAM; Material: Metal - Steel - S235 JRG2 (standaard)
Type - Other - Category: Structural Framing; Family Name: btl_staal - SFB
Type - Dimensions - bf: 200 mm; bu: 400 mm; bu_links: 200 mm; bu_rechts: 200 mm; h: 200 mm; halve breedte SFB: 100 mm; k: 33 mm; kr: 18 mm; tf: 15 mm; tu: 15 mm; tw: 9 mm; vrije oplegging plaat links: 100 mm; vrije oplegging plaat rechts: 100 mm; y: 68 mm
Type - Identity Data - Description: HEB200; Model: ligger; Type Name: HEB200+400x8
Type - Materials and Finishes - Structural Material: Metal - Steel - S235 JRG2 (standaard)
Type - Structural - Section Shape: 0; A: 13810 mm2; W: 1.06232
Type - Pset_BeamCommon - IsExternal: no; LoadBearing: yes
Type - Pset_ReinforcementBarPitchOfBeam - Description: HEB200
Pset_BeamCommon - Slope: 0 deg; Reference: HEB200+400x8
Pset_QuantityTakeOff - Reference: HEB200+400x8; sets with these values: 2
Other - Family: btl_staal - SFB; End Extension Calculation: 3000 mm; Family and Type: btl_staal - SFB: HEB200+400x8; Start Extension Calculation: 3000 mm; Type: HEB200+400x8; Type Id: 2092170
Constraints - Cross-Section Rotation: 0 deg; Reference Level: V4 BK metselwerk; End Level Offset: 200 mm; Reference Level Elevation: 11700 mm; Start Level Offset: 200 mm
Construction - eind_oplegging: -12.7 mm; start_oplegging: -12.7 mm
Dimensions - Elevation at Bottom: 11685 mm; Elevation at Top: 11900 mm
Identity Data - Has Association: no
Phasing - Phase Created: 2. nieuwbouw
Structural - Structural Usage: Other; Stick Symbol Location: Center of Geometry
Geometric Position - y Offset Value: 0 mm; yz Justification: Uniform; z Justification: Top; z Offset Value: 0 mm; Join Status: One or two joins disabled; y Justification: Origin; End Extension: 0 mm; Start Extension: 0 mm
Name (btl_staal - SFB:HEB200+400x8:...) | Span (mm) = BaseQuantities, Length (mm) = Dimensions, Length (mm) = Cut Length (mm) | CrossSectionArea (mm2) | OuterSurfaceArea (mm2) | GrossSurfaceArea (mm2) | GrossVolume (m3) | NetVolume (m3) = Volume (m3) | Comments
2013575 | 5032.81 | 6000 | 4177231 | 4189231 | 0.0301969 | 0.0680939 | + aangelaste plaat 400 | BaseQuantities - Height: 400 mm; Width: 15 mm
2031744 | 5032.81 | 6000 | 4177231 | 4189231 | 0.0301969 | 0.0680939 | + aangelaste plaat 400 | BaseQuantities - Height: 400 mm; Width: 15 mm
2058860 | 8310.12 | 7530 | 9822566 | 9837626 | 0.0625752 | 0.112436 | + aangelaste plaat 400 + toog 20mm
2059218 | 8310.12 | 7530 | 9822566 | 9837626 | 0.0625752 | 0.112436 | + aangelaste plaat 400 + toog 20mm
2059332 | 3032.85 | 7530 | 3584828 | 3599888 | 0.0228374 | 0.0410345 | + aangelaste plaat 400
2059434 | 3032.85 | 7530 | 3584828 | 3599888 | 0.0228374 | 0.0410345 | + aangelaste plaat 400

# IfcBeam: btl_staal - SFB:SFB HEB200+300x10 (2)
Type - PredefinedType: BEAM; Material: Metal - Steel - S355 JR (standaard-geintegreerde liggers)
Type - Other - Category: Structural Framing; Family Name: btl_staal - SFB
Type - Dimensions - vrije oplegging plaat links: 0 mm; bf: 200 mm; bu: 300 mm; bu_links: 100 mm; bu_rechts: 200 mm; h: 200 mm; halve breedte SFB: 100 mm; k: 33 mm; kr: 18 mm; tf: 15 mm; tu: 10 mm; tw: 9 mm; vrije oplegging plaat rechts: 100 mm; y: 68 mm
Type - Identity Data - Description: SFB HEB200+300x10; Model: ligger; Type Name: SFB HEB200+300x10
Type - Materials and Finishes - Structural Material: Metal - Steel - S355 JR (standaard-geintegreerde liggers)
Type - Structural - Section Shape: 0; A: 13810 mm2; W: 1.06232
Type - Pset_BeamCommon - IsExternal: no; LoadBearing: yes
Type - Pset_ReinforcementBarPitchOfBeam - Description: SFB HEB200+300x10
Pset_BeamCommon - Slope: 0 deg; Reference: SFB HEB200+300x10; Span: 8349.99 mm
Pset_QuantityTakeOff - Reference: SFB HEB200+300x10; sets with these values: 2
BaseQuantities - Length: 8349.99 mm; Height: 300 mm; Width: 10 mm; CrossSectionArea: 3000 mm2; OuterSurfaceArea: 5176995 mm2; GrossSurfaceArea: 5182995 mm2; GrossVolume: 0.02505 m3; NetVolume: 0.0879254 m3
Other - Family: btl_staal - SFB; End Extension Calculation: 3000 mm; Family and Type: btl_staal - SFB: SFB HEB200+300x10; Start Extension Calculation: 3000 mm; Type: SFB HEB200+300x10; Type Id: 1964035
Constraints - Cross-Section Rotation: 0 deg
Construction - eind_oplegging: -12.7 mm; start_oplegging: -12.7 mm
Dimensions - Length: 8349.99 mm; Volume: 0.0879254 m3
Identity Data - Has Association: yes; Comments: Toog 20mm & brandwerend bekleden
Phasing - Phase Created: 2. nieuwbouw
Structural - Structural Usage: Other; Stick Symbol Location: Center of Geometry; Cut Length: 8349.99 mm
Geometric Position - y Offset Value: 0 mm; yz Justification: Uniform; z Justification: Top; z Offset Value: 0 mm; Join Status: One or two joins disabled; y Justification: Origin; End Extension: 0 mm; Start Extension: 0 mm
Name (btl_staal - SFB:SFB HEB200+300x10:...) | In | Reference Level | End Level Offset (mm) = Start Level Offset (mm) | Reference Level Elevation (mm) | Elevation at Bottom (mm) | Elevation at Top (mm)
1612375 | V1 1e verd. (bk ruwe vloer) | V1 1e verd. (bk ruwe vloer) | -60 | 3730 | 3460 | 3670
1641949 | V2 2e verd. (bk ruwe vloer) | V2 2e verd. (bk ruwe vloer) | -20 | 7530 | 7300 | 7510

# IfcBeam: btl_staal - SFB:SFB HEB200+300x15 (5)
Type - PredefinedType: BEAM; Material: Metal - Steel - S355 JR (standaard-geintegreerde liggers)
Type - Other - Category: Structural Framing; Family Name: btl_staal - SFB
Type - Dimensions - vrije oplegging plaat links: 0 mm; bf: 200 mm; bu: 300 mm; bu_links: 100 mm; bu_rechts: 200 mm; h: 200 mm; halve breedte SFB: 100 mm; k: 33 mm; kr: 18 mm; tf: 15 mm; tu: 15 mm; tw: 9 mm; vrije oplegging plaat rechts: 100 mm; y: 68 mm
Type - Identity Data - Description: SFB HEB200+300x15; Model: ligger; Type Name: SFB HEB200+300x15
Type - Materials and Finishes - Structural Material: Metal - Steel - S355 JR (standaard-geintegreerde liggers)
Type - Structural - Section Shape: 0; A: 13810 mm2; W: 1.06232
Type - Pset_BeamCommon - IsExternal: no; LoadBearing: yes
Type - Pset_ReinforcementBarPitchOfBeam - Description: SFB HEB200+300x15
Pset_BeamCommon - Slope: 0 deg; Reference: SFB HEB200+300x15
Pset_QuantityTakeOff - Reference: SFB HEB200+300x15; sets with these values: 2
BaseQuantities - Height: 300 mm; Width: 15 mm; CrossSectionArea: 4500 mm2
Other - Family: btl_staal - SFB; End Extension Calculation: 3000 mm; Family and Type: btl_staal - SFB: SFB HEB200+300x15; Start Extension Calculation: 3000 mm; Type: SFB HEB200+300x15; Type Id: 1969932
Constraints - Cross-Section Rotation: 0 deg
Construction - eind_oplegging: -12.7 mm; start_oplegging: -12.7 mm
Phasing - Phase Created: 2. nieuwbouw
Structural - Structural Usage: Other; Stick Symbol Location: Center of Geometry
Geometric Position - y Offset Value: 0 mm; yz Justification: Uniform; z Justification: Top; z Offset Value: 0 mm; Join Status: One or two joins disabled; y Justification: Origin; End Extension: 0 mm; Start Extension: 0 mm
Name (btl_staal - SFB:SFB HEB200+300x15:...) | In | Span (mm) = BaseQuantities, Length (mm) = Dimensions, Length (mm) | OuterSurfaceArea (mm2) | GrossSurfaceArea (mm2) | GrossVolume (m3) | NetVolume (m3) = Volume (m3) | Reference Level | End Level Offset (mm) = Start Level Offset (mm) | Reference Level Elevation (mm) | Elevation at Bottom (mm) | Elevation at Top (mm) | Has Association | Cut Length (mm) | End Join Cutback (mm)
1969303 | V2 2e verd. (bk ruwe vloer) | 6275.32 | 3882454 | 3891454 | 0.0277318 | 0.0741364 | V2 2e verd. (bk ruwe vloer) | -60 | 7530 | 7255 | 7470 | yes | 6162.62 | 12.7
1969840 | V1 1e verd. (bk ruwe vloer) | 6275.32 | 3882454 | 3891454 | 0.0277318 | 0.0741364 | V1 1e verd. (bk ruwe vloer) | -60 | 3730 | 3455 | 3670 | yes | 6162.62 | 12.7
2014032 | V3 dakvloer | 7736.86 | 4874223 | 4883223 | 0.0348159 | 0.0930745 | V3 dakvloer | -10 | 10840 | 10615 | 10830 | no | 7736.86
2032631 | V3 dakvloer | 5732 | 3608010 | 3617010 | 0.0257715 | 0.0688958 | V3 dakvloer | -10 | 10840 | 10615 | 10830 | no | 5727 | Structural - Start Attachment Type: End Elevation; Geometric Position - Start Join Cutback: 0 mm
2032824 | V3 dakvloer | 8305.12 | 5232228 | 5241228 | 0.0373731 | 0.0999106 | V3 dakvloer | -10 | 10840 | 10615 | 10830 | no | 8305.12 | 0 | Structural - End Attachment Type: End Elevation

# IfcBeam: btl_staal - SFB:SFB HEB200+400x15 (S355) (8)
Type - PredefinedType: BEAM; Material: Metal - Steel - S355 JR (standaard-geintegreerde liggers)
Type - Other - Category: Structural Framing; Family Name: btl_staal - SFB
Type - Dimensions - bf: 200 mm; bu: 400 mm; bu_links: 200 mm; bu_rechts: 200 mm; h: 200 mm; halve breedte SFB: 100 mm; k: 33 mm; kr: 18 mm; tf: 15 mm; tu: 15 mm; tw: 9 mm; vrije oplegging plaat links: 100 mm; vrije oplegging plaat rechts: 100 mm; y: 68 mm
Type - Identity Data - Description: SFB HEB200+400x15; Model: ligger; Type Name: SFB HEB200+400x15 (S355)
Type - Materials and Finishes - Structural Material: Metal - Steel - S355 JR (standaard-geintegreerde liggers)
Type - Structural - Section Shape: 0; A: 13810 mm2; W: 1.06232
Type - Pset_BeamCommon - IsExternal: no; LoadBearing: yes
Type - Pset_ReinforcementBarPitchOfBeam - Description: SFB HEB200+400x15
Pset_BeamCommon - Slope: 0 deg; Reference: SFB HEB200+400x15 (S355)
Pset_QuantityTakeOff - Reference: SFB HEB200+400x15 (S355); sets with these values: 2
Other - Family: btl_staal - SFB; End Extension Calculation: 3000 mm; Family and Type: btl_staal - SFB: SFB HEB200+400x15 (S355); Start Extension Calculation: 3000 mm; Type: SFB HEB200+400x15 (S355); Type Id: 1754855
Constraints - Cross-Section Rotation: 0 deg; End Level Offset: -60 mm; Start Level Offset: -60 mm
Construction - eind_oplegging: -12.7 mm; start_oplegging: -12.7 mm
Identity Data - Has Association: yes
Phasing - Phase Created: 2. nieuwbouw
Structural - Structural Usage: Other; Stick Symbol Location: Center of Geometry
Geometric Position - y Offset Value: 0 mm; yz Justification: Uniform; z Justification: Top; z Offset Value: 0 mm; Join Status: One or two joins disabled; y Justification: Origin
Name (btl_staal - SFB:SFB HEB200+400x15 (S355):...) | In | Span (mm) = BaseQuantities, Length (mm) = Dimensions, Length (mm) | CrossSectionArea (mm2) | OuterSurfaceArea (mm2) | GrossSurfaceArea (mm2) | GrossVolume (m3) | NetVolume (m3) = Volume (m3) | Reference Level | Reference Level Elevation (mm) | Elevation at Bottom (mm) | Elevation at Top (mm) | Cut Length (mm) | End Extension (mm) = Start Extension (mm)
1566006 | V1 1e verd. (bk ruwe vloer) | 27846 | 6000 | 23112163 | 23124163 | 0.167076 | 0.376756 | V1 1e verd. (bk ruwe vloer) | 3730 | 3455 | 3670 | 27846 | 0 | BaseQuantities - Height: 400 mm; Width: 15 mm; Identity Data - Comments: Brandwerend bekleden
1573417 | V2 2e verd. (bk ruwe vloer) | 27889 | 6000 | 23147853 | 23159853 | 0.167334 | 0.377338 | V2 2e verd. (bk ruwe vloer) | 7530 | 7255 | 7470 | 27889 | 0 | BaseQuantities - Height: 400 mm; Width: 15 mm
1785711 | V1 1e verd. (bk ruwe vloer) | 3239 | 7530 | 3828495 | 3843555 | 0.0243897 | 0.0411768 | V1 1e verd. (bk ruwe vloer) | 3730 | 3455 | 3670 | 3239 | 0
1785979 | V1 1e verd. (bk ruwe vloer) | 3239 |  |  |  |  | 0.0408768 | V1 1e verd. (bk ruwe vloer) | 3730 | 3455 | 3670 | 3239 | 0 | Identity Data - Comments: Brandwerend bekleden
1786333 | V2 2e verd. (bk ruwe vloer) | 3446 |  |  |  |  | 0.0396866 | V2 2e verd. (bk ruwe vloer) | 7530 | 7255 | 7470 | 3339 | 0 | Geometric Position - End Join Cutback: 0 mm
1810351 | V1 1e verd. (bk ruwe vloer) | 8702.42 |  |  |  |  | 0.121434 | V1 1e verd. (bk ruwe vloer) | 3730 | 3455 | 3670 | 9302.42 | 300 | Identity Data - Comments: Brandwerend bekleden
1810977 | V1 1e verd. (bk ruwe vloer) | 6738.99 | 7530 | 7965481 | 7980541 | 0.0507446 | 0.080749 | V1 1e verd. (bk ruwe vloer) | 3730 | 3455 | 3670 | 6738.99 | 0 | Identity Data - Comments: SFB HEB200+300x15
1811969 | V2 2e verd. (bk ruwe vloer) | 3239 | 7530 | 3828495 | 3843555 | 0.0243897 | 0.0411768 | V2 2e verd. (bk ruwe vloer) | 7530 | 7255 | 7470 | 3239 | 0

# IfcBeam: btl_staal - SFB:SFB HEB220+420x15, btl_staal - SFB:SFB HEB220+420x15:1608629
In: V4 BK metselwerk
Type - PredefinedType: BEAM; Material: Metal - Steel - S355 JR (standaard-geintegreerde liggers)
Type - Other - Category: Structural Framing; Family Name: btl_staal - SFB
Type - Dimensions - bf: 220 mm; bu: 420 mm; bu_links: 210 mm; bu_rechts: 210 mm; h: 220 mm; halve breedte SFB: 110 mm; k: 34 mm; kr: 18 mm; tf: 16 mm; tu: 15 mm; tw: 9.5 mm; vrije oplegging plaat links: 100 mm; vrije oplegging plaat rechts: 100 mm; y: 77 mm
Type - Identity Data - Description: SFB HEB220+420x15; Model: ligger; Type Name: SFB HEB220+420x15
Type - Materials and Finishes - Structural Material: Metal - Steel - S355 JR (standaard-geintegreerde liggers)
Type - Structural - Section Shape: 0; A: 15400 mm2; W: 1.18482
Type - Pset_BeamCommon - IsExternal: no; LoadBearing: yes
Type - Pset_ReinforcementBarPitchOfBeam - Description: SFB HEB220+420x15
Pset_BeamCommon - Slope: 0 deg; Reference: SFB HEB220+420x15; Span: 31071 mm
Pset_QuantityTakeOff - Reference: SFB HEB220+420x15; sets with these values: 2
BaseQuantities - Length: 31071 mm; NetVolume: 0.45593 m3
Other - Family: btl_staal - SFB; End Extension Calculation: 3000 mm; Family and Type: btl_staal - SFB: SFB HEB220+420x15; Start Extension Calculation: 3000 mm; Type: SFB HEB220+420x15; Type Id: 1817583
Constraints - Cross-Section Rotation: 0 deg; Reference Level: V4 BK metselwerk; End Level Offset: -850 mm; Reference Level Elevation: 11700 mm; Start Level Offset: -850 mm
Construction - eind_oplegging: -12.7 mm; start_oplegging: -12.7 mm
Dimensions - Elevation at Bottom: 10615 mm; Elevation at Top: 10850 mm; Length: 31071 mm; Volume: 0.45593 m3
Identity Data - Has Association: yes; Comments: Brandwerend bekleden
Phasing - Phase Created: 2. nieuwbouw
Structural - Structural Usage: Other; Stick Symbol Location: Center of Geometry; Cut Length: 30848 mm; Start Attachment Type: End Elevation
Geometric Position - y Offset Value: 0 mm; yz Justification: Uniform; z Justification: Top; z Offset Value: 0 mm; Join Status: One or two joins disabled; y Justification: Origin; End Extension: 0 mm; Start Extension: 0 mm; Start Join Cutback: 12.7 mm

# IfcBeam: btl_staal - SFB:SFB HEB260+360x15, btl_staal - SFB:SFB HEB260+360x15:1751733
In: V2 2e verd. (bk ruwe vloer)
Type - PredefinedType: BEAM; Material: Metal - Steel - S355 JR (standaard-geintegreerde liggers)
Type - Other - Category: Structural Framing; Family Name: btl_staal - SFB
Type - Dimensions - bf: 260 mm; bu: 460 mm; bu_links: 230 mm; bu_rechts: 230 mm; h: 260 mm; halve breedte SFB: 130 mm; k: 41.5 mm; kr: 24 mm; tf: 17.5 mm; tu: 15 mm; tw: 10 mm; vrije oplegging plaat links: 100 mm; vrije oplegging plaat rechts: 100 mm; y: 94 mm
Type - Identity Data - Description: SFB HEB260+360x15; Model: ligger; Type Name: SFB HEB260+360x15
Type - Materials and Finishes - Structural Material: Metal - Steel - S355 JR (standaard-geintegreerde liggers)
Type - Structural - Section Shape: 0; A: 18740 mm2; W: 1.44158
Type - Pset_BeamCommon - IsExternal: no; LoadBearing: yes
Type - Pset_ReinforcementBarPitchOfBeam - Description: SFB HEB260+360x15
Pset_BeamCommon - Slope: 0 deg; Reference: SFB HEB260+360x15; Span: 22207.7 mm
Pset_QuantityTakeOff - Reference: SFB HEB260+360x15; sets with these values: 2
BaseQuantities - Length: 22207.7 mm; CrossSectionArea: 11350 mm2; OuterSurfaceArea: 34199924 mm2; GrossSurfaceArea: 34222624 mm2; GrossVolume: 0.252058 m3; NetVolume: 0.378642 m3
Other - Family: btl_staal - SFB; End Extension Calculation: 3000 mm; Family and Type: btl_staal - SFB: SFB HEB260+360x15; Start Extension Calculation: 3000 mm; Type: SFB HEB260+360x15; Type Id: 1968255
Constraints - Cross-Section Rotation: 0 deg; End Level Offset: -70 mm; Reference Level: 07400 V2 2e verd; Reference Level Elevation: 7600 mm; Start Level Offset: -70 mm
Construction - eind_oplegging: -12.7 mm; start_oplegging: -12.7 mm
Dimensions - Elevation at Bottom: 7255 mm; Elevation at Top: 7530 mm; Length: 22207.7 mm; Volume: 0.378642 m3
Identity Data - Has Association: yes
Phasing - Phase Created: 2. nieuwbouw
Structural - Structural Usage: Other; Stick Symbol Location: Center of Geometry; Cut Length: 22207.7 mm
Geometric Position - y Offset Value: 0 mm; yz Justification: Uniform; z Justification: Top; z Offset Value: 0 mm; Join Status: One or two joins disabled; y Justification: Origin; End Extension: 0 mm; Start Extension: 0 mm

# IfcBeam: btl_staal - SFB:SFB HEB260+460x15 (2)
Type - PredefinedType: BEAM; Material: Metal - Steel - S355 JR (standaard-geintegreerde liggers)
Type - Other - Category: Structural Framing; Family Name: btl_staal - SFB
Type - Dimensions - bf: 260 mm; bu: 460 mm; bu_links: 230 mm; bu_rechts: 230 mm; h: 260 mm; halve breedte SFB: 130 mm; k: 41.5 mm; kr: 24 mm; tf: 17.5 mm; tu: 15 mm; tw: 10 mm; vrije oplegging plaat links: 100 mm; vrije oplegging plaat rechts: 100 mm; y: 94 mm
Type - Identity Data - Description: SFB HEB260+460x15; Model: ligger; Type Name: SFB HEB260+460x15
Type - Materials and Finishes - Structural Material: Metal - Steel - S355 JR (standaard-geintegreerde liggers)
Type - Structural - Section Shape: 0; A: 18740 mm2; W: 1.44158
Type - Pset_BeamCommon - IsExternal: no; LoadBearing: yes
Type - Pset_ReinforcementBarPitchOfBeam - Description: SFB HEB260+460x15
Pset_BeamCommon - Slope: 0 deg; Reference: SFB HEB260+460x15; Span: 19632.3 mm
Pset_QuantityTakeOff - Reference: SFB HEB260+460x15; sets with these values: 2
BaseQuantities - Length: 19632.3 mm
Other - Family: btl_staal - SFB; End Extension Calculation: 3000 mm; Family and Type: btl_staal - SFB: SFB HEB260+460x15; Start Extension Calculation: 3000 mm; Type: SFB HEB260+460x15; Type Id: 1817839
Constraints - Cross-Section Rotation: 0 deg; End Level Offset: 0 mm; Start Level Offset: 0 mm
Construction - eind_oplegging: -12.7 mm; start_oplegging: -12.7 mm
Dimensions - Length: 19632.3 mm
Identity Data - Has Association: yes
Phasing - Phase Created: 2. nieuwbouw
Structural - Structural Usage: Other; Stick Symbol Location: Center of Geometry; Cut Length: 19632.3 mm
Geometric Position - y Offset Value: 0 mm; yz Justification: Uniform; z Justification: Top; z Offset Value: 0 mm; Join Status: One or two joins disabled; y Justification: Origin; End Extension: 0 mm; Start Extension: 0 mm
Name (btl_staal - SFB:SFB HEB260+460x15:...) | In | CrossSectionArea (mm2) | OuterSurfaceArea (mm2) | GrossSurfaceArea (mm2) | GrossVolume (m3) | NetVolume (m3) = Volume (m3) | Reference Level | Reference Level Elevation (mm) = Elevation at Top (mm) | Elevation at Bottom (mm)
1562991 | V1 1e verd. (bk ruwe vloer) | 11350 | 30233787 | 30256487 | 0.222827 | 0.345825 | V1 1e verd. (bk ruwe vloer) | 3730 | 3455 | Identity Data - Comments: Brandwerend bekleden
1573394 | V2 2e verd. (bk ruwe vloer) | 6900 | 18650713 | 18664513 | 0.135463 | 0.35829 | V2 2e verd. (bk ruwe vloer) | 7530 | 7255 | BaseQuantities - Height: 460 mm; Width: 15 mm

# IfcBeam: btl_staal - SFB:SFB HEM140+260x15, btl_staal - SFB:SFB HEM140+260x15:1608236
In: V3 dakvloer
Type - PredefinedType: BEAM; Material: Metal - Steel - S355 JR (standaard-geintegreerde liggers)
Type - Other - Category: Structural Framing; Family Name: btl_staal - SFB
Type - Dimensions - bf: 146 mm; bu: 260 mm; bu_links: 73 mm; bu_rechts: 187 mm; h: 160 mm; halve breedte SFB: 73 mm; k: 34 mm; kr: 12 mm; tf: 22 mm; tu: 15 mm; tw: 13 mm; vrije oplegging plaat links: 0 mm; vrije oplegging plaat rechts: 114 mm; y: 60 mm
Type - Identity Data - Description: SFB HEM140+260x15; Model: ligger; Type Name: SFB HEM140+260x15
Type - Materials and Finishes - Structural Material: Metal - Steel - S355 JR (standaard-geintegreerde liggers)
Type - Structural - Section Shape: 0; A: 13310 mm2; W: 1.02312
Type - Pset_BeamCommon - IsExternal: no; LoadBearing: yes
Type - Pset_ReinforcementBarPitchOfBeam - Description: SFB HEM140+260x15
Pset_BeamCommon - Slope: 0 deg; Reference: SFB HEM140+260x15; Span: 31079 mm
Pset_QuantityTakeOff - Reference: SFB HEM140+260x15; sets with these values: 2
BaseQuantities - Length: 31079 mm; Height: 260 mm; Width: 15 mm; CrossSectionArea: 3900 mm2; OuterSurfaceArea: 17093437 mm2; GrossSurfaceArea: 17101237 mm2; GrossVolume: 0.121208 m3; NetVolume: 0.367726 m3
Other - Family: btl_staal - SFB; End Extension Calculation: 3000 mm; Family and Type: btl_staal - SFB: SFB HEM140+260x15; Start Extension Calculation: 3000 mm; Type: SFB HEM140+260x15; Type Id: 1978156
Constraints - Cross-Section Rotation: 0 deg; End Level Offset: -50 mm; Reference Level: V3 dakvloer; Reference Level Elevation: 10840 mm; Start Level Offset: -50 mm
Construction - eind_oplegging: -12.7 mm; start_oplegging: -12.7 mm
Dimensions - Elevation at Bottom: 10615 mm; Elevation at Top: 10790 mm; Length: 31079 mm; Volume: 0.367726 m3
Identity Data - Has Association: yes; Comments: Brandwerend bekleden
Phasing - Phase Created: 2. nieuwbouw
Structural - Structural Usage: Other; Stick Symbol Location: Center of Geometry; Cut Length: 31079 mm
Geometric Position - Join Status: Both joins enabled; y Offset Value: 0 mm; yz Justification: Uniform; z Justification: Top; z Offset Value: 0 mm; y Justification: Origin; End Extension: 0 mm; Start Extension: 0 mm

# IfcBeam: btl_staal - SFB:SFB HEM240+450x15 (2)
Type - PredefinedType: BEAM; Material: Metal - Steel - S355 JR (standaard-geintegreerde liggers)
Type - Other - Category: Structural Framing; Family Name: btl_staal - SFB
Type - Dimensions - bf: 248 mm; bu: 450 mm; bu_links: 225 mm; bu_rechts: 225 mm; h: 270 mm; halve breedte SFB: 124 mm; k: 53 mm; kr: 21 mm; tf: 32 mm; tu: 15 mm; tw: 18 mm; vrije oplegging plaat links: 101 mm; vrije oplegging plaat rechts: 101 mm; y: 114 mm
Type - Identity Data - Description: SFB HEM240+450x15; Model: ligger; Type Name: SFB HEM240+450x15
Type - Materials and Finishes - Structural Material: Metal - Steel - S355 JR (standaard-geintegreerde liggers)
Type - Structural - Section Shape: 0; A: 26710 mm2; W: 2.05506
Type - Pset_BeamCommon - IsExternal: no; LoadBearing: yes
Type - Pset_ReinforcementBarPitchOfBeam - Description: SFB HEM240+450x15
Pset_BeamCommon - Slope: 0 deg; Reference: SFB HEM240+450x15
Pset_QuantityTakeOff - Reference: SFB HEM240+450x15; sets with these values: 2
BaseQuantities - Height: 450 mm; Width: 15 mm; CrossSectionArea: 6750 mm2
Other - Family: btl_staal - SFB; End Extension Calculation: 3000 mm; Family and Type: btl_staal - SFB: SFB HEM240+450x15; Start Extension Calculation: 3000 mm; Type: SFB HEM240+450x15; Type Id: 1751857
Constraints - Cross-Section Rotation: 0 deg; End Level Offset: 10 mm; Start Level Offset: 10 mm
Construction - eind_oplegging: -12.7 mm; start_oplegging: -12.7 mm
Identity Data - Has Association: yes
Phasing - Phase Created: 2. nieuwbouw
Structural - Structural Usage: Other; Stick Symbol Location: Center of Geometry
Geometric Position - y Offset Value: 0 mm; yz Justification: Uniform; z Justification: Top; z Offset Value: 0 mm; Join Status: One or two joins disabled; y Justification: Origin; End Extension: 0 mm; Start Extension: 0 mm
Name (btl_staal - SFB:SFB HEM240+450x15:...) | In | Span (mm) = BaseQuantities, Length (mm) = Dimensions, Length (mm) = Cut Length (mm) | OuterSurfaceArea (mm2) | GrossSurfaceArea (mm2) | GrossVolume (m3) | NetVolume (m3) = Volume (m3) | Reference Level | Reference Level Elevation (mm) | Elevation at Bottom (mm) | Elevation at Top (mm)
1555846 | V1 1e verd. (bk ruwe vloer) | 22200 | 20645962 | 20659462 | 0.14985 | 0.584525 | V1 1e verd. (bk ruwe vloer) | 3730 | 3455 | 3740 | Identity Data - Comments: Brandwerend bekleden
1573379 | V2 2e verd. (bk ruwe vloer) | 22078 | 20532498 | 20545998 | 0.149026 | 0.581313 | V2 2e verd. (bk ruwe vloer) | 7530 | 7255 | 7540

# IfcBeam: btl_staal - SFB:SFB HEM260+370x15, btl_staal - SFB:SFB HEM260+370x15:1554314
In: V1 1e verd. (bk ruwe vloer)
Type - PredefinedType: BEAM; Material: Metal - Steel - S355 JR (standaard-geintegreerde liggers)
Type - Other - Category: Structural Framing; Family Name: btl_staal - SFB
Type - Dimensions - bf: 268 mm; bu: 370 mm; bu_links: 236 mm; bu_rechts: 134 mm; h: 290 mm; halve breedte SFB: 134 mm; k: 56.5 mm; kr: 24 mm; tf: 32.5 mm; tu: 15 mm; tw: 18 mm; vrije oplegging plaat links: 102 mm; vrije oplegging plaat rechts: 0 mm; y: 129 mm
Type - Identity Data - Description: SFB HEM260+370x15; Model: ligger; Type Name: SFB HEM260+370x15
Type - Materials and Finishes - Structural Material: Metal - Steel - S355 JR (standaard-geintegreerde liggers)
Type - Structural - Section Shape: 0; A: 26660 mm2; W: 2.05114
Type - Pset_BeamCommon - IsExternal: no; LoadBearing: yes
Type - Pset_ReinforcementBarPitchOfBeam - Description: SFB HEM260+370x15
Pset_BeamCommon - Slope: 0 deg; Reference: SFB HEM260+370x15; Span: 8550.12 mm
Pset_QuantityTakeOff - Reference: SFB HEM260+370x15; sets with these values: 2
BaseQuantities - Length: 8550.12 mm; CrossSectionArea: 21470 mm2; OuterSurfaceArea: 24321000 mm2; GrossSurfaceArea: 24363940 mm2; GrossVolume: 0.323126 m3; NetVolume: 0.404304 m3
Other - End Extension Calculation: 3000 mm; Family: btl_staal - SFB; Family and Type: btl_staal - SFB: SFB HEM260+370x15; Start Extension Calculation: 3000 mm; Type: SFB HEM260+370x15; Type Id: 1769910
Constraints - Cross-Section Rotation: 0 deg; End Level Offset: -192.5 mm; Reference Level: V1 1e verd. (bk ruwe vloer); Reference Level Elevation: 3730 mm; Start Level Offset: -192.5 mm
Construction - eind_oplegging: -12.7 mm; start_oplegging: -12.7 mm
Dimensions - Elevation at Bottom: 3232.5 mm; Elevation at Top: 3537.5 mm; Length: 8550.12 mm; Volume: 0.404304 m3
Identity Data - Has Association: yes; Comments: Brandwerend belkeden
Phasing - Phase Created: 2. nieuwbouw
Structural - Structural Usage: Other; Cut Length: 15050.1 mm; Stick Symbol Location: Center of Geometry
Geometric Position - y Offset Value: 0 mm; yz Justification: Uniform; z Justification: Top; z Offset Value: 0 mm; Join Status: One or two joins disabled; End Extension: 3250 mm; Start Extension: 3250 mm; y Justification: Origin

# IfcBeam: btl_staal - Strip b x h:10x100 verticaal (6)
In: V1 1e verd. (bk ruwe vloer)
Type - Other - Category: Structural Framing; Family Name: btl_staal - Strip b x h
Type - Dimensions - b (x as): 10 mm; h (y as): 100 mm
Type - Identity Data - Description: wbv 100x10; Model: strip verticaal; OmniClass Number: 23.25.30.11.14.14; OmniClass Title: Beams; Type Name: 10x100 verticaal
Type - Materials and Finishes - Structural Material: Metal - Steel - S235 JRG2 (standaard)
Type - Structural - Section Shape: 0
Type - Pset_BeamCommon - IsExternal: no; LoadBearing: yes
Type - Pset_ReinforcementBarPitchOfBeam - Description: wbv 100x10
Material: Metal - Steel - S235 JRG2 (standaard)
BaseQuantities - CrossSectionArea: 1000 mm2
Pset_BeamCommon - Reference: 10x100 verticaal
Pset_QuantityTakeOff - Reference: 10x100 verticaal; sets with these values: 2
Other - Family: btl_staal - Strip b x h; End Extension Calculation: 3000 mm; Family and Type: btl_staal - Strip b x h: 10x100 verticaal; Start Extension Calculation: 3000 mm; Type: 10x100 verticaal; Type Id: 1567478
Constraints - Cross-Section Rotation: 0 deg; Reference Level: 03800 V1 1e verd; Reference Level Elevation: 3800 mm
Construction - End Extension: -12.5 mm; Start Extension: -12.5 mm
Phasing - Phase Created: 2. nieuwbouw
Structural - Structural Usage: Other; End Attachment Elevation: 0 mm; Start Attachment Elevation: 0 mm
Geometric Position - yz Justification: Uniform; z Offset Value: 0 mm; Join Status: One or two joins disabled; y Justification: Origin; z Justification: Origin
Name (btl_staal - Strip b x h:10x100 verticaal:...) | BaseQuantities, Length (mm) = Cut Length (mm) | OuterSurfaceArea (mm2) | GrossVolume (m3) = NetVolume (m3) = Volume (m3) | Span (mm) = Dimensions, Length (mm) | Slope (deg) | Has Association | y Offset Value (mm) | End Extension (mm) | Start Extension (mm)
1609640 | 5003.94 | 1100866 | 0.00500394 | 5303.94 | 43.9336 | yes | 0 | 0 | -300
1767246 | 4974.37 | 1094362 | 0.00497437 | 5274.37 | 44.2438 | yes | 0 | 0 | -300
2055033 | 7837.56 | 1724264 | 0.00783756 | 8137.56 | 26.8864 | no | 5 | -300 | 0
2055198 | 7807.79 | 1717714 | 0.00780779 | 8107.79 | 27.3904 | no | -5 | -300 | 0
2107251 | 7807.79 | 1717714 | 0.00780779 | 8107.79 | 27.3904 | no | 5 | -300 | 0
2107286 | 7837.56 | 1724264 | 0.00783756 | 8137.56 | 26.8864 | no | -5 | -300 | 0

# IfcBeam: btl_staal - Strip b x h:120x12 Vwvb (14)
Type - Other - Category: Structural Framing; Family Name: btl_staal - Strip b x h
Type - Dimensions - b (x as): 12 mm; h (y as): 120 mm
Type - Identity Data - Description: WVB 120x12; Model: Vwvb; OmniClass Number: 23.25.30.11.14.14; OmniClass Title: Beams; Type Name: 120x12 Vwvb
Type - Materials and Finishes - Structural Material: Metal - Steel - S235 JRG2 (standaard)
Type - Structural - Section Shape: 0
Type - Pset_BeamCommon - IsExternal: no; LoadBearing: yes
Type - Pset_ReinforcementBarPitchOfBeam - Description: WVB 120x12
Material: Metal - Steel - S235 JRG2 (standaard)
BaseQuantities - CrossSectionArea: 1440 mm2
Pset_BeamCommon - Reference: 120x12 Vwvb
Pset_QuantityTakeOff - Reference: 120x12 Vwvb; sets with these values: 2
Other - Family: btl_staal - Strip b x h; Family and Type: btl_staal - Strip b x h: 120x12 Vwvb; Type: 120x12 Vwvb; Type Id: 1818178
Constraints - Cross-Section Rotation: 0 deg
Phasing - Phase Created: 2. nieuwbouw
Structural - Structural Usage: Other; End Attachment Elevation: 0 mm
Geometric Position - yz Justification: Uniform; z Offset Value: 0 mm; y Justification: Origin; z Justification: Origin
Name (btl_staal - Strip b x h:120x12 Vwvb:...) | In | BaseQuantities, Length (mm) = Cut Length (mm) | OuterSurfaceArea (mm2) | GrossVolume (m3) = NetVolume (m3) = Volume (m3) | Span (mm) = Dimensions, Length (mm) | Slope (deg) | End Extension Calculation (mm) | Start Extension Calculation (mm) | Reference Level | Reference Level Elevation (mm) | Construction, End Extension (mm) | Construction, Start Extension (mm) | Has Association | Start Attachment Elevation (mm) | Join Status | Geometric Position, End Extension (mm) | Geometric Position, Start Extension (mm) | y Offset Value (mm)
1609529 | V1 1e verd. (bk ruwe vloer) | 7572.66 | 1999183 | 0.0109046 | 7872.66 | 23.7283 | 3000 | 3000 | 03800 V1 1e verd | 3800 | -12.5 | -12.5 | yes | 0 | One or two joins disabled | 0 | -300 | 5
1686763 | V1 1e verd. (bk ruwe vloer) | 8777.03 | 2317136 | 0.0126389 | 8777.03 | 24.5769 | 3000 | 3000 | 03800 V1 1e verd | 3800 | -12.5 | -12.5 | yes | 0 | One or two joins disabled | 0 | 0 | 0
1686809 | V2 2e verd. (bk ruwe vloer) | 8366.86 | 2208851 | 0.0120483 | 8537.33 | 21.4015 | 3000 | 3000 | V2 2e verd. (bk ruwe vloer) | 7530 | -12.5 | -12.5 | yes |  | Both joins enabled | 0 | 0 | 0 | Structural - Start Attachment Distance: 183.985 mm; Start Attachment Type: Distance; Start of Attachment to Reference Element: End; Geometric Position - Start Join Cutback: 12.7 mm
1686859 | V2 2e verd. (bk ruwe vloer) | 8491.93 | 2241869 | 0.0122284 | 8491.93 | 23.9629 | 3000 | 3000 | V2 2e verd. (bk ruwe vloer) | 7530 | -12.5 | -12.5 | yes | 0 | One or two joins disabled | 0 | 0 | 0
1766725 | V1 1e verd. (bk ruwe vloer) | 7593.8 | 2004762 | 0.0109351 | 7893.25 | 23.3463 | 3000.54 | 3000 | 03800 V1 1e verd | 3800 | -11.9559 | -12.5 | yes | 0 | One or two joins disabled | 0 | -300 | -5
1767947 | V1 1e verd. (bk ruwe vloer) | 7571.52 | 1998881 | 0.010903 | 7871.52 | 23.7319 | 3000 | 3000 | 03800 V1 1e verd | 3800 | -12.5 | -12.5 | yes | 0 | One or two joins disabled | 0 | -300 | -5
1767949 | V1 1e verd. (bk ruwe vloer) | 7647.88 | 2019042 | 0.011013 | 7947.88 | 24.1698 | 3000 | 3000 | 03800 V1 1e verd | 3800 | -12.5 | -12.5 | yes | 0 | One or two joins disabled | 0 | -300 | 5
1878802 | V1 1e verd. (bk ruwe vloer) | 8656.07 | 2285203 | 0.0124647 | 8656.07 | 24.5769 | 3000 | 3000 | 03800 V1 1e verd | 3800 | -12.5 | -12.5 | yes | 0 | One or two joins disabled | 0 | 0 | 0
2053132 | V1 1e verd. (bk ruwe vloer) | 7838.34 | 2069322 | 0.0112872 | 8138.34 | 26.8837 | 3000 | 3000 | 03800 V1 1e verd | 3800 | -12.5 | -12.5 | no | 0 | One or two joins disabled | -300 | 0 | -5
2053191 | V1 1e verd. (bk ruwe vloer) | 7778.81 | 2053605 | 0.0112015 | 8107.57 | 27.3912 | 3000 | 2971.24 | 03800 V1 1e verd | 3800 | -12.5 | -41.265 | no | 0 | One or two joins disabled | -300 | 0 | 5
2053635 | V1 1e verd. (bk ruwe vloer) | 4637.32 | 1224251 | 0.00667773 | 4937.32 | 39.9138 | 3000 | 3000 | 03800 V1 1e verd | 3800 | -12.5 | -12.5 | no | 0 | One or two joins disabled | -300 | 0 | 0
2066905 | V1 1e verd. (bk ruwe vloer) | 4730.1 | 1248747 | 0.00681135 | 4730.1 | 42.8351 | 3000 | 3000 | 03800 V1 1e verd | 3800 | -12.5 | -12.5 | no | 0 | One or two joins disabled | 0 | 0 | 0
2107055 | V1 1e verd. (bk ruwe vloer) | 7778.81 | 2053605 | 0.0112015 | 8107.57 | 27.3912 | 3000 | 2971.24 | 03800 V1 1e verd | 3800 | -12.5 | -41.265 | no | 0 | One or two joins disabled | -300 | 0 | -5
2107090 | V1 1e verd. (bk ruwe vloer) | 7838.34 | 2069322 | 0.0112872 | 8138.34 | 26.8837 | 3000 | 3000 | 03800 V1 1e verd | 3800 | -12.5 | -12.5 | no | 0 | One or two joins disabled | -300 | 0 | 5

# IfcBeam: btl_staal - Strip b x h:120x15 Vwvb (12)
Type - Other - Category: Structural Framing; Family Name: btl_staal - Strip b x h
Type - Dimensions - b (x as): 15 mm; h (y as): 120 mm
Type - Identity Data - Description: VWVB 120x15; Model: Vwvb; OmniClass Number: 23.25.30.11.14.14; OmniClass Title: Beams; Type Name: 120x15 Vwvb
Type - Materials and Finishes - Structural Material: Metal - Steel - S235 JRG2 (standaard)
Type - Structural - Section Shape: 0
Type - Pset_BeamCommon - IsExternal: no; LoadBearing: yes
Type - Pset_ReinforcementBarPitchOfBeam - Description: VWVB 120x15
Material: Metal - Steel - S235 JRG2 (standaard)
BaseQuantities - CrossSectionArea: 1800 mm2
Pset_BeamCommon - Reference: 120x15 Vwvb
Pset_QuantityTakeOff - Reference: 120x15 Vwvb; sets with these values: 2
Other - Family: btl_staal - Strip b x h; End Extension Calculation: 3000 mm; Family and Type: btl_staal - Strip b x h: 120x15 Vwvb; Start Extension Calculation: 3000 mm; Type: 120x15 Vwvb; Type Id: 2107517
Constraints - Cross-Section Rotation: 0 deg
Construction - End Extension: -12.5 mm; Start Extension: -12.5 mm
Identity Data - Has Association: yes
Phasing - Phase Created: 2. nieuwbouw
Structural - Structural Usage: Other
Geometric Position - y Offset Value: 0 mm; yz Justification: Uniform; z Offset Value: 0 mm; y Justification: Origin; End Extension: 0 mm; Start Extension: 0 mm; z Justification: Origin
Name (btl_staal - Strip b x h:120x15 Vwvb:...) | In | BaseQuantities, Length (mm) = Cut Length (mm) | OuterSurfaceArea (mm2) | GrossVolume (m3) = NetVolume (m3) = Volume (m3) | Span (mm) = Dimensions, Length (mm) | Slope (deg) | Reference Level | Reference Level Elevation (mm) | Start Attachment Type | Start Attachment Distance (mm) | Start of Attachment to Reference Element | Join Status | Start Join Cutback (mm) | End Attachment Distance (mm) | End Attachment Type | End of Attachment to Reference Element | End Join Cutback (mm)
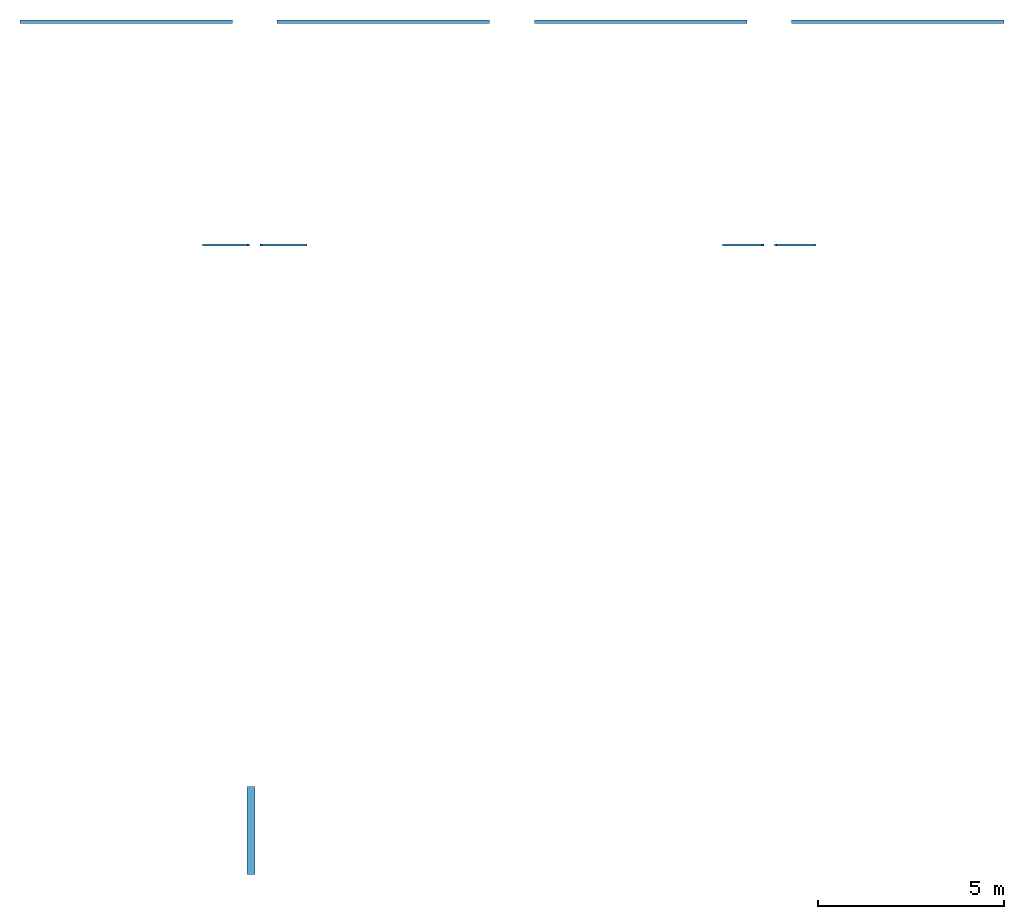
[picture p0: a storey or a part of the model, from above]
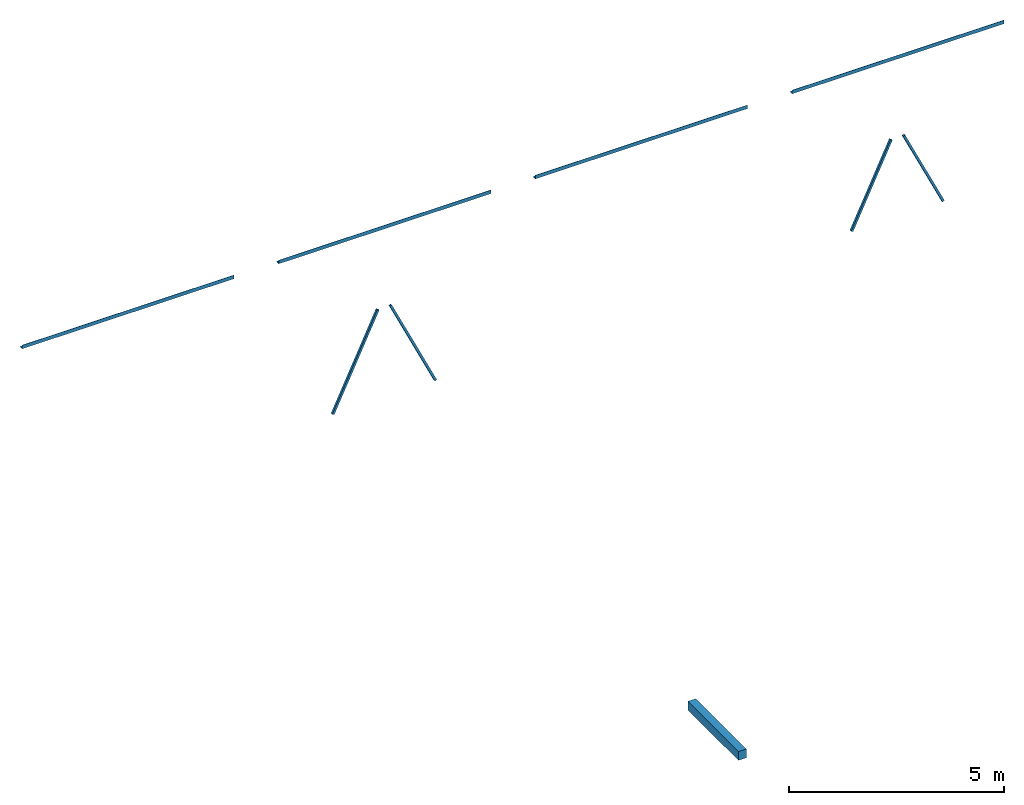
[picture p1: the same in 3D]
Properties of the parts of a building model (IFC2X3), part 4 of 6

# IfcBeam: btl_staal - Strip b x h:120x15 Vwvb (12)
Name (btl_staal - Strip b x h:120x15 Vwvb:...) | In | BaseQuantities, Length (mm) = Cut Length (mm) | OuterSurfaceArea (mm2) | GrossVolume (m3) = NetVolume (m3) = Volume (m3) | Span (mm) = Dimensions, Length (mm) | Slope (deg) | Reference Level | Reference Level Elevation (mm) | Start Attachment Type | Start Attachment Distance (mm) | Start of Attachment to Reference Element | Join Status | Start Join Cutback (mm) | End Attachment Distance (mm) | End Attachment Type | End of Attachment to Reference Element | End Join Cutback (mm)
1817003 | KDV V2 werkbalken | 3792.93 | 1024091 | 0.00682728 | 4047.75 | 50.0275 | V2 ok vloer | 7270 | Distance | 5739 | Start | One or two joins disabled | 12.7 | Structural - End Attachment Elevation: 0 mm
1817076 | KDV V2 werkbalken | 3792.93 | 1024091 | 0.00682728 | 4047.75 | 50.0275 | V2 ok vloer | 7270 |  |  |  | One or two joins disabled |  | 8338.99 | Distance | Start | 12.7 | Structural - Start Attachment Elevation: 0 mm
1817134 | KDV V1 1e verd. (bk ruwe vloer) | 4236.32 | 1143807 | 0.00762538 | 4604.34 | 55.6198 | V1 ok vloer | 3470 | Distance | 5739 | Start | Both joins enabled | 12.7 | 8338.99 | Distance | Start | 12.7
1817210 | KDV V1 1e verd. (bk ruwe vloer) | 4236.32 | 1143807 | 0.00762538 | 4604.34 | 55.6198 | V1 ok vloer | 3470 | Distance | 5739 | Start | Both joins enabled | 12.7 | 8338.99 | Distance | Start | 12.7
1817274 | F1 begg (bk ruwe vloer) | 3986.15 | 1076259 | 0.00717506 | 4435.04 | 54.1096 | F1 begg (bk ruwe vloer) | -70 | Distance | 5739 | Start | Both joins enabled | 12.7 |  |  |  | 12.7 | Structural - End Attachment Elevation: 0 mm; End Attachment Level Reference: F1 begg (bk ruwe vloer)
1817315 | F1 begg (bk ruwe vloer) | 3986.15 | 1076259 | 0.00717506 | 4435.04 | 54.1096 | F1 begg (bk ruwe vloer) | -70 |  |  |  | Both joins enabled | 12.7 | 8338.99 | Distance | Start | 12.7 | Structural - Start Attachment Elevation: 0 mm; Start Attachment Level Reference: F1 begg (bk ruwe vloer)
1817378 | KDV V2 werkbalken | 3793.29 | 1024187 | 0.00682792 | 4048.13 | 50.021 | V2 ok vloer | 7270 | Distance | 8350.15 | End | One or two joins disabled | 12.7 | Structural - End Attachment Elevation: 0 mm
1817380 | KDV V2 werkbalken | 3793.29 | 1024187 | 0.00682791 | 4048.13 | 50.021 | V2 ok vloer | 7270 |  |  |  | One or two joins disabled |  | 5749.8 | Distance | End | 12.7 | Structural - Start Attachment Elevation: 0 mm
1817382 | KDV V1 1e verd. (bk ruwe vloer) | 4236.32 | 1143807 | 0.00762538 | 4604.34 | 55.6198 | V1 ok vloer | 3470 | Distance | 8306.99 | End | Both joins enabled | 12.7 | 5750.01 | Distance | End | 12.7
1817384 | KDV V1 1e verd. (bk ruwe vloer) | 4236.32 | 1143807 | 0.00762538 | 4604.34 | 55.6198 | V1 ok vloer | 3470 | Distance | 8349.99 | End | Both joins enabled | 12.7 | 5707.01 | Distance | End | 12.7
1817386 | F1 begg (bk ruwe vloer) | 3986.15 | 1076262 | 0.00717508 | 4435.05 | 54.1094 | F1 begg (bk ruwe vloer) | -70 | Distance | 8306.99 | End | Both joins enabled | 12.7 |  |  |  | 12.7 | Structural - End Attachment Elevation: 0 mm; End Attachment Level Reference: F1 begg (bk ruwe vloer)
1817388 | F1 begg (bk ruwe vloer) | 3986.15 | 1076259 | 0.00717506 | 4435.04 | 54.1096 | F1 begg (bk ruwe vloer) | -70 |  |  |  | Both joins enabled | 12.7 | 5707.01 | Distance | End | 12.7 | Structural - Start Attachment Elevation: 0 mm; Start Attachment Level Reference: F1 begg (bk ruwe vloer)

# IfcBeam: btl_staal - Strip b x h:300x15 onderplaat, btl_staal - Strip b x h:300x15 onderplaat:1890953
In: KDV V1 1e verd. (bk ruwe vloer)
Type - Other - Category: Structural Framing; Family Name: btl_staal - Strip b x h
Type - Dimensions - b (x as): 300 mm; h (y as): 15 mm
Type - Identity Data - Description: Onderplaat 300x15; Model: strip horizontaal; OmniClass Number: 23.25.30.11.14.14; OmniClass Title: Beams; Type Name: 300x15 onderplaat
Type - Materials and Finishes - Structural Material: Metal - Steel - S235 JRG2 (standaard)
Type - Structural - Section Shape: 0
Type - Pset_BeamCommon - IsExternal: no; LoadBearing: yes
Type - Pset_ReinforcementBarPitchOfBeam - Description: Onderplaat 300x15
Material: Metal - Steel - S235 JRG2 (standaard)
BaseQuantities - Length: 1523.89 mm; CrossSectionArea: 4500 mm2; OuterSurfaceArea: 960054 mm2; GrossVolume: 0.00685753 m3; NetVolume: 0.00685753 m3
Pset_BeamCommon - Slope: 0 deg; Reference: 300x15 onderplaat; Span: 1523.89 mm
Pset_QuantityTakeOff - Reference: 300x15 onderplaat; sets with these values: 2
Other - Family: btl_staal - Strip b x h; End Extension Calculation: 3000 mm; Family and Type: btl_staal - Strip b x h: 300x15 onderplaat; Start Extension Calculation: 3000 mm; Type: 300x15 onderplaat; Type Id: 1891114
Constraints - Cross-Section Rotation: 0 deg; End Level Offset: 0 mm; Start Level Offset: 0 mm; Reference Level: V1 ok vloer; Reference Level Elevation: 3470 mm
Construction - End Extension: -12.5 mm; Start Extension: -12.5 mm
Dimensions - Elevation at Bottom: 3455 mm; Elevation at Top: 3470 mm; Length: 1523.89 mm; Volume: 0.00685753 m3
Identity Data - Has Association: yes
Phasing - Phase Created: 2. nieuwbouw
Structural - Structural Usage: Other; Stick Symbol Location: Center of Geometry; Cut Length: 1523.89 mm
Geometric Position - Join Status: Both joins enabled; y Offset Value: 0 mm; yz Justification: Uniform; z Justification: Top; z Offset Value: 0 mm; y Justification: Origin; End Extension: 0 mm; Start Extension: 0 mm

# IfcBeam: btl_staal - Strip b x h:schotje tpv vide (4)
In: V1 1e verd. (bk ruwe vloer)
Type - Other - Category: Structural Framing; Family Name: btl_staal - Strip b x h
Type - Dimensions - b (x as): 12 mm; h (y as): 150 mm
Type - Identity Data - Model: strip verticaal; OmniClass Number: 23.25.30.11.14.14; OmniClass Title: Beams; Type Name: schotje tpv vide
Type - Materials and Finishes - Structural Material: Metal - Steel - S235 JRG2 (standaard)
Type - Structural - Section Shape: 0
Type - Pset_BeamCommon - IsExternal: no; LoadBearing: yes
Material: Metal - Steel - S235 JRG2 (standaard)
BaseQuantities - GrossSurfaceArea: 0 mm2; NetVolume: 0.000255 m3
Pset_BeamCommon - Reference: schotje tpv vide; Span: 302.161 mm; Slope: 55.7843 deg
Pset_QuantityTakeOff - Reference: schotje tpv vide; sets with these values: 2
Other - Family: btl_staal - Strip b x h; End Extension Calculation: 3000 mm; Family and Type: btl_staal - Strip b x h: schotje tpv vide; Start Extension Calculation: 3000 mm; Type: schotje tpv vide; Type Id: 1830299
Constraints - Cross-Section Rotation: 0 deg; Start Level Offset: 0 mm; Reference Level: V1 1e verd. (bk ruwe vloer); End Level Offset: -249.865 mm; Reference Level Elevation: 3730 mm
Construction - End Extension: -12.5 mm; Start Extension: -12.5 mm
Dimensions - Length: 302.161 mm; Volume: 0.000255 m3
Identity Data - Has Association: yes
Phasing - Phase Created: 2. nieuwbouw
Structural - Structural Usage: Other; Stick Symbol Location: Center of Geometry; Cut Length: 302.161 mm
Geometric Position - y Offset Value: 0 mm; yz Justification: Uniform; z Justification: Top; z Offset Value: 0 mm; Join Status: One or two joins disabled; y Justification: Origin; End Extension: 0 mm; Start Extension: 0 mm
Name (btl_staal - Strip b x h:schotje tpv vide:...) | Group
1830362 | Model Group:koppeling stalen kolom aan ligget tpv vide (members excluded):1831325
1831376 | Model Group:koppeling stalen kolom aan ligget tpv vide (members excluded):1831406
1831447 | Model Group:koppeling stalen kolom aan ligget tpv vide (members excluded):1831465
1831518 | Model Group:koppeling stalen kolom aan ligget tpv vide (members excluded):1831536

# IfcBeam: btl_staal - THQ:THQ 300x8+100x18+200x8, btl_staal - THQ:THQ 300x8+100x18+200x8:1967441
In: V1 1e verd. (bk ruwe vloer)
Type - Other - Category: Structural Framing; Family Name: btl_staal - THQ
Type - Dimensions - bo: 100 mm; bu: 200 mm; bu_links: 100 mm; bu_rechts: 100 mm; h: 300 mm; halve breedte THQ: 58 mm; info = onderplaat bu x tu: h x tw + bo x to + bu x tu; to: 8 mm; tu: 8 mm; tw: 8 mm; vrije oplegging plaat links: 42 mm; vrije oplegging plaat rechts: 42 mm
Type - Identity Data - Model: ligger; Type Name: THQ 300x8+100x18+200x8
Type - Materials and Finishes - Structural Material: Metal - Steel - S355 JR (standaard-geintegreerde liggers)
Type - Structural - Section Shape: 0; A: 13725 mm2; W: 1.07604
Type - Pset_BeamCommon - IsExternal: no; LoadBearing: yes
Material: Metal - Steel - S355 JR (standaard-geintegreerde liggers)
BaseQuantities - Length: 6050 mm; CrossSectionArea: 7200 mm2; OuterSurfaceArea: 10890000 mm2; GrossVolume: 0.04356 m3; NetVolume: 0.04356 m3
Pset_BeamCommon - Slope: 0 deg; Reference: THQ 300x8+100x18+200x8; Span: 5450 mm
Pset_QuantityTakeOff - Reference: THQ 300x8+100x18+200x8; sets with these values: 2
Other - End Extension Calculation: 3000 mm; Family: btl_staal - THQ; Family and Type: btl_staal - THQ: THQ 300x8+100x18+200x8; Start Extension Calculation: 3000 mm; Type: THQ 300x8+100x18+200x8; Type Id: 1967429
Constraints - Cross-Section Rotation: 0 deg; Reference Level: V1 1e verd. (bk ruwe vloer); End Level Offset: -975.664 mm; Reference Level Elevation: 3730 mm; Start Level Offset: -975.664 mm
Construction - eind_oplegging: -12.7 mm; start_oplegging: -12.7 mm
Dimensions - Elevation at Bottom: 2446.34 mm; Elevation at Top: 2754.34 mm; Length: 5450 mm; Volume: 0.04356 m3
Identity Data - Has Association: yes
Phasing - Phase Created: 2. nieuwbouw
Structural - Structural Usage: Other; Stick Symbol Location: Center of Geometry; Cut Length: 6050 mm
Geometric Position - Join Status: Both joins enabled; y Offset Value: 0 mm; yz Justification: Uniform; z Justification: Top; z Offset Value: 0 mm; y Justification: Origin; End Extension: 300 mm; Start Extension: 300 mm

# IfcBeam: btl_staal - UNP met onderstrip:UNP200+strip 190x10 (2)
Type - PredefinedType: BEAM; Material: Metal - Steel - S235 JRG2 (standaard)
Type - Other - Category: Structural Framing; Family Name: btl_staal - UNP met onderstrip; strip vrije oplegging buiten UNP reken: 75 mm
Type - Dimensions - bf: 75 mm; d: 200 mm; tf: 11.5 mm; tw: 8.5 mm; x: 20.1 mm
Type - Division Geometry - strip breedte: 190 mm; strip dikte: 10 mm; strip einde vanaf End Join pt2: 0 mm; strip einde vanaf Start Join pt1: 0 mm; strip pos vanaf rechte rand UNP: -115 mm; strip vrije oplegging buiten UNP: 0 mm
Type - Identity Data - Description: UNP200+strip 190x10; Model: ligger+strip; Type Name: UNP200+strip 190x10
Type - Materials and Finishes - Structural Material: Metal - Steel - S235 JRG2 (standaard)
Type - Structural - Section Shape: 0; A: 3220 mm2; W: 0.247716
Type - Pset_BeamCommon - IsExternal: no; LoadBearing: yes
Type - Pset_ReinforcementBarPitchOfBeam - Description: UNP200+strip 190x10
Pset_BeamCommon - Slope: 0 deg; Reference: UNP200+strip 190x10; Span: 1495.14 mm
Pset_QuantityTakeOff - Reference: UNP200+strip 190x10; sets with these values: 2
BaseQuantities - Length: 1495.14 mm; CrossSectionArea: 3929.92 mm2; OuterSurfaceArea: 992167 mm2; GrossSurfaceArea: 1000027 mm2; GrossVolume: 0.00587579 m3; NetVolume: 0.00871657 m3
Other - End Extension Calculation: 3000 mm; Family: btl_staal - UNP met onderstrip; Family and Type: btl_staal - UNP met onderstrip: UNP200+strip 190x10; Start Extension Calculation: 3000 mm; Type: UNP200+strip 190x10; Type Id: 1862766
Constraints - Cross-Section Rotation: 0 deg; End Level Offset: -60 mm; Start Level Offset: -60 mm
Construction - EindOplegging: -12.5 mm; StartOplegging: -12.5 mm
Dimensions - Length: 1495.14 mm; Volume: 0.00284078 m3
Identity Data - Has Association: yes
Phasing - Phase Created: 2. nieuwbouw
Structural - Structural Usage: Other; Stick Symbol Location: Center of Geometry; Cut Length: 1495.14 mm
Geometric Position - Join Status: Both joins enabled; y Offset Value: 0 mm; yz Justification: Uniform; z Justification: Top; z Offset Value: 0 mm; y Justification: Origin; End Extension: 0 mm; Start Extension: 0 mm
Name (btl_staal - UNP met onderstrip:UNP200+strip 190x10:...) | In | Reference Level | Reference Level Elevation (mm) | Elevation at Bottom (mm) | Elevation at Top (mm)
1863466 | V1 1e verd. (bk ruwe vloer) | V1 1e verd. (bk ruwe vloer) | 3730 | 3460 | 3670
1868649 | V2 2e verd. (bk ruwe vloer) | V2 2e verd. (bk ruwe vloer) | 7530 | 7260 | 7470 | Geometric Position - Start Join Cutback: 0 mm

# IfcBeam: btl_staal - UNP:UNP160 (5)
In: V3 dakvloer
Type - Other - Category: Structural Framing; Family Name: btl_staal - UNP
Type - Dimensions - bf: 65 mm; d: 160 mm; tf: 10.5 mm; tw: 7.5 mm; x: 18.4 mm
Type - Identity Data - Description: UNP 160; Model: ligger; Type Name: UNP160
Type - Materials and Finishes - Structural Material: Metal - Steel - S235 JRG2 (standaard)
Type - Structural - Section Shape: 0; A: 2401 mm2; W: 0.184855
Type - Pset_BeamCommon - IsExternal: no; LoadBearing: yes
Type - Pset_ReinforcementBarPitchOfBeam - Description: UNP 160
Material: Metal - Steel - S235 JRG2 (standaard)
BaseQuantities - CrossSectionArea: 2931.16 mm2
Pset_BeamCommon - Reference: UNP160
Pset_QuantityTakeOff - Reference: UNP160; sets with these values: 2
Other - Family: btl_staal - UNP; End Extension Calculation: 3000 mm; Family and Type: btl_staal - UNP: UNP160; Start Extension Calculation: 3000 mm; Type: UNP160; Type Id: 2123955
Constraints - Reference Level: V3 dakvloer; Reference Level Elevation: 10840 mm
Construction - EindOplegging: -12.5 mm; StartOplegging: -12.5 mm
Identity Data - Has Association: no
Phasing - Phase Created: 2. nieuwbouw
Structural - Structural Usage: Other; Stick Symbol Location: Center of Geometry; Angle: 0 deg
Geometric Position - y Offset Value: 0 mm; yz Justification: Uniform; z Justification: Top; z Offset Value: 0 mm; Join Status: One or two joins disabled; y Justification: Origin; End Extension: 0 mm; Start Extension: 0 mm
Name (btl_staal - UNP:UNP160:...) | BaseQuantities, Length (mm) = Cut Length (mm) | OuterSurfaceArea (mm2) | GrossVolume (m3) | NetVolume (m3) = Volume (m3) | Span (mm) = Dimensions, Length (mm) | Slope (deg) | Cross-Section Rotation (deg) | End Level Offset (mm) | Start Level Offset (mm)
2108071 | 3060.01 | 1677555 | 0.00896937 | 0.00879489 | 3084.87 | 20.9696 | 0 | 425.42 | 1529.41
2109160 | 3060.01 | 1677555 | 0.00896937 | 0.00879489 | 3084.87 | 20.9696 | 0 | 425.42 | 1529.41
2124033 | 3060.01 | 1677555 | 0.00896937 | 0.00879489 | 3084.87 | 20.9696 | 0 | 425.42 | 1529.41
2124565 | 1377.09 | 754950 | 0.00403648 | 0.00403648 | 1395.5 | 0.0018786 | -20.87 | 936.354 | 936.4 | Geometric Position - Start Join Cutback: 0 mm
2124865 | 1512.56 | 829212 | 0.00443354 | 0.00443354 | 1530.96 | 0.0018786 | -20.87 | 936.35 | 936.4 | Geometric Position - Start Join Cutback: 0 mm

# IfcBeam: btl_staal - UNP:UNP180. (4)
In: V3 dakvloer
Type - Other - Category: Structural Framing; Family Name: btl_staal - UNP
Type - Dimensions - bf: 70 mm; d: 180 mm; tf: 11 mm; tw: 8 mm; x: 19.3 mm
Type - Identity Data - Description: UNP 180; Model: ligger; Type Name: UNP180.
Type - Materials and Finishes - Structural Material: Metal - Steel - S235 JRG2 (standaard)
Type - Structural - Section Shape: 0; A: 2796 mm2; W: 0.215256
Type - Pset_BeamCommon - IsExternal: no; LoadBearing: yes
Type - Pset_ReinforcementBarPitchOfBeam - Description: UNP 180
Material: Metal - Steel - S235 JRG2 (standaard)
BaseQuantities - CrossSectionArea: 3412.83 mm2
Pset_BeamCommon - Slope: 0 deg; Reference: UNP180.
Pset_QuantityTakeOff - Reference: UNP180.; sets with these values: 2
Other - End Extension Calculation: 3000 mm; Family: btl_staal - UNP; Family and Type: btl_staal - UNP: UNP180.; Start Extension Calculation: 3000 mm; Type: UNP180.; Type Id: 2202595
Constraints - Cross-Section Rotation: 0 deg; Reference Level: V3 dakvloer; End Level Offset: 860 mm; Reference Level Elevation: 10840 mm; Start Level Offset: 860 mm
Construction - EindOplegging: -12.5 mm; StartOplegging: -12.5 mm
Dimensions - Elevation at Bottom: 11520 mm; Elevation at Top: 11700 mm
Phasing - Phase Created: 2. nieuwbouw
Structural - Structural Usage: Other; Stick Symbol Location: Center of Geometry; Angle: 0 deg
Geometric Position - y Offset Value: 0 mm; yz Justification: Uniform; z Justification: Top; z Offset Value: 0 mm; y Justification: Origin; End Extension: 0 mm; Start Extension: 0 mm
Name (btl_staal - UNP:UNP180.:...) | BaseQuantities, Length (mm) = Cut Length (mm) | OuterSurfaceArea (mm2) | GrossVolume (m3) = NetVolume (m3) = Volume (m3) | Span (mm) = Dimensions, Length (mm) | Has Association | End Attachment Type | Join Status | End Join Cutback (mm)
1734745 | 3359.81 | 2035731 | 0.0114665 | 3427.05 | yes | End Elevation | One or two joins disabled | 0
1750656 | 5220.8 | 3163316 | 0.0178177 | 5222.58 | yes | End Elevation | One or two joins disabled | 0
2060519 | 3142.12 | 1903831 | 0.0107235 | 3281.5 | no | End Elevation | Both joins enabled | 0 | Structural - Start Attachment Type: End Elevation; Geometric Position - Start Join Cutback: 0 mm
2061115 | 1356.05 | 821641 | 0.00462798 | 1362.53 | no |  | Both joins enabled | Structural - Start Attachment Type: End Elevation; Geometric Position - Start Join Cutback: 0 mm

# IfcBeam: btl_staal - UNP:UNP200 (4)
Type - Other - Category: Structural Framing; Family Name: btl_staal - UNP
Type - Dimensions - bf: 75 mm; d: 200 mm; tf: 11.5 mm; tw: 8.5 mm; x: 20.1 mm
Type - Identity Data - Description: UNP200; Model: ligger; Type Name: UNP200
Type - Materials and Finishes - Structural Material: Metal - Steel - S235 JRG2 (standaard)
Type - Structural - Section Shape: 0; A: 3220 mm2; W: 0.247716
Type - Pset_BeamCommon - IsExternal: no; LoadBearing: yes
Type - Pset_ReinforcementBarPitchOfBeam - Description: UNP200
Material: Metal - Steel - S235 JRG2 (standaard)
BaseQuantities - CrossSectionArea: 3929.92 mm2
Pset_BeamCommon - Slope: 0 deg; Reference: UNP200
Pset_QuantityTakeOff - Reference: UNP200; sets with these values: 2
Other - Family: btl_staal - UNP; End Extension Calculation: 3000 mm; Family and Type: btl_staal - UNP: UNP200; Start Extension Calculation: 3000 mm; Type: UNP200; Type Id: 1863261
Constraints - Cross-Section Rotation: 0 deg
Construction - EindOplegging: -12.5 mm; StartOplegging: -12.5 mm
Identity Data - Has Association: yes
Phasing - Phase Created: 2. nieuwbouw
Structural - Structural Usage: Other; Stick Symbol Location: Center of Geometry; Angle: 0 deg
Geometric Position - y Offset Value: 0 mm; yz Justification: Uniform; z Justification: Top; z Offset Value: 0 mm; y Justification: Origin; End Extension: 0 mm; Start Extension: 0 mm
Name (btl_staal - UNP:UNP200:...) | In | BaseQuantities, Length (mm) = Cut Length (mm) | OuterSurfaceArea (mm2) | GrossVolume (m3) = NetVolume (m3) = Volume (m3) | Span (mm) = Dimensions, Length (mm) | Reference Level | End Level Offset (mm) = Start Level Offset (mm) | Reference Level Elevation (mm) | Elevation at Bottom (mm) | Elevation at Top (mm) | Join Status
1862613 | V1 1e verd. (bk ruwe vloer) | 1805.92 | 1198394 | 0.0070971 | 1805.92 | V1 1e verd. (bk ruwe vloer) | -1211 | 3730 | 2319 | 2519 | One or two joins disabled
1863399 | V1 1e verd. (bk ruwe vloer) | 2263.69 | 1502166 | 0.0088961 | 2276.39 | V1 1e verd. (bk ruwe vloer) | -1211 | 3730 | 2319 | 2519 | Both joins enabled | Geometric Position - Start Join Cutback: 12.7 mm
1868645 | V2 2e verd. (bk ruwe vloer) | 1805.92 | 1198394 | 0.0070971 | 1805.92 | V2 2e verd. (bk ruwe vloer) | -60 | 7530 | 7270 | 7470 | One or two joins disabled
1868647 | V2 2e verd. (bk ruwe vloer) | 2276.39 | 1510594 | 0.00894601 | 2276.39 | V2 2e verd. (bk ruwe vloer) | 0 | 7530 | 7330 | 7530 | Both joins enabled | Constraints - Orientation: Normal; Work Plane: Level : V2 2e verd. (bk ruwe vloer)

# IfcBuildingElementProxy: Generic Models 1:Generic Models 1, Generic Models 1:Generic Models 1:1865951
In: F1 begg (bk ruwe vloer)
Type - Material: Beton, prefab C35/45
Type - Other - Category: Generic Models; Family Name: Generic Models 1
Type - Identity Data - Description: Prefab betonplaat d=220; Type Name: Generic Models 1
Pset_BuildingElementProxyCommon - Reference: Generic Models 1; sets with these values: 2
Other - Family: Generic Models 1; Family and Type: Generic Models 1: Generic Models 1; Type: Generic Models 1; Type Id: 1865949
Constraints - Elevation from Level: 0 mm; Moves With Nearby Elements: no
Dimensions - Area: 936944 mm2; Volume: 1.22852 m3
Phasing - Phase Created: 2. nieuwbouw

# IfcBuildingElementProxy: Generic Models 2:Generic Models 1, Generic Models 2:Generic Models 1:1868458
In: KDV V2 werkbalken
Type - Material: Beton, prefab C35/45
Type - Other - Category: Generic Models; Family Name: Generic Models 2
Type - Identity Data - Description: Prefab betonplaat d=220; Type Name: Generic Models 1
Pset_BuildingElementProxyCommon - Reference: Generic Models 1; sets with these values: 2
Other - Type: Generic Models 1; Family: Generic Models 2; Family and Type: Generic Models 2: Generic Models 1; Type Id: 1868456
Constraints - Elevation from Level: 0 mm; Moves With Nearby Elements: no
Dimensions - Area: 937226 mm2; Volume: 1.22889 m3
Phasing - Phase Created: 2. nieuwbouw

# IfcBuildingElementProxy: Generic Models 4:Generic Models 4, Generic Models 4:Generic Models 4:1918372
In: F1 begg (bk ruwe vloer)
Type - Material: Beton, prefab C35/45
Type - Other - Category: Generic Models; Family Name: Generic Models 4
Type - Identity Data - Type Name: Generic Models 4
Pset_BuildingElementProxyCommon - Reference: Generic Models 4; sets with these values: 2
Other - Family: Generic Models 4; Family and Type: Generic Models 4: Generic Models 4; Type: Generic Models 4; Type Id: 1918370
Constraints - Elevation from Level: 0 mm; Moves With Nearby Elements: no
Dimensions - Area: 721486 mm2; Volume: 0.937932 m3
Phasing - Phase Created: 2. nieuwbouw

# IfcBuildingElementProxy: Generic Models 5:Generic Models 4, Generic Models 5:Generic Models 4:1918787
In: F1 begg (bk ruwe vloer)
Type - Material: Beton, prefab C35/45
Type - Other - Category: Generic Models; Family Name: Generic Models 5
Type - Identity Data - Type Name: Generic Models 4
Pset_BuildingElementProxyCommon - Reference: Generic Models 4; sets with these values: 2
Other - Type: Generic Models 4; Family: Generic Models 5; Family and Type: Generic Models 5: Generic Models 4; Type Id: 1918785
Constraints - Elevation from Level: 0 mm; Moves With Nearby Elements: no
Dimensions - Area: 804202 mm2; Volume: 1.04546 m3
Phasing - Phase Created: 2. nieuwbouw

# IfcBuildingElementProxy: Generic Models 8:Generic Models 4, Generic Models 8:Generic Models 4:1961874
In: KDV V2 werkbalken
Type - Material: Beton, prefab C35/45
Type - Other - Category: Generic Models; Family Name: Generic Models 8
Type - Identity Data - Type Name: Generic Models 4
Pset_BuildingElementProxyCommon - Reference: Generic Models 4; sets with these values: 2
Other - Type: Generic Models 4; Family: Generic Models 8; Family and Type: Generic Models 8: Generic Models 4; Type Id: 1961872
Constraints - Moves With Nearby Elements: no; Elevation from Level: 3800 mm
Dimensions - Area: 721486 mm2; Volume: 0.937932 m3
Phasing - Phase Created: 2. nieuwbouw

# IfcBuildingElementProxy: Generic Models 9:Generic Models 4, Generic Models 9:Generic Models 4:1961906
In: V1 1e verd. (bk ruwe vloer)
Type - Material: Beton, prefab C35/45
Type - Other - Category: Generic Models; Family Name: Generic Models 9
Type - Identity Data - Type Name: Generic Models 4
Pset_BuildingElementProxyCommon - Reference: Generic Models 4; sets with these values: 2
Other - Type: Generic Models 4; Family: Generic Models 9; Family and Type: Generic Models 9: Generic Models 4; Type Id: 1961904
Constraints - Moves With Nearby Elements: no; Elevation from Level: 3800 mm
Dimensions - Area: 804202 mm2; Volume: 1.03361 m3
Phasing - Phase Created: 2. nieuwbouw

# IfcBuildingElementProxy: NL_00_BTB_nulpunt_marker & naald:NL_00_BTB_nulpunt_marker & naald, NL_00_BTB_nulpunt_marker & naald:NL_00_BTB_nulpunt_marker & naald:1477550
In: F1 begg (bk ruwe vloer)
Type - Material: <Unnamed>, bt_huisstijl_rood
Type - Other - Category: Generic Models; Family Name: NL_00_BTB_nulpunt_marker & naald
Type - Constraints - Default Elevation: 0 mm
Type - Graphics - Naald allebei uit: yes; Naald onderzijde kubus Links Onder: yes; Naald onderzijde kubus Rechts Boven: no
Type - Identity Data - Description: Orgin punt Revit model; Manufacturer: Berkhout Tros Bouwadviseurs BV; Type Name: NL_00_BTB_nulpunt_marker & naald; URL: www.berkhouttros.nl
Type - Materials and Finishes - kubes kleur: bt_huisstijl_rood
Type - Pset_ManufacturerTypeInformation - Manufacturer: Berkhout Tros Bouwadviseurs BV
Pset_BuildingElementProxyCommon - Reference: NL_00_BTB_nulpunt_marker & naald; sets with these values: 2
Other - Family: NL_00_BTB_nulpunt_marker & naald; Family and Type: NL_00_BTB_nulpunt_marker & naald: NL_00_BTB_nulpunt_marker & naald; Type: NL_00_BTB_nulpunt_marker & naald; Type Id: 1477535
Constraints - Elevation from Level: 0 mm; Host: Level : 00000 begg; Level: 00000 begg; Moves With Nearby Elements: no; Offset from Host: 0 mm
Dimensions - Area: 4750916 mm2; Volume: 1.04803 m3
Phasing - Phase Created: 2. nieuwbouw

# IfcColumn: btk_beton - 4-hoek:500x350 ihwg (19)
In: F1 begg (bk ruwe vloer)
Type - PredefinedType: COLUMN; Material: Concrete - Cast-in-Place - C20/25
Type - Other - Category: Structural Columns; Family Name: btk_beton - 4-hoek
Type - Dimensions - Breedte x: 500 mm; Lengte y: 350 mm
Type - Identity Data - Description: ihwg kolom 500x350; Model: kolom; Type Mark: Opstort; Type Name: 500x350 ihwg
Type - Materials and Finishes - Structural Material: Concrete - Cast-in-Place - C20/25
Type - Structural - Section Shape: 0
Type - Pset_ColumnCommon - IsExternal: no; LoadBearing: yes
Type - Pset_ReinforcementBarPitchOfColumn - Description: ihwg kolom 500x350
BaseQuantities - Length: 350 mm
Pset_ColumnCommon - Reference: 500x350 ihwg
Pset_QuantityTakeOff - Reference: 500x350 ihwg; sets with these values: 2
Other - Family: btk_beton - 4-hoek; Family and Type: btk_beton - 4-hoek: 500x350 ihwg; Type: 500x350 ihwg; Type Id: 1782806
Constraints - Room Bounding: yes; Base Offset: 0 mm; Column Style: Vertical; Moves With Grids: yes; Base Level: F2 (bk fundering); Level: F2 (bk fundering); Top Level: F1 begg (bk ruwe vloer); Top Offset: -60 mm
Dimensions - Length: 350 mm
Identity Data - Has Association: yes
Phasing - Phase Created: 2. nieuwbouw
Structural - Rebar Cover - Other Faces: Rebar Cover 1 <25 mm>; Rebar Cover - Top Face: Rebar Cover 1 <25 mm>
Name (btk_beton - 4-hoek:500x350 ihwg:...) | CrossSectionArea (mm2) | OuterSurfaceArea (mm2) | GrossVolume (m3) = NetVolume (m3) = Volume (m3) | Column Location Mark
1781670 | 150000 | 560000 | 0.0525 | B-2(-1300) | Pset_ColumnCommon - Slope: 0 deg
1782937 | 150000 | 560000 | 0.0525 | B-2(1300) | Pset_ColumnCommon - Slope: 0 deg
1782956 | 157500 | 577500 | 0.055125 | B-3
1782969 | 150000 | 560000 | 0.0525 | B-5(-1300)
1782980 | 150000 | 560000 | 0.0525 | B-5(1300)
1782995 | 165000 | 595000 | 0.05775 | B-7
1783043 | 162500 | 577500 | 0.056875 | C-7
1783143 | 162500 | 577500 | 0.056875 | C-6 | Pset_ColumnCommon - Slope: 0 deg; Structural - Rebar Cover - Bottom Face: Rebar Cover 1 <25 mm>
1783185 | 162500 | 577500 | 0.056875 | C-4 | Pset_ColumnCommon - Slope: 0 deg; Structural - Rebar Cover - Bottom Face: Rebar Cover 1 <25 mm>
1783198 | 162500 | 577500 | 0.056875 | C-2(1325.6) | Pset_ColumnCommon - Slope: 0 deg
1783267 | 166950 | 595000 | 0.0584325 | B-1 | Structural - Rebar Cover - Bottom Face: Rebar Cover 1 <25 mm>
1787127 | 137798 | 699981 | 0.0482294 | D-2
1787147 | 175000 | 595000 | 0.06125 | D-4 | Structural - Rebar Cover - Bottom Face: Rebar Cover 1 <25 mm>
1795236 | 175000 | 595000 | 0.06125 | F-4
1795256 | 175000 | 595000 | 0.06125 | F-6
1880081 | 175000 | 595000 | 0.06125 | B(-2446.7)-9
1880524 | 175000 | 595000 | 0.06125 | B(2063.9)-9
1883180 | 175000 | 595000 | 0.06125 | D-6 | Structural - Rebar Cover - Bottom Face: Rebar Cover 1 <25 mm>
1930189 | 175000 | 595000 | 0.06125 | D-8 | Structural - Rebar Cover - Bottom Face: Rebar Cover 1 <25 mm>

# IfcColumn: btk_staal - Buis + beton:Ø323.9x10 (4)
In: F1 begg (bk ruwe vloer)
Type - PredefinedType: COLUMN; Material: Concrete - Cast-in-Place - C30/37, Metal - Steel - S235 JRG2 (standaard)
Type - Other - Category: Structural Columns; Family Name: btk_staal - Buis + beton; hiddenlijns: 303.9 mm
Type - Dimensions - OD: 323.9 mm; t: 10 mm
Type - Identity Data - Description: buisprofiel-betongevuld; Model: kolom; Type Comments: 6Ø16 + bgls Ø8-150. Dekking 25mm; Type Mark: K4; Type Name: Ø323.9x10
Type - Materials and Finishes - Betonkwaliteit: Concrete - Cast-in-Place - C30/37; Staalkwaliteit: Metal - Steel - S235 JRG2 (standaard)
Type - Structural - Section Shape: 0; A: 6285.95 mm2; W: 0.483906
Type - Pset_ColumnCommon - IsExternal: no; LoadBearing: yes
Type - Pset_ReinforcementBarPitchOfColumn - Description: buisprofiel-betongevuld
BaseQuantities - Length: 3540 mm; CrossSectionArea: 9860.14 mm2; OuterSurfaceArea: 6981913 mm2; GrossVolume: 0.0349049 m3; NetVolume: 0.291664 m3
Pset_ColumnCommon - Reference: Ø323.9x10
Pset_QuantityTakeOff - Reference: Ø323.9x10; sets with these values: 2
Other - Family: btk_staal - Buis + beton; Family and Type: btk_staal - Buis + beton: Ø323.9x10; Type: Ø323.9x10; Type Id: 1815192
Constraints - Level: F1 begg (bk ruwe vloer); Base Offset: 0 mm; Top Offset: 0 mm; Base Level: F1 begg (bk ruwe vloer); Column Style: Vertical; Moves With Grids: yes; Top Level: V1 ok vloer
Dimensions - Length: 3540 mm; Volume: 0.291664 m3
Identity Data - Has Association: yes
Phasing - Phase Created: 2. nieuwbouw
Name (btk_staal - Buis + beton:Ø323.9x10:...) | Column Location Mark
1551474 | D-4
1551519 | D-6
1552006 | C-4
1552429 | C-6

# IfcColumn: btk_staal - Buis + beton:Ø323.9x10 (4)
Type - PredefinedType: COLUMN; Material: Metal - Steel - S235 JRG2 (standaard), Concrete - Cast-in-Place - C30/37
Type - Other - Category: Structural Columns; Family Name: btk_staal - Buis + beton; hiddenlijns: 303.9 mm
Type - Dimensions - OD: 323.9 mm; t: 10 mm
Type - Identity Data - Description: buisprofiel-betongevuld; Model: kolom; Type Comments: 6Ø16 + bgls Ø8-150. Dekking 25mm; Type Mark: K4; Type Name: Ø323.9x10
Type - Materials and Finishes - Betonkwaliteit: Concrete - Cast-in-Place - C30/37; Staalkwaliteit: Metal - Steel - S235 JRG2 (standaard)
Type - Structural - Section Shape: 0; A: 6285.95 mm2; W: 0.483906
Type - Pset_ColumnCommon - IsExternal: no; LoadBearing: yes
Type - Pset_ReinforcementBarPitchOfColumn - Description: buisprofiel-betongevuld
BaseQuantities - CrossSectionArea: 72525.9 mm2
Pset_ColumnCommon - Reference: Ø323.9x10
Pset_QuantityTakeOff - Reference: Ø323.9x10; sets with these values: 2
Other - Family: btk_staal - Buis + beton; Family and Type: btk_staal - Buis + beton: Ø323.9x10; Type: Ø323.9x10; Type Id: 1815192
Constraints - Base Offset: 0 mm; Top is Attached: yes; Column Style: Vertical; Moves With Grids: yes; Top Level: V2 2e verd. (bk ruwe vloer)
Construction - Attachment Justification At Top: Minimum Intersection; Offset From Attachment At Top: 0 mm
Identity Data - Has Association: yes
Phasing - Phase Created: 2. nieuwbouw
Name (btk_staal - Buis + beton:Ø323.9x10:...) | In | BaseQuantities, Length (mm) = Dimensions, Length (mm) | OuterSurfaceArea (mm2) | GrossVolume (m3) | NetVolume (m3) = Volume (m3) | Level = Base Level | Column Location Mark | Top Offset (mm)
1567848 | V1 1e verd. (bk ruwe vloer) | 3525 | 6730847 | 0.255654 | 0.290428 | V1 1e verd. (bk ruwe vloer) | C-4 | -275
1567850 | V1 1e verd. (bk ruwe vloer) | 3525 | 6730847 | 0.255654 | 0.290428 | V1 1e verd. (bk ruwe vloer) | C-6 | -275
1761750 | V2 2e verd. (bk ruwe vloer) | 3085 | 5890684 | 0.223742 | 0.254176 | V2 2e verd. (bk ruwe vloer) | C-4 | 3085
1761752 | V2 2e verd. (bk ruwe vloer) | 3085 | 5890684 | 0.223742 | 0.254176 | V2 2e verd. (bk ruwe vloer) | C-6 | 3085

# IfcColumn: btk_staal - HE(a-b-m):HEA140 (5)
Type - PredefinedType: COLUMN; Material: Metal - Steel - S235 JRG2 (standaard)
Type - Other - Category: Structural Columns; Family Name: btk_staal - HE(a-b-m)
Type - Dimensions - bf: 140 mm; d: 133 mm; k: 20.5 mm; kr: 12 mm; tf: 8.5 mm; tw: 5.5 mm
Type - Identity Data - Model: kolom; Type Mark: HEA140; Type Name: HEA140
Type - Materials and Finishes - Structural Material: Metal - Steel - S235 JRG2 (standaard)
Type - Structural - Section Shape: 0; A: 3142 mm2; W: 0.241832
Type - Pset_ColumnCommon - IsExternal: no; LoadBearing: yes
BaseQuantities - CrossSectionArea: 3018 mm2
Pset_ColumnCommon - Reference: HEA140
Pset_QuantityTakeOff - Reference: HEA140; sets with these values: 2
Other - Family: btk_staal - HE(a-b-m); Family and Type: btk_staal - HE(a-b-m): HEA140; Type: HEA140; Type Id: 1652557
Constraints - Column Style: Vertical; Moves With Grids: yes
Phasing - Phase Created: 2. nieuwbouw
Name (btk_staal - HE(a-b-m):HEA140:...) | In | BaseQuantities, Length (mm) = Dimensions, Length (mm) | OuterSurfaceArea (mm2) | GrossVolume (m3) = NetVolume (m3) = Volume (m3) | Slope (deg) | Base Offset (mm) | Top Level | Base Level = Level | Column Location Mark | Top Offset (mm) | Has Association
1657252 | F1 begg (bk ruwe vloer) | 7265 | 5920975 | 0.0219258 | 0 | 0 | V2 2e verd. (bk ruwe vloer) | F2 (bk fundering) | H(-1731.6)-6(-1676.6) | -745 | yes
1660120 | F1 begg (bk ruwe vloer) | 7265 | 5920975 | 0.0219258 | 0 | 0 | V2 2e verd. (bk ruwe vloer) | F2 (bk fundering) | H(-1731.6)-4(-367.3) | -745 | yes
1839967 | V4 BK metselwerk | 1107 | 902205 | 0.00334093 | 0 | -850 | V4 BK metselwerk | V4 BK metselwerk | F-4(3275.1) | 257 | yes
2090098 | V3 dakvloer | 802.047 | 653668 | 0.00242058 |  | 57.9531 | V4 BK metselwerk | V3 dakvloer | F-4 | 0 | no | Constraints - Top is Attached: yes; Base is Attached: yes; Construction - Attachment Justification At Top: Minimum Intersection; Offset From Attachment At Top: 0 mm; Attachment Justification At Base: Minimum Intersection; Offset From Attachment At Base: 0 mm
2091876 | V3 dakvloer | 802.047 | 653668 | 0.00242058 |  | 57.9531 | V4 BK metselwerk | V3 dakvloer | F-6 | 0 | no | Constraints - Top is Attached: yes; Base is Attached: yes; Construction - Attachment Justification At Top: Minimum Intersection; Offset From Attachment At Top: 0 mm; Attachment Justification At Base: Minimum Intersection; Offset From Attachment At Base: 0 mm

# IfcColumn: btk_staal - HE(a-b-m):HEA260 (6)
In: V1 1e verd. (bk ruwe vloer)
Type - PredefinedType: COLUMN; Material: Metal - Steel - S235 JRG2 (standaard)
Type - Other - Category: Structural Columns; Family Name: btk_staal - HE(a-b-m)
Type - Dimensions - bf: 260 mm; d: 250 mm; k: 36.5 mm; kr: 24 mm; tf: 12.5 mm; tw: 7.5 mm
Type - Identity Data - Model: kolom; Type Mark: HEA260; Type Name: HEA260
Type - Materials and Finishes - Structural Material: Metal - Steel - S235 JRG2 (standaard)
Type - Structural - Section Shape: 0; A: 8680 mm2; W: 0.668814
Type - Pset_ColumnCommon - IsExternal: no; LoadBearing: yes
BaseQuantities - CrossSectionArea: 8187.5 mm2
Pset_ColumnCommon - Reference: HEA260
Pset_QuantityTakeOff - Reference: HEA260; sets with these values: 2
Other - Family: btk_staal - HE(a-b-m); Family and Type: btk_staal - HE(a-b-m): HEA260; Type: HEA260; Type Id: 1778173
Constraints - Column Style: Vertical; Moves With Grids: yes; Level: V1 1e verd. (bk ruwe vloer); Base Level: V1 1e verd. (bk ruwe vloer); Top Level: V4 BK metselwerk; Base Offset: 120 mm
Identity Data - Has Association: yes
Phasing - Phase Created: 2. nieuwbouw
Name (btk_staal - HE(a-b-m):HEA260:...) | BaseQuantities, Length (mm) = Dimensions, Length (mm) | OuterSurfaceArea (mm2) | GrossVolume (m3) = NetVolume (m3) = Volume (m3) | Column Location Mark | Top Offset (mm)
1568915 | 6787.95 | 10351621 | 0.0555763 | H-8 | -1062.05
1568979 | 6787.95 | 10351624 | 0.0555763 | H-6(-1676.6) | -1062.05
1569033 | 6787.95 | 10351626 | 0.0555764 | H-4(-367.3) | -1062.05
1569054 | 6934.25 | 10574731 | 0.0567742 | H-2 | -915.75 | Constraints - Top is Attached: yes; Construction - Attachment Justification At Top: Minimum Intersection; Offset From Attachment At Top: 0 mm
1569101 | 6808 | 10382200 | 0.0557405 | G-2 | -1042 | Constraints - Top is Attached: yes; Construction - Attachment Justification At Top: Minimum Intersection; Offset From Attachment At Top: 0 mm; Pset_ColumnCommon - Slope: 0 deg
1569140 | 6808 | 10382200 | 0.0557405 | G-8 | -1042 | Constraints - Top is Attached: yes; Construction - Attachment Justification At Top: Minimum Intersection; Offset From Attachment At Top: 0 mm; Pset_ColumnCommon - Slope: 0 deg

# IfcColumn: btk_staal - HE(a-b-m):HEB140 (2)
In: F1 begg (bk ruwe vloer)
Type - PredefinedType: COLUMN; Material: Metal - Steel - S235 JRG2 (standaard)
Type - Other - Category: Structural Columns; Family Name: btk_staal - HE(a-b-m)
Type - Dimensions - bf: 140 mm; d: 140 mm; k: 24 mm; kr: 12 mm; tf: 12 mm; tw: 7 mm
Type - Identity Data - Model: kolom; Type Name: HEB140
Type - Materials and Finishes - Structural Material: Metal - Steel - S235 JRG2 (standaard)
Type - Structural - Section Shape: 0; A: 4300 mm2; W: 0.330484
Type - Pset_ColumnCommon - IsExternal: no; LoadBearing: yes
BaseQuantities - Length: 8070 mm; CrossSectionArea: 4172 mm2; OuterSurfaceArea: 6665820 mm2; GrossVolume: 0.033668 m3; NetVolume: 0.033668 m3
Pset_ColumnCommon - Slope: 0 deg; Reference: HEB140
Pset_QuantityTakeOff - Reference: HEB140; sets with these values: 2
Other - Family: btk_staal - HE(a-b-m); Family and Type: btk_staal - HE(a-b-m): HEB140; Type: HEB140; Type Id: 1807250
Constraints - Base Offset: 0 mm; Column Style: Vertical; Moves With Grids: yes; Top Level: V2 2e verd. (bk ruwe vloer); Base Level: F2 (bk fundering); Level: F2 (bk fundering); Top Offset: 60 mm
Dimensions - Length: 8070 mm; Volume: 0.033668 m3
Identity Data - Has Association: yes
Phasing - Phase Created: 2. nieuwbouw
Name (btk_staal - HE(a-b-m):HEB140:...) | Column Location Mark
1807182 | H(-1735.1)-4(2046.3)
1807386 | H(-1735.1)-6(-4090.2)

# IfcColumn: btk_staal - HE(a-b-m):HEB200 (6)
Type - PredefinedType: COLUMN; Material: Metal - Steel - S235 JRG2 (standaard)
Type - Other - Category: Structural Columns; Family Name: btk_staal - HE(a-b-m)
Type - Dimensions - bf: 200 mm; d: 200 mm; k: 33 mm; kr: 18 mm; tf: 15 mm; tw: 9 mm
Type - Identity Data - Description: HEB200; Model: kolom; Type Name: HEB200
Type - Materials and Finishes - Structural Material: Metal - Steel - S235 JRG2 (standaard)
Type - Structural - Section Shape: 0; A: 7810 mm2; W: 0.601148
Type - Pset_ColumnCommon - IsExternal: no; LoadBearing: yes
Type - Pset_ReinforcementBarPitchOfColumn - Description: HEB200
BaseQuantities - GrossSurfaceArea: 0 mm2
Pset_ColumnCommon - Reference: HEB200
Pset_QuantityTakeOff - Reference: HEB200; sets with these values: 2
Other - Family: btk_staal - HE(a-b-m); Family and Type: btk_staal - HE(a-b-m): HEB200; Type: HEB200; Type Id: 1580462
Constraints - Column Style: Vertical; Moves With Grids: yes
Phasing - Phase Created: 2. nieuwbouw
Name (btk_staal - HE(a-b-m):HEB200:...) | In | NetVolume (m3) = Volume (m3) | Slope (deg) | Base Level = Level | Base Offset (mm) | Column Location Mark | Top Level | Top Offset (mm) | Length (mm) | Has Association | Group
1601204 | V3 dakvloer | 0.0025935 | 32.3803 | V3 dakvloer | 10 | C(-107)-1(-107) | V3 dakvloer | 660 | 650 | yes
1988281 | V2 2e verd. (bk ruwe vloer) | 0.00416977 |  | V2 2e verd. (bk ruwe vloer) | 3120 | C(-107)-9(103.8) | V4 BK metselwerk | -163 | 887 | yes
2015835 | V2 2e verd. (bk ruwe vloer) | 0.00269996 |  | 07400 V2 2e verd | 3250 | C(-107)-2 | V4 BK metselwerk | 0 | 850 | no | Model Group:Spant 5 (members excluded):2015775
2015952 | V2 2e verd. (bk ruwe vloer) | 0.00269996 | 32.3796 | 07400 V2 2e verd | 3250 | C(-107)-3 | V4 BK metselwerk | 0 | 850 | no | Model Group:Spant 5 (members excluded):2015892
2016067 | V2 2e verd. (bk ruwe vloer) | 0.00269996 | 32.3796 | 07400 V2 2e verd | 3250 | C(-107)-5 | V4 BK metselwerk | 0 | 850 | no | Model Group:Spant 5 (members excluded):2016007
2016182 | V2 2e verd. (bk ruwe vloer) | 0.00269996 | 32.3796 | 07400 V2 2e verd | 3250 | C(-107)-7 | V4 BK metselwerk | 0 | 850 | no | Model Group:Spant 5 (members excluded):2016122

# IfcColumn: btk_staal - Koker + beton:K200x200x8 (4)
In: F1 begg (bk ruwe vloer)
Type - PredefinedType: COLUMN; Material: Concrete - Cast-in-Place - C30/37, Metal - Steel - S275 J0H (standaard-kokers/buizen)
Type - Other - Category: Structural Columns; Family Name: btk_staal - Koker + beton
Type - Dimensions - b: 200 mm; Ht: 200 mm; kr: 16 mm; t: 8 mm
Type - Identity Data - Description: kokerprofiel-betongevuld; Model: kolom; Type Comments: 4Ø16 + bgls Ø8-150. Dekking 25mm; Type Mark: K5; Type Name: K200x200x8
Type - Materials and Finishes - Betonkwaliteit: Concrete - Cast-in-Place - C30/37; Staalkwaliteit: Metal - Steel - S275 J0H (standaard-kokers/buizen)
Type - Structural - Section Shape: 0; A: 9146.22 mm2; Shape: vierkant; W: 0.704097
Type - Pset_ColumnCommon - IsExternal: no; LoadBearing: yes
Type - Pset_ReinforcementBarPitchOfColumn - Description: kokerprofiel-betongevuld
BaseQuantities - Length: 2778 mm; CrossSectionArea: 6144 mm2; OuterSurfaceArea: 4267008 mm2; GrossVolume: 0.017068 m3; NetVolume: 0.11112 m3
Pset_ColumnCommon - Reference: K200x200x8
Pset_QuantityTakeOff - Reference: K200x200x8; sets with these values: 2
Other - Family: btk_staal - Koker + beton; Family and Type: btk_staal - Koker + beton: K200x200x8; Type: K200x200x8; Type Id: 2064965
Constraints - Level: F1 begg (bk ruwe vloer); Base Offset: 0 mm; Base Level: F1 begg (bk ruwe vloer); Column Style: Vertical; Moves With Grids: yes; Top Level: V1 ok vloer; Top Offset: -762 mm
Dimensions - Length: 2778 mm; Volume: 0.11112 m3
Identity Data - Has Association: no
Phasing - Phase Created: 2. nieuwbouw
Name (btk_staal - Koker + beton:K200x200x8:...) | Column Location Mark
2064898 | H(-107)-2(2415.1)
2065048 | H(-107)-4(-3489.9)
2065068 | H(-107)-6(1489.1)
2065084 | H(-107)-8(-2416.1)

# IfcColumn: btk_staal - Koker + beton:K220x220x8 (16)
Type - PredefinedType: COLUMN; Material: Concrete - Cast-in-Place - C30/37, Metal - Steel - S275 J0H (standaard-kokers/buizen)
Type - Other - Category: Structural Columns; Family Name: btk_staal - Koker + beton
Type - Dimensions - b: 220 mm; Ht: 220 mm; kr: 16 mm; t: 8 mm
Type - Identity Data - Description: kokerprofiel-betongevuld; Model: kolom; Type Comments: 4Ø16 + bgls Ø8-150. Dekking 25mm; Type Mark: K1; Type Name: K220x220x8
Type - Materials and Finishes - Betonkwaliteit: Concrete - Cast-in-Place - C30/37; Staalkwaliteit: Metal - Steel - S275 J0H (standaard-kokers/buizen)
Type - Structural - Section Shape: 0; A: 9146.22 mm2; Shape: vierkant; W: 0.704097
Type - Pset_ColumnCommon - IsExternal: no; LoadBearing: yes
Type - Pset_ReinforcementBarPitchOfColumn - Description: kokerprofiel-betongevuld
BaseQuantities - CrossSectionArea: 6784 mm2
Pset_ColumnCommon - Reference: K220x220x8
Pset_QuantityTakeOff - Reference: K220x220x8; sets with these values: 2
Other - Family: btk_staal - Koker + beton; Family and Type: btk_staal - Koker + beton: K220x220x8; Type: K220x220x8; Type Id: 1814161
Constraints - Column Style: Vertical; Moves With Grids: yes
Identity Data - Has Association: no
Phasing - Phase Created: 2. nieuwbouw
Name (btk_staal - Koker + beton:K220x220x8:...) | In | BaseQuantities, Length (mm) = Dimensions, Length (mm) | OuterSurfaceArea (mm2) | GrossVolume (m3) | NetVolume (m3) = Volume (m3) | Level = Base Level | Base Offset (mm) | Top is Attached | Top Level | Column Location Mark | Top Offset (mm) | Attachment Justification At Top | Offset From Attachment At Top (mm)
1564432 | F1 begg (bk ruwe vloer) | 3525 | 5978400 | 0.0239136 | 0.17061 | F1 begg (bk ruwe vloer) | 0 | yes | V1 ok vloer | B-1 | -15 | Minimum Intersection | 0
1565501 | F1 begg (bk ruwe vloer) | 3525 | 5978400 | 0.0239136 | 0.17061 | F1 begg (bk ruwe vloer) | 0 | yes | V1 ok vloer | B-7 | -15 | Minimum Intersection | 0
1567769 | V1 1e verd. (bk ruwe vloer) | 3525 | 5978400 | 0.0239136 | 0.17061 | V1 1e verd. (bk ruwe vloer) | 0 | yes | V2 2e verd. (bk ruwe vloer) | B-1 | -275 | Minimum Intersection | 0
1567779 | V1 1e verd. (bk ruwe vloer) | 3525 | 5978400 | 0.0239136 | 0.17061 | V1 1e verd. (bk ruwe vloer) | 0 | yes | V2 2e verd. (bk ruwe vloer) | B-7 | -275 | Minimum Intersection | 0
1568898 | V1 1e verd. (bk ruwe vloer) | 6847.95 | 11614128 | 0.0464565 | 0.331441 | V1 1e verd. (bk ruwe vloer) | 120 |  | V4 BK metselwerk | F-8 | -1002.05
1573600 | F1 begg (bk ruwe vloer) | 3540 | 6003840 | 0.0240154 | 0.171336 | F1 begg (bk ruwe vloer) | 0 |  | V1 ok vloer | C-2(1325.6) | 0
1573686 | F1 begg (bk ruwe vloer) | 3540 | 6003840 | 0.0240154 | 0.171336 | F1 begg (bk ruwe vloer) | 0 |  | V1 ok vloer | C-7 | 0
1573735 | V1 1e verd. (bk ruwe vloer) | 3525 | 5978400 | 0.0239136 | 0.17061 | V1 1e verd. (bk ruwe vloer) | 0 | yes | V2 2e verd. (bk ruwe vloer) | C-2(1325.6) | -275 | Minimum Intersection | 0
1573737 | V1 1e verd. (bk ruwe vloer) | 3525 | 5978400 | 0.0239136 | 0.17061 | V1 1e verd. (bk ruwe vloer) | 0 | yes | V2 2e verd. (bk ruwe vloer) | C-7 | -275 | Minimum Intersection | 0
1639178 | V2 2e verd. (bk ruwe vloer) | 3085 | 5232160 | 0.0209286 | 0.149314 | V2 2e verd. (bk ruwe vloer) | 0 | yes | V2 2e verd. (bk ruwe vloer) | B-7 | 3085 | Minimum Intersection | 0
1753877 | V2 2e verd. (bk ruwe vloer) | 3167.95 | 5372848 | 0.0214914 | 0.153329 | V2 2e verd. (bk ruwe vloer) | 0 | yes | V3 dakvloer | F-6 | -142.047 | Minimum Intersection | 0
1753975 | V2 2e verd. (bk ruwe vloer) | 3167.95 | 5372848 | 0.0214914 | 0.153329 | V2 2e verd. (bk ruwe vloer) | 0 | yes | V3 dakvloer | F-4 | -142.047 | Minimum Intersection | 0
1779466 | V2 2e verd. (bk ruwe vloer) | 3085 | 5232160 | 0.0209286 | 0.149314 | V2 2e verd. (bk ruwe vloer) | 0 | yes | V2 2e verd. (bk ruwe vloer) | C-2(1325.6) | 3085 | Minimum Intersection | 0
1809476 | F1 begg (bk ruwe vloer) | 3525 | 5978400 | 0.0239136 | 0.17061 | F1 begg (bk ruwe vloer) | 0 |  | V1 ok vloer | B(2063.9)-9 | -15
1809593 | F1 begg (bk ruwe vloer) | 3525 | 5978400 | 0.0239136 | 0.17061 | F1 begg (bk ruwe vloer) | 0 |  | V1 ok vloer | B(-2446.7)-9 | -15
1817752 | V2 2e verd. (bk ruwe vloer) | 3085 | 5232160 | 0.0209286 | 0.149314 | V2 2e verd. (bk ruwe vloer) | 0 | yes | V2 2e verd. (bk ruwe vloer) | C-7 | 3085 | Minimum Intersection | 0

# IfcColumn: btk_staal - Koker + beton:K220x220x8 (2)
Type - PredefinedType: COLUMN; Material: Metal - Steel - S275 J0H (standaard-kokers/buizen), Concrete - Cast-in-Place - C30/37
Type - Other - Category: Structural Columns; Family Name: btk_staal - Koker + beton
Type - Dimensions - b: 220 mm; Ht: 220 mm; kr: 16 mm; t: 8 mm
Type - Identity Data - Description: kokerprofiel-betongevuld; Model: kolom; Type Comments: 4Ø16 + bgls Ø8-150. Dekking 25mm; Type Mark: K1; Type Name: K220x220x8
Type - Materials and Finishes - Betonkwaliteit: Concrete - Cast-in-Place - C30/37; Staalkwaliteit: Metal - Steel - S275 J0H (standaard-kokers/buizen)
Type - Structural - Section Shape: 0; A: 9146.22 mm2; Shape: vierkant; W: 0.704097
Type - Pset_ColumnCommon - IsExternal: no; LoadBearing: yes
Type - Pset_ReinforcementBarPitchOfColumn - Description: kokerprofiel-betongevuld
BaseQuantities - CrossSectionArea: 41616 mm2
Pset_ColumnCommon - Slope: 0 deg; Reference: K220x220x8
Pset_QuantityTakeOff - Reference: K220x220x8; sets with these values: 2
Other - Family: btk_staal - Koker + beton; Family and Type: btk_staal - Koker + beton: K220x220x8; Type: K220x220x8; Type Id: 1814161
Constraints - Base Offset: 0 mm; Column Style: Vertical; Moves With Grids: yes; Top Level: V4 BK metselwerk
Identity Data - Has Association: no
Phasing - Phase Created: 2. nieuwbouw
Name (btk_staal - Koker + beton:K220x220x8:...) | In | BaseQuantities, Length (mm) = Dimensions, Length (mm) | OuterSurfaceArea (mm2) | GrossVolume (m3) | NetVolume (m3) = Volume (m3) | Level = Base Level | Column Location Mark | Top Offset (mm)
1568845 | V1 1e verd. (bk ruwe vloer) | 7040.87 | 11490697 | 0.293013 | 0.340778 | V1 1e verd. (bk ruwe vloer) | F-2 | -929.132
1639016 | V2 2e verd. (bk ruwe vloer) | 3085 | 5034720 | 0.128385 | 0.149314 | V2 2e verd. (bk ruwe vloer) | B-1 | -1085 | Constraints - Top is Attached: yes; Construction - Attachment Justification At Top: Minimum Intersection; Offset From Attachment At Top: 0 mm

# IfcColumn: btk_staal - Koker + beton:K250x250x8.0 (21)
Type - PredefinedType: COLUMN; Material: Concrete - Cast-in-Place - C30/37, Metal - Steel - S275 J0H (standaard-kokers/buizen)
Type - Other - Category: Structural Columns; Family Name: btk_staal - Koker + beton
Type - Dimensions - b: 250 mm; Ht: 250 mm; kr: 16 mm; t: 8 mm
Type - Identity Data - Description: kokerprofiel-betongevuld; Model: kolom; Type Comments: 8Ø12 + bgls Ø8-150. Dekking 25mm; Type Mark: K2; Type Name: K250x250x8.0
Type - Materials and Finishes - Betonkwaliteit: Concrete - Cast-in-Place - C30/37; Staalkwaliteit: Metal - Steel - S275 J0H (standaard-kokers/buizen)
Type - Structural - Section Shape: 0; A: 7546.22 mm2; Shape: vierkant; W: 0.580925
Type - Pset_ColumnCommon - IsExternal: no; LoadBearing: yes
Type - Pset_ReinforcementBarPitchOfColumn - Description: kokerprofiel-betongevuld
BaseQuantities - CrossSectionArea: 7744 mm2
Pset_ColumnCommon - Reference: K250x250x8.0
Pset_QuantityTakeOff - Reference: K250x250x8.0; sets with these values: 2
Other - Family: btk_staal - Koker + beton; Family and Type: btk_staal - Koker + beton: K250x250x8.0; Type: K250x250x8.0; Type Id: 1813943
Constraints - Column Style: Vertical; Moves With Grids: yes
Identity Data - Has Association: yes
Phasing - Phase Created: 2. nieuwbouw
Name (btk_staal - Koker + beton:K250x250x8.0:...) | In | BaseQuantities, Length (mm) = Dimensions, Length (mm) | OuterSurfaceArea (mm2) | GrossVolume (m3) | NetVolume (m3) = Volume (m3) | Level = Base Level | Base Offset (mm) | Top is Attached | Top Level | Column Location Mark | Top Offset (mm) | Attachment Justification At Top | Offset From Attachment At Top (mm)
1565122 | F1 begg (bk ruwe vloer) | 3525 | 6824400 | 0.0272976 | 0.220312 | F1 begg (bk ruwe vloer) | 0 | yes | V1 ok vloer | B-3 | -15 | Minimum Intersection | 0
1565231 | F1 begg (bk ruwe vloer) | 3525 | 6824400 | 0.0272976 | 0.220312 | F1 begg (bk ruwe vloer) | 0 | yes | V1 ok vloer | B-5(-1300) | -15 | Minimum Intersection | 0
1565412 | F1 begg (bk ruwe vloer) | 3525 | 6824400 | 0.0272976 | 0.220312 | F1 begg (bk ruwe vloer) | 0 | yes | V1 ok vloer | B-5(1300) | -15 | Minimum Intersection | 0
1567773 | V1 1e verd. (bk ruwe vloer) | 3525 | 6824400 | 0.0272976 | 0.220312 | V1 1e verd. (bk ruwe vloer) | 0 | yes | V2 2e verd. (bk ruwe vloer) | B-3 | -275 | Minimum Intersection | 0
1567775 | V1 1e verd. (bk ruwe vloer) | 3525 | 6824400 | 0.0272976 | 0.220312 | V1 1e verd. (bk ruwe vloer) | 0 | yes | V2 2e verd. (bk ruwe vloer) | B-5(-1300) | -275 | Minimum Intersection | 0
1567777 | V1 1e verd. (bk ruwe vloer) | 3525 | 6824400 | 0.0272976 | 0.220312 | V1 1e verd. (bk ruwe vloer) | 0 | yes | V2 2e verd. (bk ruwe vloer) | B-5(1300) | -275 | Minimum Intersection | 0
1567840 | V1 1e verd. (bk ruwe vloer) | 3515 | 6805040 | 0.0272202 | 0.219688 | V1 1e verd. (bk ruwe vloer) | 10 | yes | V2 2e verd. (bk ruwe vloer) | D-4 | -275 | Minimum Intersection | 0
1567842 | V1 1e verd. (bk ruwe vloer) | 3515 | 6805040 | 0.0272202 | 0.219688 | V1 1e verd. (bk ruwe vloer) | 10 | yes | V2 2e verd. (bk ruwe vloer) | D-6 | -275 | Minimum Intersection | 0
1568687 | F1 begg (bk ruwe vloer) | 3525 | 6824400 | 0.0272976 | 0.220312 | F1 begg (bk ruwe vloer) | 0 | yes | V1 ok vloer | D-2(175) | -15 | Minimum Intersection | 0
1568742 | F1 begg (bk ruwe vloer) | 3525 | 6824400 | 0.0272976 | 0.220312 | F1 begg (bk ruwe vloer) | 0 | yes | V1 ok vloer | D-8(-175) | -15 | Minimum Intersection | 0
1568812 | V1 1e verd. (bk ruwe vloer) | 3515 | 6805040 | 0.0272202 | 0.219688 | V1 1e verd. (bk ruwe vloer) | 10 | yes | V2 2e verd. (bk ruwe vloer) | D-2(175) | -275 | Minimum Intersection | 0
1568814 | V1 1e verd. (bk ruwe vloer) | 3515 | 6805040 | 0.0272202 | 0.219688 | V1 1e verd. (bk ruwe vloer) | 10 | yes | V2 2e verd. (bk ruwe vloer) | D-8(-175) | -275 | Minimum Intersection | 0
1572394 | V1 1e verd. (bk ruwe vloer) | 3525 | 6824400 | 0.0272976 | 0.220313 | V1 1e verd. (bk ruwe vloer) | 0 | yes | V2 ok vloer | F-4 | -15 | Minimum Intersection | 0
1572670 | V1 1e verd. (bk ruwe vloer) | 3525 | 6824400 | 0.0272976 | 0.220313 | V1 1e verd. (bk ruwe vloer) | 0 | yes | V2 ok vloer | F-6 | -15 | Minimum Intersection | 0
1582758 | V2 2e verd. (bk ruwe vloer) | 4160 | 8053760 | 0.032215 | 0.26 | V2 2e verd. (bk ruwe vloer) | 10 | yes | V2 2e verd. (bk ruwe vloer) | D-4 | 4170 | Minimum Intersection | 0
1582760 | V2 2e verd. (bk ruwe vloer) | 4160 | 8053760 | 0.032215 | 0.26 | V2 2e verd. (bk ruwe vloer) | 10 | yes | V2 2e verd. (bk ruwe vloer) | D-6 | 4170 | Minimum Intersection | 0
1582766 | V2 2e verd. (bk ruwe vloer) | 2875 | 5566000 | 0.022264 | 0.179687 | V2 2e verd. (bk ruwe vloer) | 10 |  | V2 2e verd. (bk ruwe vloer) | D-2(236) | 2885
1582768 | V2 2e verd. (bk ruwe vloer) | 2875 | 5566000 | 0.022264 | 0.179687 | V2 2e verd. (bk ruwe vloer) | 10 |  | V2 2e verd. (bk ruwe vloer) | D-8(-236) | 2885
1608535 | V2 2e verd. (bk ruwe vloer) | 3085 | 5972560 | 0.0238902 | 0.192812 | V2 2e verd. (bk ruwe vloer) | 0 | yes | V3 dakvloer | B-5(-1300) | -225 | Minimum Intersection | 0
1608537 | V2 2e verd. (bk ruwe vloer) | 3085 | 5972560 | 0.0238902 | 0.192812 | V2 2e verd. (bk ruwe vloer) | 0 | yes | V3 dakvloer | B-5(1300) | -225 | Minimum Intersection | 0
1815797 | V2 2e verd. (bk ruwe vloer) | 3085 | 5972560 | 0.0238902 | 0.192812 | V2 2e verd. (bk ruwe vloer) | 0 | yes | V3 dakvloer | B-3 | -225 | Minimum Intersection | 0

# IfcColumn: btk_staal - Koker + beton:K250x250x8.0 (6)
Type - PredefinedType: COLUMN; Material: Metal - Steel - S275 J0H (standaard-kokers/buizen), Concrete - Cast-in-Place - C30/37
Type - Other - Category: Structural Columns; Family Name: btk_staal - Koker + beton
Type - Dimensions - b: 250 mm; Ht: 250 mm; kr: 16 mm; t: 8 mm
Type - Identity Data - Description: kokerprofiel-betongevuld; Model: kolom; Type Comments: 8Ø12 + bgls Ø8-150. Dekking 25mm; Type Mark: K2; Type Name: K250x250x8.0
Type - Materials and Finishes - Betonkwaliteit: Concrete - Cast-in-Place - C30/37; Staalkwaliteit: Metal - Steel - S275 J0H (standaard-kokers/buizen)
Type - Structural - Section Shape: 0; A: 7546.22 mm2; Shape: vierkant; W: 0.580925
Type - Pset_ColumnCommon - IsExternal: no; LoadBearing: yes
Type - Pset_ReinforcementBarPitchOfColumn - Description: kokerprofiel-betongevuld
BaseQuantities - CrossSectionArea: 54756 mm2
Pset_ColumnCommon - Slope: 0 deg; Reference: K250x250x8.0
Pset_QuantityTakeOff - Reference: K250x250x8.0; sets with these values: 2
Other - Family: btk_staal - Koker + beton; Family and Type: btk_staal - Koker + beton: K250x250x8.0; Type: K250x250x8.0; Type Id: 1813943
Constraints - Base Offset: 0 mm; Top is Attached: yes; Column Style: Vertical; Moves With Grids: yes
Construction - Attachment Justification At Top: Minimum Intersection; Offset From Attachment At Top: 0 mm
Identity Data - Has Association: yes
Phasing - Phase Created: 2. nieuwbouw
Name (btk_staal - Koker + beton:K250x250x8.0:...) | In | BaseQuantities, Length (mm) = Dimensions, Length (mm) | OuterSurfaceArea (mm2) | GrossVolume (m3) | NetVolume (m3) = Volume (m3) | Level = Base Level | Top Level | Column Location Mark | Top Offset (mm)
1564358 | F1 begg (bk ruwe vloer) | 3525 | 6598800 | 0.193015 | 0.220312 | F1 begg (bk ruwe vloer) | V1 ok vloer | B-2(-1300) | -15
1564841 | F1 begg (bk ruwe vloer) | 3525 | 6598800 | 0.193015 | 0.220312 | F1 begg (bk ruwe vloer) | V1 ok vloer | B-2(1300) | -15
1567767 | V1 1e verd. (bk ruwe vloer) | 3525 | 6598800 | 0.193015 | 0.220312 | V1 1e verd. (bk ruwe vloer) | V2 2e verd. (bk ruwe vloer) | B-2(-1300) | -275
1567771 | V1 1e verd. (bk ruwe vloer) | 3525 | 6598800 | 0.193015 | 0.220312 | V1 1e verd. (bk ruwe vloer) | V2 2e verd. (bk ruwe vloer) | B-2(1300) | -275
1608531 | V2 2e verd. (bk ruwe vloer) | 3085 | 5775120 | 0.168922 | 0.192812 | V2 2e verd. (bk ruwe vloer) | V3 dakvloer | B-2(-1300) | -225
1608533 | V2 2e verd. (bk ruwe vloer) | 3085 | 5775120 | 0.168922 | 0.192812 | V2 2e verd. (bk ruwe vloer) | V3 dakvloer | B-2(1300) | -225

# IfcColumn: btk_staal - Koker + beton:K300x300x8.0 (2)
In: F1 begg (bk ruwe vloer)
Type - PredefinedType: COLUMN; Material: Concrete - Cast-in-Place - C30/37, Metal - Steel - S275 J0H (standaard-kokers/buizen)
Type - Other - Category: Structural Columns; Family Name: btk_staal - Koker + beton
Type - Dimensions - b: 300 mm; Ht: 300 mm; kr: 16 mm; t: 8 mm
Type - Identity Data - Description: kokerprofiel-betongevuld; Model: kolom; Type Comments: 8Ø12 + bgls Ø8-150. Dekking 25mm; Type Mark: K3; Type Name: K300x300x8.0
Type - Materials and Finishes - Betonkwaliteit: Concrete - Cast-in-Place - C30/37; Staalkwaliteit: Metal - Steel - S275 J0H (standaard-kokers/buizen)
Type - Structural - Section Shape: 0; A: 9146.22 mm2; Shape: vierkant; W: 0.704097
Type - Pset_ColumnCommon - IsExternal: no; LoadBearing: yes
Type - Pset_ReinforcementBarPitchOfColumn - Description: kokerprofiel-betongevuld
BaseQuantities - Length: 3312.5 mm; CrossSectionArea: 9344 mm2; OuterSurfaceArea: 7738000 mm2; GrossVolume: 0.030952 m3; NetVolume: 0.298125 m3
Pset_ColumnCommon - Reference: K300x300x8.0
Pset_QuantityTakeOff - Reference: K300x300x8.0; sets with these values: 2
Other - Family: btk_staal - Koker + beton; Family and Type: btk_staal - Koker + beton: K300x300x8.0; Type: K300x300x8.0; Type Id: 1813945
Constraints - Level: F1 begg (bk ruwe vloer); Top is Attached: yes; Base Level: F1 begg (bk ruwe vloer); Column Style: Vertical; Moves With Grids: yes; Top Level: V1 ok vloer; Base Offset: -10 mm; Top Offset: -237.5 mm
Construction - Attachment Justification At Top: Minimum Intersection; Offset From Attachment At Top: 0 mm
Dimensions - Length: 3312.5 mm; Volume: 0.298125 m3
Identity Data - Has Association: yes
Phasing - Phase Created: 2. nieuwbouw
Name (btk_staal - Koker + beton:K300x300x8.0:...) | Column Location Mark
1551684 | F-6
1551871 | F-4

# IfcColumn: btk_staal - Koker:K100x100x5.0 (24)
Type - PredefinedType: COLUMN; Material: Metal - Steel - S275 J0H (standaard-kokers/buizen)
Type - Other - Category: Structural Columns; Family Name: btk_staal - Koker
Type - Dimensions - b: 100 mm; Ht: 100 mm; kr: 10 mm; t: 5 mm
Type - Identity Data - Description: kokerprofiel; Model: kolom; Type Name: K100x100x5.0
Type - Materials and Finishes - Structural Material: Metal - Steel - S275 J0H (standaard-kokers/buizen)
Type - Structural - Section Shape: 0; A: 1888 mm2; Shape: vierkant; W: 0.144614
Type - Pset_ColumnCommon - IsExternal: no; LoadBearing: yes
Type - Pset_ReinforcementBarPitchOfColumn - Description: kokerprofiel
Pset_ColumnCommon - Reference: K100x100x5.0
Pset_QuantityTakeOff - Reference: K100x100x5.0; sets with these values: 2
Other - Family: btk_staal - Koker; Family and Type: btk_staal - Koker: K100x100x5.0; Type: K100x100x5.0; Type Id: 1705430
Constraints - Column Style: Vertical; Moves With Grids: yes
Graphics - kolom hartlijn in plattegrond: no; kolom hartlijn lengte: 20 mm
Phasing - Phase Created: 2. nieuwbouw
Name (btk_staal - Koker:K100x100x5.0:...) | In | NetVolume (m3) = Volume (m3) | Base Level = Level | Top Level | Base Offset (mm) | Column Location Mark | Top Offset (mm) | Dimensions, Length (mm) | Has Association | BaseQuantities, Length (mm) | CrossSectionArea (mm2) | OuterSurfaceArea (mm2) | GrossVolume (m3) | Slope (deg)
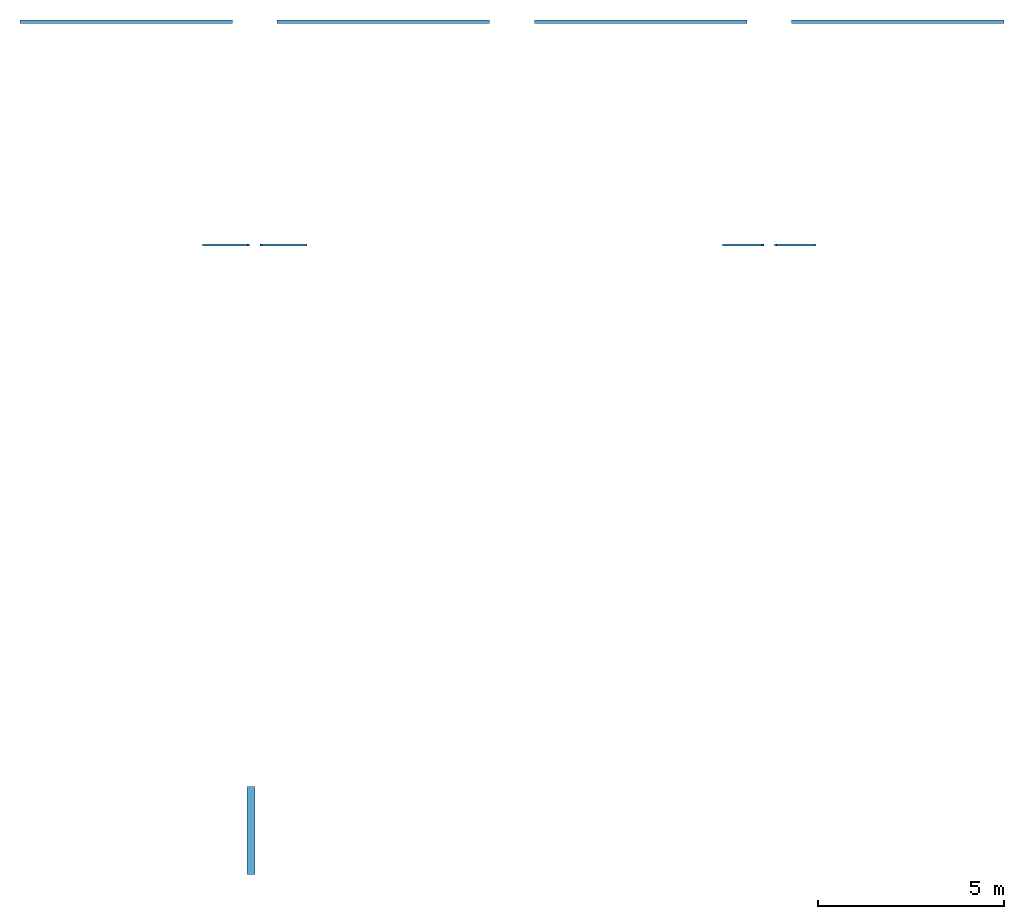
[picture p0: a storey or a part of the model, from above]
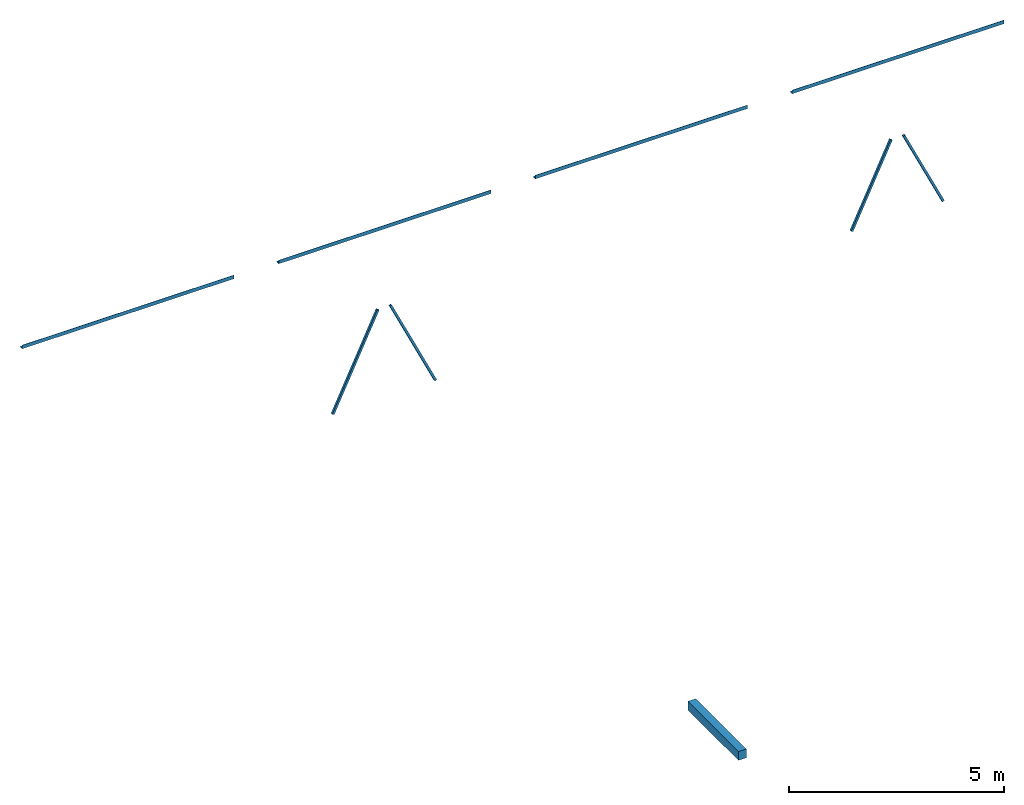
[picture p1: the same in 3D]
Properties of the parts of a building model (IFC2X3), part 5 of 6

# IfcColumn: btk_staal - Koker:K100x100x5.0 (24)
Name (btk_staal - Koker:K100x100x5.0:...) | In | NetVolume (m3) = Volume (m3) | Base Level = Level | Top Level | Base Offset (mm) | Column Location Mark | Top Offset (mm) | Dimensions, Length (mm) | Has Association | BaseQuantities, Length (mm) | CrossSectionArea (mm2) | OuterSurfaceArea (mm2) | GrossVolume (m3) | Slope (deg)
1604064 | V3 dakvloer | 0.00470418 | V3 dakvloer | V3 dakvloer | -50 | B(-50.2)-1(-107) | 2432.8 | 2482.8 | yes | BaseQuantities - GrossSurfaceArea: 0 mm2; Constraints - Top is Attached: yes; Base is Attached: yes; Construction - Attachment Justification At Top: Minimum Intersection; Offset From Attachment At Top: 0 mm; Attachment Justification At Base: Minimum Intersection; Offset From Attachment At Base: 0 mm
1839883 | V4 BK metselwerk | 0.00201344 | V4 BK metselwerk | V4 BK metselwerk | -802 | F-2(3400.9) | 257.706 | 1059.71 | yes | 1059.71 | 1900 | 805377 | 0.00201344 | 0 | Constraints - Top is Attached: yes; Construction - Attachment Justification At Top: Minimum Intersection; Offset From Attachment At Top: 0 mm
1839969 | V4 BK metselwerk | 0.0021033 | V4 BK metselwerk | V4 BK metselwerk | -850 | F-6(2474.1) | 257 | 1107 | yes | 1107 | 1900 | 841320 | 0.0021033 | 0
1857173 | V4 BK metselwerk | 0.00469518 | V4 BK metselwerk | V4 BK metselwerk | -910 | B(-50.2)-9 | 1700 | 2610 | yes |  |  |  |  | 20.9681 | BaseQuantities - GrossSurfaceArea: 0 mm2; Constraints - Base is Attached: yes; Construction - Attachment Justification At Base: Minimum Intersection; Offset From Attachment At Base: 0 mm
2011404 | V4 BK metselwerk | 0.00210464 | V4 BK metselwerk | V4 BK metselwerk | -850 | H(-97)-2(3400.9) | 257.706 | 1107.71 | no | 1107.71 | 1900 | 841857 | 0.00210464 | Constraints - Top is Attached: yes; Construction - Attachment Justification At Top: Minimum Intersection; Offset From Attachment At Top: 0 mm
2011484 | V4 BK metselwerk | 0.00210464 | V4 BK metselwerk | V4 BK metselwerk | -850 | H(-97)-4(3275.1) | 257.706 | 1107.71 | no | 1107.71 | 1900 | 841857 | 0.00210464 | Constraints - Top is Attached: yes; Construction - Attachment Justification At Top: Minimum Intersection; Offset From Attachment At Top: 0 mm
2011485 | V4 BK metselwerk | 0.0021033 | V4 BK metselwerk | V4 BK metselwerk | -850 | H(-97)-6(2474.1) | 257 | 1107 | no | 1107 | 1900 | 841320 | 0.0021033 | 0 | Group: Model Group:dakspant 1A (members excluded):2011268
2011738 | V4 BK metselwerk | 0.00213181 | V4 BK metselwerk | V4 BK metselwerk | -864.3 | F(-3600)-2(3400.9) | 257.706 | 1122.01 | no | 1122.01 | 1900 | 852725 | 0.00213181 | Constraints - Top is Attached: yes; Construction - Attachment Justification At Top: Minimum Intersection; Offset From Attachment At Top: 0 mm
2011818 | V4 BK metselwerk | 0.0021033 | V4 BK metselwerk | V4 BK metselwerk | -850 | F(-3600)-4(3275.1) | 257 | 1107 | no | 1107 | 1900 | 841320 | 0.0021033 | 0 | Group: Model Group:dakspant 1 (members excluded):2011580
2011819 | V4 BK metselwerk | 0.0021033 | V4 BK metselwerk | V4 BK metselwerk | -850 | F(-3600)-6(2474.1) | 257 | 1107 | no | 1107 | 1900 | 841320 | 0.0021033 | 0 | Group: Model Group:dakspant 1 (members excluded):2011580
2012037 | V4 BK metselwerk | 0.00210464 | V4 BK metselwerk | V4 BK metselwerk | -850 | G-2(3400.9) | 257.706 | 1107.71 | no | 1107.71 | 1900 | 841857 | 0.00210464 | 0 | Constraints - Top is Attached: yes; Construction - Attachment Justification At Top: Minimum Intersection; Offset From Attachment At Top: 0 mm
2012117 | V4 BK metselwerk | 0.0021033 | V4 BK metselwerk | V4 BK metselwerk | -850 | G-4(3275.1) | 257 | 1107 | no | 1107 | 1900 | 841320 | 0.0021033 | Group: Model Group:dakspant 1 (members excluded):2011879
2012118 | V4 BK metselwerk | 0.0021033 | V4 BK metselwerk | V4 BK metselwerk | -850 | G-6(2474.1) | 257 | 1107 | no | 1107 | 1900 | 841320 | 0.0021033 | 0 | Group: Model Group:dakspant 1 (members excluded):2011879
2012336 | V4 BK metselwerk | 0.00213179 | V4 BK metselwerk | V4 BK metselwerk | -864.289 | G(-3575)-2(3400.9) | 257.706 | 1122 | no | 1122 | 1900 | 852716 | 0.00213179 | Constraints - Top is Attached: yes; Base is Attached: yes; Construction - Attachment Justification At Top: Minimum Intersection; Offset From Attachment At Top: 0 mm; Attachment Justification At Base: Minimum Intersection; Offset From Attachment At Base: 0 mm
2012416 | V4 BK metselwerk | 0.0021033 | V4 BK metselwerk | V4 BK metselwerk | -850 | G(-3575)-4(3275.1) | 257 | 1107 | no | 1107 | 1900 | 841320 | 0.0021033 | 0 | Group: Model Group:dakspant 1 (members excluded):2012178
2012417 | V4 BK metselwerk | 0.0021033 | V4 BK metselwerk | V4 BK metselwerk | -850 | G(-3575)-6(2474.1) | 257 | 1107 | no | 1107 | 1900 | 841320 | 0.0021033 | 0 | Group: Model Group:dakspant 1 (members excluded):2012178
2013961 | V4 BK metselwerk | 0.0016701 | V4 BK metselwerk | V4 BK metselwerk | -870 | D-2(3400.9) | 9 | 879 | no | 879 | 1900 | 668040 | 0.0016701 | Constraints - Top is Attached: yes; Construction - Attachment Justification At Top: Minimum Intersection; Offset From Attachment At Top: 0 mm
2013963 | V4 BK metselwerk | 0.0016701 | V4 BK metselwerk | V4 BK metselwerk | -870 | D-6(2474.1) | 9 | 879 | no | 879 | 1900 | 668040 | 0.0016701 | Constraints - Top is Attached: yes; Construction - Attachment Justification At Top: Minimum Intersection; Offset From Attachment At Top: 0 mm
2015839 | V4 BK metselwerk | 0.00469518 | V4 BK metselwerk | V4 BK metselwerk | -910 | B(-50.2)-2 | 1800 | 2710 | no | BaseQuantities - GrossSurfaceArea: 0 mm2; Group: Model Group:Spant 5 (members excluded):2015775
2015956 | V4 BK metselwerk | 0.00469518 | V4 BK metselwerk | V4 BK metselwerk | -910 | B(-50.2)-3 | 1800 | 2710 | no |  |  |  |  | 20.9681 | BaseQuantities - GrossSurfaceArea: 0 mm2; Group: Model Group:Spant 5 (members excluded):2015892
2016071 | V4 BK metselwerk | 0.00469518 | V4 BK metselwerk | V4 BK metselwerk | -910 | B(-50.2)-5 | 1800 | 2710 | no |  |  |  |  | 20.9681 | BaseQuantities - GrossSurfaceArea: 0 mm2; Group: Model Group:Spant 5 (members excluded):2016007
2016186 | V4 BK metselwerk | 0.00469518 | V4 BK metselwerk | V4 BK metselwerk | -910 | B(-50.2)-7 | 1800 | 2710 | no |  |  |  |  | 20.9681 | BaseQuantities - GrossSurfaceArea: 0 mm2; Group: Model Group:Spant 5 (members excluded):2016122
2077815 | V1 1e verd. (bk ruwe vloer) | 0.0051265 | V1 1e verd. (bk ruwe vloer) | V2 ok vloer | 0 | B(-2446.7)-10(290) | -841.843 | 2698.16 | no | 2698.16 | 1900 | 2050599 | 0.0051265 | Constraints - Top is Attached: yes; Construction - Attachment Justification At Top: Minimum Intersection; Offset From Attachment At Top: 0 mm
2077816 | V1 1e verd. (bk ruwe vloer) | 0.00526166 | V1 1e verd. (bk ruwe vloer) | V2 ok vloer | 0 | B(2063.9)-10(290) | -770.703 | 2769.3 | no | 2769.3 | 1900 | 2104665 | 0.00526166 | Constraints - Top is Attached: yes; Construction - Attachment Justification At Top: Minimum Intersection; Offset From Attachment At Top: 0 mm

# IfcColumn: btk_staal - Koker:K150x150x5.0 (3)
In: F1 begg (bk ruwe vloer)
Type - PredefinedType: COLUMN; Material: Metal - Steel - S275 J0H (standaard-kokers/buizen)
Type - Other - Category: Structural Columns; Family Name: btk_staal - Koker
Type - Dimensions - b: 150 mm; Ht: 150 mm; kr: 10 mm; t: 5 mm
Type - Identity Data - Description: kokerprofiel; Model: kolom; Type Name: K150x150x5.0
Type - Materials and Finishes - Structural Material: Metal - Steel - S275 J0H (standaard-kokers/buizen)
Type - Structural - Section Shape: 0; A: 2822.74 mm2; Shape: vierkant; W: 0.217301
Type - Pset_ColumnCommon - IsExternal: no; LoadBearing: yes
Type - Pset_ReinforcementBarPitchOfColumn - Description: kokerprofiel
BaseQuantities - CrossSectionArea: 2900 mm2
Pset_ColumnCommon - Reference: K150x150x5.0
Pset_QuantityTakeOff - Reference: K150x150x5.0; sets with these values: 2
Other - Family: btk_staal - Koker; Family and Type: btk_staal - Koker: K150x150x5.0; Type: K150x150x5.0; Type Id: 1810069
Constraints - Level: F1 begg (bk ruwe vloer); Base Offset: 0 mm; Base Level: F1 begg (bk ruwe vloer); Column Style: Vertical; Moves With Grids: yes; Top Level: V1 ok vloer
Graphics - kolom hartlijn in plattegrond: no; kolom hartlijn lengte: 20 mm
Identity Data - Has Association: yes
Phasing - Phase Created: 2. nieuwbouw
Name (btk_staal - Koker:K150x150x5.0:...) | BaseQuantities, Length (mm) = Dimensions, Length (mm) | OuterSurfaceArea (mm2) | GrossVolume (m3) = NetVolume (m3) = Volume (m3) | Column Location Mark | Top Offset (mm) | Top is Attached | Attachment Justification At Top | Offset From Attachment At Top (mm)
1810022 | 3525 | 4089000 | 0.0102225 | B(-2446.7)-10(-100) | -15
1922065 | 3400 | 3944000 | 0.00986 | B(-2446.7)-10(290) | -140 | yes | Minimum Intersection | 0
1922116 | 3400 | 3944000 | 0.00986 | B(2063.9)-10(290) | -140 | yes | Minimum Intersection | 0

# IfcColumn: btk_staal - Koker:K80x80x6 (14)
Type - PredefinedType: COLUMN; Material: Metal - Steel - S275 J0H (standaard-kokers/buizen)
Type - Other - Category: Structural Columns; Family Name: btk_staal - Koker
Type - Dimensions - b: 80 mm; Ht: 80 mm; kr: 12 mm; t: 6 mm
Type - Identity Data - Description: kokerprofiel; Model: kolom; Type Name: K80x80x6
Type - Materials and Finishes - Structural Material: Metal - Steel - S275 J0H (standaard-kokers/buizen)
Type - Structural - Section Shape: 0; A: 1488 mm2; Shape: vierkant; W: 0.113821
Type - Pset_ColumnCommon - IsExternal: no; LoadBearing: yes
Type - Pset_ReinforcementBarPitchOfColumn - Description: kokerprofiel
BaseQuantities - CrossSectionArea: 1776 mm2
Pset_ColumnCommon - Reference: K80x80x6
Pset_QuantityTakeOff - Reference: K80x80x6; sets with these values: 2
Other - Family: btk_staal - Koker; Family and Type: btk_staal - Koker: K80x80x6; Type: K80x80x6; Type Id: 1819390
Constraints - Column Style: Vertical; Moves With Grids: yes
Graphics - kolom hartlijn in plattegrond: no; kolom hartlijn lengte: 20 mm
Identity Data - Has Association: yes
Phasing - Phase Created: 2. nieuwbouw
Name (btk_staal - Koker:K80x80x6:...) | In | BaseQuantities, Length (mm) = Dimensions, Length (mm) | OuterSurfaceArea (mm2) | GrossVolume (m3) = NetVolume (m3) = Volume (m3) | Level = Base Level | Base Offset (mm) | Top is Attached | Top Level | Column Location Mark | Top Offset (mm) | Attachment Justification At Top | Offset From Attachment At Top (mm)
1819394 | F1 begg (bk ruwe vloer) | 1637.68 | 969507 | 0.00290852 | F1 begg (bk ruwe vloer) | 0 | yes | F1 begg (bk ruwe vloer) | C(-2476)-5(-1699.3) | 1637.68 | Minimum Intersection | 0
1819571 | F1 begg (bk ruwe vloer) | 2382.6 | 1410499 | 0.0042315 | F1 begg (bk ruwe vloer) | 0 | yes | V1 ok vloer | C(-376)-4(2624.8) | -1157.4 | Minimum Intersection | 0
1820729 | KDV V1 1e verd. (bk ruwe vloer) | 997.4 | 590461 | 0.00177138 | V1 ok vloer | -997.4 | yes | F1 begg (bk ruwe vloer) | C(-376)-4(2624.8) | 3540 | Minimum Intersection | 0 | Constraints - Base is Attached: yes; Construction - Attachment Justification At Base: Minimum Intersection; Offset From Attachment At Base: 0 mm
1820930 | F1 begg (bk ruwe vloer) | 2382.6 | 1410499 | 0.0042315 | F1 begg (bk ruwe vloer) | 0 | yes | V1 ok vloer | C(-376)-5(-98.4) | -1157.4 | Minimum Intersection | 0
1821256 | KDV V1 1e verd. (bk ruwe vloer) | 997.4 | 590461 | 0.00177138 | V1 ok vloer | -997.4 | yes | V1 ok vloer | C(-376)-5(-98.4) | 0 | Minimum Intersection | 0 | Constraints - Base is Attached: yes; Construction - Attachment Justification At Base: Minimum Intersection; Offset From Attachment At Base: 0 mm
1821673 | F1 begg (bk ruwe vloer) | 2382.6 | 1410499 | 0.0042315 | F1 begg (bk ruwe vloer) | 0 | yes | V1 ok vloer | C(-376)-6(-959.3) | -1157.4 | Minimum Intersection | 0
1821769 | KDV V1 1e verd. (bk ruwe vloer) | 997.4 | 590461 | 0.00177138 | V1 ok vloer | -997.4 | yes | V1 ok vloer | C(-376)-6(-959.3) | 0 | Minimum Intersection | 0 | Constraints - Base is Attached: yes; Construction - Attachment Justification At Base: Minimum Intersection; Offset From Attachment At Base: 0 mm
1824002 | F1 begg (bk ruwe vloer) | 1637.68 | 969507 | 0.00290852 | F1 begg (bk ruwe vloer) | 0 | yes | F1 begg (bk ruwe vloer) | C(-2476)-4(2624.8) | 1637.68 | Minimum Intersection | 0
1824030 | F1 begg (bk ruwe vloer) | 1637.68 | 969507 | 0.00290852 | F1 begg (bk ruwe vloer) | 0 | yes | F1 begg (bk ruwe vloer) | C(-2476)-5(-98.4) | 1637.68 | Minimum Intersection | 0
1824052 | F1 begg (bk ruwe vloer) | 1637.68 | 969507 | 0.00290852 | F1 begg (bk ruwe vloer) | 0 |  | F1 begg (bk ruwe vloer) | C(-2476)-6(-575.9) | 1637.68
1828466 | F1 begg (bk ruwe vloer) | 2382.6 | 1410499 | 0.0042315 | F1 begg (bk ruwe vloer) | 0 | yes | V1 ok vloer | C(-376)-4(860.7) | -1157.4 | Minimum Intersection | 0
1828725 | KDV V1 1e verd. (bk ruwe vloer) | 997.4 | 590461 | 0.00177138 | V1 ok vloer | -997.4 | yes | V1 ok vloer | C(-376)-4(860.7) | 0 | Minimum Intersection | 0 | Constraints - Base is Attached: yes; Construction - Attachment Justification At Base: Minimum Intersection; Offset From Attachment At Base: 0 mm
1829267 | F1 begg (bk ruwe vloer) | 1594.75 | 944090 | 0.00283227 | F1 begg (bk ruwe vloer) | 0 | yes | F1 begg (bk ruwe vloer) | C(-2476)-4(1495.2) | 1594.75 | Minimum Intersection | 0
1829500 | F1 begg (bk ruwe vloer) | 1594.75 | 944090 | 0.00283227 | F1 begg (bk ruwe vloer) | 0 | yes | F1 begg (bk ruwe vloer) | C(-2297.1)-4(511.3) | 1594.75 | Minimum Intersection | 0

# IfcColumn: btk_staal - Koker:K90x90x8 (4)
Type - PredefinedType: COLUMN; Material: Metal - Steel - S275 J0H (standaard-kokers/buizen)
Type - Other - Category: Structural Columns; Family Name: btk_staal - Koker
Type - Dimensions - b: 90 mm; Ht: 90 mm; kr: 16 mm; t: 8 mm
Type - Identity Data - Description: kokerprofiel; Model: kolom; Type Name: K90x90x8
Type - Materials and Finishes - Structural Material: Metal - Steel - S275 J0H (standaard-kokers/buizen)
Type - Structural - Section Shape: 0; A: 1488 mm2; Shape: vierkant; W: 0.113821
Type - Pset_ColumnCommon - IsExternal: no; LoadBearing: yes
Type - Pset_ReinforcementBarPitchOfColumn - Description: kokerprofiel
BaseQuantities - CrossSectionArea: 2624 mm2
Pset_ColumnCommon - Reference: K90x90x8
Pset_QuantityTakeOff - Reference: K90x90x8; sets with these values: 2
Other - Family: btk_staal - Koker; Family and Type: btk_staal - Koker: K90x90x8; Type: K90x90x8; Type Id: 1869064
Constraints - Column Style: Vertical; Moves With Grids: yes
Graphics - kolom hartlijn in plattegrond: no; kolom hartlijn lengte: 20 mm
Identity Data - Has Association: yes
Phasing - Phase Created: 2. nieuwbouw
Name (btk_staal - Koker:K90x90x8:...) | In | BaseQuantities, Length (mm) = Dimensions, Length (mm) | OuterSurfaceArea (mm2) | GrossVolume (m3) = NetVolume (m3) = Volume (m3) | Top Offset (mm) | Level = Base Level | Top Level | Base Offset (mm) | Column Location Mark
1683599 | V1 1e verd. (bk ruwe vloer) | 3600 | 2361600 | 0.0094464 | 0 | V1 1e verd. (bk ruwe vloer) | V2 ok vloer | -60 | F(1395.1)-2(3654.9)
1866597 | F1 begg (bk ruwe vloer) | 3530 | 2315680 | 0.00926272 | -10 | F1 begg (bk ruwe vloer) | V1 ok vloer | 0 | F(1395.1)-2(3654.9)
1868516 | V1 1e verd. (bk ruwe vloer) | 3600 | 2361600 | 0.0094464 | 0 | V1 1e verd. (bk ruwe vloer) | V2 ok vloer | -60 | F(400)-2(3654.9)
1868518 | F1 begg (bk ruwe vloer) | 3530 | 2315680 | 0.00926272 | -10 | F1 begg (bk ruwe vloer) | V1 ok vloer | 0 | F(400)-2(3654.9)

# IfcColumn: btk_staal - UNP:UNP160 (3)
In: V2 2e verd. (bk ruwe vloer)
Type - PredefinedType: COLUMN; Material: Metal - Steel - S235 JRG2 (standaard)
Type - Other - Category: Structural Columns; Family Name: btk_staal - UNP
Type - Dimensions - bf: 65 mm; d: 160 mm; tf: 10.5 mm; tw: 7.5 mm; x: 18.4 mm
Type - Identity Data - Model: kolom; Type Mark: K0; Type Name: UNP160
Type - Materials and Finishes - Structural Material: Metal - Steel - S235 JRG2 (standaard)
Type - Structural - Section Shape: 0; A: 2401 mm2; W: 0.184855
Type - Pset_ColumnCommon - IsExternal: no; LoadBearing: yes
BaseQuantities - GrossSurfaceArea: 0 mm2
Pset_ColumnCommon - Reference: UNP160
Pset_QuantityTakeOff - Reference: UNP160; sets with these values: 2
Other - Type: UNP160; Family: btk_staal - UNP; Family and Type: btk_staal - UNP: UNP160; Type Id: 2123857
Constraints - Top Offset: 0 mm; Column Style: Vertical; Moves With Grids: yes; Top Level: V4 BK metselwerk; Base Level: 07400 V2 2e verd; Level: 07400 V2 2e verd; Base Offset: 3250 mm
Dimensions - Length: 850 mm
Identity Data - Has Association: no
Phasing - Phase Created: 2. nieuwbouw
Name (btk_staal - UNP:UNP160:...) | NetVolume (m3) = Volume (m3) | Column Location Mark
2108207 | 0.00105998 | C(-120.9)-6(426.9)
2108226 | 0.00105998 | C(-120.9)-6(1836.8)
2109611 | 0.00103471 | C(-120.9)-3(-1629)

# IfcFooting: btl_ihwg - Poer 4-hoek:2200x2200x1000 4pp (4)
In: F1 begg (bk ruwe vloer)
Type - Material: Beton, ihwg C30/37
Type - Other - Category: Structural Foundations; Family Name: btl_ihwg - Poer 4-hoek
Type - Dimensions - Height: 1000 mm; Length: 2200 mm; Width: 2200 mm
Type - Identity Data - Model: poer; Type Name: 2200x2200x1000 4pp
Type - Materials and Finishes - Structural Material: Beton, ihwg C30/37
Pset_QuantityTakeOff - Reference: 2200x2200x1000 4pp; sets with these values: 3
Other - Family: btl_ihwg - Poer 4-hoek; Family and Type: btl_ihwg - Poer 4-hoek: 2200x2200x1000 4pp; Type: 2200x2200x1000 4pp; Type Id: 2000617
Constraints - Height Offset From Level: 0 mm; Moves With Grids: yes; Level: F2 (bk fundering); Host: Level : F2 (bk fundering)
Dimensions - Area: 4840000 mm2; Elevation at Bottom: -1480 mm; Elevation at Bottom Survey: -1480 mm; Elevation at Top: -480 mm; Elevation at Top Survey: -480 mm; Volume: 4.84 m3
Identity Data - Has Association: no
Phasing - Phase Created: 2. nieuwbouw
Structural - Rebar Cover - Bottom Face: Rebar Cover 1 <25 mm>; Rebar Cover - Other Faces: Rebar Cover 1 <25 mm>; Rebar Cover - Top Face: Rebar Cover 1 <25 mm>
Name (btl_ihwg - Poer 4-hoek:2200x2200x1000 4pp:...)
2000650
2000735
2237231
2237232

# IfcGroup: Model Group:Spant 3 (3)
Other - Category: Model Groups; Family: Model Group; Family and Type: Model Group: Spant 3; Type: Spant 3; Type Id: 1592839
Constraints - Reference Level: V4 BK metselwerk; Origin Level Offset: -1060.35 mm
Other(Type) - Category: Model Groups; Family Name: Model Group
Identity Data(Type) - Type Name: Spant 3
Name (Model Group:Spant 3:...)
2012551
2012732
2012913

# IfcGroup: Model Group:Spant 4 (4)
Other - Category: Model Groups; Family: Model Group; Family and Type: Model Group: Spant 4; Type: Spant 4; Type Id: 1597068
Constraints - Reference Level: V4 BK metselwerk; Origin Level Offset: -1032.12 mm
Other(Type) - Category: Model Groups; Family Name: Model Group
Identity Data(Type) - Type Name: Spant 4
Name (Model Group:Spant 4:...)
2013463
2013474
2013485
2013496

# IfcGroup: Model Group:Spant 5 (4)
Other - Category: Model Groups; Family: Model Group; Family and Type: Model Group: Spant 5; Type: Spant 5; Type Id: 1604882
Constraints - Origin Level Offset: -50 mm; Reference Level: V2 2e verd. (bk ruwe vloer)
Other(Type) - Category: Model Groups; Family Name: Model Group
Identity Data(Type) - Type Name: Spant 5
Name (Model Group:Spant 5 (members excluded):...)
2015775
2015892
2016007
2016122

# IfcGroup: Model Group:dakspant 1 (3)
Other - Category: Model Groups; Family: Model Group; Family and Type: Model Group: dakspant 1; Type: dakspant 1; Type Id: 1581221
Constraints - Origin Level Offset: 0 mm; Reference Level: V4 BK metselwerk
Other(Type) - Category: Model Groups; Family Name: Model Group
Identity Data(Type) - Type Name: dakspant 1
Name (Model Group:dakspant 1 (members excluded):...)
2011580
2011879
2012178

# IfcGroup: Model Group:dakspant 1A, Model Group:dakspant 1A (members excluded):2011268
Other - Category: Model Groups; Family: Model Group; Family and Type: Model Group: dakspant 1A; Type: dakspant 1A; Type Id: 1840763
Constraints - Origin Level Offset: 0 mm; Reference Level: V4 BK metselwerk
Other(Type) - Category: Model Groups; Family Name: Model Group
Identity Data(Type) - Type Name: dakspant 1A

# IfcGroup: Model Group:koppeling stalen kolom aan ligget tpv vide (4)
Other - Category: Model Groups; Family: Model Group; Family and Type: Model Group: koppeling stalen kolom aan ligget tpv vide; Type: koppeling stalen kolom aan ligget tpv vide; Type Id: 1831326
Constraints - Origin Level Offset: -334.211 mm; Reference Level: V1 1e verd. (bk ruwe vloer)
Other(Type) - Category: Model Groups; Family Name: Model Group
Identity Data(Type) - Type Name: koppeling stalen kolom aan ligget tpv vide
Name (Model Group:koppeling stalen kolom aan ligget tpv vide (members excluded):...)
1831325
1831406
1831465
1831536

# IfcGroup: Model Group:tribune spant (3)
Other - Category: Model Groups; Family: Model Group; Family and Type: Model Group: tribune spant; Type: tribune spant; Type Id: 1820484
Constraints - Origin Level Offset: -96.8812 mm; Reference Level: 00000 begg
Other(Type) - Category: Model Groups; Family Name: Model Group
Identity Data(Type) - Type Name: tribune spant
Name (Model Group:tribune spant (members excluded):...)
1820483
1820524
1820546

# IfcOpeningElement: Opening (83)
Name | In | Depth (mm) | BaseQuantities, Height (mm) | BaseQuantities, Width (mm)
Basic Wall:bt_kzst 214:1543078 | F1 begg (bk ruwe vloer) | 214 | 1222 | 4860 | Classification: (28.d) Uniformat (Uniformat); Pset_OpeningElementCommon - Reference: bt_kzst 214; sets with these values: 2; Other - Category: Walls: Rectangular Straight Wall Opening; Constraints - Top Constraint: Up to level: V1 ok vloer; Base Constraint: F2 (bk fundering); Base Offset: 3188 mm; Top Offset: 460 mm; Unconnected Height: 1222 mm; Phasing - Phase Created: 2. nieuwbouw
Basic Wall:bt_kzst 214:1543875 | F1 begg (bk ruwe vloer) | 214 | 1222 | 470.3 | Classification: (28.d) Uniformat (Uniformat); Pset_OpeningElementCommon - Reference: bt_kzst 214; sets with these values: 2; Other - Category: Walls: Rectangular Straight Wall Opening; Constraints - Top Constraint: Up to level: V1 ok vloer; Base Constraint: F2 (bk fundering); Base Offset: 3188 mm; Top Offset: 460 mm; Unconnected Height: 1222 mm; Phasing - Phase Created: 2. nieuwbouw
Basic Wall:bt_kzst 214:1543875 | F1 begg (bk ruwe vloer) | 3048 | 2295 | 5700.3 | Classification: (28.d) Uniformat (Uniformat); Pset_OpeningElementCommon - Reference: variabel - raam met borstwering; sets with these values: 2; Other - Category: Windows; Family: bt_raamsparing_variabel; Family and Type: bt_raamsparing_variabel: variabel - raam met borstwering; Head Height: 2778 mm; Host Id: 1911856; Type: variabel - raam met borstwering; Type Id: 1140486; Phasing - Phase Created: 2. nieuwbouw; Analysis Results - oppervlakte: 13082192 mm2; oppervlakte in m2: 13.0822 mm; Constraints - Level: F1 begg (bk ruwe vloer); Sill Height: 483 mm; Dimensions - Area: 14793187 mm2; Height: 2295 mm; Sill Height (ter info): 1000 mm; Width: 5700.3 mm; Graphics - Opening gevuld: no; Identity Data - Mark: 55; Other(Type) - Category: Windows; Family Name: bt_raamsparing_variabel; Graphics(Type) - baz streepjes borstwering: no; baz streepjes kruis: yes; Identity Data(Type) - Type Mark: 31; Type Name: variabel - raam met borstwering; Analytical Properties(Type) - Analytic Construction: <None>; Define Thermal Properties by: Schematic Type
Basic Wall:bt_kzst 214:1544769 | F1 begg (bk ruwe vloer) | 214 | 1222 | 300 | Classification: (28.d) Uniformat (Uniformat); Pset_OpeningElementCommon - Reference: bt_kzst 214; sets with these values: 2; Other - Category: Walls: Rectangular Straight Wall Opening; Constraints - Top Constraint: Up to level: V1 ok vloer; Base Constraint: F2 (bk fundering); Base Offset: 3188 mm; Top Offset: 460 mm; Unconnected Height: 1222 mm; Phasing - Phase Created: 2. nieuwbouw
Basic Wall:bt_kzst 214:1544769 | F1 begg (bk ruwe vloer) | 3048 | 2340 | 1200.28 | Classification: (28.d) Uniformat (Uniformat); Pset_OpeningElementCommon - Reference: variabel - raam met borstwering; sets with these values: 2; Other - Category: Windows; Family: bt_raamsparing_variabel; Family and Type: bt_raamsparing_variabel: variabel - raam met borstwering; Head Height: 2708 mm; Host Id: 1543078; Type: variabel - raam met borstwering; Type Id: 1140486; Phasing - Phase Created: 2. nieuwbouw; Analysis Results - oppervlakte: 2808666 mm2; oppervlakte in m2: 2.80867 mm; Constraints - Level: 00000 begg; Sill Height: 368 mm; Dimensions - Area: 3566287 mm2; Height: 2340 mm; Sill Height (ter info): 1000 mm; Width: 1200.28 mm; Graphics - Opening gevuld: no; Identity Data - Mark: 84; Other(Type) - Category: Windows; Family Name: bt_raamsparing_variabel; Graphics(Type) - baz streepjes borstwering: no; baz streepjes kruis: yes; Identity Data(Type) - Type Mark: 31; Type Name: variabel - raam met borstwering; Analytical Properties(Type) - Analytic Construction: <None>; Define Thermal Properties by: Schematic Type
Basic Wall:bt_kzst 214:1545493 | F1 begg (bk ruwe vloer) | 214 | 1172 | 300 | Classification: (28.d) Uniformat (Uniformat); Pset_OpeningElementCommon - Reference: bt_kzst 214; sets with these values: 2; Other - Category: Walls: Rectangular Straight Wall Opening; Constraints - Top Constraint: Up to level: V1 ok vloer; Base Constraint: F2 (bk fundering); Base Offset: 3188 mm; Top Offset: 410 mm; Unconnected Height: 1172 mm; Phasing - Phase Created: 2. nieuwbouw
Basic Wall:bt_kzst 214:1546130 | F1 begg (bk ruwe vloer) | 214 | 1222 | 300 | Classification: (28.d) Uniformat (Uniformat); Pset_OpeningElementCommon - Reference: bt_kzst 214; sets with these values: 2; Other - Category: Walls: Rectangular Straight Wall Opening; Constraints - Top Constraint: Up to level: V1 ok vloer; Base Constraint: F2 (bk fundering); Base Offset: 3188 mm; Top Offset: 460 mm; Unconnected Height: 1222 mm; Phasing - Phase Created: 2. nieuwbouw
Basic Wall:bt_kzst 214:1549191 | F1 begg (bk ruwe vloer) | 214 | 762 | 299.014 | Classification: (28.d) Uniformat (Uniformat); Pset_OpeningElementCommon - Reference: bt_kzst 214; sets with these values: 2; Other - Category: Walls: Rectangular Straight Wall Opening; Constraints - Top Constraint: Up to level: V1 ok vloer; Base Constraint: F1 begg (bk ruwe vloer); Base Offset: 2778 mm; Top Offset: 0 mm; Unconnected Height: 762 mm; Phasing - Phase Created: 2. nieuwbouw
Basic Wall:bt_kzst 300:355912 | F1 begg (bk ruwe vloer) |  | 3250 | 60 | Classification: (28.d) Uniformat (Uniformat); Pset_OpeningElementCommon - Reference: bt_kzst 300; sets with these values: 2; Other - Category: Lines: <Sketch>; Dimensions - Length: 3250 mm
Basic Wall:bt_kzst 214:1555450 | F1 begg (bk ruwe vloer) | 214 | 1172 | 300 | Classification: (28.d) Uniformat (Uniformat); Pset_OpeningElementCommon - Reference: bt_kzst 214; sets with these values: 2; Other - Category: Walls: Rectangular Straight Wall Opening; Constraints - Top Constraint: Up to level: V1 ok vloer; Base Constraint: F2 (bk fundering); Base Offset: 3188 mm; Top Offset: 410 mm; Unconnected Height: 1172 mm; Phasing - Phase Created: 2. nieuwbouw
Basic Wall:bt_kzst 214:1555450 | F1 begg (bk ruwe vloer) | 214 | 220 | 1311.18 | Classification: (28.d) Uniformat (Uniformat); Pset_OpeningElementCommon - Reference: Generic Models 6; sets with these values: 2; Other - Category: Generic Models; Family: Generic Models 6; Family and Type: Generic Models 6: Generic Models 6; Type: Generic Models 6; Type Id: 1935071; Phasing - Phase Created: 2. nieuwbouw; Other(Type) - Category: Generic Models; Family Name: Generic Models 6; Identity Data(Type) - Type Name: Generic Models 6; Constraints - Elevation from Level: 0 mm; Moves With Nearby Elements: no
Basic Wall:bt_kzst 214:1571056 | V1 1e verd. (bk ruwe vloer) | 214 | 762 | 470.3 | Classification: (28.d) Uniformat (Uniformat); Pset_OpeningElementCommon - Reference: bt_kzst 214; sets with these values: 2; Other - Category: Walls: Rectangular Straight Wall Opening; Constraints - Top Constraint: Up to level: V2 ok vloer; Base Constraint: V1 1e verd. (bk ruwe vloer); Base Offset: 2778 mm; Top Offset: 0 mm; Unconnected Height: 762 mm; Phasing - Phase Created: 2. nieuwbouw
Basic Wall:bt_kzst 214:1571056 | V1 1e verd. (bk ruwe vloer) | 3048 | 2340 | 5700.3 | Classification: (28.d) Uniformat (Uniformat); Pset_OpeningElementCommon - Reference: variabel - raam met borstwering; sets with these values: 2; Other - Category: Windows; Family: bt_raamsparing_variabel; Family and Type: bt_raamsparing_variabel: variabel - raam met borstwering; Head Height: 2708 mm; Host Id: 1571026; Type: variabel - raam met borstwering; Type Id: 1140486; Phasing - Phase Created: 2. nieuwbouw; Analysis Results - oppervlakte: 13338706 mm2; oppervlakte in m2: 13.3387 mm; Constraints - Level: 03800 V1 1e verd; Sill Height: 368 mm; Dimensions - Area: 15059331 mm2; Height: 2340 mm; Sill Height (ter info): 1000 mm; Width: 5700.3 mm; Graphics - Opening gevuld: no; Identity Data - Mark: 59; Other(Type) - Category: Windows; Family Name: bt_raamsparing_variabel; Graphics(Type) - baz streepjes borstwering: no; baz streepjes kruis: yes; Identity Data(Type) - Type Mark: 31; Type Name: variabel - raam met borstwering; Analytical Properties(Type) - Analytic Construction: <None>; Define Thermal Properties by: Schematic Type
Basic Wall:bt_kzst 214:1571698 | V1 1e verd. (bk ruwe vloer) | 214 | 762 | 4860 | Classification: (28.d) Uniformat (Uniformat); Pset_OpeningElementCommon - Reference: bt_kzst 214; sets with these values: 2; Other - Category: Walls: Rectangular Straight Wall Opening; Constraints - Top Constraint: Up to level: V2 ok vloer; Base Constraint: V1 1e verd. (bk ruwe vloer); Base Offset: 2778 mm; Top Offset: 0 mm; Unconnected Height: 762 mm; Phasing - Phase Created: 2. nieuwbouw
Basic Wall:bt_kzst 214:1571801 | V1 1e verd. (bk ruwe vloer) | 214 | 762 | 300 | Classification: (28.d) Uniformat (Uniformat); Pset_OpeningElementCommon - Reference: bt_kzst 214; sets with these values: 2; Other - Category: Walls: Rectangular Straight Wall Opening; Constraints - Top Constraint: Up to level: V2 ok vloer; Base Constraint: V1 1e verd. (bk ruwe vloer); Base Offset: 2778 mm; Top Offset: 0 mm; Unconnected Height: 762 mm; Phasing - Phase Created: 2. nieuwbouw
Basic Wall:bt_kzst 214:1571801 | V1 1e verd. (bk ruwe vloer) | 3048 | 2340 | 1200.28 | Classification: (28.d) Uniformat (Uniformat); Pset_OpeningElementCommon - Reference: variabel - raam met borstwering; sets with these values: 2; Other - Category: Windows; Family: bt_raamsparing_variabel; Family and Type: bt_raamsparing_variabel: variabel - raam met borstwering; Head Height: 2708 mm; Host Id: 1571698; Type: variabel - raam met borstwering; Type Id: 1140486; Phasing - Phase Created: 2. nieuwbouw; Analysis Results - oppervlakte: 2808666 mm2; oppervlakte in m2: 2.80867 mm; Constraints - Level: 03800 V1 1e verd; Sill Height: 368 mm; Dimensions - Area: 3566287 mm2; Height: 2340 mm; Sill Height (ter info): 1000 mm; Width: 1200.28 mm; Graphics - Opening gevuld: no; Identity Data - Mark: 86; Other(Type) - Category: Windows; Family Name: bt_raamsparing_variabel; Graphics(Type) - baz streepjes borstwering: no; baz streepjes kruis: yes; Identity Data(Type) - Type Mark: 31; Type Name: variabel - raam met borstwering; Analytical Properties(Type) - Analytic Construction: <None>; Define Thermal Properties by: Schematic Type
Basic Wall:bt_kzst 214:1572122 | V1 1e verd. (bk ruwe vloer) | 214 | 762 | 300 | Classification: (28.d) Uniformat (Uniformat); Pset_OpeningElementCommon - Reference: bt_kzst 214; sets with these values: 2; Other - Category: Walls: Rectangular Straight Wall Opening; Constraints - Top Constraint: Up to level: V2 ok vloer; Base Constraint: V1 1e verd. (bk ruwe vloer); Base Offset: 2778 mm; Top Offset: 0 mm; Unconnected Height: 762 mm; Phasing - Phase Created: 2. nieuwbouw
Basic Wall:bt_kzst 214:1572122 | V1 1e verd. (bk ruwe vloer) | 3048 | 2348 | 1760.09 | Classification: (28.d) Uniformat (Uniformat); Pset_OpeningElementCommon - Reference: variabel - raam met borstwering; sets with these values: 2; Other - Category: Windows; Family: bt_raamsparing_variabel; Family and Type: bt_raamsparing_variabel: variabel - raam met borstwering; Head Height: 2708 mm; Host Id: 1644937; Type: variabel - raam met borstwering; Type Id: 1140486; Phasing - Phase Created: 2. nieuwbouw; Analysis Results - oppervlakte: 4132698 mm2; oppervlakte in m2: 4.1327 mm; Constraints - Level: 03800 V1 1e verd; Sill Height: 360 mm; Dimensions - Area: 5011830 mm2; Height: 2348 mm; Sill Height (ter info): 1000 mm; Width: 1760.09 mm; Graphics - Opening gevuld: no; Identity Data - Mark: 75; Other(Type) - Category: Windows; Family Name: bt_raamsparing_variabel; Graphics(Type) - baz streepjes borstwering: no; baz streepjes kruis: yes; Identity Data(Type) - Type Mark: 31; Type Name: variabel - raam met borstwering; Analytical Properties(Type) - Analytic Construction: <None>; Define Thermal Properties by: Schematic Type
Basic Wall:bt_kzst 214:1607539 | V2 2e verd. (bk ruwe vloer) | 3048 | 2340 | 5700.3 | Classification: (28.d) Uniformat (Uniformat); Pset_OpeningElementCommon - Reference: variabel - raam met borstwering; sets with these values: 2; Other - Category: Windows; Family: bt_raamsparing_variabel; Family and Type: bt_raamsparing_variabel: variabel - raam met borstwering; Head Height: 2778 mm; Host Id: 1607535; Type: variabel - raam met borstwering; Type Id: 1140486; Phasing - Phase Created: 2. nieuwbouw; Analysis Results - oppervlakte: 13338706 mm2; oppervlakte in m2: 13.3387 mm; Constraints - Level: V2 2e verd. (bk ruwe vloer); Sill Height: 438 mm; Dimensions - Area: 15059331 mm2; Height: 2340 mm; Sill Height (ter info): 1000 mm; Width: 5700.3 mm; Graphics - Opening gevuld: no; Identity Data - Mark: 63; Other(Type) - Category: Windows; Family Name: bt_raamsparing_variabel; Graphics(Type) - baz streepjes borstwering: no; baz streepjes kruis: yes; Identity Data(Type) - Type Mark: 31; Type Name: variabel - raam met borstwering; Analytical Properties(Type) - Analytic Construction: <None>; Define Thermal Properties by: Schematic Type
Basic Wall:bt_kzst 214:1607545 | V2 2e verd. (bk ruwe vloer) | 214 | 494.059 | 214 | Classification: (28.d) Uniformat (Uniformat); Pset_OpeningElementCommon - Reference: bt_kzst 214; sets with these values: 2; Other - Category: Walls: Rectangular Straight Wall Opening; Constraints - Top Constraint: Up to level: V3 dakvloer; Base Constraint: V2 2e verd. (bk ruwe vloer); Base Offset: 2778 mm; Top Offset: -37.9409 mm; Unconnected Height: 494.059 mm; Phasing - Phase Created: 2. nieuwbouw
Basic Wall:bt_kzst 214:1607551 | V2 2e verd. (bk ruwe vloer) | 3048 | 2339.99 | 1200.28 | Classification: (28.d) Uniformat (Uniformat); Pset_OpeningElementCommon - Reference: variabel - raam met borstwering; sets with these values: 2; Other - Category: Windows; Family: bt_raamsparing_variabel; Family and Type: bt_raamsparing_variabel: variabel - raam met borstwering; Head Height: 2777.99 mm; Host Id: 1607549; Type: variabel - raam met borstwering; Type Id: 1140486; Phasing - Phase Created: 2. nieuwbouw; Analysis Results - oppervlakte: 2808657 mm2; oppervlakte in m2: 2.80866 mm; Constraints - Level: V2 2e verd. (bk ruwe vloer); Sill Height: 438 mm; Dimensions - Area: 3566276 mm2; Height: 2339.99 mm; Sill Height (ter info): 1000 mm; Width: 1200.28 mm; Graphics - Opening gevuld: no; Identity Data - Mark: 88; Other(Type) - Category: Windows; Family Name: bt_raamsparing_variabel; Graphics(Type) - baz streepjes borstwering: no; baz streepjes kruis: yes; Identity Data(Type) - Type Mark: 31; Type Name: variabel - raam met borstwering; Analytical Properties(Type) - Analytic Construction: <None>; Define Thermal Properties by: Schematic Type
Basic Wall:bt_kzst 214:355903 | V2 2e verd. (bk ruwe vloer) |  | 982.532 | 115 | Classification: (28.d) Uniformat (Uniformat); Pset_OpeningElementCommon - Reference: bt_kzst 214; sets with these values: 2; Other - Category: Lines: <Sketch>; Dimensions - Length: 982.532 mm
Basic Wall:bt_kzst 214:1626859 | F1 begg (bk ruwe vloer) | 214 | 762 | 300.967 | Classification: (28.d) Uniformat (Uniformat); Pset_OpeningElementCommon - Reference: bt_kzst 214; sets with these values: 2; Other - Category: Walls: Rectangular Straight Wall Opening; Constraints - Top Constraint: Up to level: V1 ok vloer; Base Constraint: F1 begg (bk ruwe vloer); Base Offset: 2778 mm; Top Offset: 0 mm; Unconnected Height: 762 mm; Phasing - Phase Created: 2. nieuwbouw
Basic Wall:bt_kzst 214:1627050 | F1 begg (bk ruwe vloer) | 214 | 1172 | 300 | Classification: (28.d) Uniformat (Uniformat); Pset_OpeningElementCommon - Reference: bt_kzst 214; sets with these values: 2; Other - Category: Walls: Rectangular Straight Wall Opening; Constraints - Top Constraint: Up to level: V1 ok vloer; Base Constraint: F2 (bk fundering); Base Offset: 3188 mm; Top Offset: 410 mm; Unconnected Height: 1172 mm; Phasing - Phase Created: 2. nieuwbouw
Basic Wall:bt_kzst 214:1628353 | F1 begg (bk ruwe vloer) | 214 | 1032 | 221.322 | Classification: (28.d) Uniformat (Uniformat); Pset_OpeningElementCommon - Reference: bt_kzst 214; sets with these values: 2; Other - Category: Walls: Rectangular Straight Wall Opening; Constraints - Top Constraint: Up to level: V1 ok vloer; Base Constraint: F2 (bk fundering); Base Offset: 3188 mm; Top Offset: 270 mm; Unconnected Height: 1032 mm; Phasing - Phase Created: 2. nieuwbouw
Basic Wall:bt_kzst 214:1646121 | V2 2e verd. (bk ruwe vloer) | 214 | 592.008 | 300 | Classification: (28.d) Uniformat (Uniformat); Pset_OpeningElementCommon - Reference: bt_kzst 214; sets with these values: 2; Other - Category: Walls: Rectangular Straight Wall Opening; Constraints - Base Constraint: V2 2e verd. (bk ruwe vloer); Base Offset: 2777.99 mm; Top Offset: 0 mm; Unconnected Height: 592.008 mm; Phasing - Phase Created: 2. nieuwbouw
Basic Wall:bt_kzst 214:1646121 | V2 2e verd. (bk ruwe vloer) | 3048 | 2348 | 1760.09 | Classification: (28.d) Uniformat (Uniformat); Pset_OpeningElementCommon - Reference: variabel - raam met borstwering; sets with these values: 2; Other - Category: Windows; Family: bt_raamsparing_variabel; Family and Type: bt_raamsparing_variabel: variabel - raam met borstwering; Head Height: 2778 mm; Host Id: 1935908; Type: variabel - raam met borstwering; Type Id: 1140486; Phasing - Phase Created: 2. nieuwbouw; Analysis Results - oppervlakte: 4132698 mm2; oppervlakte in m2: 4.1327 mm; Constraints - Level: V2 2e verd. (bk ruwe vloer); Sill Height: 430 mm; Dimensions - Area: 5011830 mm2; Height: 2348 mm; Sill Height (ter info): 1000 mm; Width: 1760.09 mm; Graphics - Opening gevuld: no; Identity Data - Mark: 76; Other(Type) - Category: Windows; Family Name: bt_raamsparing_variabel; Graphics(Type) - baz streepjes borstwering: no; baz streepjes kruis: yes; Identity Data(Type) - Type Mark: 31; Type Name: variabel - raam met borstwering; Analytical Properties(Type) - Analytic Construction: <None>; Define Thermal Properties by: Schematic Type
Floor:D2_ kanaalplaat d=150+druklaag=60-50-60:1666077 | V3 dakvloer | Classification: (23b.a) Uniformat (Uniformat); Pset_OpeningElementCommon - Reference: D2_ kanaalplaat d=150+druklaag=60-50-60; sets with these values: 2; Other - Category: Shaft Openings; Constraints - Top Constraint: Up to level: V3 dakvloer; Base Constraint: V3 dakvloer; Base Offset: -800 mm; Top Offset: 200 mm; Unconnected Height: 1000 mm; Phasing - Phase Created: 2. nieuwbouw; BaseQuantities - Area: 1131121 mm2
Floor:_ prefab betonplaat d=220 (bordes) 2:1806050 | V1 1e verd. (bk ruwe vloer) | 105 | 90 | 1482.54 | Classification: (23c.a) Uniformat (Uniformat); Pset_OpeningElementCommon - Reference: Generic Models 3; sets with these values: 2; Other - Category: Generic Models; Family: Generic Models 3; Family and Type: Generic Models 3: Generic Models 3; Type: Generic Models 3; Type Id: 1915702; Phasing - Phase Created: 2. nieuwbouw; Other(Type) - Category: Generic Models; Family Name: Generic Models 3; Identity Data(Type) - Type Name: Generic Models 3; Constraints - Moves With Nearby Elements: no
 | V2 2e verd. (bk ruwe vloer) | 260 | 1336.54 | 6012.34 | Classification: (23b.a) Uniformat (Uniformat); Pset_OpeningElementCommon - Reference: C1_ kanaalplaat d=200+druklaag=60-50-60; sets with these values: 2; BaseQuantities - Area: 0 mm2; Volume: 9028173 m3
Basic Wall:bt_kzst 214:1933353 | F1 begg (bk ruwe vloer) | 3048 | 2348 | 5700.33 | Classification: (28.d) Uniformat (Uniformat); Pset_OpeningElementCommon - Reference: variabel - raam met borstwering; sets with these values: 2; Other - Category: Windows; Family: bt_raamsparing_variabel; Family and Type: bt_raamsparing_variabel: variabel - raam met borstwering; Head Height: 2778 mm; Host Id: 2087783; Type: variabel - raam met borstwering; Type Id: 1140486; Phasing - Phase Created: 2. nieuwbouw; Analysis Results - oppervlakte: 13384365 mm2; oppervlakte in m2: 13.3844 mm; Constraints - Level: F1 begg (bk ruwe vloer); Sill Height: 430 mm; Dimensions - Area: 15106707 mm2; Height: 2348 mm; Sill Height (ter info): 1000 mm; Width: 5700.33 mm; Graphics - Opening gevuld: no; Identity Data - Mark: 70; Other(Type) - Category: Windows; Family Name: bt_raamsparing_variabel; Graphics(Type) - baz streepjes borstwering: no; baz streepjes kruis: yes; Identity Data(Type) - Type Mark: 31; Type Name: variabel - raam met borstwering; Analytical Properties(Type) - Analytic Construction: <None>; Define Thermal Properties by: Schematic Type
Basic Wall:bt_kzst 214:1933665 | F1 begg (bk ruwe vloer) | 3048 | 2348 | 5700.33 | Classification: (28.d) Uniformat (Uniformat); Pset_OpeningElementCommon - Reference: variabel - raam met borstwering; sets with these values: 2; Other - Category: Windows; Family: bt_raamsparing_variabel; Family and Type: bt_raamsparing_variabel: variabel - raam met borstwering; Head Height: 2778 mm; Host Id: 2087813; Type: variabel - raam met borstwering; Type Id: 1140486; Phasing - Phase Created: 2. nieuwbouw; Analysis Results - oppervlakte: 13384365 mm2; oppervlakte in m2: 13.3844 mm; Constraints - Level: F1 begg (bk ruwe vloer); Sill Height: 430 mm; Dimensions - Area: 15106707 mm2; Height: 2348 mm; Sill Height (ter info): 1000 mm; Width: 5700.33 mm; Graphics - Opening gevuld: no; Identity Data - Mark: 71; Other(Type) - Category: Windows; Family Name: bt_raamsparing_variabel; Graphics(Type) - baz streepjes borstwering: no; baz streepjes kruis: yes; Identity Data(Type) - Type Mark: 31; Type Name: variabel - raam met borstwering; Analytical Properties(Type) - Analytic Construction: <None>; Define Thermal Properties by: Schematic Type
Basic Wall:bt_kzst 214:1935647 | KDV V1 1e verd. (bk ruwe vloer) | 3048 | 2348 | 1760.09 | Classification: (28.d) Uniformat (Uniformat); Pset_OpeningElementCommon - Reference: variabel - raam met borstwering; sets with these values: 2; Other - Category: Windows; Family: bt_raamsparing_variabel; Family and Type: bt_raamsparing_variabel: variabel - raam met borstwering; Head Height: 2708 mm; Host Id: 1644937; Type: variabel - raam met borstwering; Type Id: 1140486; Phasing - Phase Created: 2. nieuwbouw; Analysis Results - oppervlakte: 4132698 mm2; oppervlakte in m2: 4.1327 mm; Constraints - Level: 03800 V1 1e verd; Sill Height: 360 mm; Dimensions - Area: 5011830 mm2; Height: 2348 mm; Sill Height (ter info): 1000 mm; Width: 1760.09 mm; Graphics - Opening gevuld: no; Identity Data - Mark: 75; Other(Type) - Category: Windows; Family Name: bt_raamsparing_variabel; Graphics(Type) - baz streepjes borstwering: no; baz streepjes kruis: yes; Identity Data(Type) - Type Mark: 31; Type Name: variabel - raam met borstwering; Analytical Properties(Type) - Analytic Construction: <None>; Define Thermal Properties by: Schematic Type
Floor:PBO prefab betonplaat d=200 (bordes):1961816 | V2 2e verd. (bk ruwe vloer) | 105 | 90 | 1482.54 | Classification: (23c.a) Uniformat (Uniformat); Pset_OpeningElementCommon - Reference: Generic Models 3; sets with these values: 2; Other - Category: Generic Models; Family: Generic Models 7; Family and Type: Generic Models 7: Generic Models 3; Type: Generic Models 3; Type Id: 1961837; Phasing - Phase Created: 2. nieuwbouw; Other(Type) - Category: Generic Models; Family Name: Generic Models 7; Identity Data(Type) - Type Name: Generic Models 3; Constraints - Moves With Nearby Elements: no
 | V2 2e verd. (bk ruwe vloer) | 260 | Classification: (23b.a) Uniformat (Uniformat); Pset_OpeningElementCommon - Reference: C1_ kanaalplaat d=200+druklaag=60-50-60; sets with these values: 2; BaseQuantities - Area: 26678890 mm2; Volume: 2833784 m3
Basic Wall:bt_kzst 214:2087787 | F1 begg (bk ruwe vloer) | 3048 | 2348 | 5700.33 | Classification: (28.d) Uniformat (Uniformat); Pset_OpeningElementCommon - Reference: variabel - raam met borstwering; sets with these values: 2; Other - Category: Windows; Family: bt_raamsparing_variabel; Family and Type: bt_raamsparing_variabel: variabel - raam met borstwering; Head Height: 2778 mm; Host Id: 2087783; Type: variabel - raam met borstwering; Type Id: 1140486; Phasing - Phase Created: 2. nieuwbouw; Analysis Results - oppervlakte: 13384365 mm2; oppervlakte in m2: 13.3844 mm; Constraints - Level: F1 begg (bk ruwe vloer); Sill Height: 430 mm; Dimensions - Area: 15106707 mm2; Height: 2348 mm; Sill Height (ter info): 1000 mm; Width: 5700.33 mm; Graphics - Opening gevuld: no; Identity Data - Mark: 70; Other(Type) - Category: Windows; Family Name: bt_raamsparing_variabel; Graphics(Type) - baz streepjes borstwering: no; baz streepjes kruis: yes; Identity Data(Type) - Type Mark: 31; Type Name: variabel - raam met borstwering; Analytical Properties(Type) - Analytic Construction: <None>; Define Thermal Properties by: Schematic Type
Basic Wall:bt_kzst 214:2087904 | F1 begg (bk ruwe vloer) | 3048 | 2348 | 5700.33 | Classification: (28.d) Uniformat (Uniformat); Pset_OpeningElementCommon - Reference: variabel - raam met borstwering; sets with these values: 2; Other - Category: Windows; Family: bt_raamsparing_variabel; Family and Type: bt_raamsparing_variabel: variabel - raam met borstwering; Head Height: 2778 mm; Host Id: 2087813; Type: variabel - raam met borstwering; Type Id: 1140486; Phasing - Phase Created: 2. nieuwbouw; Analysis Results - oppervlakte: 13384365 mm2; oppervlakte in m2: 13.3844 mm; Constraints - Level: F1 begg (bk ruwe vloer); Sill Height: 430 mm; Dimensions - Area: 15106707 mm2; Height: 2348 mm; Sill Height (ter info): 1000 mm; Width: 5700.33 mm; Graphics - Opening gevuld: no; Identity Data - Mark: 71; Other(Type) - Category: Windows; Family Name: bt_raamsparing_variabel; Graphics(Type) - baz streepjes borstwering: no; baz streepjes kruis: yes; Identity Data(Type) - Type Mark: 31; Type Name: variabel - raam met borstwering; Analytical Properties(Type) - Analytic Construction: <None>; Define Thermal Properties by: Schematic Type
3 x Basic Wall:bt_kzst 214:1543078 | F1 begg (bk ruwe vloer) | 3048 | 2340 | 1200.28
4 x Basic Wall:bt_kzst 214:1571026 | V1 1e verd. (bk ruwe vloer) | 3048 | 2340 | 5700.3
Basic Wall:bt_kzst 214:1571484 | V1 1e verd. (bk ruwe vloer) | 800 | 2450 | 1034.15
Basic Wall:bt_kzst 214:1571538 | V1 1e verd. (bk ruwe vloer) | 3048 | 1400 | 1200.15
Basic Wall:bt_kzst 214:1571650 | V1 1e verd. (bk ruwe vloer) | 3048 | 1400 | 1199.98
3 x Basic Wall:bt_kzst 214:1571698 | V1 1e verd. (bk ruwe vloer) | 3048 | 2340 | 1200.28
4 x Basic Wall:bt_kzst 214:1607535 | V2 2e verd. (bk ruwe vloer) | 3048 | 2340 | 5700.3
Basic Wall:bt_kzst 214:1607543 | V2 2e verd. (bk ruwe vloer) | 3048 | 1400 | 1200.15
Basic Wall:bt_kzst 214:1607545 | V2 2e verd. (bk ruwe vloer) | 3048 | 1400 | 1200.15
3 x Basic Wall:bt_kzst 214:1607549 | V2 2e verd. (bk ruwe vloer) | 3048 | 2339.99 | 1200.28
Basic Wall:bt_kzst 214:1607553 | V2 2e verd. (bk ruwe vloer) | 3048 | 1400 | 1399.6
Basic Wall:bt_kzst 214:1607679 | V2 2e verd. (bk ruwe vloer) | 3048 | 1400 | 1399.6
Basic Wall:bt_kzst 214:1643487 | V1 1e verd. (bk ruwe vloer) | 800 | 2450 | 1034.06
Basic Wall:bt_kzst 214:1643882 | V1 1e verd. (bk ruwe vloer) | 3048 | 2658 | 1760.09
Basic Wall:bt_kzst 214:1811112 | F1 begg (bk ruwe vloer) | 3048 | 1400 | 1200.06
Basic Wall:bt_kzst 214:1811425 | F1 begg (bk ruwe vloer) | 3048 | 1400 | 1200.06
4 x Basic Wall:bt_kzst 214:1911856 | F1 begg (bk ruwe vloer) | 3048 | 2295 | 5700.3
Basic Wall:bt_kzst 214:1932186 | F1 begg (bk ruwe vloer) | 3048 | 2348 | 5700.3
Basic Wall:bt_kzst 214:1932186 | F1 begg (bk ruwe vloer) | 3048 | 2348 | 3955.21
Basic Wall:bt_kzst 214:1932186 | F1 begg (bk ruwe vloer) | 800 | 2778 | 1741.09
Basic Wall:bt_kzst 214:1933958 | F1 begg (bk ruwe vloer) | 3048 | 2348 | 5700.3
Basic Wall:bt_kzst 214:1934225 | F1 begg (bk ruwe vloer) | 3048 | 2348 | 5700.3
Basic Wall:bt_kzst 214:1935908 | KDV V2 werkbalken | 3048 | 2348 | 1760.09
Basic Wall:bt_kzst 214:1963433 | KDV V1 1e verd. (bk ruwe vloer) | 3048 | 3110 | 5289.65
Basic Wall:bt_kzst 214:1963584 | KDV V2 werkbalken | 3048 | 2547.99 | 5150.25
Basic Wall:bt_kzst 214:1963794 | KDV V1 1e verd. (bk ruwe vloer) | 3048 | 3110 | 5150.25
Basic Wall:bt_kzst 214:1963797 | KDV V2 werkbalken | 3048 | 2977.99 | 5150.25
Basic Wall:bt_kzst 300:2050667 | V1 1e verd. (bk ruwe vloer) | 800 | 2450 | 1834.1
Basic Wall:bt_kzst 214:2087742 | V1 1e verd. (bk ruwe vloer) | 3048 | 2615 | 1760.09
Basic Wall:bt_kzst 214:2087783 | F1 begg (bk ruwe vloer) | 3048 | 2348 | 5700.33
Basic Wall:bt_kzst 214:2087813 | F1 begg (bk ruwe vloer) | 3048 | 2348 | 5700.33

# IfcRoof: Basic Roof:bt_kapconstructie d=467 (2)
Type - Other - Category: Roofs; Family Name: Basic Roof
Type - Construction - Default Thickness: 270 mm
Type - Graphics - Coarse Scale Fill Pattern: <Solid fill>; Coarse Scale Fill Color: 5153993
Type - Identity Data - Type Name: bt_kapconstructie d=467
Type - Analytical Properties - Roughness: 1; Absorptance: 0.1
Material: Wood - DAK plaatmateriaal buitenzijde 20 mm, Wood - DAK kern 180 mm, Wood - DAK plaatmateriaal binnenzijde 70 mm
Pset_QuantityTakeOff - Reference: bt_kapconstructie d=467
Pset_RoofCommon - IsExternal: yes; Reference: bt_kapconstructie d=467
Other - Family: Basic Roof; Family and Type: Basic Roof: bt_kapconstructie d=467; Type: bt_kapconstructie d=467; Type Id: 1652131
Constraints - Related to Mass: no; Room Bounding: yes
Construction - Fascia Depth: 0 mm; Rafter Cut: Plumb Cut
Dimensions - Thickness: 270 mm
Phasing - Phase Created: 2. nieuwbouw
Name (Basic Roof:bt_kapconstructie d=467:...) | In | ProjectedArea (mm2) | TotalArea (mm2) = NetArea (mm2) = Area (mm2) | Extrusion End (mm) | Extrusion Start (mm) | Level Offset (mm) | Reference Level | Work Plane | Volume (m3)
1652128 | KDV V1 1e verd. (bk ruwe vloer) | 12812763 | 13590839 | -2070.82 | -214 | 0 | V1 ok vloer | Grid : 1 | 3.66774
1659249 | V4 BK metselwerk | 12649931 | 13426112 | -1857 | -214.12 | -200 | V4 BK metselwerk | Grid : H | 3.62346

# IfcSlab: Floor:A1_ geisoleerd kanaalplaat d=200+ druklaag 60-50-60 (15)
In: F1 begg (bk ruwe vloer)
Type - PredefinedType: FLOOR; Material: Druklaag, C20/25 op systeemvloer 60 mm, Beton, prefab - kanaalplaat 200 mm, Isolatie, onder vloer 150 mm
Type - Other - Category: Floors; Family Name: Floor
Type - Construction - Default Thickness: 410 mm; Function: Interior
Type - Graphics - Coarse Scale Fill Color: 12632256; Coarse Scale Fill Pattern: <Solid fill>
Type - Identity Data - Assembly Code: (23b.a); Description: geisoleerde kanaalplaat d=200; Model: kanaalplaat vloer; t. Dikte afwerking: evt isol. + zc: 70 mm; t. Dikte druklaag:: -; t. Dikte isolatie ondervloer:: 150; t. Peil - afgewerktevloer:: P =0; t. Peil - b.k. ruwevloer:: P -70; t. Veranderlijke Belasting in kN/m2:: 5,00 kN/m²; Type Mark: A1; Type Name: A1_ geisoleerd kanaalplaat d=200+ druklaag 60-50-60
Type - Text - BasisDikte: 0 mm; Totale opleghoogte: 0 mm
Type - Analytical Properties - Absorptance: 0.1; Roughness: 1
Type - Pset_ReinforcementBarPitchOfSlab - Description: geisoleerde kanaalplaat d=200
Type - Pset_SlabCommon - IsExternal: no
Classification: (23b.a) Uniformat (Uniformat)
Pset_QuantityTakeOff - Reference: A1_ geisoleerd kanaalplaat d=200+ druklaag 60-50-60; sets with these values: 2
Pset_SlabCommon - LoadBearing: yes; Reference: A1_ geisoleerd kanaalplaat d=200+ druklaag 60-50-60; PitchAngle: 0 deg
Other - Family: Floor; Family and Type: Floor: A1_ geisoleerd kanaalplaat d=200+ druklaag 60-50-60; Type: A1_ geisoleerd kanaalplaat d=200+ druklaag 60-50-60; Type Id: 1540126
Constraints - Height Offset From Level: 0 mm; Level: F1 begg (bk ruwe vloer); Related to Mass: no; Room Bounding: yes
Dimensions - Core Thickness: 410 mm; Elevation at Bottom: -480 mm; Elevation at Bottom Core: -480 mm; Elevation at Bottom Survey: -480 mm; Elevation at Top: -70 mm; Elevation at Top Core: -70 mm; Elevation at Top Survey: -70 mm; Thickness: 410 mm
Identity Data - Has Association: yes
Phasing - Phase Created: 2. nieuwbouw
Structural - Rebar Cover - Bottom Face: Rebar Cover 1 <25 mm>; Rebar Cover - Other Faces: Rebar Cover 1 <25 mm>; Rebar Cover - Top Face: Rebar Cover 1 <25 mm>; Structural: yes
Name (Floor:A1_ geisoleerd kanaalplaat d=200+ druklaag 60-50-60:...) | Width (mm) | BaseQuantities, Perimeter (mm) | GrossArea (mm2) = NetArea (mm2) = Area (mm2) | GrossVolume (m3) = NetVolume (m3) = Volume (m3) | Dimensions, Perimeter (mm)
1539055 | 8689.84 | 99.999 | 56918458 | 23.3366 | 30479.7
1540046 | 4013.51 | 69.3144 | 26288517 | 10.7783 | 21127
1540482 | 8996.63 | 102.012 | 58927929 | 24.1605 | 31093.3
1540601 | 22300 | 194.39 | 163347496 | 66.9725 | 59250
1541128 |  | 184.009 | 136527495 | 55.9763 | 56085.9
1541433 |  | 215.597 | 147977461 | 60.6708 | 65714
1541765 |  | 55.4461 | 16048347 | 6.57982 | 16900
1541935 |  | 55.0615 | 15877063 | 6.5096 | 16782.7
1542088 | 6600 | 78.4121 | 35310000 | 14.4771 | 23900
1542217 | 6600 | 78.4121 | 35310000 | 14.4771 | 23900
1542304 | 6600 | 78.4121 | 35310000 | 14.4771 | 23900
1542332 | 6675 | 78.9042 | 35711252 | 14.6416 | 24050
1611150 |  | 197.014 | 167790698 | 68.7942 | 60049.9 | Identity Data - Comments: + druklaag 60-50-60
1999444 | 3700.26 | 43.3087 | 10730691 | 4.39958 | 13200.5
1999622 | 4362.87 | 47.6565 | 12652251 | 5.18742 | 14525.7

# IfcSlab: Floor:A2_kanaalplaat d=200, Floor:A2_kanaalplaat d=200:1625059
In: F1 begg (bk ruwe vloer)
Type - PredefinedType: FLOOR; Material: Beton, prefab - kanaalplaat 200 mm
Type - Other - Category: Floors; Family Name: Floor
Type - Construction - Function: Interior; Default Thickness: 200 mm
Type - Graphics - Coarse Scale Fill Pattern: <Solid fill>; Coarse Scale Fill Color: 12632256
Type - Identity Data - Assembly Code: (23b.a); Description: kanaalplaat d=200; Model: kanaalplaat vloer; t. Dikte afwerking: evt isol. + zc: 70 mm; t. Dikte druklaag:: -; t. Dikte isolatie ondervloer:: 150; t. Peil - afgewerktevloer:: P -350; t. Peil - b.k. ruwevloer:: P -420; t. Veranderlijke Belasting in kN/m2:: 3 kN/m²; Type Mark: A2; Type Name: A2_kanaalplaat d=200
Type - Text - BasisDikte: 0 mm; Totale opleghoogte: 0 mm
Type - Analytical Properties - Roughness: 1; Absorptance: 0.1
Type - Pset_ReinforcementBarPitchOfSlab - Description: kanaalplaat d=200
Type - Pset_SlabCommon - IsExternal: no
Classification: (23b.a) Uniformat (Uniformat)
Pset_QuantityTakeOff - Reference: A2_kanaalplaat d=200; sets with these values: 2
Pset_SlabCommon - LoadBearing: yes; PitchAngle: 0 deg; Reference: A2_kanaalplaat d=200
BaseQuantities - Width: 7195 mm; Perimeter: 55.0853 mm; GrossArea: 8634000 mm2; NetArea: 8634000 mm2; GrossVolume: 1.7268 m3; NetVolume: 1.7268 m3
Other - Family: Floor; Family and Type: Floor: A2_kanaalplaat d=200; Type: A2_kanaalplaat d=200; Type Id: 1881200
Constraints - Level: F1 begg (bk ruwe vloer); Related to Mass: no; Room Bounding: yes; Height Offset From Level: -350 mm
Dimensions - Area: 8634000 mm2; Core Thickness: 200 mm; Elevation at Bottom: -620 mm; Elevation at Bottom Core: -620 mm; Elevation at Bottom Survey: -620 mm; Elevation at Top: -420 mm; Elevation at Top Core: -420 mm; Elevation at Top Survey: -420 mm; Perimeter: 16790 mm; Thickness: 200 mm; Volume: 1.7268 m3
Identity Data - Has Association: yes
Phasing - Phase Created: 2. nieuwbouw
Structural - Rebar Cover - Bottom Face: Rebar Cover 1 <25 mm>; Rebar Cover - Other Faces: Rebar Cover 1 <25 mm>; Rebar Cover - Top Face: Rebar Cover 1 <25 mm>; Structural: yes

# IfcSlab: Floor:A3_ ihwg betonvloer d=200 (2)
In: F1 begg (bk ruwe vloer)
Type - PredefinedType: FLOOR; Material: Concrete - Cast-in-Place - C20/25 200 mm
Type - Other - Category: Floors; Family Name: Floor
Type - Construction - Function: Interior; Default Thickness: 200 mm
Type - Graphics - Coarse Scale Fill Pattern: <Solid fill>; Coarse Scale Fill Color: 12632256
Type - Identity Data - Assembly Code: (23b.a); Description: ihwg betonvloer d=200; Model: ihwg betonvloer; t. Dikte afwerking: evt isol. + zc: Buitenafwerking; t. Dikte druklaag:: -; t. Peil - afgewerktevloer:: var.; t. Peil - b.k. ruwevloer:: P -420; t. Veranderlijke Belasting in kN/m2:: 5,00 kN/m²; Type Mark: A3; Type Name: A3_ ihwg betonvloer d=200
Type - Materials and Finishes - Structural Material: Concrete - Cast-in-Place - C20/25
Type - Text - BasisDikte: 0 mm; Totale opleghoogte: 0 mm
Type - Analytical Properties - Roughness: 1; Absorptance: 0.1
Type - Pset_ReinforcementBarPitchOfSlab - Description: ihwg betonvloer d=200
Type - Pset_SlabCommon - IsExternal: no
Classification: (23b.a) Uniformat (Uniformat)
Pset_QuantityTakeOff - Reference: A3_ ihwg betonvloer d=200; sets with these values: 2
Pset_SlabCommon - LoadBearing: yes; PitchAngle: 0 deg; Reference: A3_ ihwg betonvloer d=200
Other - Family: Floor; Family and Type: Floor: A3_ ihwg betonvloer d=200; Type: A3_ ihwg betonvloer d=200; Type Id: 2095683
Constraints - Height Offset From Level: 0 mm; Related to Mass: no; Room Bounding: yes; Level: F2 (bk fundering)
Dimensions - Core Thickness: 200 mm; Elevation at Bottom: -680 mm; Elevation at Bottom Core: -680 mm; Elevation at Bottom Survey: -680 mm; Elevation at Top: -480 mm; Elevation at Top Core: -480 mm; Elevation at Top Survey: -480 mm; Thickness: 200 mm
Identity Data - Has Association: no
Phasing - Phase Created: 2. nieuwbouw
Structural - Rebar Cover - Bottom Face: Rebar Cover 1 <25 mm>; Rebar Cover - Other Faces: Rebar Cover 1 <25 mm>; Rebar Cover - Top Face: Rebar Cover 1 <25 mm>; Structural: yes
Name (Floor:A3_ ihwg betonvloer d=200:...) | BaseQuantities, Perimeter (mm) | GrossArea (mm2) = NetArea (mm2) = Area (mm2) | GrossVolume (m3) = NetVolume (m3) = Volume (m3) | Dimensions, Perimeter (mm)
2095678 | 86.6798 | 25591281 | 5.11826 | 26420
2099616 | 120.23 | 48732991 | 9.7466 | 36646

# IfcSlab: Floor:B1_ kanaalplaat d=200+druklaag=60-50-60 (13)
In: V1 1e verd. (bk ruwe vloer)
Type - PredefinedType: FLOOR; Material: Druklaag, C20/25 op systeemvloer 60 mm, Beton, prefab - kanaalplaat 200 mm
Type - Other - Category: Floors; Family Name: Floor
Type - Construction - Function: Interior; Default Thickness: 260 mm
Type - Graphics - Coarse Scale Fill Pattern: <Solid fill>; Coarse Scale Fill Color: 12632256
Type - Identity Data - Assembly Code: (23b.a); Description: kanaalplaatvloer d=200+drukl.60-50-60; Model: kanaalplaat vloer; t. Dikte afwerking: evt isol. + zc: 70 mm; t. Dikte druklaag:: 60-50-60 (gewapend); t. Peil - afgewerktevloer:: P +3800; t. Peil - b.k. druklaag:: P -60; t. Peil - b.k. ruwevloer:: P +3730; t. Veranderlijke Belasting in kN/m2:: 4 kN/m²; Type Comments: Wapening druklaag #Ø6-100; Type Mark: B1; Type Name: B1_ kanaalplaat d=200+druklaag=60-50-60
Type - Materials and Finishes - Structural Material: Druklaag, C20/25 op systeemvloer
Type - Text - BasisDikte: 0 mm; Totale opleghoogte: 0 mm
Type - Analytical Properties - Roughness: 1; Absorptance: 0.1
Type - Pset_ReinforcementBarPitchOfSlab - Description: kanaalplaatvloer d=200+drukl.60-50-60
Type - Pset_SlabCommon - IsExternal: no
Classification: (23b.a) Uniformat (Uniformat)
Pset_QuantityTakeOff - Reference: B1_ kanaalplaat d=200+druklaag=60-50-60; sets with these values: 2
Pset_SlabCommon - LoadBearing: yes; PitchAngle: 0 deg; Reference: B1_ kanaalplaat d=200+druklaag=60-50-60
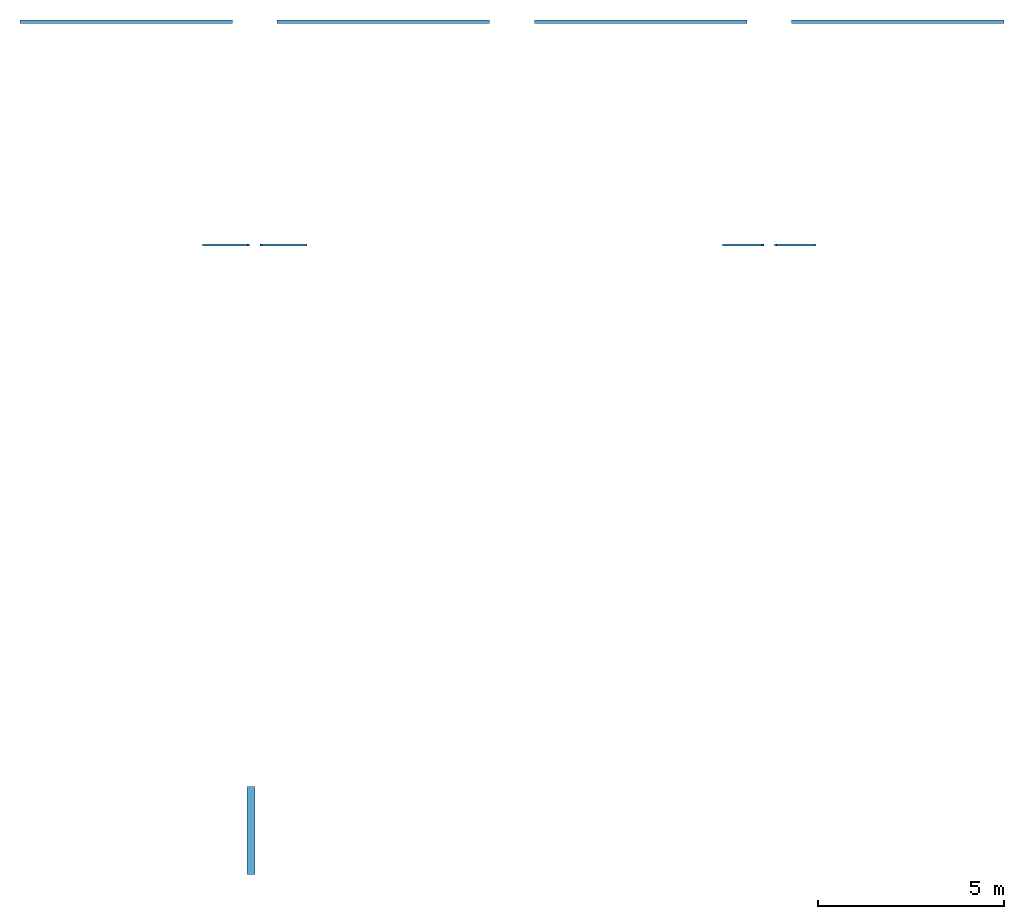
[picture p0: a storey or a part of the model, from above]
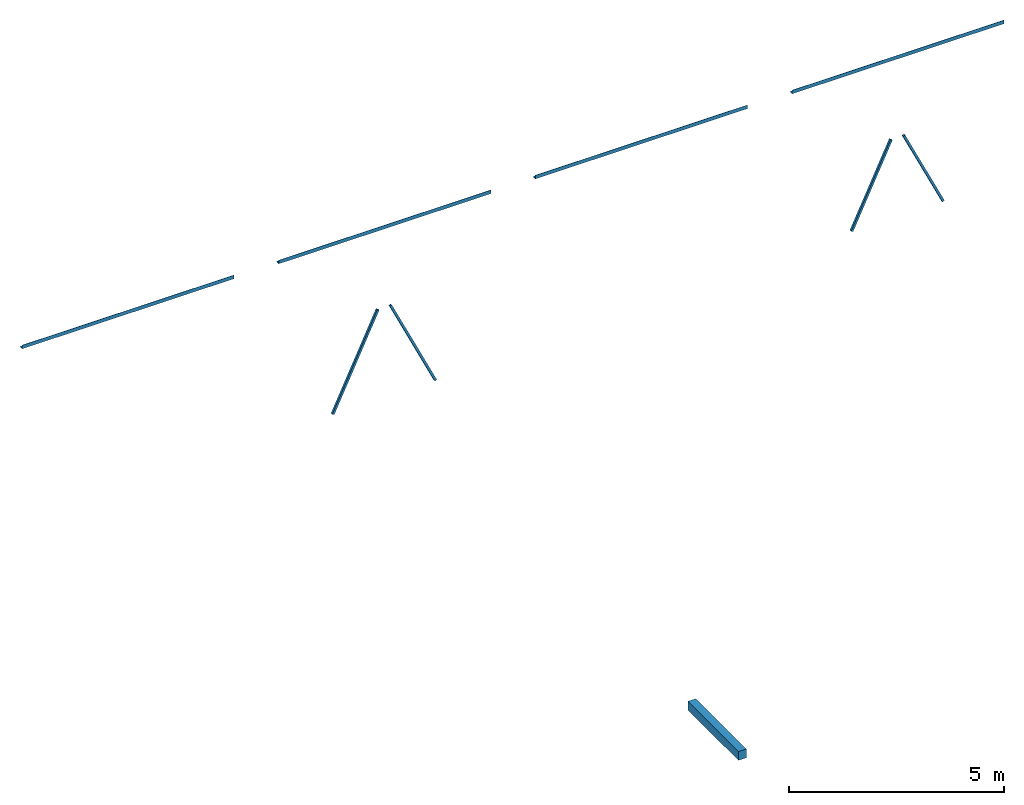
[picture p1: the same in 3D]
Properties of the parts of a building model (IFC2X3), part 6 of 6

# IfcSlab: Floor:B1_ kanaalplaat d=200+druklaag=60-50-60 (13)
Other - Family: Floor; Family and Type: Floor: B1_ kanaalplaat d=200+druklaag=60-50-60; Type: B1_ kanaalplaat d=200+druklaag=60-50-60; Type Id: 598564
Constraints - Height Offset From Level: 0 mm; Related to Mass: no; Room Bounding: yes; Level: V1 1e verd. (bk ruwe vloer)
Dimensions - Core Thickness: 260 mm; Elevation at Bottom: 3470 mm; Elevation at Bottom Core: 3470 mm; Elevation at Bottom Survey: 3470 mm; Elevation at Top: 3730 mm; Elevation at Top Core: 3730 mm; Elevation at Top Survey: 3730 mm; Thickness: 260 mm
Phasing - Phase Created: 2. nieuwbouw
Structural - Rebar Cover - Bottom Face: Rebar Cover 1 <25 mm>; Rebar Cover - Other Faces: Rebar Cover 1 <25 mm>; Rebar Cover - Top Face: Rebar Cover 1 <25 mm>; Structural: yes
Name (Floor:B1_ kanaalplaat d=200+druklaag=60-50-60:...) | BaseQuantities, Perimeter (mm) | GrossArea (mm2) | NetArea (mm2) = Area (mm2) | GrossVolume (m3) | NetVolume (m3) = Volume (m3) | Dimensions, Perimeter (mm) | Has Association
1555713 | 157.891 | 124051960 | 124051960 | 32.2535 | 32.2535 | 48125.3 | yes
1559567 | 92.7949 | 48692761 | 48692761 | 12.6601 | 12.6601 | 28283.9 | yes
1563221 | 219.245 | 152451859 | 152451859 | 39.6375 | 39.6375 | 66826 | yes
1566292 | 218.589 | 154617072 | 154617072 | 40.2004 | 40.2004 | 66626 | yes | BaseQuantities - Width: 27739 mm
1620302 | 44.1798 | 11142374 | 11142374 | 2.89702 | 2.89702 | 13466 | yes
1621773 | 33.2694 | 5780660 | 5780660 | 1.50297 | 1.50297 | 10140.5 | yes | BaseQuantities - Width: 3339 mm
1621927 | 60.976 |  | 10394030 |  | 2.70245 | 18585.5 | yes
1693152 | 71.182 | 20859460 | 20859460 | 5.42346 | 5.42346 | 21696.3 | yes | BaseQuantities - Width: 8349.99 mm
1693283 | 79.6717 | 36100103 | 36100103 | 9.38603 | 9.38603 | 24283.9 | yes
1694024 | 96.9429 | 4553492 | 4553492 | 1.18391 | 1.18391 | 29548.2 | no
1810117 | 64.2716 | 20594341 | 20594341 | 5.35453 | 5.35453 | 19590 | yes | BaseQuantities - Width: 3056 mm
1878042 | 24.6642 | 3367206 | 3367206 | 0.875473 | 0.875473 | 7517.66 | yes | BaseQuantities - Width: 2271.39 mm
1890476 | 66.9558 | 24900576 | 24900576 | 6.47415 | 6.47415 | 20408.1 | yes | BaseQuantities - Width: 6165.13 mm

# IfcSlab: Floor:B2_ bekistingsplaatvloer d=300, schil=60 (2)
In: V1 1e verd. (bk ruwe vloer)
Type - PredefinedType: FLOOR; Material: Druklaag, C20/25 op systeemvloer 120 mm, Isolatie, op vloer 100 mm, Druklaag, C20/25 op bekistingsplaat 240 mm, Beton, prefab - bekistingsplaat schil 60 mm
Type - Other - Category: Floors; Family Name: Floor
Type - Construction - Function: Interior; Default Thickness: 520 mm
Type - Graphics - Coarse Scale Fill Pattern: <Solid fill>; Coarse Scale Fill Color: 12632256
Type - Identity Data - Assembly Code: (23b.a); Description: bekistingsplaat d=300 +iso=100+betonlaag=120; Model: bekistingsplaat vloer; t. Dikte afwerking: evt isol. + zc: -; t. Dikte druklaag:: -; t. Peil - afgewerktevloer:: P +3800; t. Peil - b.k. ruwevloer:: P +3800; t. Veranderlijke Belasting in kN/m2:: 5,00 kN/m²; Type Comments: Gymzaal. Wapening 60kg/m³ excl. knipverlies, las- en verankeringslengte; Type Mark: B2; Type Name: B2_ bekistingsplaatvloer d=300, schil=60
Type - Materials and Finishes - Structural Material: Druklaag, C20/25 op bekistingsplaat
Type - Text - BasisDikte: 0 mm; Totale opleghoogte: 0 mm
Type - Analytical Properties - Roughness: 1; Absorptance: 0.1
Type - Pset_ReinforcementBarPitchOfSlab - Description: bekistingsplaat d=300 +iso=100+betonlaag=120
Type - Pset_SlabCommon - IsExternal: no
Classification: (23b.a) Uniformat (Uniformat)
Pset_QuantityTakeOff - Reference: B2_ bekistingsplaatvloer d=300, schil=60; sets with these values: 2
Pset_SlabCommon - LoadBearing: yes; PitchAngle: 0 deg; Reference: B2_ bekistingsplaatvloer d=300, schil=60
Other - Family: Floor; Family and Type: Floor: B2_ bekistingsplaatvloer d=300, schil=60; Type: B2_ bekistingsplaatvloer d=300, schil=60; Type Id: 1554523
Constraints - Related to Mass: no; Room Bounding: yes; Height Offset From Level: 70 mm; Level: V1 1e verd. (bk ruwe vloer)
Dimensions - Core Thickness: 520 mm; Elevation at Bottom: 3280 mm; Elevation at Bottom Core: 3280 mm; Elevation at Bottom Survey: 3280 mm; Elevation at Top: 3800 mm; Elevation at Top Core: 3800 mm; Elevation at Top Survey: 3800 mm; Thickness: 520 mm
Identity Data - Has Association: yes
Phasing - Phase Created: 2. nieuwbouw
Structural - Rebar Cover - Bottom Face: Rebar Cover 1 <25 mm>; Rebar Cover - Other Faces: Rebar Cover 1 <25 mm>; Rebar Cover - Top Face: Rebar Cover 1 <25 mm>; Structural: yes
Name (Floor:B2_ bekistingsplaatvloer d=300, schil=60:...) | BaseQuantities, Perimeter (mm) | GrossArea (mm2) = NetArea (mm2) = Area (mm2) | GrossVolume (m3) = NetVolume (m3) = Volume (m3) | Dimensions, Perimeter (mm)
1554519 | 200.315 | 171323010 | 89.088 | 61056
1554896 | 194.501 | 157141339 | 81.7135 | 59284 | BaseQuantities - Width: 22728 mm

# IfcSlab: Floor:C1_ kanaalplaat d=200+druklaag=60-50-60 (12)
In: V2 2e verd. (bk ruwe vloer)
Type - PredefinedType: FLOOR; Material: Druklaag, C20/25 op systeemvloer 60 mm, Beton, prefab - kanaalplaat 200 mm
Type - Other - Category: Floors; Family Name: Floor
Type - Construction - Function: Interior; Default Thickness: 260 mm
Type - Graphics - Coarse Scale Fill Pattern: <Solid fill>; Coarse Scale Fill Color: 12632256
Type - Identity Data - Assembly Code: (23b.a); Description: kanaalplaatvloer d=200+drukl.60-50-60; Model: kanaalplaat vloer; t. Dikte afwerking: evt isol. + zc: 70 mm; t. Dikte druklaag:: 60-50-60 (gewapend); t. Peil - afgewerktevloer:: P +7800; t. Peil - b.k. druklaag:: P -60; t. Peil - b.k. ruwevloer:: P +6730; t. Veranderlijke Belasting in kN/m2:: 4 kN/m²; Type Comments: Wapening druklaag #Ø6-100; Type Mark: C1; Type Name: C1_ kanaalplaat d=200+druklaag=60-50-60
Type - Materials and Finishes - Structural Material: Druklaag, C20/25 op systeemvloer
Type - Text - BasisDikte: 0 mm; Totale opleghoogte: 0 mm
Type - Analytical Properties - Roughness: 1; Absorptance: 0.1
Type - Pset_ReinforcementBarPitchOfSlab - Description: kanaalplaatvloer d=200+drukl.60-50-60
Type - Pset_SlabCommon - IsExternal: no
Classification: (23b.a) Uniformat (Uniformat)
Pset_QuantityTakeOff - Reference: C1_ kanaalplaat d=200+druklaag=60-50-60; sets with these values: 2
Pset_SlabCommon - LoadBearing: yes; PitchAngle: 0 deg; Reference: C1_ kanaalplaat d=200+druklaag=60-50-60
Other - Family: Floor; Family and Type: Floor: C1_ kanaalplaat d=200+druklaag=60-50-60; Type: C1_ kanaalplaat d=200+druklaag=60-50-60; Type Id: 1664429
Constraints - Height Offset From Level: 0 mm; Related to Mass: no; Room Bounding: yes; Level: V2 2e verd. (bk ruwe vloer)
Dimensions - Core Thickness: 260 mm; Elevation at Bottom: 7270 mm; Elevation at Bottom Core: 7270 mm; Elevation at Bottom Survey: 7270 mm; Elevation at Top: 7530 mm; Elevation at Top Core: 7530 mm; Elevation at Top Survey: 7530 mm; Thickness: 260 mm
Identity Data - Has Association: yes
Phasing - Phase Created: 2. nieuwbouw
Structural - Rebar Cover - Bottom Face: Rebar Cover 1 <25 mm>; Rebar Cover - Other Faces: Rebar Cover 1 <25 mm>; Rebar Cover - Top Face: Rebar Cover 1 <25 mm>; Structural: yes
Name (Floor:C1_ kanaalplaat d=200+druklaag=60-50-60:...) | BaseQuantities, Perimeter (mm) | GrossArea (mm2) | NetArea (mm2) = Area (mm2) | GrossVolume (m3) | NetVolume (m3) = Volume (m3) | Dimensions, Perimeter (mm)
1639637 | 219.245 | 152451859 | 152451859 | 39.6375 | 39.6375 | 66826
1639650 | 218.589 | 154617072 | 154617072 | 40.2004 | 40.2004 | 66626 | BaseQuantities - Width: 27739 mm
1639678 | 43.9167 | 11008489 | 11008489 | 2.86221 | 2.86221 | 13385.8
1811947 | 33.2694 | 5780660 | 5780660 | 1.50297 | 1.50297 | 10140.5 | BaseQuantities - Width: 3339 mm
1811955 | 61.2391 | 18540471 | 10583796 |  | 2.75179 | 18665.7
1939440 | 157.891 | 124183166 | 124183166 | 32.2876 | 32.2876 | 48125.3
1939453 | 24.6642 | 3367206 | 3367206 | 0.875473 | 0.875473 | 7517.66 | BaseQuantities - Width: 2271.39 mm
1939462 | 66.9558 | 24900576 | 24900576 | 6.47415 | 6.47415 | 20408.1 | BaseQuantities - Width: 6165.13 mm
1964895 | 92.7949 | 48692761 | 48692761 | 12.6601 | 12.6601 | 28283.9
1964908 | 71.182 | 20859460 | 20859460 | 5.42346 | 5.42346 | 21696.3 | BaseQuantities - Width: 8349.99 mm
1964917 | 79.6717 | 36100103 | 36100103 | 9.38603 | 9.38603 | 24283.9
1964978 | 96.9431 | 4822462 | 3322067 |  | 0.863737 | 29548.3

# IfcSlab: Floor:D1_ kanaalplaat d=150+druklaag=60-50-60 (5)
In: V3 dakvloer
Type - PredefinedType: FLOOR; Material: Druklaag, C20/25 op systeemvloer 60 mm, Beton, prefab - kanaalplaat 150 mm
Type - Other - Category: Floors; Family Name: Floor
Type - Construction - Function: Interior; Default Thickness: 210 mm
Type - Graphics - Coarse Scale Fill Pattern: <Solid fill>; Coarse Scale Fill Color: 12632256
Type - Identity Data - Assembly Code: (23b.a); Description: kanaalplaatvloer d=150+drukl.60-50-60; Model: kanaalplaat vloer; t. Dikte afwerking: evt isol. + zc: -; t. Dikte druklaag:: 60-50-60 (gewapend); t. Peil - b.k. druklaag:: P +10780; t. Peil - b.k. ruwevloer:: P +10840; t. Veranderlijke Belasting in kN/m2:: 2.5 kN/m²; Type Comments: Wapening druklaag #Ø6-100; Type Mark: D1; Type Name: D1_ kanaalplaat d=150+druklaag=60-50-60
Type - Materials and Finishes - Structural Material: Druklaag, C20/25 op systeemvloer
Type - Text - BasisDikte: 0 mm; Totale opleghoogte: 0 mm
Type - Analytical Properties - Roughness: 1; Absorptance: 0.1
Type - Pset_ReinforcementBarPitchOfSlab - Description: kanaalplaatvloer d=150+drukl.60-50-60
Type - Pset_SlabCommon - IsExternal: no
Classification: (23b.a) Uniformat (Uniformat)
Pset_QuantityTakeOff - Reference: D1_ kanaalplaat d=150+druklaag=60-50-60; sets with these values: 2
Pset_SlabCommon - LoadBearing: yes; PitchAngle: 0 deg; Reference: D1_ kanaalplaat d=150+druklaag=60-50-60
Other - Family: Floor; Family and Type: Floor: D1_ kanaalplaat d=150+druklaag=60-50-60; Type: D1_ kanaalplaat d=150+druklaag=60-50-60; Type Id: 1979437
Constraints - Height Offset From Level: 0 mm; Related to Mass: no; Room Bounding: yes; Level: V3 dakvloer
Dimensions - Core Thickness: 210 mm; Elevation at Bottom: 10630 mm; Elevation at Bottom Core: 10630 mm; Elevation at Bottom Survey: 10630 mm; Elevation at Top: 10840 mm; Elevation at Top Core: 10840 mm; Elevation at Top Survey: 10840 mm; Thickness: 210 mm
Identity Data - Has Association: yes
Phasing - Phase Created: 2. nieuwbouw
Structural - Rebar Cover - Bottom Face: Rebar Cover 1 <25 mm>; Rebar Cover - Other Faces: Rebar Cover 1 <25 mm>; Rebar Cover - Top Face: Rebar Cover 1 <25 mm>; Structural: yes
Name (Floor:D1_ kanaalplaat d=150+druklaag=60-50-60:...) | Width (mm) | BaseQuantities, Perimeter (mm) | GrossArea (mm2) = NetArea (mm2) = Area (mm2) | GrossVolume (m3) = NetVolume (m3) = Volume (m3) | Dimensions, Perimeter (mm)
1665495 | 6989 | 81.5145 | 37976920 | 7.97515 | 24845.6
1665765 | 6800 | 80.2744 | 36949925 | 7.75948 | 24467.6
1665791 | 6799.98 | 80.2743 | 36949837 | 7.75947 | 24467.6
1665825 | 6799.99 | 80.2743 | 36949897 | 7.75948 | 24467.6
1701033 | 3075 | 55.8321 | 16708961 | 3.50888 | 17017.6

# IfcSlab: Floor:D2_ kanaalplaat d=150+druklaag=60-50-60, Floor:D2_ kanaalplaat d=150+druklaag=60-50-60:1665957
In: V3 dakvloer
Type - PredefinedType: FLOOR; Material: Druklaag, C20/25 op systeemvloer 60 mm, Beton, prefab - kanaalplaat 150 mm
Type - Other - Category: Floors; Family Name: Floor
Type - Construction - Function: Interior; Default Thickness: 210 mm
Type - Graphics - Coarse Scale Fill Pattern: <Solid fill>; Coarse Scale Fill Color: 12632256
Type - Identity Data - Assembly Code: (23b.a); Description: kanaalplaatvloer d=150+drukl.60-50-60; Model: kanaalplaat vloer; t. Dikte afwerking: evt isol. + zc: Dakafwerking; t. Dikte druklaag:: 60-50-60 (gewapend); t. Peil - afgewerktevloer:: var.; t. Peil - b.k. druklaag:: P -60; t. Peil - b.k. ruwevloer:: P +10840; t. Veranderlijke Belasting in kN/m2:: 1,00 kN/m²; Type Comments: Wapening druklaag #Ø6-100; Type Mark: D2; Type Name: D2_ kanaalplaat d=150+druklaag=60-50-60
Type - Materials and Finishes - Structural Material: Druklaag, C20/25 op systeemvloer
Type - Text - BasisDikte: 0 mm; Totale opleghoogte: 0 mm
Type - Analytical Properties - Roughness: 1; Absorptance: 0.1
Type - Pset_ReinforcementBarPitchOfSlab - Description: kanaalplaatvloer d=150+drukl.60-50-60
Type - Pset_SlabCommon - IsExternal: no
Classification: (23b.a) Uniformat (Uniformat)
Pset_QuantityTakeOff - Reference: D2_ kanaalplaat d=150+druklaag=60-50-60; sets with these values: 2
Pset_SlabCommon - LoadBearing: yes; PitchAngle: 0 deg; Reference: D2_ kanaalplaat d=150+druklaag=60-50-60
BaseQuantities - Perimeter: 185.242 mm; GrossArea: 138834795 mm2; NetArea: 135440764 mm2; NetVolume: 28.4427 m3
Other - Family: Floor; Family and Type: Floor: D2_ kanaalplaat d=150+druklaag=60-50-60; Type: D2_ kanaalplaat d=150+druklaag=60-50-60; Type Id: 1666077
Constraints - Height Offset From Level: 0 mm; Related to Mass: no; Room Bounding: yes; Level: V3 dakvloer
Dimensions - Area: 135440764 mm2; Core Thickness: 210 mm; Elevation at Bottom: 10630 mm; Elevation at Bottom Core: 10630 mm; Elevation at Bottom Survey: 10630 mm; Elevation at Top: 10840 mm; Elevation at Top Core: 10840 mm; Elevation at Top Survey: 10840 mm; Perimeter: 56461.9 mm; Thickness: 210 mm; Volume: 28.4427 m3
Identity Data - Has Association: yes
Phasing - Phase Created: 2. nieuwbouw
Structural - Rebar Cover - Bottom Face: Rebar Cover 1 <25 mm>; Rebar Cover - Other Faces: Rebar Cover 1 <25 mm>; Rebar Cover - Top Face: Rebar Cover 1 <25 mm>; Structural: yes

# IfcSlab: Floor:PBO prefab betonplaat d=200 (bordes) (3)
Type - PredefinedType: FLOOR; Material: Beton, prefab 200 mm
Type - Other - Category: Floors; Family Name: Floor
Type - Construction - Function: Interior; Default Thickness: 200 mm
Type - Graphics - Coarse Scale Fill Pattern: <Solid fill>; Coarse Scale Fill Color: 13758963
Type - Identity Data - Assembly Code: (23c.a); Description: prefab betonplaat d=200; Model: prefab betonplaat; Type Comments: bordes; Type Mark: PBO; Type Name: PBO prefab betonplaat d=200 (bordes)
Type - Materials and Finishes - Structural Material: Beton, prefab
Type - Text - BasisDikte: 0 mm; Totale opleghoogte: 0 mm
Type - Analytical Properties - Roughness: 1; Absorptance: 0.1
Type - Pset_ReinforcementBarPitchOfSlab - Description: prefab betonplaat d=200
Type - Pset_SlabCommon - IsExternal: no
Classification: (23c.a) Uniformat (Uniformat)
Pset_QuantityTakeOff - Reference: PBO prefab betonplaat d=200 (bordes); sets with these values: 2
Pset_SlabCommon - LoadBearing: yes; PitchAngle: 0 deg; Reference: PBO prefab betonplaat d=200 (bordes)
Other - Family: Floor; Family and Type: Floor: PBO prefab betonplaat d=200 (bordes); Type: PBO prefab betonplaat d=200 (bordes); Type Id: 1504639
Constraints - Related to Mass: no; Room Bounding: yes
Dimensions - Core Thickness: 200 mm; Thickness: 200 mm
Identity Data - Has Association: yes
Phasing - Phase Created: 2. nieuwbouw
Structural - Rebar Cover - Bottom Face: Rebar Cover 1 <25 mm>; Rebar Cover - Other Faces: Rebar Cover 1 <25 mm>; Rebar Cover - Top Face: Rebar Cover 1 <25 mm>; Structural: yes
Name (Floor:PBO prefab betonplaat d=200 (bordes):...) | In | Width (mm) | BaseQuantities, Perimeter (mm) | GrossArea (mm2) | NetArea (mm2) = Area (mm2) | GrossVolume (m3) | NetVolume (m3) = Volume (m3) | Level | Height Offset From Level (mm) | Elevation at Bottom (mm) = Elevation at Bottom Core (mm) = Elevation at Bottom Survey (mm) | Elevation at Top (mm) = Elevation at Top Core (mm) = Elevation at Top Survey (mm) | Dimensions, Perimeter (mm)
1663228 | V1 1e verd. (bk ruwe vloer) | 1135.56 | 17.5502 | 1747726 | 1747726 | 0.349545 | 0.349545 | V1 1e verd. (bk ruwe vloer) | 120 | 3650 | 3850 | 5349.3
1663343 | V1 1e verd. (bk ruwe vloer) | 837.985 | 17.2118 | 1495877 | 1495877 | 0.299175 | 0.299175 | V1 1e verd. (bk ruwe vloer) | -1780 | 1750 | 1950 | 5246.15
1961816 | V2 2e verd. (bk ruwe vloer) |  | 15.1085 | 1280787 | 1253537 |  | 0.224955 | V2 2e verd. (bk ruwe vloer) | -1830.3 | 5499.7 | 5699.7 | 4605.08

# IfcSlab: Floor:_ prefab betonplaat d=220 (bordes) 2, Floor:_ prefab betonplaat d=220 (bordes) 2:1806050
In: V1 1e verd. (bk ruwe vloer)
Type - PredefinedType: FLOOR; Material: Beton, prefab 220 mm
Type - Other - Category: Floors; Family Name: Floor
Type - Construction - Function: Interior; Default Thickness: 220 mm
Type - Graphics - Coarse Scale Fill Pattern: <Solid fill>; Coarse Scale Fill Color: 13758963
Type - Identity Data - Assembly Code: (23c.a); Description: prefab betonplaat d=220; Model: prefab betonplaat; Type Comments: bordes; Type Mark: P1; Type Name: _ prefab betonplaat d=220 (bordes) 2
Type - Materials and Finishes - Structural Material: Beton, prefab
Type - Text - BasisDikte: 0 mm; Totale opleghoogte: 0 mm
Type - Analytical Properties - Roughness: 1; Absorptance: 0.1
Type - Pset_ReinforcementBarPitchOfSlab - Description: prefab betonplaat d=220
Type - Pset_SlabCommon - IsExternal: no
Classification: (23c.a) Uniformat (Uniformat)
Pset_QuantityTakeOff - Reference: _ prefab betonplaat d=220 (bordes) 2; sets with these values: 2
Pset_SlabCommon - LoadBearing: yes; PitchAngle: 0 deg; Reference: _ prefab betonplaat d=220 (bordes) 2
BaseQuantities - Perimeter: 15.1085 mm; NetArea: 1280787 mm2; NetVolume: 0.250571 m3
Other - Family: Floor; Family and Type: Floor: _ prefab betonplaat d=220 (bordes) 2; Type: _ prefab betonplaat d=220 (bordes) 2; Type Id: 1976435
Constraints - Related to Mass: no; Room Bounding: yes; Level: V1 1e verd. (bk ruwe vloer); Height Offset From Level: -1830.3 mm
Dimensions - Area: 1280787 mm2; Core Thickness: 220 mm; Elevation at Bottom: 1679.7 mm; Elevation at Bottom Core: 1679.7 mm; Elevation at Bottom Survey: 1679.7 mm; Elevation at Top: 1899.7 mm; Elevation at Top Core: 1899.7 mm; Elevation at Top Survey: 1899.7 mm; Perimeter: 4605.08 mm; Thickness: 220 mm; Volume: 0.250571 m3
Identity Data - Has Association: yes
Phasing - Phase Created: 2. nieuwbouw
Structural - Rebar Cover - Bottom Face: Rebar Cover 1 <25 mm>; Rebar Cover - Other Faces: Rebar Cover 1 <25 mm>; Rebar Cover - Top Face: Rebar Cover 1 <25 mm>; Structural: yes

# IfcWall: Basic Wall:bt_kzst 214 (7)
Type - PredefinedType: STANDARD; Material: Kalkzandsteen, lijmwerk CS12 214 mm
Type - Other - Category: Walls; Family Name: Basic Wall
Type - Construction - Function: Interior; Width: 214 mm; Wrapping at Inserts: Do not wrap
Type - Graphics - Coarse Scale Fill Color: 0; Coarse Scale Fill Pattern: Kalkzandsteen
Type - Identity Data - Assembly Code: (28.d); Description: kalkzandsteen d=214 CS12; Type Mark: KZS 214; Type Name: bt_kzst 214
Type - Materials and Finishes - Structural Material: Kalkzandsteen, lijmwerk CS12
Type - Analytical Properties - Roughness: 1; Absorptance: 0.1
Type - Pset_ReinforcementBarPitchOfWall - Description: kalkzandsteen d=214 CS12
Type - Pset_WallCommon - IsExternal: no
Classification: (28.d) Uniformat (Uniformat)
Pset_QuantityTakeOff - Reference: bt_kzst 214; sets with these values: 2
Pset_WallCommon - LoadBearing: yes; Reference: bt_kzst 214
BaseQuantities - Width: 214 mm
Other - Family: Basic Wall; Family and Type: Basic Wall: bt_kzst 214; Type: bt_kzst 214; Type Id: 355903
Constraints - Related to Mass: no; Room Bounding: yes; Base Extension Distance: 0 mm; Base is Attached: no; Top Extension Distance: 0 mm
Identity Data - Has Association: yes
Phasing - Phase Created: 2. nieuwbouw
Structural - Rebar Cover - Other Faces: Rebar Cover 1 <25 mm>; Structural: yes; Rebar Cover - Exterior Face: Rebar Cover 1 <25 mm>; Rebar Cover - Interior Face: Rebar Cover 1 <25 mm>; Structural Usage: Bearing
Cross-Section Definition - Cross-Section: Vertical
Name (Basic Wall:bt_kzst 214:...) | In | ExtendToStructure = Top is Attached | BaseQuantities, Length (mm) = Dimensions, Length (mm) | NetVolume (m3) = Volume (m3) | Base Constraint | Base Offset (mm) | Top Constraint | Location Line | Top Offset (mm) | Unconnected Height (mm) | Area (mm2)
1550339 | F1 begg (bk ruwe vloer) | yes | 22514 | 10.3943 | F1 begg (bk ruwe vloer) | 0 | Up to level: V1 ok vloer | Wall Centerline | 0 | 3540 | 48571545
1642406 | V1 1e verd. (bk ruwe vloer) | no | 7196.25 | 5.93904 | V1 1e verd. (bk ruwe vloer) | -150 | Up to level: V2 2e verd. (bk ruwe vloer) | Finish Face: Interior | -20 | 3930 | 27752512
1644937 | KDV V1 1e verd. (bk ruwe vloer) | no | 3516.45 | 2.60782 | V1 ok vloer | 143.1 | Up to level: V2 2e verd. (bk ruwe vloer) | Finish Face: Interior | -154.039 | 3762.86 | 12186086
1646123 | KDV V2 werkbalken | no | 3516.45 | 2.38067 | V2 ok vloer | 143.1 | Up to level: V4 BK metselwerk | Finish Face: Interior | -945.047 | 3341.85 | 11124628
1761424 | V2 2e verd. (bk ruwe vloer) | no | 3241.57 | 2.44613 | V2 2e verd. (bk ruwe vloer) | 0 | Up to level: V4 BK metselwerk | Finish Face: Interior | -548.1 | 3621.9 | 11430529
1769744 | V2 2e verd. (bk ruwe vloer) | no | 7203.75 | 4.86523 | V2 2e verd. (bk ruwe vloer) | 3.1 | Up to level: V4 BK metselwerk | Finish Face: Interior | -945.047 | 3221.85 | 22734696
1934257 | F1 begg (bk ruwe vloer) | no | 6107 | 0.544509 | F1 begg (bk ruwe vloer) | 0 | Up to level: V1 ok vloer | Finish Face: Interior | -762 | 2778 | 2544434

# IfcWallStandardCase: Basic Wall:bt_kzst 214 (95)
Type - PredefinedType: STANDARD; Material: Kalkzandsteen, lijmwerk CS12 214 mm
Type - Other - Category: Walls; Family Name: Basic Wall
Type - Construction - Function: Interior; Width: 214 mm; Wrapping at Inserts: Do not wrap
Type - Graphics - Coarse Scale Fill Color: 0; Coarse Scale Fill Pattern: Kalkzandsteen
Type - Identity Data - Assembly Code: (28.d); Description: kalkzandsteen d=214 CS12; Type Mark: KZS 214; Type Name: bt_kzst 214
Type - Materials and Finishes - Structural Material: Kalkzandsteen, lijmwerk CS12
Type - Analytical Properties - Roughness: 1; Absorptance: 0.1
Type - Pset_ReinforcementBarPitchOfWall - Description: kalkzandsteen d=214 CS12
Type - Pset_WallCommon - IsExternal: no
Classification: (28.d) Uniformat (Uniformat)
BaseQuantities - Width: 214 mm
Pset_QuantityTakeOff - Reference: bt_kzst 214; sets with these values: 2
Pset_WallCommon - LoadBearing: yes; Reference: bt_kzst 214
Other - Family: Basic Wall; Family and Type: Basic Wall: bt_kzst 214; Type: bt_kzst 214; Type Id: 355903
Constraints - Related to Mass: no; Room Bounding: yes; Base Extension Distance: 0 mm; Base is Attached: no; Top Extension Distance: 0 mm
Phasing - Phase Created: 2. nieuwbouw
Structural - Rebar Cover - Other Faces: Rebar Cover 1 <25 mm>; Structural: yes; Rebar Cover - Exterior Face: Rebar Cover 1 <25 mm>; Rebar Cover - Interior Face: Rebar Cover 1 <25 mm>; Structural Usage: Bearing
Cross-Section Definition - Cross-Section: Vertical
Name (Basic Wall:bt_kzst 214:...) | In | Height (mm) | BaseQuantities, Length (mm) | GrossFootprintArea (mm2) | GrossVolume (m3) | GrossSideArea (mm2) | NetSideArea (mm2) = Area (mm2) | NetVolume (m3) = Volume (m3) | ExtendToStructure = Top is Attached | Base Constraint | Base Offset (mm) | Location Line | Top Constraint | Top Offset (mm) | Unconnected Height (mm) | Dimensions, Length (mm) | Has Association
1542997 | F1 begg (bk ruwe vloer) | 3540 | 5564 | 1190696 | 4.21506 | 19696560 | 19696560 | 4.21506 | yes | F1 begg (bk ruwe vloer) | 0 | Finish Face: Interior | Up to level: V1 ok vloer | 20 | 3560 | 5457 | yes
1543078 | F1 begg (bk ruwe vloer) | 3540 | 5285.65 | 1131129 | 1.40857 | 6582117 | 6582117 | 1.40857 | yes | F1 begg (bk ruwe vloer) | 0 | Finish Face: Interior | Up to level: V1 ok vloer | 20 | 3560 | 5392.65 | yes
1543628 | F1 begg (bk ruwe vloer) | 3540 | 5349.35 | 1144760 | 4.05245 | 18936692 | 18936692 | 4.05245 | yes | F1 begg (bk ruwe vloer) | 0 | Wall Centerline | Up to level: V1 ok vloer | 20 | 3560 | 5456.35 | yes
1543815 | F1 begg (bk ruwe vloer) | 3540 | 5349.35 | 1144760 | 4.05245 | 18936692 | 18936692 | 4.05245 | yes | F1 begg (bk ruwe vloer) | 0 | Wall Centerline | Up to level: V1 ok vloer | 20 | 3560 | 5456.35 | yes
1543845 | F1 begg (bk ruwe vloer) | 3540 | 5349.35 | 1144760 | 4.05245 | 18936692 | 18936692 | 4.05245 | yes | F1 begg (bk ruwe vloer) | 0 | Wall Centerline | Up to level: V1 ok vloer | 20 | 3560 | 5456.35 | yes
1543875 | F1 begg (bk ruwe vloer) | 3540 | 3938.57 | 842853 | 2.9063 | 13580837 | 13580837 | 2.9063 | yes | F1 begg (bk ruwe vloer) | 0 | Finish Face: Interior | Up to level: V1 ok vloer | 20 | 3560 | 3938.57 | yes
1543877 | F1 begg (bk ruwe vloer) | 3540 | 5350 | 1144900 | 4.05295 | 18939000 | 18939000 | 4.05295 | yes | F1 begg (bk ruwe vloer) | 0 | Wall Centerline | Up to level: V1 ok vloer | 20 | 3560 | 5457 | yes
1544769 | F1 begg (bk ruwe vloer) | 3540 | 2714.91 | 580990 | 2.00779 | 9382174 | 9382174 | 2.00779 | no | F1 begg (bk ruwe vloer) | 0 | Finish Face: Interior | Up to level: V1 ok vloer | 0 | 3540 | 2714.91 | yes
1545493 | F1 begg (bk ruwe vloer) | 3540 | 1084.06 | 231990 | 0.772323 | 3608984 | 3608984 | 0.772323 | yes | F1 begg (bk ruwe vloer) | 0 | Finish Face: Interior | Up to level: V1 ok vloer | 20 | 3560 | 1191.06 | yes
1546130 | F1 begg (bk ruwe vloer) | 3540 | 2573.44 | 550717 | 1.90062 | 8881387 | 8881387 | 1.90062 | no | F1 begg (bk ruwe vloer) | 0 | Finish Face: Interior | Up to level: V1 ok vloer | 0 | 3540 | 2680.44 | yes
1546608 | F1 begg (bk ruwe vloer) | 3540 | 514.024 | 110001 | 0.389404 | 1819643 | 1819643 | 0.389404 | yes | F1 begg (bk ruwe vloer) | 0 | Finish Face: Interior | Up to level: V1 ok vloer | 20 | 3560 | 300.024 | yes
1547990 | F1 begg (bk ruwe vloer) | 3350 | 463.936 | 99282.2 | 0.332595 | 1554184 | 1554184 | 0.332595 | yes | F1 begg (bk ruwe vloer) | 0 | Finish Face: Interior | Up to level: V1 ok vloer | 0 | 3540 | 356.936 | yes
1548796 | F1 begg (bk ruwe vloer) | 3350 | 807 | 172698 | 0.578538 | 2703450 | 2703450 | 0.578538 | yes | F1 begg (bk ruwe vloer) | 0 | Finish Face: Interior | Up to level: V1 ok vloer | 0 | 3540 | 700 | yes
1548875 | F1 begg (bk ruwe vloer) | 3540 | 514.007 | 109997 | 0.389391 | 1819584 | 1819584 | 0.389391 | yes | F1 begg (bk ruwe vloer) | 0 | Finish Face: Interior | Up to level: V1 ok vloer | 20 | 3560 | 300.006 | yes
1549191 | F1 begg (bk ruwe vloer) | 3540 | 1082.75 | 231709 | 0.771489 | 3605091 | 3605091 | 0.771489 | yes | F1 begg (bk ruwe vloer) | 0 | Finish Face: Interior | Up to level: V1 ok vloer | 20 | 3560 | 1189.75 | yes
1549561 | F1 begg (bk ruwe vloer) | 3540 | 3151.09 | 674334 | 2.38714 | 11154863 | 11154863 | 2.38714 | no | F1 begg (bk ruwe vloer) | 0 | Finish Face: Interior | Up to level: V1 ok vloer | 0 | 3540 | 3044.09 | yes
1549776 | F1 begg (bk ruwe vloer) | 3540 | 1857.76 | 397560 | 1.40736 | 6576465 | 6576465 | 1.40736 | yes | F1 begg (bk ruwe vloer) | 0 | Finish Face: Interior | Up to level: V1 ok vloer | 20 | 3560 | 1964.76 | yes
1550279 | F1 begg (bk ruwe vloer) | 3400 | 6593 | 1410902 | 4.79707 | 22416200 | 22416200 | 4.79707 | no | F1 begg (bk ruwe vloer) | 0 | Wall Centerline | Up to level: V1 ok vloer | -140 | 3400 | 6807 | yes
1550444 | F1 begg (bk ruwe vloer) | 3400 | 6593 | 1410902 | 4.79707 | 22416200 | 22416200 | 4.79707 | no | F1 begg (bk ruwe vloer) | 0 | Wall Centerline | Up to level: V1 ok vloer | -140 | 3400 | 6807 | yes
1555246 | F1 begg (bk ruwe vloer) | 3540 | 300.345 | 64273.9 | 0.22753 | 1063223 | 1063223 | 0.22753 | no | F1 begg (bk ruwe vloer) | 0 | Finish Face: Interior | Up to level: V1 ok vloer | 0 | 3540 | 407.345 | yes
1555450 | F1 begg (bk ruwe vloer) | 3650 | 4067.65 | 870477 | 3.12126 | 14585328 | 14296869 | 3.05953 | no | F1 begg (bk ruwe vloer) | 0 | Finish Face: Interior | Up to level: V1 ok vloer | 0 | 3540 | 4067.65 | yes
1565929 | F1 begg (bk ruwe vloer) | 3540 | 3450 | 738300 | 2.61358 | 12213005 | 12213005 | 2.61358 | yes | F1 begg (bk ruwe vloer) | 0 | Wall Centerline | Up to level: V1 ok vloer | 20 | 3560 | 3450 | yes
1568637 | F1 begg (bk ruwe vloer) | 3560 | 5664 | 1212096 | 4.31506 | 20163840 | 20163840 | 4.31506 | no | F1 begg (bk ruwe vloer) | 0 | Finish Face: Interior | Up to level: V1 ok vloer | 20 | 3560 | 5557 | yes
1570870 | V1 1e verd. (bk ruwe vloer) | 3540 | 5350 | 1144900 | 4.05295 | 18939000 | 18939000 | 4.05295 | no | V1 1e verd. (bk ruwe vloer) | 0 | Wall Centerline | Up to level: V2 ok vloer | 0 | 3540 | 5457 | yes
1570994 | V1 1e verd. (bk ruwe vloer) | 3540 | 5350 | 1144900 | 4.05295 | 18939000 | 18939000 | 4.05295 | no | V1 1e verd. (bk ruwe vloer) | 0 | Wall Centerline | Up to level: V2 ok vloer | 0 | 3540 | 5457 | yes
1571026 | V1 1e verd. (bk ruwe vloer) | 2778 | 26925.4 | 5762038 | 4.58974 | 21447363 | 21447363 | 4.58974 | no | V1 1e verd. (bk ruwe vloer) | 0 | Finish Face: Interior | Up to level: V2 ok vloer | -762 | 2778 | 27032.4 | yes
1571028 | V1 1e verd. (bk ruwe vloer) | 3540 | 5350 | 1144900 | 4.05295 | 18939000 | 18939000 | 4.05295 | no | V1 1e verd. (bk ruwe vloer) | 0 | Wall Centerline | Up to level: V2 ok vloer | 0 | 3540 | 5457 | yes
1571056 | V1 1e verd. (bk ruwe vloer) | 3540 | 3938.57 | 842853 | 2.90629 | 13580772 | 13580772 | 2.90629 | no | V1 1e verd. (bk ruwe vloer) | 0 | Finish Face: Interior | Up to level: V2 ok vloer | 0 | 3540 | 3831.57 | yes
1571058 | V1 1e verd. (bk ruwe vloer) | 3540 | 5350 | 1144900 | 4.05295 | 18939000 | 18939000 | 4.05295 | no | V1 1e verd. (bk ruwe vloer) | 0 | Wall Centerline | Up to level: V2 ok vloer | 0 | 3540 | 5457 | yes
1571484 | V1 1e verd. (bk ruwe vloer) | 3540 | 11314 | 2421196 | 8.02883 | 37517901 | 37517901 | 8.02883 | no | V1 1e verd. (bk ruwe vloer) | 0 | Finish Face: Interior | Up to level: V2 ok vloer | 0 | 3540 | 11314 | yes
1571538 | V1 1e verd. (bk ruwe vloer) | 3540 | 5564 | 1190696 | 4.21506 | 19696560 | 18016350 | 3.8555 | no | V1 1e verd. (bk ruwe vloer) | 0 | Finish Face: Interior | Up to level: V2 ok vloer | 0 | 3540 | 5457 | yes
1571650 | V1 1e verd. (bk ruwe vloer) | 3540 | 5664 | 1212096 | 4.29082 | 20050560 | 18370589 | 3.93131 | no | V1 1e verd. (bk ruwe vloer) | 0 | Finish Face: Interior | Up to level: V2 ok vloer | 0 | 3540 | 5557 | yes
1571698 | V1 1e verd. (bk ruwe vloer) | 3540 | 5285.65 | 1131129 | 1.40857 | 6582117 | 6582117 | 1.40857 | no | V1 1e verd. (bk ruwe vloer) | 0 | Finish Face: Interior | Up to level: V2 ok vloer | 0 | 3540 | 5392.65 | yes
1571801 | V1 1e verd. (bk ruwe vloer) | 3540 | 2714.91 | 580990 | 2.00779 | 9382174 | 9382174 | 2.00779 | no | V1 1e verd. (bk ruwe vloer) | 0 | Finish Face: Interior | Up to level: V2 ok vloer | 0 | 3540 | 2714.91 | yes
1571924 | V1 1e verd. (bk ruwe vloer) | 3540 | 2937.09 | 628538 | 2.22502 | 10397303 | 10397303 | 2.22502 | no | V1 1e verd. (bk ruwe vloer) | 0 | Finish Face: Interior | Up to level: V2 ok vloer | 0 | 3540 | 3044.09 | yes
1572122 | V1 1e verd. (bk ruwe vloer) | 3540 | 2787.44 | 596513 | 2.06192 | 9635122 | 9635122 | 2.06192 | no | V1 1e verd. (bk ruwe vloer) | 0 | Finish Face: Interior | Up to level: V2 ok vloer | 0 | 3540 | 2787.44 | yes
1607535 | V2 2e verd. (bk ruwe vloer) | 2778 | 26925.4 | 5762038 | 4.58974 | 21447363 | 21447363 | 4.58974 | no | V2 2e verd. (bk ruwe vloer) | 0 | Finish Face: Interior | Up to level: V4 BK metselwerk | -1392 | 2778 | 27032.4 | yes
1607539 | V2 2e verd. (bk ruwe vloer) | 2778 | 590 | 126260 | 0.350027 | 1635639 | 1635639 | 0.350027 | no | V2 2e verd. (bk ruwe vloer) | 0 | Finish Face: Interior | Up to level: V4 BK metselwerk | -1392 | 2778 | 590 | yes
1607543 | V2 2e verd. (bk ruwe vloer) | 3260 | 5664.19 | 1212136 | 0.359565 | 1680210 | 16785042 | 3.592 | no | V2 2e verd. (bk ruwe vloer) | 0 | Finish Face: Interior |  | 90 | 3260 | 5557.19 | yes
1607545 | V2 2e verd. (bk ruwe vloer) | 3260 | 5564 | 1190696 | 3.8596 | 18035492 | 16355282 | 3.50003 | no | V2 2e verd. (bk ruwe vloer) | 0 | Finish Face: Interior | Up to level: V3 dakvloer | -50 | 3260 | 5457 | yes
1607549 | V2 2e verd. (bk ruwe vloer) | 3035 | 5499.65 | 1176925 | 2.97097 | 13883014 | 8265700 | 1.76886 | no | V2 2e verd. (bk ruwe vloer) | 0 | Finish Face: Interior | Up to level: V4 BK metselwerk | -1135 | 3035 | 5392.65 | yes
1607551 | V2 2e verd. (bk ruwe vloer) | 3035 | 2714.91 | 580990 | 1.74176 | 8139059 | 8139059 | 1.74176 | no | V2 2e verd. (bk ruwe vloer) | 0 | Finish Face: Interior | Up to level: V4 BK metselwerk | -1135 | 3035 | 2714.91 | yes
1607553 | V2 2e verd. (bk ruwe vloer) | 3060 | 5863.81 | 1254856 | 3.83986 | 17943266 | 15983823 | 3.42054 | no | V2 2e verd. (bk ruwe vloer) | 0 | Finish Face: Interior | Up to level: V4 BK metselwerk | -1110 | 3060 | 5756.81 | yes
1607555 | V2 2e verd. (bk ruwe vloer) | 3035 | 2937.09 | 628538 | 1.90761 | 8914072 | 8914072 | 1.90761 | no | V2 2e verd. (bk ruwe vloer) | 0 | Finish Face: Interior | Up to level: V4 BK metselwerk | -1135 | 3035 | 3044.09 | yes
1607679 | V2 2e verd. (bk ruwe vloer) | 3100 | 5450 | 1166300 | 3.61553 | 16895000 | 14935556 | 3.19621 | no | V2 2e verd. (bk ruwe vloer) | 0 | Finish Face: Interior | Up to level: V3 dakvloer | -210 | 3100 | 5557 | yes
1610735 | F1 begg (bk ruwe vloer) | 3540 | 649.07 | 138901 | 0.491709 | 2297707 | 2297707 | 0.491709 | no | F1 begg (bk ruwe vloer) | 0 | Finish Face: Interior | Up to level: V1 ok vloer | 0 | 3540 | 649.07 | yes
1626859 | F1 begg (bk ruwe vloer) | 3540 | 1085.03 | 232196 | 0.772896 | 3611664 | 3611664 | 0.772896 | yes | F1 begg (bk ruwe vloer) | 0 | Finish Face: Interior | Up to level: V1 ok vloer | 20 | 3560 | 1192.03 | yes
1627050 | F1 begg (bk ruwe vloer) | 3540 | 1083.73 | 231918 | 0.772071 | 3607808 | 3607808 | 0.772071 | yes | F1 begg (bk ruwe vloer) | 0 | Finish Face: Interior | Up to level: V1 ok vloer | 20 | 3560 | 1190.73 | yes
1627707 | F1 begg (bk ruwe vloer) | 3350 | 593 | 126902 | 0.425122 | 1986550 | 1986550 | 0.425123 | yes | F1 begg (bk ruwe vloer) | 0 | Finish Face: Interior | Up to level: V1 ok vloer | 0 | 3540 | 700 | yes
1627852 | F1 begg (bk ruwe vloer) | 3350 | 9200.41 | 1968887 | 6.59577 | 30821368 | 30821368 | 6.59577 | yes | F1 begg (bk ruwe vloer) | 0 | Finish Face: Interior | Up to level: V1 ok vloer | 0 | 3540 | 9200.41 | yes
1628076 | F1 begg (bk ruwe vloer) | 3350 | 249.038 | 53294.1 | 0.178535 | 834277 | 834277 | 0.178535 | yes | F1 begg (bk ruwe vloer) | 0 | Finish Face: Interior | Up to level: V1 ok vloer | 0 | 3540 | 356.038 | yes
1628353 | F1 begg (bk ruwe vloer) | 3350 | 900.743 | 192759 | 0.608986 | 2845729 | 2845729 | 0.608986 | yes | F1 begg (bk ruwe vloer) | 0 | Finish Face: Interior | Up to level: V1 ok vloer | 0 | 3540 | 793.743 | yes
1628557 | F1 begg (bk ruwe vloer) | 3540 | 1805.33 | 386340 | 1.34504 | 6285227 | 6285227 | 1.34504 | yes | F1 begg (bk ruwe vloer) | 0 | Finish Face: Interior | Up to level: V1 ok vloer | 0 | 3540 | 1805.33 | yes
1642328 | V2 2e verd. (bk ruwe vloer) | 3147.95 | 814.345 | 174270 | 0.548594 | 2563521 | 2563521 | 0.548594 | no | V2 2e verd. (bk ruwe vloer) | 0 | Finish Face: Interior | Up to level: V4 BK metselwerk | -1022.05 | 3147.95 | 814.345 | yes
1642526 | V1 1e verd. (bk ruwe vloer) | 3540 | 8049.97 | 1722694 | 6.09834 | 28496904 | 28496904 | 6.09834 | no | V1 1e verd. (bk ruwe vloer) | 0 | Finish Face: Interior | Up to level: V2 ok vloer | 0 | 3540 | 8049.97 | yes
1642984 | V1 1e verd. (bk ruwe vloer) | 3930 | 7135.75 | 1527050 | 6.00131 | 28043497 | 28043497 | 6.00131 | no | V1 1e verd. (bk ruwe vloer) | -150 | Finish Face: Interior | Up to level: V2 2e verd. (bk ruwe vloer) | -20 | 3930 | 7135.75 | yes
1643487 | V1 1e verd. (bk ruwe vloer) | 3660 | 7233.37 | 1547942 | 5.14987 | 24064803 | 24064803 | 5.14987 | no | V1 1e verd. (bk ruwe vloer) | 120 | Finish Face: Interior | Up to level: V2 2e verd. (bk ruwe vloer) | -20 | 3660 | 7233.37 | yes
1643882 | V1 1e verd. (bk ruwe vloer) | 3660 | 7651.06 | 1637326 | 4.99145 | 23324553 | 23324553 | 4.99145 | no | V1 1e verd. (bk ruwe vloer) | 120 | Finish Face: Interior | Up to level: V2 2e verd. (bk ruwe vloer) | -20 | 3660 | 7651.06 | yes
1644294 | V1 1e verd. (bk ruwe vloer) | 3660 | 7196.25 | 1539998 | 5.63639 | 26338275 | 26338275 | 5.63639 | no | V1 1e verd. (bk ruwe vloer) | 120 | Finish Face: Interior | Up to level: V2 2e verd. (bk ruwe vloer) | -20 | 3660 | 7196.25 | yes
1644296 | V1 1e verd. (bk ruwe vloer) | 3660 | 7135.75 | 1527051 | 5.589 | 26116845 | 26116845 | 5.589 | no | V1 1e verd. (bk ruwe vloer) | 120 | Finish Face: Interior | Up to level: V2 2e verd. (bk ruwe vloer) | -20 | 3660 | 7135.75 | yes
1645432 | V2 2e verd. (bk ruwe vloer) | 3147.95 | 1399.35 | 299461 | 0.942688 | 4405085 | 4405085 | 0.942688 | no | V2 2e verd. (bk ruwe vloer) | 0 | Finish Face: Interior | Up to level: V4 BK metselwerk | -1022.05 | 3147.95 | 1399.35 | yes
1646121 | V2 2e verd. (bk ruwe vloer) | 3224.95 | 2787.44 | 596513 | 1.89421 | 8851459 | 8851459 | 1.89421 | no | V2 2e verd. (bk ruwe vloer) | 0 | Finish Face: Interior | Up to level: V4 BK metselwerk | -945.047 | 3224.95 | 2787.44 | yes
1763955 | V1 1e verd. (bk ruwe vloer) | 3540 | 3450 | 738300 | 2.61358 | 12213005 | 12213005 | 2.61358 | no | V1 1e verd. (bk ruwe vloer) | 0 | Wall Centerline | Up to level: V2 ok vloer | 0 | 3540 | 3450 | yes
1768366 | V2 2e verd. (bk ruwe vloer) | 3212.85 | 7200 | 1540800 | 4.95036 | 23132542 | 23132542 | 4.95036 | no | V2 2e verd. (bk ruwe vloer) | 3.1 | Finish Face: Interior | Up to level: V4 BK metselwerk | -954.047 | 3212.85 | 7200 | yes
1768707 | V2 2e verd. (bk ruwe vloer) | 3212.85 | 7128.25 | 1525446 | 4.90103 | 22902020 | 22902020 | 4.90103 | no | V2 2e verd. (bk ruwe vloer) | 3.1 | Finish Face: Interior | Up to level: V4 BK metselwerk | -954.047 | 3212.85 | 7128.25 | yes
1769034 | V2 2e verd. (bk ruwe vloer) | 3212.85 | 7658.56 | 1638931 | 5.26564 | 24605815 | 24605815 | 5.26564 | no | V2 2e verd. (bk ruwe vloer) | 3.1 | Finish Face: Interior | Up to level: V4 BK metselwerk | -954.047 | 3212.85 | 7658.56 | yes
1769253 | V2 2e verd. (bk ruwe vloer) | 3212.85 | 7237.12 | 1548745 | 4.97589 | 23251819 | 23251819 | 4.97589 | no | V2 2e verd. (bk ruwe vloer) | 3.1 | Finish Face: Interior | Up to level: V4 BK metselwerk | -954.047 | 3212.85 | 7237.12 | yes
1769402 | V2 2e verd. (bk ruwe vloer) | 3212.85 | 7610.8 | 1628712 | 5.23281 | 24452397 | 24452397 | 5.23281 | no | V2 2e verd. (bk ruwe vloer) | 3.1 | Finish Face: Interior | Up to level: V4 BK metselwerk | -954.047 | 3212.85 | 7610.8 | yes
1769682 | V2 2e verd. (bk ruwe vloer) | 3221.85 | 7128.25 | 1525445 | 4.91476 | 22966175 | 22966175 | 4.91476 | no | V2 2e verd. (bk ruwe vloer) | 3.1 | Finish Face: Interior | Up to level: V4 BK metselwerk | -945.047 | 3221.85 | 7128.25 | yes
1802180 | F1 begg (bk ruwe vloer) | 3560 | 1104.91 | 236451 | 0.841765 | 3933481 | 3933481 | 0.841765 | no | F1 begg (bk ruwe vloer) | 0 | Finish Face: Interior | Up to level: V1 ok vloer | 20 | 3560 | 1104.91 | yes
1811112 | F1 begg (bk ruwe vloer) | 3560 | 3213.98 | 687792 | 2.44854 | 11441773 | 9761686 | 2.089 | no | F1 begg (bk ruwe vloer) | 0 | Finish Face: Interior | Up to level: V1 ok vloer | 20 | 3560 | 3213.98 | yes
1811425 | F1 begg (bk ruwe vloer) | 3540 | 3213.98 | 687792 | 2.43478 | 11377493 | 9697406 | 2.07524 | no | F1 begg (bk ruwe vloer) | 0 | Finish Face: Interior | Up to level: V1 ok vloer | 0 | 3540 | 3213.98 | yes
1911856 | F1 begg (bk ruwe vloer) | 2778 | 26925.4 | 5762038 | 4.8093 | 22473352 | 22473352 | 4.8093 | no | F1 begg (bk ruwe vloer) | 0 | Finish Face: Interior | Up to level: V1 ok vloer | -762 | 2778 | 27032.4 | yes
1932186 | F1 begg (bk ruwe vloer) | 2778 | 13205.8 | 2826040 | 1.96405 | 9177824 | 9177824 | 1.96405 | no | F1 begg (bk ruwe vloer) | 0 | Finish Face: Interior | Up to level: V1 ok vloer | -762 | 2778 | 13205.8 | yes
1933353 | F1 begg (bk ruwe vloer) | 2778 | 2065.21 | 441955 | 0.341163 | 1594217 | 1594217 | 0.341163 | no | F3 (ok fundering) | 1110 | Finish Face: Interior | Up to level: V1 ok vloer | -762 | 2778 | 2065.21 | yes
1933665 | F1 begg (bk ruwe vloer) | 2778 | 2063.41 | 441571 | 0.340617 | 1591669 | 1591669 | 0.340617 | no | F3 (ok fundering) | 1110 | Finish Face: Interior | Up to level: V1 ok vloer | -762 | 2778 | 2063.41 | yes
1933958 | F1 begg (bk ruwe vloer) | 2778 | 6300.28 | 1348260 | 0.881223 | 4117866 | 4117866 | 0.881223 | no | F1 begg (bk ruwe vloer) | 0 | Finish Face: Interior | Up to level: V1 ok vloer | -762 | 2778 | 6300.28 | yes
1934225 | F1 begg (bk ruwe vloer) | 2778 | 6300.28 | 1348259 | 0.881224 | 4117867 | 4117867 | 0.881224 | no | F1 begg (bk ruwe vloer) | 0 | Finish Face: Interior | Up to level: V1 ok vloer | -762 | 2778 | 6300.28 | yes
1935647 | KDV V1 1e verd. (bk ruwe vloer) | 2778 | 1760.09 | 376658 | 0.162777 | 760642 | 760642 | 0.162777 | no | V1 ok vloer | 260 | Finish Face: Interior | Up to level: V2 2e verd. (bk ruwe vloer) | -1022 | 2778 | 1760.09 | yes
1935908 | KDV V2 werkbalken | 2978 | 1760.09 | 376658 | 0.238109 | 1112659 | 1112659 | 0.238109 | no | V2 ok vloer | 260 | Finish Face: Interior | Up to level: V4 BK metselwerk | -1192 | 2978 | 1760.09 | yes
1963433 | KDV V1 1e verd. (bk ruwe vloer) | 3540 | 6272 | 1342207 | 1.23094 | 5752065 | 5752065 | 1.23094 | no | V1 ok vloer | 260 | Finish Face: Interior | Up to level: V2 2e verd. (bk ruwe vloer) | -260 | 3540 | 6379 | yes
1963584 | KDV V2 werkbalken | 2977.99 | 6272 | 1342207 | 1.1888 | 5555153 | 5555153 | 1.1888 | no | V2 ok vloer | 260 | Finish Face: Interior | Up to level: V4 BK metselwerk | -1192.01 | 2977.99 | 6379 | yes
1963794 | KDV V1 1e verd. (bk ruwe vloer) | 3540 | 6272 | 1342207 | 1.32371 | 6185582 | 6185582 | 1.32371 | no | V1 ok vloer | 260 | Finish Face: Interior | Up to level: V2 2e verd. (bk ruwe vloer) | -260 | 3540 | 6379 | yes
1963797 | KDV V2 werkbalken | 2977.99 | 6272 | 1342207 | 0.714877 | 3340545 | 3340545 | 0.714877 | no | V2 ok vloer | 260 | Finish Face: Interior | Up to level: V4 BK metselwerk | -1192.01 | 2977.99 | 6379 | yes
1987336 | V3 dakvloer | 2451.46 | 5500.19 | 1177040 | 1.64498 | 7686800 | 7686800 | 1.64498 | no | V3 dakvloer | -170.708 | Finish Face: Interior | Up to level: V4 BK metselwerk | 1500 | 2530.71 | 5500.19 | yes
1987519 | V3 dakvloer | 2401.48 | 5506.81 | 1178458 | 1.58649 | 7413505 | 7413505 | 1.58649 | no | V3 dakvloer | 0 | Finish Face: Interior | Up to level: V4 BK metselwerk | 1500 | 2360 | 5506.81 | yes
2071864 | V3 dakvloer | 2451.46 | 5500.19 | 1177040 | 1.66865 | 7797416 | 7797416 | 1.66865 | no | V3 dakvloer | -130 | Finish Face: Interior | Up to level: V4 BK metselwerk | 1500 | 2490 | 5607.19 | no
2071873 | V3 dakvloer | 2401.48 | 5506.81 | 1178458 | 1.58649 | 7413505 | 7413505 | 1.58649 | no | V3 dakvloer | 0 | Finish Face: Interior | Up to level: V4 BK metselwerk | 1500 | 2360 | 5506.81 | no
2087742 | V1 1e verd. (bk ruwe vloer) | 3660 | 7614.55 | 1629515 | 4.99789 | 23354643 | 23354643 | 4.99789 | no | V1 1e verd. (bk ruwe vloer) | 120 | Finish Face: Interior | Up to level: V2 2e verd. (bk ruwe vloer) | -20 | 3660 | 7614.55 | no
2087783 | F1 begg (bk ruwe vloer) | 430 | 1769.83 | 378743 | 0.16286 | 761026 | 761026 | 0.16286 | no | F3 (ok fundering) | 1110 | Finish Face: Interior | Up to level: V1 ok vloer | -762 | 2778 | 1769.83 | no
2087787 | F1 begg (bk ruwe vloer) | 2778 | 2065.26 | 441966 | 0.340395 | 1590629 | 1590629 | 0.340395 | no | F3 (ok fundering) | 1110 | Finish Face: Interior | Up to level: V1 ok vloer | -762 | 2778 | 2065.26 | no
2087813 | F1 begg (bk ruwe vloer) | 430 | 1769.83 | 378743 | 0.16286 | 761026 | 761026 | 0.16286 | no | F3 (ok fundering) | 1110 | Finish Face: Interior | Up to level: V1 ok vloer | -762 | 2778 | 1769.83 | no
2087904 | F1 begg (bk ruwe vloer) | 2778 | 2067.06 | 442351 | 0.34094 | 1593178 | 1593178 | 0.34094 | no | F3 (ok fundering) | 1110 | Finish Face: Interior | Up to level: V1 ok vloer | -762 | 2778 | 2067.06 | no
2242823 | F1 begg (bk ruwe vloer) | 3560 | 604.582 | 129381 | 0.460595 | 2152312 | 2152312 | 0.460595 | no | F1 begg (bk ruwe vloer) | 0 | Finish Face: Interior | Up to level: V1 ok vloer | 20 | 3560 | 604.582 | no
2243252 | F1 begg (bk ruwe vloer) | 3560 | 787.917 | 168614 | 0.600267 | 2804984 | 2804984 | 0.600267 | no | F1 begg (bk ruwe vloer) | 0 | Finish Face: Interior | Up to level: V1 ok vloer | 20 | 3560 | 787.917 | no

# IfcWallStandardCase: Basic Wall:bt_kzst 300 (8)
Type - PredefinedType: STANDARD; Material: Kalkzandsteen, lijmwerk CS12 300 mm
Type - Other - Category: Walls; Family Name: Basic Wall
Type - Construction - Wrapping at Inserts: Do not wrap; Function: Exterior; Width: 300 mm
Type - Graphics - Coarse Scale Fill Color: 0; Coarse Scale Fill Pattern: Kalkzandsteen
Type - Identity Data - Assembly Code: (28.d); Description: kalkzandsteen d=300 CS12; Type Mark: KZS 300; Type Name: bt_kzst 300
Type - Materials and Finishes - Structural Material: Kalkzandsteen, lijmwerk CS12
Type - Analytical Properties - Roughness: 1; Absorptance: 0.1
Type - Pset_ReinforcementBarPitchOfWall - Description: kalkzandsteen d=300 CS12
Type - Pset_WallCommon - IsExternal: yes
Classification: (28.d) Uniformat (Uniformat)
BaseQuantities - Width: 300 mm
Pset_QuantityTakeOff - Reference: bt_kzst 300; sets with these values: 2
Pset_WallCommon - LoadBearing: yes; ExtendToStructure: no; Reference: bt_kzst 300
Other - Family: Basic Wall; Family and Type: Basic Wall: bt_kzst 300; Type: bt_kzst 300; Type Id: 355912
Constraints - Related to Mass: no; Room Bounding: yes; Base Extension Distance: 0 mm; Base is Attached: no; Base Offset: 0 mm; Top Extension Distance: 0 mm; Location Line: Wall Centerline; Top is Attached: no
Phasing - Phase Created: 2. nieuwbouw
Structural - Rebar Cover - Other Faces: Rebar Cover 1 <25 mm>; Structural: yes; Rebar Cover - Exterior Face: Rebar Cover 1 <25 mm>; Rebar Cover - Interior Face: Rebar Cover 1 <25 mm>; Structural Usage: Bearing
Cross-Section Definition - Cross-Section: Vertical
Name (Basic Wall:bt_kzst 300:...) | In | Height (mm) = Unconnected Height (mm) | BaseQuantities, Length (mm) | GrossFootprintArea (mm2) | GrossVolume (m3) = NetVolume (m3) = Volume (m3) | GrossSideArea (mm2) = NetSideArea (mm2) = Area (mm2) | Base Constraint | Top Constraint | Top Offset (mm) | Dimensions, Length (mm) | Has Association
1550573 | F1 begg (bk ruwe vloer) | 3400 | 5951.13 | 1785339 | 6.01165 | 20038843 | F1 begg (bk ruwe vloer) | Up to level: V1 ok vloer | -140 | 6058.13 | yes
1550701 | F1 begg (bk ruwe vloer) | 3302.5 | 3949.71 | 1184912 | 3.91317 | 13043909 | F1 begg (bk ruwe vloer) |  | 0 | 4056.71 | yes
2050422 | V1 1e verd. (bk ruwe vloer) | 3525 | 7963.86 | 2389159 | 8.42178 | 28072615 | V1 1e verd. (bk ruwe vloer) | Up to level: V2 ok vloer | -15 | 7856.86 | no
2050667 | V1 1e verd. (bk ruwe vloer) | 3525 | 8300.12 | 2490037 | 7.42932 | 24764397 | V1 1e verd. (bk ruwe vloer) | Up to level: V2 ok vloer | -15 | 8300.12 | no
2050701 | V1 1e verd. (bk ruwe vloer) | 3525 | 5747 | 1724100 | 6.07745 | 20258173 | V1 1e verd. (bk ruwe vloer) | Up to level: V2 ok vloer | -15 | 5747 | no
2051411 | V2 2e verd. (bk ruwe vloer) | 3167.95 | 7963.86 | 2389159 | 7.56874 | 25229143 | V2 2e verd. (bk ruwe vloer) | Up to level: V3 dakvloer | -142.047 | 7856.86 | no
2051412 | V2 2e verd. (bk ruwe vloer) | 3167.95 | 8300.12 | 2490037 | 7.88832 | 26294402 | V2 2e verd. (bk ruwe vloer) | Up to level: V3 dakvloer | -142.047 | 8300.12 | no
2051413 | V2 2e verd. (bk ruwe vloer) | 3167.95 | 5747 | 1724100 | 5.46187 | 18206225 | V2 2e verd. (bk ruwe vloer) | Up to level: V3 dakvloer | -142.047 | 5747 | no

# IfcWallStandardCase: Basic Wall:bt_mw 210 (penant) (4)
In: F1 begg (bk ruwe vloer)
Type - PredefinedType: STANDARD; Material: Metselwerk, steen 100 mm, Default Wall 10 mm, Metselwerk, steen 100 mm
Type - Other - Category: Walls; Family Name: Basic Wall
Type - Construction - Wrapping at Inserts: Do not wrap; Function: Exterior; Width: 210 mm; Wrapping at Ends: Exterior
Type - Graphics - Coarse Scale Fill Color: 0; Coarse Scale Fill Pattern: Metselwerk
Type - Identity Data - Assembly Code: (28.d); Description: metselwerk penant d=210; Type Mark: mw penant; Type Name: bt_mw 210 (penant)
Type - Analytical Properties - Roughness: 1; Absorptance: 0.1
Type - Pset_ReinforcementBarPitchOfWall - Description: metselwerk penant d=210
Type - Pset_WallCommon - IsExternal: yes
Classification: (28.d) Uniformat (Uniformat)
BaseQuantities - Width: 210 mm
Pset_QuantityTakeOff - Reference: bt_mw 210 (penant); sets with these values: 2
Pset_WallCommon - LoadBearing: yes; Reference: bt_mw 210 (penant)
Other - Family: Basic Wall; Family and Type: Basic Wall: bt_mw 210 (penant); Type: bt_mw 210 (penant); Type Id: 1966077
Constraints - Related to Mass: no; Room Bounding: yes; Base Extension Distance: 0 mm; Base is Attached: no; Base Offset: 0 mm; Top Constraint: Up to level: V1 ok vloer; Top Extension Distance: 0 mm; Base Constraint: F2 (bk fundering); Location Line: Core Face: Exterior
Identity Data - Has Association: yes
Phasing - Phase Created: 2. nieuwbouw
Structural - Rebar Cover - Other Faces: Rebar Cover 1 <25 mm>; Structural: yes; Rebar Cover - Exterior Face: Rebar Cover 1 <25 mm>; Rebar Cover - Interior Face: Rebar Cover 1 <25 mm>; Structural Usage: Bearing
Cross-Section Definition - Cross-Section: Vertical
Name (Basic Wall:bt_mw 210 (penant):...) | Height (mm) | BaseQuantities, Length (mm) | GrossFootprintArea (mm2) | GrossVolume (m3) | GrossSideArea (mm2) = NetSideArea (mm2) = Area (mm2) | NetVolume (m3) = Volume (m3) | ExtendToStructure = Top is Attached | Top Offset (mm) | Unconnected Height (mm) | Dimensions, Length (mm)
1965977 | 3123.34 | 1425.02 | 299255 | 0.934673 | 4450823 | 0.934689 | yes | 0 | 3950 | 1320.02
1966312 | 2926.34 | 330.015 | 69303.2 | 0.202804 | 965735 | 0.202804 | no | -1023.66 | 2926.34 | 435.015
1966389 | 3123.34 | 1425.02 | 299255 | 0.934673 | 4450823 | 0.934673 | yes | 0 | 3950 | 1320.02
1966391 | 2926.34 | 330.428 | 69389.8 | 0.203058 | 966942 | 0.203058 | no | -1023.66 | 2926.34 | 435.428

# IfcWallStandardCase: Basic Wall:bt_prefab betonwand d=120, Basic Wall:bt_prefab betonwand d=120:1812450
In: KDV V2 werkbalken
Type - PredefinedType: STANDARD; Material: Beton, prefab 120 mm
Type - Other - Category: Walls; Family Name: Basic Wall
Type - Construction - Wrapping at Inserts: Do not wrap; Function: Exterior; Width: 120 mm
Type - Graphics - Coarse Scale Fill Pattern: <Solid fill>; Coarse Scale Fill Color: 3456971
Type - Identity Data - Assembly Code: (28.d); Description: prefab betonwand d=120; Type Name: bt_prefab betonwand d=120
Type - Materials and Finishes - Structural Material: Beton, prefab
Type - Analytical Properties - Roughness: 1; Absorptance: 0.1
Type - Pset_ReinforcementBarPitchOfWall - Description: prefab betonwand d=120
Type - Pset_WallCommon - IsExternal: yes
Classification: (28.d) Uniformat (Uniformat)
BaseQuantities - Height: 2910 mm; Length: 920 mm; Width: 120 mm; GrossFootprintArea: 110400 mm2; GrossVolume: 0.321264 m3; GrossSideArea: 2677200 mm2; NetSideArea: 2677200 mm2; NetVolume: 0.321264 m3
Pset_QuantityTakeOff - Reference: bt_prefab betonwand d=120; sets with these values: 2
Pset_WallCommon - LoadBearing: yes; ExtendToStructure: no; Reference: bt_prefab betonwand d=120
Other - Family: Basic Wall; Family and Type: Basic Wall: bt_prefab betonwand d=120; Type: bt_prefab betonwand d=120; Type Id: 1805567
Constraints - Related to Mass: no; Room Bounding: yes; Base Extension Distance: 0 mm; Base is Attached: no; Top Extension Distance: 0 mm; Top is Attached: no; Base Constraint: V2 ok vloer; Location Line: Core Face: Exterior; Base Offset: -1580 mm; Top Constraint: Up to level: V3 ok vloer; Top Offset: -1780 mm; Unconnected Height: 2910 mm
Dimensions - Area: 2677200 mm2; Length: 920 mm; Volume: 0.321264 m3
Identity Data - Has Association: yes
Phasing - Phase Created: 2. nieuwbouw
Structural - Rebar Cover - Other Faces: Rebar Cover 1 <25 mm>; Structural: yes; Rebar Cover - Exterior Face: Rebar Cover 1 <25 mm>; Rebar Cover - Interior Face: Rebar Cover 1 <25 mm>; Structural Usage: Bearing
Cross-Section Definition - Cross-Section: Vertical

# IfcWallStandardCase: Basic Wall:bt_prefab betonwand d=140 (2)
Type - PredefinedType: STANDARD; Material: Beton, prefab 140 mm
Type - Other - Category: Walls; Family Name: Basic Wall
Type - Construction - Wrapping at Inserts: Do not wrap; Function: Exterior; Width: 140 mm
Type - Graphics - Coarse Scale Fill Pattern: <Solid fill>; Coarse Scale Fill Color: 3456971
Type - Identity Data - Assembly Code: (28.d); Description: prefab betonwand d=140; Type Name: bt_prefab betonwand d=140
Type - Materials and Finishes - Structural Material: Beton, prefab
Type - Analytical Properties - Roughness: 1; Absorptance: 0.1
Type - Pset_ReinforcementBarPitchOfWall - Description: prefab betonwand d=140
Type - Pset_WallCommon - IsExternal: yes
Classification: (28.d) Uniformat (Uniformat)
BaseQuantities - Length: 920 mm; Width: 140 mm; GrossFootprintArea: 128800 mm2
Pset_QuantityTakeOff - Reference: bt_prefab betonwand d=140; sets with these values: 2
Pset_WallCommon - LoadBearing: yes; ExtendToStructure: no; Reference: bt_prefab betonwand d=140
Other - Family: Basic Wall; Family and Type: Basic Wall: bt_prefab betonwand d=140; Type: bt_prefab betonwand d=140; Type Id: 1977336
Constraints - Related to Mass: no; Room Bounding: yes; Base Extension Distance: 0 mm; Base is Attached: no; Top Extension Distance: 0 mm; Top is Attached: no; Location Line: Core Face: Exterior
Dimensions - Length: 920 mm
Identity Data - Has Association: yes
Phasing - Phase Created: 2. nieuwbouw
Structural - Rebar Cover - Other Faces: Rebar Cover 1 <25 mm>; Structural: yes; Rebar Cover - Exterior Face: Rebar Cover 1 <25 mm>; Rebar Cover - Interior Face: Rebar Cover 1 <25 mm>; Structural Usage: Bearing
Cross-Section Definition - Cross-Section: Vertical
Name (Basic Wall:bt_prefab betonwand d=140:...) | In | Height (mm) = Unconnected Height (mm) | GrossVolume (m3) = NetVolume (m3) = Volume (m3) | GrossSideArea (mm2) = NetSideArea (mm2) = Area (mm2) | Base Constraint | Base Offset (mm) | Top Constraint | Top Offset (mm)
1805803 | F1 begg (bk ruwe vloer) | 3870 | 0.498456 | 3560400 | F1 begg (bk ruwe vloer) | 0 | Up to level: V1 1e verd. (bk ruwe vloer) | 70
1806347 | V1 1e verd. (bk ruwe vloer) | 1670 | 0.215096 | 1536400 | V1 1e verd. (bk ruwe vloer) | 90 | Up to level: V2 ok vloer | -1780
